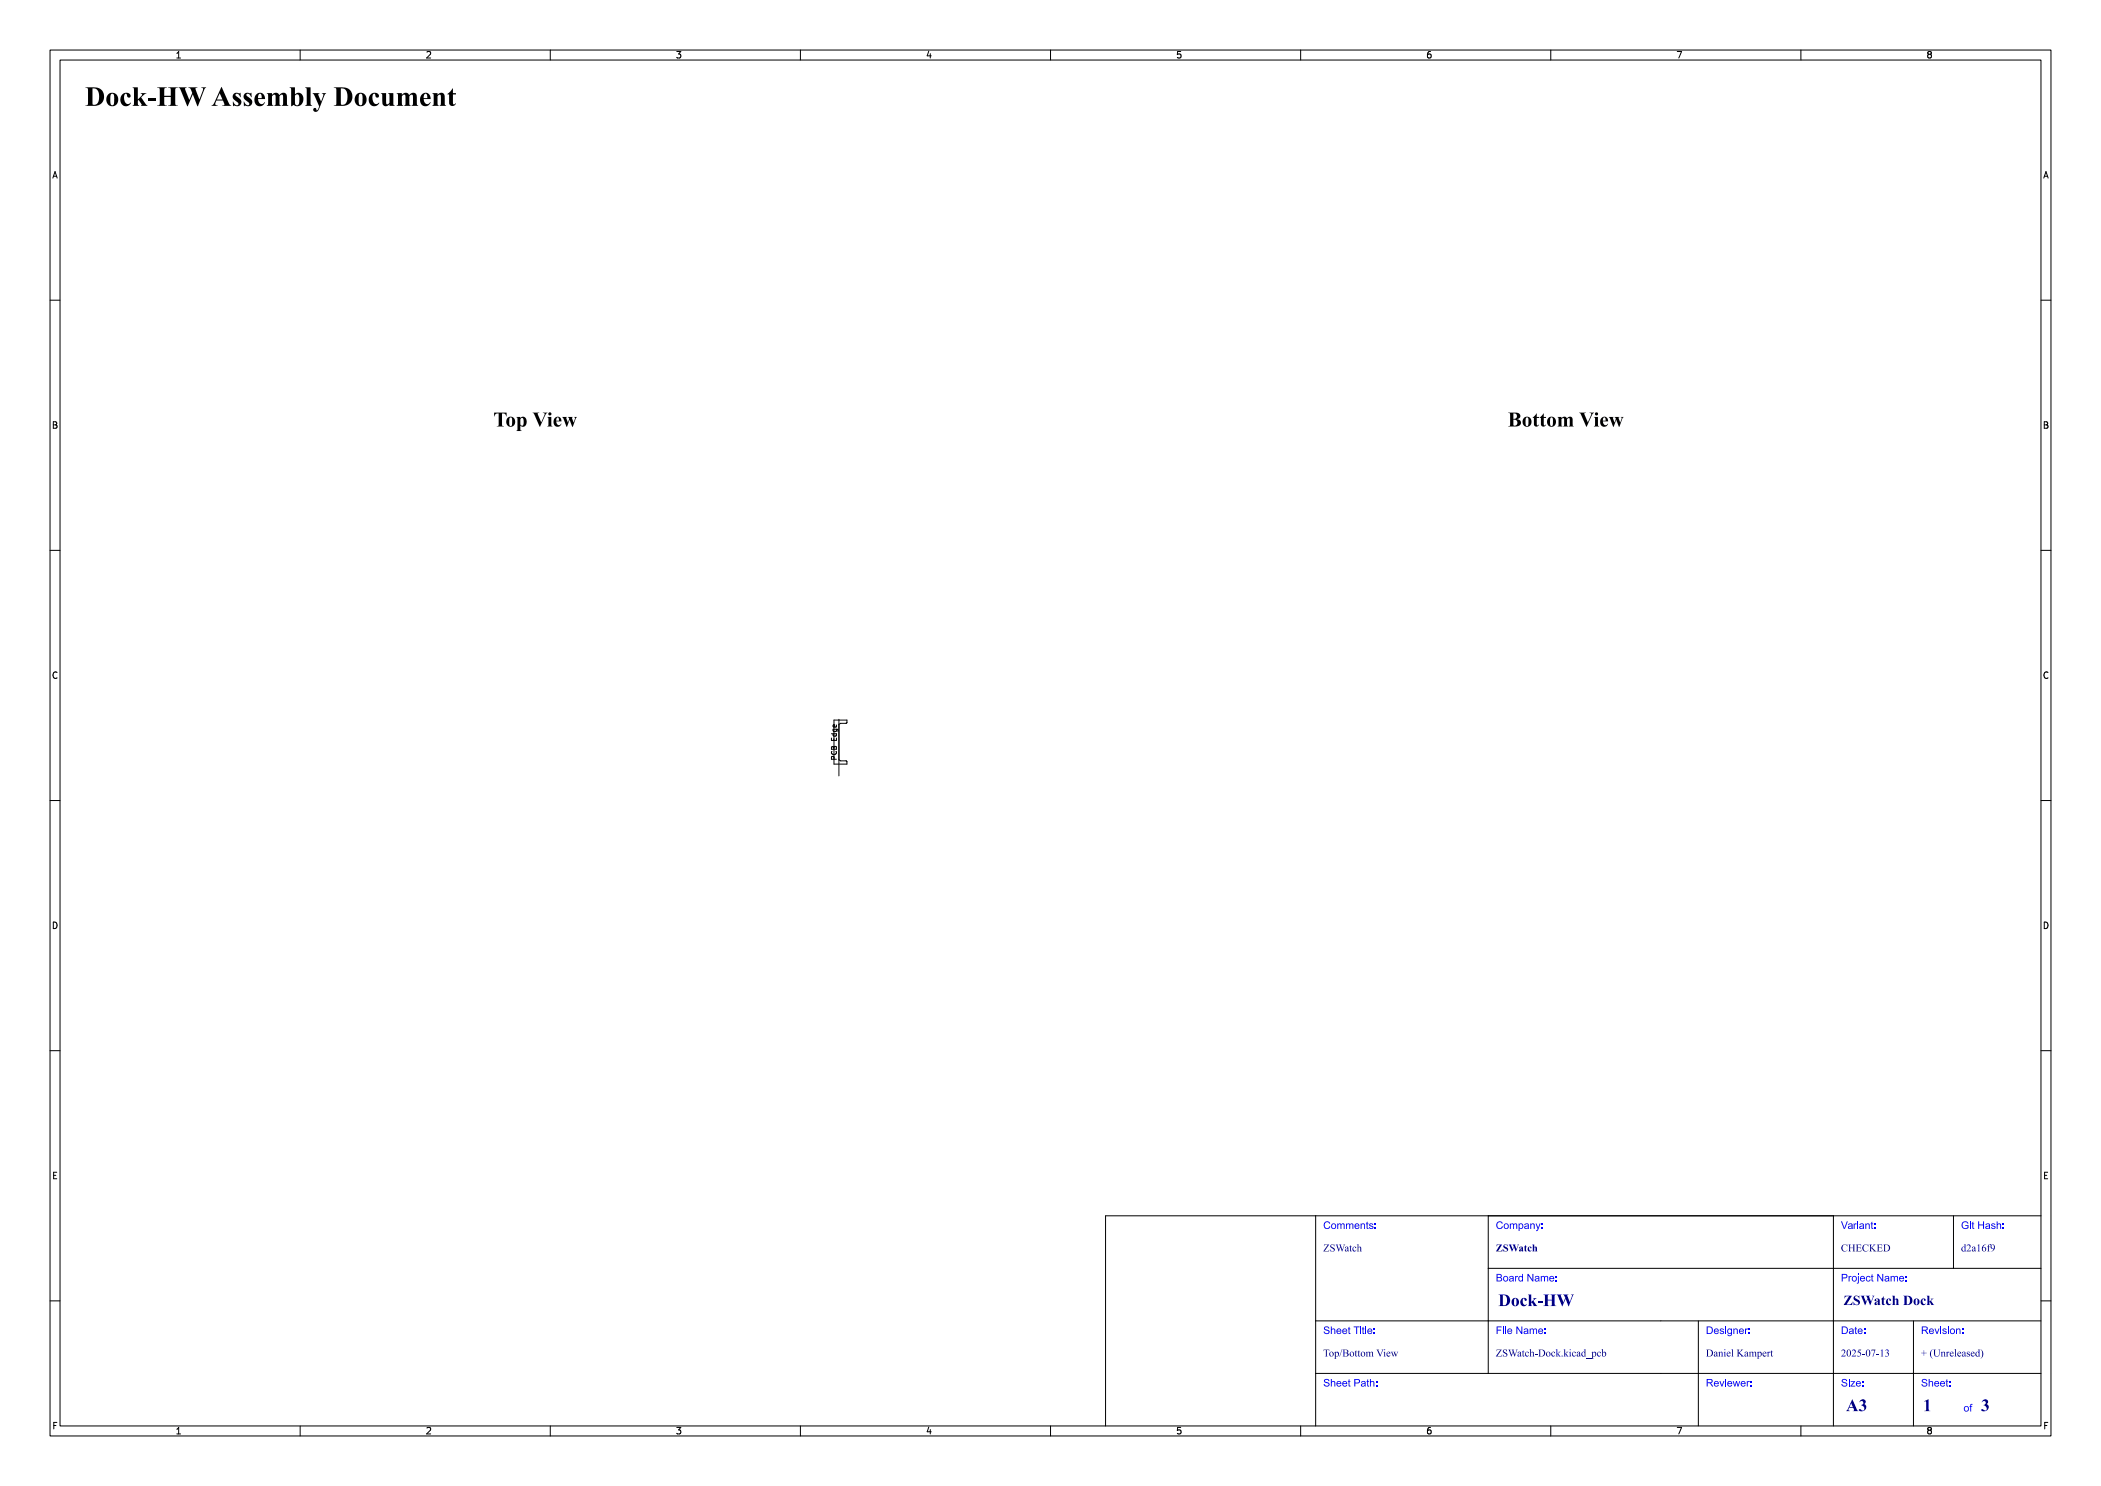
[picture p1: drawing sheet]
<svg xmlns="http://www.w3.org/2000/svg" width="420mm" height="297mm" viewBox="0 0 420 297" stroke-linecap="round" stroke-linejoin="round" font-family="sans-serif">
<defs><g id="words">
<text font-size="5.3" fill="#fff" x="17" y="21.5">Dock-HW Assembly Document</text>
<g font-size="3.3" fill="#fff">
<text x="299.5" y="261.2">Dock-HW</text>
<text x="369" y="282.2">A3</text>
<text x="384.4" y="282.3">1</text>
<text x="396" y="282.3">3</text>
</g>
<text font-size="2.7" fill="#fff" x="368.5" y="261">ZSWatch Dock</text>
<g font-size="2" fill="#fff">
<text x="264.5" y="245.8">Comments:</text>
<text x="299" y="245.8">Company:</text>
<text x="368" y="245.8">Variant:</text>
<text x="392" y="245.8">Git Hash:</text>
<text x="264.5" y="250.2">ZSWatch</text>
<text x="299" y="250.2">ZSWatch</text>
<text x="368" y="250.2">CHECKED</text>
<text x="392" y="250.2">d2a16f9</text>
<text x="299" y="256.2">Board Name:</text>
<text x="368" y="256.2">Project Name:</text>
<text x="264.5" y="266.8">Sheet Title:</text>
<text x="299" y="266.8">File Name:</text>
<text x="341" y="266.8">Designer:</text>
<text x="368" y="266.8">Date:</text>
<text x="384" y="266.8">Revision:</text>
<text x="264.5" y="271.2">Top/Bottom View</text>
<text x="299" y="271.2">ZSWatch-Dock.kicad_pcb</text>
<text x="341" y="271.2">Daniel Kampert</text>
<text x="368" y="271.2">2025-07-13</text>
<text x="384" y="271.2">+ (Unreleased)</text>
<text x="264.5" y="277.3">Sheet Path:</text>
<text x="341" y="277.2">Reviewer:</text>
<text x="368" y="277.3">Size:</text>
<text x="384" y="277.2">Sheet:</text>
<text x="392.5" y="282.3">of</text>
</g>
<g font-size="1.7" fill="#fff">
<text x="35" y="11.6">1</text>
<text x="85" y="11.6">2</text>
<text x="135" y="11.6">3</text>
<text x="185" y="11.6">4</text>
<text x="235" y="11.6">5</text>
<text x="285" y="11.6">6</text>
<text x="335" y="11.6">7</text>
<text x="385" y="11.6">8</text>
<text x="10.5" y="35.6">A</text>
<text x="408.5" y="35.6">A</text>
<text x="10.5" y="85.6">B</text>
<text x="408.5" y="85.6">B</text>
<text x="10.5" y="135.7">C</text>
<text x="408.5" y="135.7">C</text>
<text x="10.5" y="185.6">D</text>
<text x="408.5" y="185.6">D</text>
<text x="10.5" y="235.7">E</text>
<text x="408.5" y="235.7">E</text>
<text x="10.5" y="285.6">F</text>
<text x="35" y="286.7">1</text>
<text x="85" y="286.7">2</text>
<text x="135" y="286.7">3</text>
<text x="185" y="286.7">4</text>
<text x="235" y="286.7">5</text>
<text x="285" y="286.7">6</text>
<text x="335" y="286.7">7</text>
<text x="385" y="286.7">8</text>
<text x="408.5" y="285.6">F</text>
</g>
<text font-size="1.3" fill="#fff" x="167.2" y="151.5" transform="rotate(-90 167.2 151.5)">PCB Edge</text>
</g></defs>
<g fill="#000">
<path d="M98.8 82.5h2.5v.7a.76 .76 0 0 0-.9-.6v2.4l.3 .2h-1.4l.4-.2v-2.4a.75 .75 0 0 0-.9 .6z" fill-rule="evenodd"/>
<path d="M101.6 83.4a.95 .95 0 0 1 1.4 1 .95 .95 0 0 1-1.6 .6l-.2-.5h.6v.4a.26 .26 0 0 0 .3 .3 .26 .26 0 0 0 .2-.3v-1.3a.28 .28 0 0 0-.3-.2 .28 .28 0 0 0-.2 .4v.7h-.6l.1-.6z" fill-rule="evenodd"/>
<path d="M103.2 83.3h.8v.3a.73 .73 0 0 1 .9-.2 .73 .73 0 0 1 .4 .9 .77 .77 0 0 1-.3 .9 .77 .77 0 0 1-1-.1v.9l.3 .1h-1.1l.2-.2v-2.1h.6v1a.31 .31 0 0 0 .3 .3 .31 .31 0 0 0 .3-.2v-1.1a.31 .31 0 0 0-.3-.3 .31 .31 0 0 0-.3 .3h-.6v-.3z" fill-rule="evenodd"/>
<path d="M106.5 82.5h1.3l-.3 .1v.2l.7 1.6 .7-1.6-.4-.3h.9l-.3 .3-1.2 2.5-1.1-2.6z" fill-rule="evenodd"/>
<path d="M109.4 83.3h.8v1.7l.2 .2h-1l.2-.4v-1.3z" fill-rule="evenodd"/>
<path d="M110.9 83.6a.77 .77 0 0 1 .9-.2 .77 .77 0 0 1 .4 .8h-1a.54 .54 0 0 0 .3 .7 .54 .54 0 0 0 .7-.2 .82 .82 0 0 1-1.1 .5 .82 .82 0 0 1-.4-1.1h1l-.1-.6a.37 .37 0 0 0-.4 .1 .37 .37 0 0 0 0 .4h-.5z" fill-rule="evenodd"/>
<path d="M112.4 83.3h.9l-.1 .2 .3 1 .3-.8-.3-.4h1l-.2 .2 .4 1 .3-.9-.2-.3 .5 .1-.2 .2-.6 1.7h-.1l-.5-1.4-.7 1.4z" fill-rule="evenodd"/>
<path d="M301.5 82.5h1.3a.72 .72 0 0 1 .9 .2 .72 .72 0 0 1 0 .9l-.4 .2a.73 .73 0 0 1 .8 .7 .73 .73 0 0 1-.9 .7h-1.7l.3-.1 .1-.2h.6a.51 .51 0 0 0 .8 0 .51 .51 0 0 0-.1-.7l-.2-.3h-.5v1h-.6v-1.2h.6a.57 .57 0 0 0 .7-.5 .57 .57 0 0 0-.7-.6v1.1h-.6l-.1-1z" fill-rule="evenodd"/>
<path d="M304.7 83.4a.95 .95 0 0 1 1.4 1 .95 .95 0 0 1-1.5 .6l-.2-.5h.6v.4a.26 .26 0 0 0 .2 .3 .26 .26 0 0 0 .3-.3v-1.3a.28 .28 0 0 0-.3-.2 .28 .28 0 0 0-.2 .4v.7h-.6v-.6z" fill-rule="evenodd"/>
<path d="M307.1 82.6l.1 .7h.5v.2h-.5v1.4l.1 .1 .3-.2a.51 .51 0 0 1-.6 .4 .51 .51 0 0 1-.4-.6v-1.1h-.2z" fill-rule="evenodd"/>
<path d="M308.5 82.6l.1 .7h.5v.2h-.5v1.4l.1 .1 .3-.2a.51 .51 0 0 1-.6 .4 .51 .51 0 0 1-.4-.6v-1.1h-.2z" fill-rule="evenodd"/>
<path d="M309.6 83.4a.95 .95 0 0 1 1.4 1 .95 .95 0 0 1-1.5 .6l-.2-.5h.5l.1 .4a.26 .26 0 0 0 .2 .3 .26 .26 0 0 0 .3-.3v-1.3a.28 .28 0 0 0-.4-.2 .28 .28 0 0 0-.1 .4l-.1 .7h-.5v-.6z" fill-rule="evenodd"/>
<path d="M311.3 83.3h.8v.3a.6 .6 0 0 1 .6-.3 .6 .6 0 0 1 .5 .3 .61 .61 0 0 1 .8-.3 .61 .61 0 0 1 .4 .7v1l.2 .2h-1l.2-.2v-1.2a.27 .27 0 0 0-.3-.3 .27 .27 0 0 0-.2 .3v1.2l.2 .2h-1l.2-.2v-1.2a.22 .22 0 0 0-.2-.2 .22 .22 0 0 0-.3 .1l-.1 1.1 .2 .4h-1l.3-.4-.1-1.3z" fill-rule="evenodd"/>
<path d="M315.7 82.5h1.3l-.3 .1v.2l.7 1.6 .7-1.5v-.3l-.4-.1h1l-.4 .3-1.1 2.5-1.2-2.6z" fill-rule="evenodd"/>
<path d="M318.6 83.3h.8v1.7l.3 .2h-1.1l.3-.4-.1-1.3z" fill-rule="evenodd"/>
<path d="M320.1 83.6a.77 .77 0 0 1 1-.2 .77 .77 0 0 1 .4 .8h-1.1a.54 .54 0 0 0 .3 .7 .54 .54 0 0 0 .7-.2 .82 .82 0 0 1-1.1 .5 .82 .82 0 0 1-.4-1.1h1.1l-.2-.6a.37 .37 0 0 0-.4 .1 .37 .37 0 0 0 0 .4h-.5z" fill-rule="evenodd"/>
<path d="M321.6 83.3h1l-.2 .2 .3 1 .3-.8-.3-.4h1l-.2 .2 .4 1 .3-.9-.2-.3 .6 .1-.2 .2-.7 1.7h-.1l-.5-1.4-.6 1.4z" fill-rule="evenodd"/>
<circle cx="109.9" cy="82.7" r=".32"/>
<circle cx="319.1" cy="82.7" r=".32"/>
</g>
<g fill="none" stroke="#000" stroke-width=".2">
<path d="M10 10h400v277h-400zM12 12h396v273h-396zM35.3 11.6h.8M35.3 10.7l.4-.4v1.3M60 10v2M85.3 10.4l.5-.1 .3 .4-.8 .9h.8M110 10v2M135.3 10.3h.8l-.4 .5 .3 .1v.6l-.2 .1-.5-.1M160 10v2M185.7 10.2l-.4 1h.9M186 10.7v.9M210 10v2"/>
<path d="M236 10.3h-.6l-.1 .6 .2-.1 .5 .1 .1 .1-.1 .5-.2 .1-.5-.1M260 10v2M286 10.3l-.4 .1-.2 .2-.1 .7 .3 .3 .4-.1 .1-.5-.1-.1-.4-.1-.3 .2M310 10v2M335.3 10.3h.9l-.6 1.3M360 10v2M385.6 10.9l-.3 .2 .1 .4 .2 .1 .4-.1 .1-.2-.1-.3-.2-.1M385.6 10.9l-.3-.3 .3-.3h.2l.3 .2-.3 .4M385.6 10.9h.2M10.6 35.6l.4-1.3 .4 1.3M10.7 35.2h.6M408.6 35.6l.4-1.3 .4 1.3"/>
<path d="M408.7 35.2h.6M10 60h2M408 60h2M10.7 84.3h.4l.2 .2-.2 .4 .2 .1 .1 .3-.2 .3h-.5zM10.7 84.9h.4M408.6 84.3h.5l.2 .2-.2 .4 .2 .1 .1 .3-.3 .3h-.5zM408.6 84.9h.5M10 110h2M408 110h2M11.4 134.4a.62 .62 0 0 0-.9 .5 .62 .62 0 0 0 .7 .7l.2-.1M409.4 134.4a.62 .62 0 0 0-.9 .5 .62 .62 0 0 0 .6 .7l.3-.1M10 160h2"/>
<path d="M166.2 147.5v.5h1v-.5M166.2 146.7h1M166.3 149.3l.2-.1 .2 .2 .2-.2h.2l.1 .5h-1zM166.3 150.2a.44 .44 0 0 0 .4 .6 .44 .44 0 0 0 .4-.6M166.5 145.7h.8l.2 .2v.3M166.6 145.7l-.1 .3 .2 .2 .5-.1v-.4M166.6 146.7l-.1 .2 .2 .2 .5-.1v-.3M166.7 147.7v.3M166.7 149.4v.3M166.7 151.4l-.2-.2h-.2l-.1 .5h1M167.2 144.9v.3l-.1 .1h-.5v-.4l.2-.1 .1 .5M167.7 144.8l.3-.2h1.2l.1-.7h-2.6v8.8h2.6l-.1-.6h-1.2l-.3-.2"/>
<path d="M167.7 143.8v11.3M408 160h2M10.7 184.3a.66 .66 0 0 1 .7 .6 .66 .66 0 0 1-.7 .7zM408.6 184.3a.66 .66 0 0 1 .8 .6 .66 .66 0 0 1-.8 .7zM10 210h2M408 210h2M10.7 234.9h.5M11.3 234.3h-.6v1.3h.6M408.7 234.9h.4M409.3 234.3h-.6v1.3h.6M10 260h2M408 260h2"/>
<path d="M10.8 284.9h.4M11.4 284.3h-.6v1.3M35.3 285.7l.4-.4v1.3M35.3 286.6h.8M60 285v2M85.3 285.4l.5-.1 .3 .4-.8 .9h.8M110 285v2M135.3 285.3h.8l-.4 .5 .3 .1v.6l-.2 .1-.5-.1M160 285v2M185.7 285.2l-.4 1h.9M186 285.7v.9M210 285v2"/>
<path d="M236 285.3h-.6l-.1 .6 .2-.1 .5 .1 .1 .1-.1 .5-.2 .1-.5-.1M260 285v2M286 285.3l-.4 .1-.2 .2-.1 .7 .3 .3 .4-.1 .1-.5-.1-.1-.4-.1-.3 .2M310 285v2M335.3 285.3h.9l-.6 1.3M360 285v2M385.6 285.9l-.3-.3 .3-.3h.2l.3 .2-.3 .4M385.6 285.9l-.3 .2v.2l.3 .3 .4-.1 .1-.2v-.2l-.3-.2M385.6 285.9h.2M408.7 284.9h.5M409.4 284.3h-.7v1.3"/>
</g>
<path d="M384.6 280.1l.9-.4v2.1l.4 .2h-1.2l.3-.1v-1.5v-.3z" fill-rule="evenodd" fill="#00007f"/>
<g fill="#00f">
<path d="M384.3 275.7l.7-.1 .2 .4-.1 .1a.32 .32 0 0 0-.4-.4 .32 .32 0 0 0-.3 .5h.3a.5 .5 0 0 1 .6 .6 .5 .5 0 0 1-.8 .3l-.4-.3v-.2h.2a.39 .39 0 0 0 .4 .4 .39 .39 0 0 0 .4-.4l-.9-.4v-.2z" fill-rule="evenodd"/>
<path d="M385.5 275.6h.2v.6l.3-.2 .4 .2v.9h-.2v-.7a.27 .27 0 0 0-.3-.2 .27 .27 0 0 0-.2 .3v.6h-.2z" fill-rule="evenodd"/>
<path d="M386.8 276.2a.51 .51 0 0 1 .6-.1 .51 .51 0 0 1 .2 .5h-.8l.3 .4 .5-.2a.52 .52 0 0 1-.6 .3 .52 .52 0 0 1-.3-.6h.8l-.3-.3-.4 .3h-.1z" fill-rule="evenodd"/>
<path d="M388 276.2a.51 .51 0 0 1 .6-.1 .51 .51 0 0 1 .2 .5h-.8l.2 .4 .6-.2a.52 .52 0 0 1-.6 .3 .52 .52 0 0 1-.4-.6h.8l-.3-.3-.3 .3h-.2z" fill-rule="evenodd"/>
<path d="M389.1 275.8l.2-.1v.3h.1v.2h-.1v.6l.2 .3a.27 .27 0 0 1-.3 0 .27 .27 0 0 1-.1-.3v-.6h-.2z" fill-rule="evenodd"/>
<path d="M389.7 276h.2v.2h-.2z" fill-rule="evenodd"/>
<path d="M389.7 276.9h.2v.2h-.2z" fill-rule="evenodd"/>
<path d="M392.7 281.1a.54 .54 0 0 1 .9 .1 .54 .54 0 0 1-.3 .8 .54 .54 0 0 1-.7-.4h.2a.37 .37 0 0 0 .5 .4 .37 .37 0 0 0 0-.7l-.3-.1-.2 .4h-.2z" fill-rule="evenodd"/>
<path d="M393.9 280.7l.4-.1v.2l-.3 .1 .2 .3h-.2v.9h-.2v-.9h-.1z" fill-rule="evenodd"/>
</g>
<path d="M396.3 279.9a.55 .55 0 0 1 .9-.2 .55 .55 0 0 1-.1 .9 .81 .81 0 0 1 .2 1.2 .81 .81 0 0 1-1.3 0l.3-.2a.54 .54 0 0 0 .8 .2 .71 .71 0 0 0-.6-1 .41 .41 0 0 0 .5-.3 .41 .41 0 0 0-.3-.5 .41 .41 0 0 0-.5 .3z" fill-rule="evenodd" fill="#00007f"/>
<g fill="#00f">
<path d="M368.3 275.7l.7-.1 .2 .4-.1 .1a.32 .32 0 0 0-.4-.4 .32 .32 0 0 0-.3 .5h.3a.5 .5 0 0 1 .6 .6 .5 .5 0 0 1-.8 .3l-.4-.3v-.2h.2a.39 .39 0 0 0 .4 .4 .39 .39 0 0 0 .4-.4l-.9-.4v-.2z" fill-rule="evenodd"/>
<path d="M369.5 275.6h.2v.2h-.2z" fill-rule="evenodd"/>
<path d="M369.5 276h.2v1.1h-.2z" fill-rule="evenodd"/>
<path d="M369.9 276h.9l-.7 1h.8v.1h-1l.7-.9h-.7z" fill-rule="evenodd"/>
<path d="M371.1 276.2a.51 .51 0 0 1 .6-.1 .51 .51 0 0 1 .3 .5h-.8l.2 .4 .6-.2a.52 .52 0 0 1-.7 .3 .52 .52 0 0 1-.3-.6h.8l-.3-.3-.3 .3h-.2z" fill-rule="evenodd"/>
<path d="M372.3 276h.2v.2h-.2z" fill-rule="evenodd"/>
<path d="M372.3 276.9h.2v.2h-.2z" fill-rule="evenodd"/>
</g>
<g fill="#00007f">
<path d="M370.3 279.7l.9 2.1 .3 .2h-1.1l.2-.1-.1-.5h-.9l-.1 .5 .3 .1h-.8l.6-.8h.8l-.3-.7-.4 .7h-.1z" fill-rule="evenodd"/>
<path d="M371.9 279.9a.55 .55 0 0 1 .8-.2 .55 .55 0 0 1 0 .9 .81 .81 0 0 1 .1 1.2 .81 .81 0 0 1-1.2 0l.2-.2a.54 .54 0 0 0 .8 .2 .72 .72 0 0 0-.6-1 .41 .41 0 0 0 .5-.3 .41 .41 0 0 0-.3-.5 .41 .41 0 0 0-.5 .3z" fill-rule="evenodd"/>
</g>
<path d="M366.5 274.5h41.5M382.5 274.5v10.5M408 264h-41.5v21" fill="none" stroke="#000" stroke-width=".2"/>
<g fill="#00f">
<path d="M384.2 265.1h.6a.42 .42 0 0 1 .6 .4 .42 .42 0 0 1-.5 .4l.6 .7h-.3l-.4-.6h-.2h-.2v.6h-.2v-.8l.9-.1a.25 .25 0 0 0 0-.3 .25 .25 0 0 0-.3-.1h-.4v.5h-.2z" fill-rule="evenodd"/>
<path d="M385.7 265.7l.1-.1a.51 .51 0 0 1 .6 0 .51 .51 0 0 1 .2 .5h-.8l.2 .4 .6-.2a.52 .52 0 0 1-.7 .3 .52 .52 0 0 1-.3-.6h.8l-.3-.3-.3 .3h-.2z" fill-rule="evenodd"/>
<path d="M386.7 265.5h.2l.3 .9 .3-.9h.2l-.4 1.1h-.2z" fill-rule="evenodd"/>
<path d="M387.9 265.1h.2v.2h-.2z" fill-rule="evenodd"/>
<path d="M387.9 265.5h.2v1.1h-.2z" fill-rule="evenodd"/>
<path d="M388.4 265.6l.5-.1 .2 .3h-.2a.21 .21 0 0 0-.2-.2 .21 .21 0 0 0-.1 .3 .43 .43 0 0 1 .4 .1 .43 .43 0 0 1 .1 .4l-.2 .2h-.4l-.2-.3h.1a.24 .24 0 0 0 .3 .3 .24 .24 0 0 0 .2-.4 .43 .43 0 0 1-.6-.5z" fill-rule="evenodd"/>
<path d="M389.4 265.1h.2v.2h-.2z" fill-rule="evenodd"/>
<path d="M389.4 265.5h.2v1.1h-.2z" fill-rule="evenodd"/>
<path d="M390 265.6a.54 .54 0 0 1 .8 .1 .54 .54 0 0 1-.3 .8 .54 .54 0 0 1-.7-.4h.2a.37 .37 0 0 0 .5 .4 .37 .37 0 0 0 .1-.7l-.4-.1-.2 .4h-.2z" fill-rule="evenodd"/>
<path d="M391 265.5h.2v.2l.3-.2a.35 .35 0 0 1 .4 .5v.6h-.2v-.6a.27 .27 0 0 0-.3-.3 .27 .27 0 0 0-.2 .3v.6h-.2z" fill-rule="evenodd"/>
<path d="M392.2 265.5h.2v.2h-.2z" fill-rule="evenodd"/>
<path d="M392.2 266.4h.2v.2h-.2z" fill-rule="evenodd"/>
</g>
<g fill="#00007f">
<path d="M384 270.4h.5l.1-.5v.5l.5 .1h-.5l-.1 .5v-.5z" fill-rule="evenodd"/>
<path d="M386.1 269.8l.3-.1a1.42 1.42 0 0 0 0 1.9l-.5-.6a1.13 1.13 0 0 1 .2-1.2z" fill-rule="evenodd"/>
<path d="M386.4 269.7h.6l-.2 .2v.7a.41 .41 0 0 0 .4 .5 .41 .41 0 0 0 .4-.6v-.7l-.2-.1h.5l-.2 .2v.6a.55 .55 0 0 1-.6 .7 .55 .55 0 0 1-.5-.7v-.7z" fill-rule="evenodd"/>
<path d="M387.9 270.3l.4-.1v.2a.29 .29 0 0 1 .3-.2 .29 .29 0 0 1 .2 .3v.5l.2 .1h-.5l.2-.2-.1-.5-.1-.1-.2 .1v.6l.1 .1h-.4l.1-.1v-.6z" fill-rule="evenodd"/>
<path d="M389 270.3l.3-.1v.2l.2-.2h.2l-.4 .3v.5l.2 .1h-.5l.1-.1v-.6z" fill-rule="evenodd"/>
<path d="M389.9 270.3l.4-.1 .2 .2v.1h-.6l.2 .4 .3 .1 .1-.2a.41 .41 0 0 1-.6 .3 .41 .41 0 0 1-.1-.6h.5l-.2-.3-.3 .3z" fill-rule="evenodd"/>
<path d="M390.7 269.8l.3-.1v1.3l.1 .1h-.4l.1-.1v-.9v-.3z" fill-rule="evenodd"/>
<path d="M391.4 270.3l.4-.1 .2 .2 .1 .1h-.7l.2 .4 .3 .1 .1-.2a.41 .41 0 0 1-.5 .3 .41 .41 0 0 1-.2-.6h.5l-.2-.3-.3 .3z" fill-rule="evenodd"/>
<path d="M392.3 270.2l.5 .1 .1 .7 .1-.1-.1 .2-.2-.1-.2 .1h-.2l-.1-.2 .3 .1 .2-.1v-.3l-.5 .3 .5-.4-.2-.3-.2 .3z" fill-rule="evenodd"/>
<path d="M393.2 270.2h.5v.3l-.2-.3-.2 .1 .1 .2a.34 .34 0 0 1 .4 .5 .34 .34 0 0 1-.6 .1v-.3l.2 .3 .2-.2-.4-.4z" fill-rule="evenodd"/>
<path d="M394.1 270.3l.4-.1 .2 .2v.1h-.6l.1 .4 .3 .1 .2-.2a.41 .41 0 0 1-.6 .3 .41 .41 0 0 1-.1-.6h.5l-.2-.3-.3 .3z" fill-rule="evenodd"/>
<path d="M395.4 269.8l.3-.1v1.3h.2l-.6 .2-.4-.2v-.4h.2l.1 .4 .3-.1-.1-.7-.3 .1v.3h-.2v-.1a.41 .41 0 0 1 .6-.3v-.4z" fill-rule="evenodd"/>
<path d="M395.9 269.7a1.08 1.08 0 0 1 0 1.9 1.42 1.42 0 0 0 0-1.9z" fill-rule="evenodd"/>
</g>
<path d="M382.5 264v10.5" fill="none" stroke="#000" stroke-width=".2"/>
<g fill="#00f">
<path d="M368.2 265.1h.5a.75 .75 0 0 1 .7 .8 .75 .75 0 0 1-.7 .7h-.5v-.2h.5a.58 .58 0 0 0 .5-.5 .58 .58 0 0 0-.5-.6h-.3v1.1h-.2z" fill-rule="evenodd"/>
<path d="M369.7 265.6l.2-.1a.47 .47 0 0 1 .5 .1 .47 .47 0 0 1 .1 .6l.1 .4-.2-.1-.5 .1-.3-.1v-.2l.6 .2 .1-.4-.7 .2a.57 .57 0 0 1 .7-.4l-.1-.2-.6 .1z" fill-rule="evenodd"/>
<path d="M370.9 265.3l.1-.1v.3h.2v.2h-.2v.6l.2 .3a.27 .27 0 0 1-.3 0 .27 .27 0 0 1 0-.3v-.6h-.2z" fill-rule="evenodd"/>
<path d="M371.5 265.7l.1-.1a.51 .51 0 0 1 .5 0 .51 .51 0 0 1 .2 .5h-.8l.3 .4 .5-.2a.52 .52 0 0 1-.6 .3 .52 .52 0 0 1-.4-.6h.9l-.3-.3-.4 .3h-.2z" fill-rule="evenodd"/>
<path d="M372.6 265.5h.2v.2h-.2z" fill-rule="evenodd"/>
<path d="M372.6 266.4h.2v.2h-.2z" fill-rule="evenodd"/>
</g>
<path d="M408 253.5h-41.5v10.5" fill="none" stroke="#000" stroke-width=".2"/>
<g fill="#00f">
<path d="M368.2 254.6h.5a.46 .46 0 0 1 .6 .5 .46 .46 0 0 1-.6 .4h-.3v.6h-.2v-.8h.7l.2-.2-.2-.3h-.5v.5h-.2z" fill-rule="evenodd"/>
<path d="M369.5 255h.2v.2l.4-.2v.2a.24 .24 0 0 0-.3 .1 .24 .24 0 0 0-.1 .3v.5h-.2z" fill-rule="evenodd"/>
<path d="M370.3 255.1a.55 .55 0 0 1 .9 .1 .55 .55 0 0 1-.3 .8 .55 .55 0 0 1-.7-.4h.2a.37 .37 0 0 0 .5 .4 .37 .37 0 0 0 0-.7l-.3-.1-.2 .4h-.2z" fill-rule="evenodd"/>
<path d="M371.4 254.6h.2v.2h-.2z" fill-rule="evenodd"/>
<path d="M371.4 255h.2v1.2a.3 .3 0 0 1-.1 .3 .3 .3 0 0 1-.3 0l.2-.2z" fill-rule="evenodd"/>
<path d="M371.9 255.2a.51 .51 0 0 1 .7-.1 .51 .51 0 0 1 .2 .5h-.8l.2 .4 .6-.2a.52 .52 0 0 1-.6 .3 .52 .52 0 0 1-.4-.6h.8l-.3-.3-.3 .3h-.2z" fill-rule="evenodd"/>
<path d="M373.1 255.1h.6l.2 .3h-.2a.34 .34 0 0 0-.5-.2 .34 .34 0 0 0 0 .6l.3 .2 .2-.3h.2a.53 .53 0 0 1-.8 .3 .53 .53 0 0 1 0-.8z" fill-rule="evenodd"/>
<path d="M374.1 254.8l.2-.1v.3h.2v.2h-.2v.6l.2 .3a.27 .27 0 0 1-.3 0 .27 .27 0 0 1-.1-.3v-.6h-.1z" fill-rule="evenodd"/>
<path d="M375.3 254.6h.2l.8 1.2v-1.2h.2v1.5h-.2l-.8-1.2v1.2h-.2z" fill-rule="evenodd"/>
<path d="M376.9 255.1l.1-.1a.47 .47 0 0 1 .6 .1 .47 .47 0 0 1 0 .6l.1 .4-.2-.1-.5 .1-.3-.1v-.2l.6 .2 .2-.4-.8 .2a.57 .57 0 0 1 .8-.4l-.2-.2-.6 .1z" fill-rule="evenodd"/>
<path d="M377.9 255h.2v.2l.3-.2 .3 .2 .3-.2 .3 .1 .1 1h-.2l-.1-.9a.26 .26 0 0 0-.2 0 .26 .26 0 0 0-.1 .3v.6h-.2v-.8l-.4-.1-.1 .9h-.2z" fill-rule="evenodd"/>
<path d="M379.8 255.2a.51 .51 0 0 1 .6-.1 .51 .51 0 0 1 .2 .5h-.8l.3 .4 .5-.2a.52 .52 0 0 1-.6 .3 .52 .52 0 0 1-.4-.6h.8l-.3-.3-.3 .3h-.2z" fill-rule="evenodd"/>
<path d="M380.9 255h.2v.2h-.2z" fill-rule="evenodd"/>
<path d="M380.9 255.9h.2v.2h-.2z" fill-rule="evenodd"/>
</g>
<g fill="#00007f">
<path d="M368.2 269.8a.42 .42 0 0 1 .6 .1 .42 .42 0 0 1-.1 .6l-.4 .5 .7-.1-.1 .2h-.9a.88 .88 0 0 0 .6-1.2h-.2l-.3 .2z" fill-rule="evenodd"/>
<path d="M369.3 269.8l.2-.1a.7 .7 0 0 1 .5 .7 .7 .7 0 0 1-.6 .7l-.3-.5 .2-.1a.36 .36 0 0 0 0 .4 .36 .36 0 0 0 .4 .1l.1-.8-.2-.4a.42 .42 0 0 0-.3 .7l-.2-.1z" fill-rule="evenodd"/>
<path d="M370.3 269.8a.42 .42 0 0 1 .6 .1 .42 .42 0 0 1-.1 .6l-.4 .5 .7-.1-.1 .2h-.9a.88 .88 0 0 0 .6-1.2h-.2l-.3 .2z" fill-rule="evenodd"/>
<path d="M371.6 269.7h.5l-.1 .2h-.4l-.1 .2a.5 .5 0 0 1 .5 .6 .5 .5 0 0 1-.7 .3 .4 .4 0 0 0 .6-.2 .4 .4 0 0 0-.5-.5h-.1z" fill-rule="evenodd"/>
<path d="M372.3 270.6h.5v.1h-.5z" fill-rule="evenodd"/>
<path d="M373.2 269.8l.1-.1a.7 .7 0 0 1 .6 .7 .7 .7 0 0 1-.6 .7l-.3-.5 .2-.1a.36 .36 0 0 0-.1 .4 .36 .36 0 0 0 .4 .1l.2-.6-.2-.6a.42 .42 0 0 0-.3 .7l-.2-.1z" fill-rule="evenodd"/>
<path d="M374.2 269.7h.7l-.5 1.4h-.1l.4-1.2h-.5l-.1 .2z" fill-rule="evenodd"/>
<path d="M375.1 270.6h.5v.1h-.5z" fill-rule="evenodd"/>
<path d="M375.9 269.9l.4-.2v1.3l.2 .1h-.5l.1-.1v-1z" fill-rule="evenodd"/>
<path d="M377 269.8h.4a.31 .31 0 0 1 0 .5 .44 .44 0 0 1 .1 .7 .44 .44 0 0 1-.6 0 .35 .35 0 0 0 .5-.1 .35 .35 0 0 0-.3-.5 .28 .28 0 0 0 .3-.2 .28 .28 0 0 0-.2-.3 .28 .28 0 0 0-.3 .1z" fill-rule="evenodd"/>
</g>
<g fill="#00f">
<path d="M341.2 275.6h.6a.42 .42 0 0 1 .6 .4 .42 .42 0 0 1-.5 .4l.6 .7h-.3a.74 .74 0 0 0-.8-.6v.6h-.2v-.8l.9-.1a.25 .25 0 0 0 0-.3 .25 .25 0 0 0-.3-.1h-.4v.5h-.2z" fill-rule="evenodd"/>
<path d="M342.7 276.2a.51 .51 0 0 1 .6-.1 .51 .51 0 0 1 .3 .5h-.8l.2 .4 .6-.2a.52 .52 0 0 1-.7 .3 .52 .52 0 0 1-.3-.6h.8l-.3-.3-.3 .3h-.2z" fill-rule="evenodd"/>
<path d="M343.7 276h.2l.3 .9 .3-.9h.2l-.4 1.1h-.2z" fill-rule="evenodd"/>
<path d="M344.9 275.6h.2v.2h-.2z" fill-rule="evenodd"/>
<path d="M344.9 276h.2v1.1h-.2z" fill-rule="evenodd"/>
<path d="M345.4 276.2a.51 .51 0 0 1 .6-.1 .51 .51 0 0 1 .3 .5h-.8l.2 .4 .6-.2a.52 .52 0 0 1-.7 .3 .52 .52 0 0 1-.3-.6h.8l-.3-.3-.3 .3h-.2z" fill-rule="evenodd"/>
<path d="M346.4 276h.2l.2 .9 .2-.9h.2l.2 .9 .3-.9h.2l-.4 1.1h-.2l-.2-.8-.2 .8h-.2z" fill-rule="evenodd"/>
<path d="M348.1 276.2a.51 .51 0 0 1 .6-.1 .51 .51 0 0 1 .3 .5h-.9l.3 .4 .6-.2a.52 .52 0 0 1-.7 .3 .52 .52 0 0 1-.3-.6h.8l-.3-.3-.3 .3h-.2z" fill-rule="evenodd"/>
<path d="M349.2 276h.1v.2l.4-.2v.2a.24 .24 0 0 0-.3 .1 .24 .24 0 0 0 0 .3v.5h-.2z" fill-rule="evenodd"/>
<path d="M349.9 276h.2v.2h-.2z" fill-rule="evenodd"/>
<path d="M349.9 276.9h.2v.2h-.2z" fill-rule="evenodd"/>
</g>
<path d="M332 274.5h34.5M339.5 274.5v10.5" fill="none" stroke="#000" stroke-width=".2"/>
<g fill="#00f">
<path d="M341.2 265.1h.5a.75 .75 0 0 1 .7 .8 .75 .75 0 0 1-.7 .7h-.5v-.2h.5a.58 .58 0 0 0 .5-.5 .58 .58 0 0 0-.5-.6h-.3v1.1h-.2z" fill-rule="evenodd"/>
<path d="M342.7 265.7l.1-.1a.51 .51 0 0 1 .6 0 .51 .51 0 0 1 .2 .5h-.8l.2 .4 .6-.2a.52 .52 0 0 1-.7 .3 .52 .52 0 0 1-.3-.6h.8l-.3-.3-.3 .3h-.2z" fill-rule="evenodd"/>
<path d="M343.8 265.6l.6-.1 .2 .3h-.2a.21 .21 0 0 0-.2-.2 .21 .21 0 0 0-.2 .3 .43 .43 0 0 1 .5 .1 .43 .43 0 0 1 .1 .4l-.2 .2h-.4l-.3-.3h.2a.24 .24 0 0 0 .3 .3 .24 .24 0 0 0 .2-.4 .43 .43 0 0 1-.6-.5z" fill-rule="evenodd"/>
<path d="M344.9 265.1h.2v.2h-.2z" fill-rule="evenodd"/>
<path d="M344.9 265.5h.2v1.1h-.2z" fill-rule="evenodd"/>
<path d="M345.4 265.6l.3-.1 .4 .2v-.2h.1v1a.48 .48 0 0 1-.3 .5 .48 .48 0 0 1-.6-.3l.5 .2 .2-.1v-.3a.47 .47 0 0 1-.5 0 .47 .47 0 0 1-.2-.4h.2a.34 .34 0 0 0 .4 .3 .34 .34 0 0 0 .1-.5 .3 .3 0 0 0-.3-.2 .3 .3 0 0 0-.2 .4h-.2z" fill-rule="evenodd"/>
<path d="M346.5 265.5h.2v.2l.3-.2a.35 .35 0 0 1 .4 .5v.6h-.2v-.6a.27 .27 0 0 0-.3-.3 .27 .27 0 0 0-.2 .3v.6h-.2z" fill-rule="evenodd"/>
<path d="M347.7 265.7l.1-.1a.51 .51 0 0 1 .6 0 .51 .51 0 0 1 .2 .5h-.8l.2 .4 .6-.2a.52 .52 0 0 1-.6 .3 .52 .52 0 0 1-.4-.6h.8l-.3-.3-.3 .3h-.2z" fill-rule="evenodd"/>
<path d="M348.8 265.5h.2v.2l.4-.2v.2a.24 .24 0 0 0-.3 .1 .24 .24 0 0 0-.1 .3v.5h-.2z" fill-rule="evenodd"/>
<path d="M349.6 265.5h.2v.2h-.2z" fill-rule="evenodd"/>
<path d="M349.6 266.4h.2v.2h-.2z" fill-rule="evenodd"/>
</g>
<path d="M332 264h34.5M339.5 264v10.5" fill="none" stroke="#000" stroke-width=".2"/>
<g fill="#00007f">
<path d="M341 269.7h.6a.7 .7 0 0 1 .8 .7 .7 .7 0 0 1-.7 .7h-.7l.2-.1v-1.2h.2v1.2a.65 .65 0 0 0 .8-.7 .65 .65 0 0 0-1-.5z" fill-rule="evenodd"/>
<path d="M342.7 270.2l.5 .1 .1 .7 .1-.1-.1 .2-.7-.1v-.1l.3 .1 .2-.1v-.3l-.5 .3 .5-.4-.2-.3-.3 .3z" fill-rule="evenodd"/>
<path d="M343.5 270.3l.3-.1v.2a.29 .29 0 0 1 .3-.2 .29 .29 0 0 1 .2 .3v.5l.2 .1h-.5l.2-.2v-.5l-.2-.1-.2 .1v.6l.1 .1h-.4l.1-.1v-.6z" fill-rule="evenodd"/>
<path d="M344.6 270.3l.3-.1v.8l.1 .1h-.4l.1-.1v-.5z" fill-rule="evenodd"/>
<path d="M345.3 270.3l.4-.1 .2 .2 .1 .1h-.7l.2 .4 .3 .1 .1-.2a.41 .41 0 0 1-.5 .3 .41 .41 0 0 1-.2-.6h.5l-.2-.3-.3 .3z" fill-rule="evenodd"/>
<path d="M346.1 269.8l.3-.1v1.3l.2 .1h-.5l.1-.1v-1.1z" fill-rule="evenodd"/>
<path d="M347.2 269.7h.5l-.1 .1-.1 .6 .6-.5-.1-.2h.5l-.8 .7 1 .7h-.7l.1-.1-.6-.6 .1 .6 .1 .1h-.5l.2-.2-.1-1z" fill-rule="evenodd"/>
<path d="M348.8 270.2l.6 .1v.7l.2-.1-.2 .2-.7-.1v-.1l.3 .1 .2-.1v-.3l-.5 .3 .5-.4-.1-.3-.3 .3z" fill-rule="evenodd"/>
<path d="M349.6 270.3l.3-.1v.2l.3-.2 .3 .2a.3 .3 0 0 1 .3-.2 .3 .3 0 0 1 .2 .3l.1 .5 .1 .1h-.5l.2-.1v-.5a.2 .2 0 0 0-.2-.2 .2 .2 0 0 0-.2 .2v.5l.1 .1h-.4l.1-.1v-.5l-.1-.2-.3 .1v.6l.2 .1h-.5l.1-.1v-.5z" fill-rule="evenodd"/>
<path d="M351.2 270.3l.3-.1v.2a.39 .39 0 0 1 .6-.1 .39 .39 0 0 1 0 .5l-.2 .3h-.4v.4l.2 .1h-.5l.2-.2v-1h.1l.1 .6a.33 .33 0 0 0 .4-.3 .33 .33 0 0 0-.4-.3h-.2z" fill-rule="evenodd"/>
<path d="M352.4 270.3l.4-.1 .3 .2v.1h-.6l.1 .4 .3 .1 .2-.2a.41 .41 0 0 1-.6 .3 .41 .41 0 0 1-.1-.6h.5l-.2-.3-.3 .3z" fill-rule="evenodd"/>
<path d="M353.2 270.3l.3-.1v.2l.2-.2h.2l-.4 .3v.5l.2 .1h-.5l.1-.1 .1-.5z" fill-rule="evenodd"/>
<path d="M354.2 269.9v.3h.2h-.2v.7h.3l-.3 .2-.1-.1-.1-.8h-.1z" fill-rule="evenodd"/>
<circle cx="344.8" cy="269.8" r=".1"/>
</g>
<path d="M332 264h-34.5v10.5h34.5" fill="none" stroke="#000" stroke-width=".2"/>
<g fill="#00007f">
<path d="M299.2 269.7h1l-.9 1.3h.7l.2-.3v.4h-1.2l.9-1.3h-.6l-.2 .3z" fill-rule="evenodd"/>
<path d="M300.5 269.8l.7-.1v.5a.29 .29 0 0 0-.3-.4 .29 .29 0 0 0-.2 .4h.1a.49 .49 0 0 1 .5 .3 .49 .49 0 0 1-.2 .6l-.7 .1 .1-.5a.33 .33 0 0 0 .3 .4 .33 .33 0 0 0 .3-.4l-.1-.1a.51 .51 0 0 1-.5-.2 .51 .51 0 0 1 0-.6z" fill-rule="evenodd"/>
<path d="M301.5 269.7h.5l-.1 .2 .3 .9 .2-.7-.3-.4h.6l-.2 .2 .3 .9 .3-.9-.1-.2h.4l-.6 1.5-.3-.9-.4 .9z" fill-rule="evenodd"/>
<path d="M303.5 270.2l.5 .1v.7l.2-.1-.1 .2-.7-.1-.1-.1 .4 .1 .2-.1v-.3l-.6 .3 .6-.4-.2-.3-.3 .3z" fill-rule="evenodd"/>
<path d="M304.5 269.9v.3h.3h-.3v.7h.3l-.3 .2-.1-.1v-.8h-.2z" fill-rule="evenodd"/>
<path d="M305 270.3l.4-.1 .2 .1-.1 .2a.28 .28 0 0 0-.4-.3 .28 .28 0 0 0-.1 .5l.3 .3 .3-.2a.43 .43 0 0 1-.6 .3 .43 .43 0 0 1-.1-.7z" fill-rule="evenodd"/>
<path d="M305.7 269.8l.3-.1v.7l.3-.2h.2l.1 .8 .1 .1h-.4l.1-.2v-.5l-.1-.1-.3 .1 .1 .6 .1 .1h-.5l.2-.1v-.9z" fill-rule="evenodd"/>
<path d="M306.8 270.6h.6v.1h-.6z" fill-rule="evenodd"/>
<path d="M307.5 269.7h.6a.7 .7 0 0 1 .8 .7 .7 .7 0 0 1-.8 .7h-.6l.2-.1v-1.2h.2v1.2a.65 .65 0 0 0 .7-.7 .65 .65 0 0 0-.9-.5z" fill-rule="evenodd"/>
<path d="M309.2 270.3a.46 .46 0 0 1 .7 .1 .46 .46 0 0 1-.3 .7 .46 .46 0 0 1-.6-.5h.2a.34 .34 0 0 0 .1 .4 .34 .34 0 0 0 .5-.1 .34 .34 0 0 0-.1-.4l-.2-.3-.3 .4h-.2z" fill-rule="evenodd"/>
<path d="M310.2 270.3l.4-.1 .2 .1v.2a.28 .28 0 0 0-.4-.3 .28 .28 0 0 0-.1 .5l.2 .3 .4-.2a.43 .43 0 0 1-.7 .3 .43 .43 0 0 1 0-.7z" fill-rule="evenodd"/>
<path d="M311 269.8l.3-.1v.9l.3-.3v-.1h.4l-.5 .3 .5 .6h-.4l-.3-.5v.4l.1 .1h-.4l.1-.2v-1z" fill-rule="evenodd"/>
<path d="M312.5 269.8l.4-.1v.9l.3-.3-.1-.1h.4l-.5 .3 .6 .6h-.5l-.2-.5v.4l.1 .1h-.5l.2-.2v-1z" fill-rule="evenodd"/>
<path d="M313.6 270.3l.4-.1v.8l.1 .1h-.4l.1-.1v-.5z" fill-rule="evenodd"/>
<path d="M314.4 270.3l.4-.1 .2 .1-.1 .2a.28 .28 0 0 0-.4-.3 .28 .28 0 0 0-.1 .5l.2 .3 .4-.2a.43 .43 0 0 1-.6 .3 .43 .43 0 0 1-.1-.7z" fill-rule="evenodd"/>
<path d="M315.3 270.2l.5 .1 .1 .7 .1-.1-.1 .2-.7-.1v-.1l.3 .1 .2-.1v-.3l-.5 .3 .5-.4-.2-.3-.3 .3z" fill-rule="evenodd"/>
<path d="M316.6 269.8l.3-.1v1.3h.2l-.6 .2-.3-.2-.1-.4h.2l.2 .4 .3-.1-.2-.7-.2 .1-.1 .3h-.2v-.1a.41 .41 0 0 1 .7-.3l-.1-.4z" fill-rule="evenodd"/>
<path d="M317.1 271.5l1 .1z" fill-rule="evenodd"/>
<path d="M318.1 270.3l.3-.1v.2a.39 .39 0 0 1 .6-.1 .39 .39 0 0 1 .1 .5l-.3 .3h-.4l.1 .4 .1 .1h-.5l.2-.2v-1h.1l.1 .6a.33 .33 0 0 0 .4-.3 .33 .33 0 0 0-.4-.3h-.2z" fill-rule="evenodd"/>
<path d="M319.4 270.3l.4-.1 .2 .1-.1 .2a.28 .28 0 0 0-.4-.3 .28 .28 0 0 0-.1 .5l.2 .3 .4-.2a.43 .43 0 0 1-.6 .3 .43 .43 0 0 1-.1-.7z" fill-rule="evenodd"/>
<path d="M320.1 269.8l.3-.1v.6a.45 .45 0 0 1 .7 .3 .45 .45 0 0 1-.5 .6l-.3-.2v-.6h.1v.6a.32 .32 0 0 0 .5-.3 .32 .32 0 0 0-.5-.3h-.1v-.5z" fill-rule="evenodd"/>
<circle cx="312.3" cy="271" r=".11"/>
<circle cx="313.9" cy="269.8" r=".1"/>
</g>
<path d="M366.5 253.5h-69v10.5" fill="none" stroke="#000" stroke-width=".2"/>
<g fill="#00f">
<path d="M299.2 254.6l.9 .1 .1 .3-.2 .3a.42 .42 0 0 1 .3 .6 .42 .42 0 0 1-.6 .2h-.5v-.2l.9-.1-.1-.3-.6-.1v.5h-.2v-.7h.5a.24 .24 0 0 0 .3-.1 .24 .24 0 0 0-.2-.3h-.4v.4h-.2z" fill-rule="evenodd"/>
<path d="M300.6 255.1a.55 .55 0 0 1 .9 .1 .55 .55 0 0 1-.3 .8 .55 .55 0 0 1-.7-.4h.2a.37 .37 0 0 0 .5 .4 .37 .37 0 0 0 0-.7l-.3-.1-.2 .4h-.2z" fill-rule="evenodd"/>
<path d="M301.8 255.2l.1-.2a.47 .47 0 0 1 .6 .1 .47 .47 0 0 1 .1 .6v.4l-.2-.1-.5 .1-.2-.1-.1-.2 .6 .2 .2-.4-.8 .2a.57 .57 0 0 1 .8-.4l-.2-.2-.5 .1z" fill-rule="evenodd"/>
<path d="M302.9 255h.1v.2l.4-.2v.2a.25 .25 0 0 0-.3 .1 .25 .25 0 0 0 0 .3v.5h-.2z" fill-rule="evenodd"/>
<path d="M303.7 255.1l.3-.1 .3 .2v-.6h.1v1.5h-.1v-.1l-.2 .1h-.4l-.2-.4 .2-.1a.34 .34 0 0 0 .4 .4 .34 .34 0 0 0 .2-.6l-.4-.2-.2 .4h-.2z" fill-rule="evenodd"/>
<path d="M305.3 254.6h.2l.8 1.2v-1.2h.2v1.5h-.2l-.8-1.2v1.2h-.2z" fill-rule="evenodd"/>
<path d="M306.9 255.2l.1-.2a.47 .47 0 0 1 .6 .1 .47 .47 0 0 1 .1 .6l.1 .4-.3-.1-.4 .1-.3-.1v-.2l.6 .2 .1-.4-.7 .2a.57 .57 0 0 1 .7-.4l-.1-.2-.6 .1z" fill-rule="evenodd"/>
<path d="M308 255h.2v.2l.2-.2 .4 .2 .3-.2 .2 .1 .2 1h-.2l-.1-.9a.26 .26 0 0 0-.3 0 .26 .26 0 0 0-.1 .3v.6h-.2v-.8l-.3-.1-.1 .9h-.2z" fill-rule="evenodd"/>
<path d="M309.8 255.2a.51 .51 0 0 1 .6-.1 .51 .51 0 0 1 .3 .5h-.8l.2 .4 .6-.2a.52 .52 0 0 1-.7 .3 .52 .52 0 0 1-.3-.6h.8l-.3-.3-.3 .3h-.2z" fill-rule="evenodd"/>
<path d="M311 255h.2v.2h-.2z" fill-rule="evenodd"/>
<path d="M311 255.9h.2v.2h-.2z" fill-rule="evenodd"/>
<path d="M368 244.1h.2l.5 1.4 .5-1.4h.2l-.6 1.5h-.2z" fill-rule="evenodd"/>
<path d="M369.6 244.6l.1-.1a.47 .47 0 0 1 .5 .1 .47 .47 0 0 1 .1 .6l.1 .4-.2-.1-.5 .1-.3-.1v-.2l.6 .2 .2-.4-.8 .2a.57 .57 0 0 1 .8-.4l-.2-.2-.6 .1z" fill-rule="evenodd"/>
<path d="M370.5 244.5h.2v.2l.4-.2v.2a.25 .25 0 0 0-.3 .1 .25 .25 0 0 0-.1 .3v.5h-.2z" fill-rule="evenodd"/>
<path d="M371.2 244.1h.2v.2h-.2z" fill-rule="evenodd"/>
<path d="M371.2 244.5h.2v1.1h-.2z" fill-rule="evenodd"/>
<path d="M371.8 244.6l.1-.1a.47 .47 0 0 1 .6 .1 .47 .47 0 0 1 .1 .6l.1 .4-.3-.1-.5 .1-.2-.1v-.2l.6 .2 .1-.4-.7 .2a.57 .57 0 0 1 .7-.4l-.2-.2-.5 .1z" fill-rule="evenodd"/>
<path d="M372.9 244.5h.1v.2l.4-.2a.35 .35 0 0 1 .4 .5v.6h-.2v-.6a.27 .27 0 0 0-.3-.3 .27 .27 0 0 0-.2 .3v.6h-.2z" fill-rule="evenodd"/>
<path d="M374.1 244.3l.2-.1v.3h.2v.2h-.2v.6l.2 .3a.27 .27 0 0 1-.3 0 .27 .27 0 0 1-.1-.3v-.6h-.2z" fill-rule="evenodd"/>
<path d="M374.7 244.5h.2v.2h-.2z" fill-rule="evenodd"/>
<path d="M374.7 245.4h.2v.2h-.2z" fill-rule="evenodd"/>
</g>
<path d="M408 243h-41.5v10.5" fill="none" stroke="#000" stroke-width=".2"/>
<g fill="#00007f">
<path d="M368.3 248.9l1-.2v.5a.53 .53 0 0 0-.7-.4 .53 .53 0 0 0-.3 .8l.1 .3 .3 .2 .4-.1 .2-.2a.6 .6 0 0 1-1 .2 .78 .78 0 0 1 0-1.1z" fill-rule="evenodd"/>
<path d="M369.4 248.7h.6l-.2 .1v.6h.7v-.6l-.2-.1h.6l-.2 .3v1l.2 .1h-.6l.2-.1v-.5h-.7v.5l.2 .1h-.6l.2-.2v-1z" fill-rule="evenodd"/>
<path d="M371 248.7h1v.3l-.1-.2h-.5v.6l.4-.1 .1-.1v.4l-.1-.1-.4-.1v.6a.51 .51 0 0 0 .7-.2l-.1 .3h-1l.2-.2v-1z" fill-rule="evenodd"/>
<path d="M372.5 248.9l1-.2v.5a.53 .53 0 0 0-.7-.4 .53 .53 0 0 0-.3 .8l.1 .3 .3 .2 .4-.1 .2-.2a.6 .6 0 0 1-1 .2 .78 .78 0 0 1 0-1.1z" fill-rule="evenodd"/>
<path d="M373.6 248.7h.6l-.2 .1v.6l.5-.5-.1-.2h.5l-.7 .7 .9 .7h-.6l.1-.1-.6-.6v.6l.2 .1h-.6l.2-.2v-1z" fill-rule="evenodd"/>
<path d="M375.2 248.7h1v.3l-.1-.2h-.6v.6l.5-.1 .1-.1v.4l-.1-.1-.5-.1 .1 .6a.51 .51 0 0 0 .7-.2l-.1 .3h-1l.2-.2-.1-1z" fill-rule="evenodd"/>
<path d="M376.4 248.7h.6a.7 .7 0 0 1 .8 .7 .7 .7 0 0 1-.7 .7h-.7l.2-.1v-1.2h.2v1.2a.65 .65 0 0 0 .8-.7 .65 .65 0 0 0-1-.5z" fill-rule="evenodd"/>
</g>
<path d="M366.5 243h-69v10.5" fill="none" stroke="#000" stroke-width=".2"/>
<g fill="#00f">
<path d="M299.3 244.3l.7-.2 .4 .3-.2 .2a.53 .53 0 0 0-.8-.2 .53 .53 0 0 0 0 .8l.4 .3 .3-.1 .1-.3h.2a.74 .74 0 0 1-1.1 .4 .74 .74 0 0 1 0-1.2z" fill-rule="evenodd"/>
<path d="M300.8 244.6a.54 .54 0 0 1 .8 .1 .54 .54 0 0 1-.3 .8 .54 .54 0 0 1-.7-.4h.2a.37 .37 0 0 0 .5 .4 .37 .37 0 0 0 .1-.7l-.4-.1-.2 .4h-.2z" fill-rule="evenodd"/>
<path d="M301.8 244.5h.2v.2l.4-.2 .2 .2 .3-.2 .3 .1 .1 1h-.2l-.1-.9a.26 .26 0 0 0-.3 0 .26 .26 0 0 0 0 .3v.6h-.2l-.1-.8-.3-.1-.1 .9h-.2z" fill-rule="evenodd"/>
<path d="M303.6 244.5h.1v.2a.5 .5 0 0 1 .8 .4 .5 .5 0 0 1-.7 .4v.5h-.2v-.9h.1a.33 .33 0 0 0 .4 .4 .33 .33 0 0 0 .2-.5l-.1-.3h-.2l-.3 .4h-.1z" fill-rule="evenodd"/>
<path d="M304.8 244.6l.1-.1a.47 .47 0 0 1 .6 .1 .47 .47 0 0 1 .1 .6l.1 .4-.3-.1-.4 .1-.3-.1v-.2l.6 .2 .1-.4-.7 .2a.57 .57 0 0 1 .7-.4l-.1-.2-.6 .1z" fill-rule="evenodd"/>
<path d="M305.9 244.5h.2v.2l.3-.2a.35 .35 0 0 1 .4 .5v.6h-.2v-.6a.27 .27 0 0 0-.3-.3 .27 .27 0 0 0-.2 .3v.6h-.2z" fill-rule="evenodd"/>
<path d="M307 244.5h.2l.3 .9 .3-.9h.2l-.6 1.4-.2 .2-.1-.1-.1-.1 .3-.1 .1-.2z" fill-rule="evenodd"/>
<path d="M308.2 244.5h.2v.2h-.2z" fill-rule="evenodd"/>
<path d="M308.2 245.4h.2v.2h-.2z" fill-rule="evenodd"/>
</g>
<g fill="#00007f">
<path d="M299.2 248.7h1.1l-.8 1.3a.68 .68 0 0 0 .9-.4l-.1 .5h-1.3l.9-1.3a.54 .54 0 0 0-.8 .3z" fill-rule="evenodd"/>
<path d="M300.6 248.8l.8-.1v.5l-.4-.4-.3 .2 .2 .2a.52 .52 0 0 1 .5 .7 .52 .52 0 0 1-.8 .2l-.1 .1v-.6a.35 .35 0 0 0 .3 .5 .35 .35 0 0 0 .4-.3l-.6-.5z" fill-rule="evenodd"/>
<path d="M301.6 248.7h.6l-.1 .2 .3 .8 .2-.5-.3-.5h.7l-.2 .1 .3 .8 .3-.7-.1-.2 .3 .1-.6 1.4-.4-.9-.4 .9z" fill-rule="evenodd"/>
<path d="M303.7 249.3l.4-.2 .3 .1v.8h.2l-.1 .1-.4-.1-.2 .1-.2-.1v-.1h.4v-.3l-.2 .3h-.2l.4-.4v-.2h-.2a.15 .15 0 0 1 0 .2 .15 .15 0 0 1-.2 0 .15 .15 0 0 1 0-.2z" fill-rule="evenodd"/>
<path d="M305 248.8v.4h.3l-.3 .1 .1 .7 .2-.1-.3 .2-.2-.1v-.7l-.2-.1z" fill-rule="evenodd"/>
<path d="M305.5 249.3l.5-.1 .1 .3h-.2l-.1-.3a.37 .37 0 0 0-.1 .5 .37 .37 0 0 0 .5 .2 .47 .47 0 0 1-.8 .1 .47 .47 0 0 1 .1-.7z" fill-rule="evenodd"/>
<path d="M306.3 248.7h.4v.6l.2-.2a.29 .29 0 0 1 .3 .4l.1 .6h-.4v-.8l-.2 .1 .1 .7h-.5l.1-.2z" fill-rule="evenodd"/>
<path d="M368.7 259h1.5l-1.1 1.7a.91 .91 0 0 0 1.2-.5l-.1 .6h-1.7l1.1-1.7a.73 .73 0 0 0-.9 .4z" fill-rule="evenodd"/>
<path d="M370.7 259.1l.4-.2 .4 .2 .2-.2-.1 .7a.41 .41 0 0 0-.3-.6 .41 .41 0 0 0-.5 .4l.2 .1a.82 .82 0 0 1 .8 1l-.4 .3h-.7l-.2 .1 .1-.7a.48 .48 0 0 0 .3 .5 .48 .48 0 0 0 .6-.3l-.2-.2a.72 .72 0 0 1-.7-1z" fill-rule="evenodd"/>
<path d="M371.9 259h.8l-.1 .2 .4 1 .3-.7-.4-.5h.9l-.2 .1 .4 1.1 .4-1-.2-.2h.5l-.8 1.9-.5-1.2-.6 1.2z" fill-rule="evenodd"/>
<path d="M374.8 259.7l.2-.1a.47 .47 0 0 1 .5-.1 .47 .47 0 0 1 .2 .5l.1 .6h.1l-.4 .2a.35 .35 0 0 0-.6 0l-.2-.1v-.2h.7v-.4l-.3 .4h-.4l.7-.5-.1-.3h-.3a.2 .2 0 0 1 .1 .3 .2 .2 0 0 1-.3 0 .2 .2 0 0 1 0-.3z" fill-rule="evenodd"/>
<path d="M376.5 259.1l.1 .5h.3v.1h-.3v.9h.3l-.1 .2a.35 .35 0 0 1-.5 0 .35 .35 0 0 1-.1-.4v-.7l-.2-.1z" fill-rule="evenodd"/>
<path d="M377.2 259.7a.4 .4 0 0 1 .5-.2 .4 .4 0 0 1 .2 .5h-.2l-.1-.4a.5 .5 0 0 0-.2 .6 .5 .5 0 0 0 .6 .4v-.1a.58 .58 0 0 1-.8 .2 .58 .58 0 0 1-.1-.8z" fill-rule="evenodd"/>
<path d="M378.2 259h.6v.7a.4 .4 0 0 1 .5-.2 .4 .4 0 0 1 .2 .6v.6l.1 .1h-.6l.1-.2-.1-.9-.2 .2 .1 .9h-.7l.2-.2v-1.5z" fill-rule="evenodd"/>
<path d="M380.4 259h.9a.93 .93 0 0 1 1 .9 .93 .93 0 0 1-1 .9h-.9l.3-.1v-.2h.4l.1 .2a.57 .57 0 0 0 .6-.8 .64 .64 0 0 0-.7-.8v1.4h-.4v-1.3z" fill-rule="evenodd"/>
<path d="M382.8 259.6a.62 .62 0 0 1 .8 .2 .62 .62 0 0 1-.2 .9 .62 .62 0 0 1-.8-.2l-.1-.2h.4v.3a.18 .18 0 0 0 .2 .2 .18 .18 0 0 0 .2-.2v-.8a.19 .19 0 0 0-.3-.2 .19 .19 0 0 0-.1 .3v.4h-.4z" fill-rule="evenodd"/>
<path d="M384.1 259.7a.4 .4 0 0 1 .5-.2 .4 .4 0 0 1 .3 .5h-.2l-.2-.4a.5 .5 0 0 0-.2 .6 .5 .5 0 0 0 .6 .4v-.1a.58 .58 0 0 1-.8 .2 .58 .58 0 0 1-.1-.8z" fill-rule="evenodd"/>
<path d="M385.1 259h.6v1.2l.4-.5-.1-.1h.5l-.5 .4 .6 .8h-.6l.1-.1-.3-.5-.1 .5 .1 .1h-.7l.2-.2v-1.5z" fill-rule="evenodd"/>
<path d="M299.5 258.7h1.1a1.17 1.17 0 0 1 1.3 1.2 1.17 1.17 0 0 1-1.3 1.1h-1.1l.3-.1 .1-.2h.5v.1a.53 .53 0 0 0 .7 0 .53 .53 0 0 0 .1-.6 .93 .93 0 0 0-.8-1.4v1.9h-.5v-1.7z" fill-rule="evenodd"/>
<path d="M302.5 259.5a.79 .79 0 0 1 1.1 .8 .79 .79 0 0 1-1.3 .5l-.1-.4h.5v.3a.22 .22 0 0 0 .2 .3 .22 .22 0 0 0 .2-.2v-1.1a.23 .23 0 0 0-.3-.2 .23 .23 0 0 0-.1 .3v.6h-.5v-.5z" fill-rule="evenodd"/>
<path d="M304.2 259.6a.5 .5 0 0 1 .6-.2 .5 .5 0 0 1 .3 .6 .36 .36 0 0 1-.4-.4l-.1-.1a.42 .42 0 0 0-.2 .7 .51 .51 0 0 0 .3 .6 .51 .51 0 0 0 .5-.1 .77 .77 0 0 1-1.1 .2 .77 .77 0 0 1 0-1.2z" fill-rule="evenodd"/>
<path d="M305.4 258.7h.7v1.5l.5-.5-.1-.3h.7l-.7 .6 .8 1h-.8l.1-.1-.4-.6-.1 .6 .2 .1h-.9l.2-.3v-1.8z" fill-rule="evenodd"/>
<path d="M307.4 260.1h1v.3h-1z" fill-rule="evenodd"/>
<path d="M308.5 258.7h1.2l-.3 .2v.9h.8v-.9l-.3-.2h1.2l-.3 .1v.3v1.7l.3 .2h-1.2l.3-.1v-1h-.8v1l.3 .1h-1.2l.3-.1v-.3v-1.6z" fill-rule="evenodd"/>
<path d="M311.2 258.7h1l-.2 .3 .5 1.3 .4-.9-.2-.5-.3-.2h1.1l-.2 .2 .5 1.3 .4-1.2-.2-.3 .6 .1-.2 .1-.8 2.2-.6-1.5-.7 1.5z" fill-rule="evenodd"/>
</g>
<path d="M263 274.5h34.5M297.5 264h-34.5v21" fill="none" stroke="#000" stroke-width=".2"/>
<g fill="#00f">
<path d="M299.2 265.1h1v.2h-.8v.5h.7v.1h-.7v.7h-.2z" fill-rule="evenodd"/>
<path d="M300.4 265.1h.2v.2h-.2z" fill-rule="evenodd"/>
<path d="M300.4 265.5h.2v1.1h-.2z" fill-rule="evenodd"/>
<path d="M300.9 265.1h.2v1.5h-.2z" fill-rule="evenodd"/>
<path d="M301.4 265.7l.1-.1a.51 .51 0 0 1 .6 0 .51 .51 0 0 1 .2 .5h-.8l.2 .4 .6-.2a.52 .52 0 0 1-.7 .3 .52 .52 0 0 1-.3-.6h.8l-.3-.3-.3 .3h-.2z" fill-rule="evenodd"/>
<path d="M303.1 265.1h.2l.8 1.2v-1.2h.2v1.5h-.2l-.8-1.2v1.2h-.2z" fill-rule="evenodd"/>
<path d="M304.7 265.6l.1-.1a.47 .47 0 0 1 .6 .1 .47 .47 0 0 1 .1 .6l.1 .4-.3-.1-.5 .1-.2-.1v-.2l.6 .2 .1-.4-.7 .2a.57 .57 0 0 1 .7-.4l-.2-.2-.5 .1z" fill-rule="evenodd"/>
<path d="M305.8 265.5h.1v.2l.5-.2 .2 .2 .2-.2 .3 .1 .2 1h-.2l-.1-.9a.26 .26 0 0 0-.3 0 .26 .26 0 0 0-.1 .3v.6h-.2v-.8l-.3-.1-.1 .9h-.2z" fill-rule="evenodd"/>
<path d="M307.6 265.7l.1-.1a.51 .51 0 0 1 .6 0 .51 .51 0 0 1 .2 .5h-.8l.2 .4 .6-.2a.52 .52 0 0 1-.7 .3 .52 .52 0 0 1-.3-.6h.8l-.3-.3-.3 .3h-.2z" fill-rule="evenodd"/>
<path d="M308.8 265.5h.2v.2h-.2z" fill-rule="evenodd"/>
<path d="M308.8 266.4h.2v.2h-.2z" fill-rule="evenodd"/>
<path d="M264.8 265.2l.7-.1 .2 .4-.1 .1a.32 .32 0 0 0-.4-.4 .32 .32 0 0 0-.3 .5h.3a.5 .5 0 0 1 .6 .6 .5 .5 0 0 1-.8 .3l-.4-.3v-.2h.2a.39 .39 0 0 0 .4 .4 .39 .39 0 0 0 .4-.4l-.9-.4v-.2z" fill-rule="evenodd"/>
<path d="M266 265.1h.2v.6l.3-.2 .4 .2v.9h-.2v-.7a.27 .27 0 0 0-.3-.2 .27 .27 0 0 0-.2 .3v.6h-.2z" fill-rule="evenodd"/>
<path d="M267.3 265.7l.1-.1a.51 .51 0 0 1 .5 0 .51 .51 0 0 1 .2 .5h-.8l.3 .4 .5-.2a.52 .52 0 0 1-.6 .3 .52 .52 0 0 1-.3-.6h.8l-.3-.3-.4 .3h-.1z" fill-rule="evenodd"/>
<path d="M268.5 265.7v-.1a.51 .51 0 0 1 .6 0 .51 .51 0 0 1 .2 .5h-.8l.2 .4 .6-.2a.52 .52 0 0 1-.6 .3 .52 .52 0 0 1-.4-.6h.8l-.3-.3-.3 .3h-.2z" fill-rule="evenodd"/>
<path d="M269.6 265.3l.2-.1v.3h.1v.2h-.1v.6l.2 .3a.27 .27 0 0 1-.3 0 .27 .27 0 0 1-.1-.3v-.6h-.2z" fill-rule="evenodd"/>
<path d="M270.6 265.1h1.2v.2h-.5v1.3h-.2v-1.3h-.5z" fill-rule="evenodd"/>
<path d="M271.9 265.1h.2v.2h-.2z" fill-rule="evenodd"/>
<path d="M271.9 265.5h.2v1.1h-.2z" fill-rule="evenodd"/>
<path d="M272.4 265.3l.2-.1v.3h.1v.2h-.1v.6l.2 .3a.27 .27 0 0 1-.3 0 .27 .27 0 0 1-.1-.3v-.6h-.2z" fill-rule="evenodd"/>
<path d="M272.9 265.1h.2v1.5h-.2z" fill-rule="evenodd"/>
<path d="M273.5 265.7v-.1a.51 .51 0 0 1 .6 0 .51 .51 0 0 1 .2 .5h-.8l.3 .4 .5-.2a.52 .52 0 0 1-.6 .3 .52 .52 0 0 1-.4-.6h.8l-.3-.3-.3 .3h-.2z" fill-rule="evenodd"/>
<path d="M274.6 265.5h.2v.2h-.2z" fill-rule="evenodd"/>
<path d="M274.6 266.4h.2v.2h-.2z" fill-rule="evenodd"/>
<path d="M264.8 275.7l.7-.1 .2 .4-.1 .1a.32 .32 0 0 0-.4-.4 .32 .32 0 0 0-.3 .5h.3a.5 .5 0 0 1 .6 .6 .5 .5 0 0 1-.8 .3l-.4-.3v-.2h.2a.39 .39 0 0 0 .4 .4 .39 .39 0 0 0 .4-.4l-.9-.4v-.2z" fill-rule="evenodd"/>
<path d="M266 275.6h.2v.6l.3-.2 .4 .2v.9h-.2v-.7a.27 .27 0 0 0-.3-.2 .27 .27 0 0 0-.2 .3v.6h-.2z" fill-rule="evenodd"/>
<path d="M267.3 276.2a.51 .51 0 0 1 .6-.1 .51 .51 0 0 1 .2 .5h-.8l.3 .4 .5-.2a.52 .52 0 0 1-.6 .3 .52 .52 0 0 1-.3-.6h.8l-.3-.3-.4 .3h-.1z" fill-rule="evenodd"/>
<path d="M268.5 276.2a.51 .51 0 0 1 .6-.1 .51 .51 0 0 1 .2 .5h-.8l.2 .4 .6-.2a.52 .52 0 0 1-.6 .3 .52 .52 0 0 1-.4-.6h.8l-.3-.3-.3 .3h-.2z" fill-rule="evenodd"/>
<path d="M269.6 275.8l.2-.1v.3h.1v.2h-.1v.6l.2 .3a.27 .27 0 0 1-.3 0 .27 .27 0 0 1-.1-.3v-.6h-.2z" fill-rule="evenodd"/>
<path d="M270.7 275.6h.6a.46 .46 0 0 1 .6 .5 .46 .46 0 0 1-.6 .4h-.4v.6h-.2v-.8h.8l.2-.2-.2-.3h-.6v.5h-.2z" fill-rule="evenodd"/>
<path d="M272.2 276.2l.1-.2a.47 .47 0 0 1 .6 .1 .47 .47 0 0 1 .1 .6v.4l-.2-.1-.5 .1-.2-.1-.1-.2 .6 .2 .2-.4-.8 .2a.57 .57 0 0 1 .8-.4l-.2-.2-.5 .1z" fill-rule="evenodd"/>
<path d="M273.3 275.8l.2-.1v.3h.2v.2h-.2v.6l.2 .3a.27 .27 0 0 1-.3 0 .27 .27 0 0 1-.1-.3v-.6h-.1z" fill-rule="evenodd"/>
<path d="M273.9 275.6h.1v.6l.4-.2 .3 .1v1h-.1v-.7a.27 .27 0 0 0-.4-.2 .27 .27 0 0 0-.2 .3v.6h-.1z" fill-rule="evenodd"/>
<path d="M275.1 276h.2v.2h-.2z" fill-rule="evenodd"/>
<path d="M275.1 276.9h.2v.2h-.2z" fill-rule="evenodd"/>
</g>
<g fill="#00007f">
<path d="M264.6 269.7h1.1v.4l-.1-.2-.4-.1v1.2l.2 .1h-.6l.2-.1v-1.2h-.3l-.1 .3z" fill-rule="evenodd"/>
<path d="M265.9 270.3a.46 .46 0 0 1 .7 .1 .46 .46 0 0 1-.3 .7 .46 .46 0 0 1-.6-.5h.2a.34 .34 0 0 0 .1 .4 .34 .34 0 0 0 .5-.1 .34 .34 0 0 0-.1-.4l-.3-.3-.2 .4h-.2z" fill-rule="evenodd"/>
<path d="M266.7 270.3l.3-.1v.2a.39 .39 0 0 1 .6-.1 .39 .39 0 0 1 0 .5l-.2 .3h-.4v.4l.2 .1h-.5l.1-.2v-1h.2v.6a.33 .33 0 0 0 .5-.3 .33 .33 0 0 0-.4-.3h-.3z" fill-rule="evenodd"/>
<path d="M268.2 269.7l-.5 1.5z" fill-rule="evenodd"/>
<path d="M268.4 269.7h.6a.38 .38 0 0 1 .5 .2 .38 .38 0 0 1-.2 .5 .39 .39 0 0 1 .3 .5 .39 .39 0 0 1-.6 .2h-.6l.1-.1 .1-.5h.2v.5a.37 .37 0 0 0 .5 0 .37 .37 0 0 0 0-.5 .37 .37 0 0 0-.5 0h-.2l-.1-.7h.3v.6a.35 .35 0 0 0 .4-.1 .35 .35 0 0 0 0-.4 .35 .35 0 0 0-.4-.1z" fill-rule="evenodd"/>
<path d="M270 270.3a.46 .46 0 0 1 .7 .1 .46 .46 0 0 1-.4 .7 .46 .46 0 0 1-.5-.5h.2a.34 .34 0 0 0 .1 .4 .34 .34 0 0 0 .4-.1 .34 .34 0 0 0 0-.4l-.3-.3-.2 .4h-.2z" fill-rule="evenodd"/>
<path d="M271.1 269.9v.3h.2h-.2v.7h.3l-.3 .2-.2-.1v-.8h-.1z" fill-rule="evenodd"/>
<path d="M271.7 269.9v.3h.2h-.2v.7h.2l-.2 .2-.2-.1v-.8h-.1z" fill-rule="evenodd"/>
<path d="M272.2 270.3a.46 .46 0 0 1 .7 .1 .46 .46 0 0 1-.3 .7 .46 .46 0 0 1-.6-.5h.2a.34 .34 0 0 0 .1 .4 .34 .34 0 0 0 .5-.1 .34 .34 0 0 0-.1-.4l-.3-.3-.2 .4h-.2z" fill-rule="evenodd"/>
<path d="M273 270.3l.3-.1v.2l.4-.2 .2 .2a.3 .3 0 0 1 .3-.2 .3 .3 0 0 1 .3 .3v.5l.1 .1h-.5l.2-.1v-.5l-.2-.2-.2 .1v.6l.1 .1h-.4l.1-.1v-.5l-.1-.2-.3 .1v.6l.2 .1h-.5l.2-.1v-.6z" fill-rule="evenodd"/>
<path d="M275.1 269.7h.6l-.2 .2 .4 .9 .4-.9-.1-.2h.4l-.7 1.5z" fill-rule="evenodd"/>
<path d="M276.6 270.3l.3-.1v.8l.1 .1h-.4l.1-.1v-.5z" fill-rule="evenodd"/>
<path d="M277.3 270.3l.4-.1 .2 .2v.1h-.6l.2 .4 .3 .1 .1-.2a.41 .41 0 0 1-.6 .3 .41 .41 0 0 1-.1-.6h.5l-.2-.3-.3 .3z" fill-rule="evenodd"/>
<path d="M278 270.2h.4l-.1 .1 .2 .6 .2-.4-.2-.3h.5l-.1 .1 .2 .6 .2-.6-.1-.1h.3l-.4 1-.3-.6-.3 .6z" fill-rule="evenodd"/>
<circle cx="276.8" cy="269.8" r=".1"/>
</g>
<path d="M297.5 243h-34.5v21" fill="none" stroke="#000" stroke-width=".2"/>
<g fill="#00f">
<path d="M264.8 244.3l.7-.2 .4 .3-.2 .2a.53 .53 0 0 0-.8-.2 .53 .53 0 0 0 0 .8l.4 .3 .3-.1 .1-.3h.2a.74 .74 0 0 1-1.1 .4 .74 .74 0 0 1 0-1.2z" fill-rule="evenodd"/>
<path d="M266.3 244.6a.54 .54 0 0 1 .8 .1 .54 .54 0 0 1-.3 .8 .54 .54 0 0 1-.7-.4h.2a.37 .37 0 0 0 .5 .4 .37 .37 0 0 0 .1-.7l-.4-.1-.2 .4h-.2z" fill-rule="evenodd"/>
<path d="M267.3 244.5h.2v.2l.4-.2 .2 .2 .3-.2 .3 .1 .1 1h-.2l-.1-.9a.26 .26 0 0 0-.3 0 .26 .26 0 0 0 0 .3v.6h-.2l-.1-.8-.3-.1-.1 .9h-.2z" fill-rule="evenodd"/>
<path d="M269.1 244.5h.1v.2l.4-.2 .3 .2 .2-.2 .3 .1 .1 1h-.1l-.1-.9a.26 .26 0 0 0-.3 0 .26 .26 0 0 0-.1 .3v.6h-.2v-.8l-.3-.1-.1 .9h-.2z" fill-rule="evenodd"/>
<path d="M270.9 244.7l.1-.1a.51 .51 0 0 1 .5 0 .51 .51 0 0 1 .3 .5h-.9l.3 .4 .6-.2a.52 .52 0 0 1-.7 .3 .52 .52 0 0 1-.3-.6h.8l-.3-.3-.3 .3h-.2z" fill-rule="evenodd"/>
<path d="M272 244.5h.1v.2l.4-.2a.35 .35 0 0 1 .4 .5v.6h-.2v-.6a.27 .27 0 0 0-.3-.3 .27 .27 0 0 0-.2 .3v.6h-.2z" fill-rule="evenodd"/>
<path d="M273.2 244.3l.2-.1v.3h.2v.2h-.2v.6l.2 .3a.27 .27 0 0 1-.3 0 .27 .27 0 0 1-.1-.3v-.6h-.2z" fill-rule="evenodd"/>
<path d="M273.8 244.6l.5-.1 .2 .3h-.2a.21 .21 0 0 0-.2-.2 .21 .21 0 0 0-.1 .3 .43 .43 0 0 1 .4 .1 .43 .43 0 0 1 .1 .4l-.2 .2h-.4l-.2-.3h.1a.24 .24 0 0 0 .3 .3 .24 .24 0 0 0 .2-.4 .43 .43 0 0 1-.6-.5z" fill-rule="evenodd"/>
<path d="M274.8 244.5h.2v.2h-.2z" fill-rule="evenodd"/>
<path d="M274.8 245.4h.2v.2h-.2z" fill-rule="evenodd"/>
</g>
<g fill="#00007f">
<path d="M264.7 248.7h1l-.9 1.3h.7l.2-.3v.4h-1.2l.9-1.3h-.6l-.1 .3z" fill-rule="evenodd"/>
<path d="M266 248.8l.7-.1v.5a.29 .29 0 0 0-.3-.4 .29 .29 0 0 0-.2 .4h.1a.49 .49 0 0 1 .5 .3 .49 .49 0 0 1-.1 .6l-.8 .1 .1-.5a.33 .33 0 0 0 .3 .4 .33 .33 0 0 0 .2-.4v-.1a.51 .51 0 0 1-.5-.2 .51 .51 0 0 1 0-.6z" fill-rule="evenodd"/>
<path d="M267 248.7h.5l-.1 .1 .3 1 .2-.7-.3-.4h.6l-.2 .2 .3 .9 .3-.9-.1-.2h.4l-.6 1.5-.3-.9-.4 .9z" fill-rule="evenodd"/>
<path d="M269 249.2l.5 .1v.7l.2-.1-.1 .2-.7-.1-.1-.1 .4 .1 .2-.1v-.3l-.6 .3 .6-.4-.2-.3-.3 .3z" fill-rule="evenodd"/>
<path d="M270 248.9v.3h.3h-.3v.7h.3l-.3 .2-.1-.1v-.8h-.2z" fill-rule="evenodd"/>
<path d="M270.5 249.3l.4-.1 .2 .1-.1 .2a.28 .28 0 0 0-.4-.3 .28 .28 0 0 0-.1 .5l.3 .3 .3-.2a.43 .43 0 0 1-.6 .3 .43 .43 0 0 1-.1-.7z" fill-rule="evenodd"/>
<path d="M271.2 248.8l.3-.1v.7l.3-.2h.2l.1 .8 .1 .1h-.4l.1-.2v-.5l-.1-.1-.3 .1 .1 .6 .1 .1h-.5l.2-.1v-.9v-.3z" fill-rule="evenodd"/>
</g>
<path d="M263 243h-42v42M297.5 243h69" fill="none" stroke="#000" stroke-width=".2"/>
<g fill="#000">
<path d="M17.1 17.5a5.9 5.9 0 0 1 2.7 .1 1.87 1.87 0 0 1 .9 2.2 1.87 1.87 0 0 1-2 1.4h-1.6l.4-.2 .1-.4h.9v.2a.65 .65 0 0 0 .7 .2 .65 .65 0 0 0 .4-.6 2.07 2.07 0 0 0-.6-2.7h-.5v2.9h-.9v-2.8z" fill-rule="evenodd"/>
<path d="M21.7 18.8a1.29 1.29 0 0 1 1.9 1.1 1.29 1.29 0 0 1-1.9 1.1l-.4-.9h.7l.1 .6a.35 .35 0 0 0 .3 .3 .35 .35 0 0 0 .4-.3v-1.7a.37 .37 0 0 0-.5-.3 .37 .37 0 0 0-.2 .5l-.1 .9h-.7v-.7z" fill-rule="evenodd"/>
<path d="M26.5 17.5h1.1v2.4l.8-.9v-.2l-.3-.2h1.2l-1.1 .9 1.3 1.7h-1.3l.1-.3-.6-.9-.1 .1v.8l.2 .3h-1.3l.2-.2 .1-.4v-2.9z" fill-rule="evenodd"/>
<path d="M29.6 19.6h1.6v.6h-1.6z" fill-rule="evenodd"/>
<path d="M31.4 17.5h2l-.5 .2-.1 1.4h1.3v-1a.53 .53 0 0 0-.5-.6h2l-.5 .2-.1 .4v2.7l.6 .4h-2l.5-.3v-1.5h-1.3l.1 1.5 .5 .3h-2l.5-.2v-.5v-2.7z" fill-rule="evenodd"/>
<path d="M35.7 17.5h1.6l-.3 .2v.2l.8 2.1 .6-1.4a1.18 1.18 0 0 0-.7-1.1h1.8l-.4 .2 .8 2.2 .7-1.9v-.3l-.4-.2h1l-.3 .3-1.3 3.4-1.1-2.3-1.1 2.3-1.4-3.4z" fill-rule="evenodd"/>
<path d="M46.7 18.8a1.08 1.08 0 0 1 1.2-.1l.2-.2v.9a.84 .84 0 0 0-1-.6v.3a1.76 1.76 0 0 1 1.2 1.3 .96 .96 0 0 1-1.6 .7l-.1 .1-.1-.9a.91 .91 0 0 0 1.1 .7l.1-.4a2.35 2.35 0 0 1-1.2-1.3z" fill-rule="evenodd"/>
<path d="M48.9 18.8a1.08 1.08 0 0 1 1.2-.1l.2-.2v.9a.84 .84 0 0 0-1-.6v.3a1.75 1.75 0 0 1 1.1 1.3 .96 .96 0 0 1-1.5 .7l-.1 .1-.1-.9a.91 .91 0 0 0 1.1 .7v-.4a2.36 2.36 0 0 1-1.1-1.3z" fill-rule="evenodd"/>
<path d="M51.2 18.9a1.03 1.03 0 0 1 1.2-.3 1.03 1.03 0 0 1 .6 1.2h-1.4a.72 .72 0 0 0 .4 .9 .72 .72 0 0 0 .9-.3 .93 .93 0 0 1-1.2 .8 1.26 1.26 0 0 1-.8-1.7l1.4 .1v-.6l-.3-.3-.4 .3v.5h-.7z" fill-rule="evenodd"/>
<path d="M53.3 18.6h1.1v.4a.79 .79 0 0 1 .7-.5 .79 .79 0 0 1 .7 .5 .82 .82 0 0 1 1.1-.4 .82 .82 0 0 1 .5 1v1.3l.2 .3h-1.3l.3-.3v-1.7a.31 .31 0 0 0-.3-.3 .31 .31 0 0 0-.3 .2l-.1 .1v1.7l.3 .3h-1.4l.3-.4v-1.6a.3 .3 0 0 0-.2-.3 .3 .3 0 0 0-.4 .2l-.1 .1v1.4v.4l.2 .2h-1.3l.3-.2v-.4v-1.7z" fill-rule="evenodd"/>
<path d="M57.9 17.5h1.1v1.4a1.04 1.04 0 0 1 1.3-.1 1.04 1.04 0 0 1 .3 1.3 1.17 1.17 0 0 1-.6 1 1.17 1.17 0 0 1-1.3-.1l-.5 .2v-2.1h.8v1.6a.4 .4 0 0 0 .4 .4 .4 .4 0 0 0 .4-.4v-1.3a.46 .46 0 0 0-.3-.5 .46 .46 0 0 0-.5 .2h-.8v-1.4z" fill-rule="evenodd"/>
<path d="M61 17.5h1.1v3.1v.4l.3 .2h-1.4l.3-.2v-.4v-2.9z" fill-rule="evenodd"/>
<path d="M66.7 17.5a5.9 5.9 0 0 1 2.7 .1 1.87 1.87 0 0 1 1 2.2 1.87 1.87 0 0 1-2 1.4h-1.7l.5-.2v-.4h.9v.2a.65 .65 0 0 0 .7 .2 .65 .65 0 0 0 .5-.6 2.08 2.08 0 0 0-.7-2.7h-.5v2.9h-.9v-2.8z" fill-rule="evenodd"/>
<path d="M71.4 18.8a1.29 1.29 0 0 1 1.9 1.1 1.29 1.29 0 0 1-1.9 1.1l-.5-.9h.8v.6a.35 .35 0 0 0 .3 .3 .35 .35 0 0 0 .4-.3v-1.7a.37 .37 0 0 0-.4-.3 .37 .37 0 0 0-.3 .5v.9h-.8l.1-.7z" fill-rule="evenodd"/>
<path d="M76.1 18.6h1.1v2a.27 .27 0 0 0 .2 .3 .27 .27 0 0 0 .3-.2l.2-.2v-1.3l-.1-.4-.2-.2h1v2.3l.3 .3h-1v-.4a.79 .79 0 0 1-1.1 .4 .79 .79 0 0 1-.4-1v-1.3z" fill-rule="evenodd"/>
<path d="M79.3 18.6h1v.4a.79 .79 0 0 1 .8-.5 .79 .79 0 0 1 .7 .5 .82 .82 0 0 1 1-.4 .82 .82 0 0 1 .5 1v1.3l.3 .3h-1.3l.2-.3v-1.7a.31 .31 0 0 0-.2-.3 .31 .31 0 0 0-.3 .2l-.2 .1v1.7l.3 .3h-1.3l.3-.4-.1-1.6a.3 .3 0 0 0-.2-.3 .3 .3 0 0 0-.3 .2l-.2 .1v1.4l.1 .4 .2 .2h-1.3l.2-.2 .1-.4-.1-1.7z" fill-rule="evenodd"/>
<path d="M84.3 18.9a1.03 1.03 0 0 1 1.3-.3 1.03 1.03 0 0 1 .5 1.2h-1.4a.72 .72 0 0 0 .4 .9 .72 .72 0 0 0 .9-.3l.1 .1a1.14 1.14 0 0 1-1.5 .7 1.14 1.14 0 0 1-.6-1.6h1.4v-.6l-.3-.3-.3 .3-.1 .5h-.7z" fill-rule="evenodd"/>
<path d="M86.4 18.6h1.1v.4a.79 .79 0 0 1 1-.4 .79 .79 0 0 1 .4 1v1.3l.3 .3h-1.3l.2-.3v-1.7a.28 .28 0 0 0-.2-.3 .28 .28 0 0 0-.3 .2l-.1 .2v1.3v.4l.2 .2h-1.3l.2-.2 .1-.4v-1.7z" fill-rule="evenodd"/>
<path d="M90.5 17.7v.9h.6v.3h-.6l.1 1.8 .1 .2 .4-.3a.68 .68 0 0 1-.9 .6 .68 .68 0 0 1-.4-.9v-1.4l-.4-.1z" fill-rule="evenodd"/>
<path d="M24.5 18.8a.84 .84 0 0 1 1-.3 .84 .84 0 0 1 .5 .9 .46 .46 0 0 1-.5 0 .46 .46 0 0 1-.1-.5l-.3-.2a1.36 1.36 0 0 0 .5 2.1l.5-.3a1.02 1.02 0 0 1-1 .7 1.02 1.02 0 0 1-1-.8v-.7z" fill-rule="evenodd"/>
<path d="M44.3 17.4l1.5 3.4 .4 .4h-1.8l.5-.3-.3-.8h-1.3l-.3 .8 .5 .3h-1.2l.4-.5 .4-.8h1.4l-.6-1.3-.5 1.3h-.3z" fill-rule="evenodd"/>
<path d="M62.5 18.6h1.4l-.3 .3 .6 1.4 .4-1.4-.3-.3h.9l-.3 .3-.9 2.4a1.27 1.27 0 0 1-.7 1 .41 .41 0 0 1-.7-.2 .41 .41 0 0 1 .6-.4l.1 .3 .1 .1 .4-.8-1-2.3z" fill-rule="evenodd"/>
<path d="M74.1 18.8a.84 .84 0 0 1 1-.3 .84 .84 0 0 1 .6 .9 .46 .46 0 0 1-.6 0 .46 .46 0 0 1-.1-.5l-.2-.2a1.29 1.29 0 0 0 .4 2.1l.6-.3a.99 .99 0 0 1-.8 .7 .99 .99 0 0 1-1-.3 1.58 1.58 0 0 1 .1-2.1z" fill-rule="evenodd"/>
</g>
<g fill="#00007f">
<path d="M392.6 248.8l.3-.1v1.3h.2l-.6 .2-.4-.2v-.4h.2l.1 .4 .3-.1-.1-.7-.2 .1-.1 .3h-.2v-.1a.4 .4 0 0 1 .6-.3v-.4z" fill-rule="evenodd"/>
<path d="M393.3 248.8a.42 .42 0 0 1 .6 .1 .42 .42 0 0 1-.2 .6l-.4 .5 .7-.1-.1 .2h-.8a.87 .87 0 0 0 .6-1.2h-.3l-.3 .2z" fill-rule="evenodd"/>
<path d="M394.3 249.2l.5 .1 .1 .7 .1-.1-.1 .2-.7-.1v-.1l.3 .1 .2-.1v-.3l-.5 .3 .5-.4-.2-.3-.2 .3z" fill-rule="evenodd"/>
<path d="M395.3 248.9l.3-.2 .1 1.3 .1 .1h-.5l.2-.1v-.9v-.2z" fill-rule="evenodd"/>
<path d="M396.5 248.9l.5-.2-.4 .2-.2 .4a.43 .43 0 0 1 .6 .3 .43 .43 0 0 1-.4 .6 .43 .43 0 0 1-.4-.6h.2a.31 .31 0 0 0 .1 .4 .31 .31 0 0 0 .4 0 .31 .31 0 0 0-.1-.5l-.2-.2-.2 .1v.2h-.2z" fill-rule="evenodd"/>
<path d="M397.5 248.8l.3-.1 .2 .1v.1l-.3-.2-.1 .1v.4h.2h-.2v.8l.2 .1h-.6l.2-.1v-.8h-.2h.2z" fill-rule="evenodd"/>
<path d="M398.1 248.8a.61 .61 0 0 1 .7 .4 .61 .61 0 0 1-.3 .8l-.6 .1 .4-.2 .3-.4h-.5a.24 .24 0 0 1-.2-.2 .24 .24 0 0 1 .2-.2l.1 .3a.34 .34 0 0 0 .4-.2 .34 .34 0 0 0-.3-.4l-.2 .3h-.2z" fill-rule="evenodd"/>
</g>
<path d="M390.5 243v10.5" fill="none" stroke="#000" stroke-width=".2"/>
<g fill="#00f">
<path d="M392.3 244.3l.8-.2 .3 .3 .1 .1-.2 .1a.58 .58 0 0 0-.8-.2 .58 .58 0 0 0-.2 .8 .58 .58 0 0 0 .8 .2l.2-.1v-.3h-.4v-.1h.6v.5a.81 .81 0 0 1-1.2 .1 .81 .81 0 0 1 0-1.2z" fill-rule="evenodd"/>
<path d="M393.8 244.1h.2v.2h-.2z" fill-rule="evenodd"/>
<path d="M393.8 244.5h.2v1.1h-.2z" fill-rule="evenodd"/>
<path d="M394.3 244.3l.2-.1v.3h.1v.2h-.1v.6l.2 .3a.27 .27 0 0 1-.3 0 .27 .27 0 0 1-.1-.3v-.6h-.2z" fill-rule="evenodd"/>
<path d="M395.4 244.1h.2v.6h.8v-.6h.2v1.5h-.2v-.7h-.8v.7h-.2z" fill-rule="evenodd"/>
<path d="M397 244.6l.1-.1a.47 .47 0 0 1 .6 .1 .47 .47 0 0 1 .1 .6l.1 .4-.3-.1-.5 .1-.2-.1v-.2l.6 .2 .1-.4-.7 .2a.57 .57 0 0 1 .7-.4l-.2-.2-.5 .1z" fill-rule="evenodd"/>
<path d="M398.1 244.6l.6-.1 .2 .3h-.2a.21 .21 0 0 0-.3-.2 .21 .21 0 0 0-.1 .3 .43 .43 0 0 1 .5 .1 .43 .43 0 0 1 .1 .4l-.3 .2h-.3l-.3-.3h.2a.24 .24 0 0 0 .3 .3 .24 .24 0 0 0 .1-.4 .43 .43 0 0 1-.5-.5z" fill-rule="evenodd"/>
<path d="M399.1 244.1h.2v.6l.3-.2 .4 .1v1h-.2v-.7a.27 .27 0 0 0-.3-.2 .27 .27 0 0 0-.2 .3v.6h-.2z" fill-rule="evenodd"/>
<path d="M400.4 244.5h.2v.2h-.2z" fill-rule="evenodd"/>
<path d="M400.4 245.4h.2v.2h-.2z" fill-rule="evenodd"/>
</g>
<use href="#words"/>
</svg>
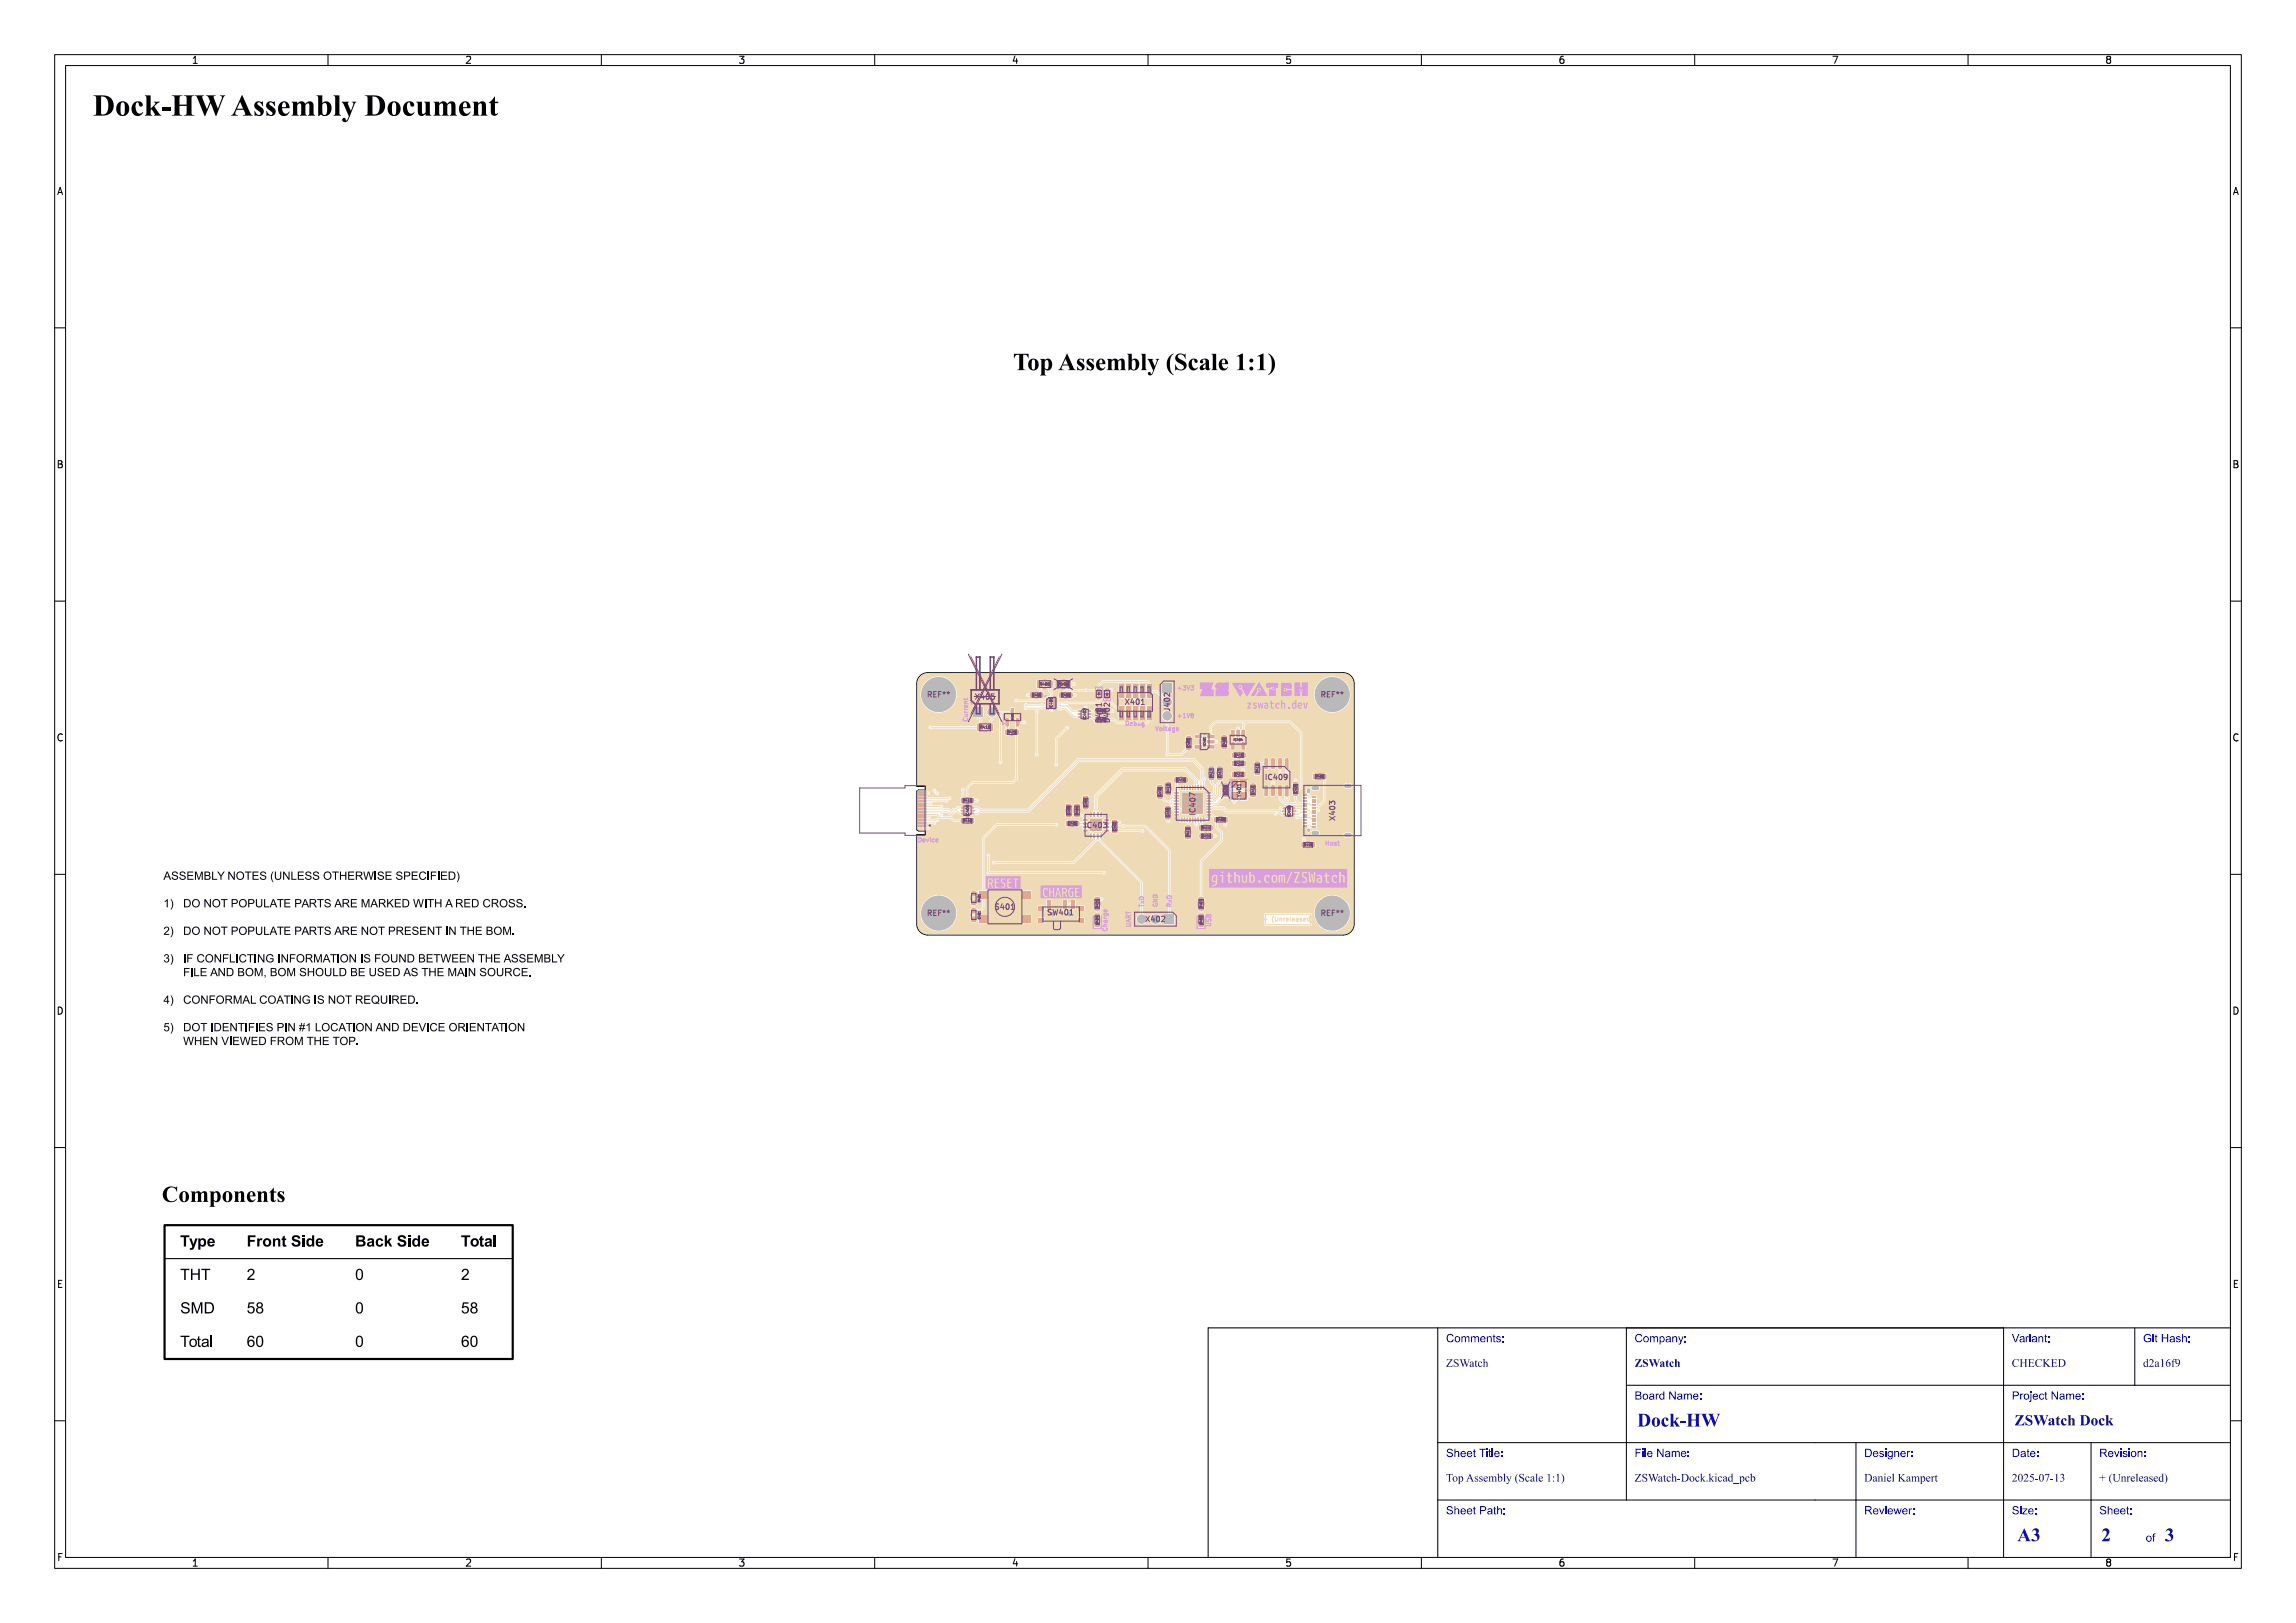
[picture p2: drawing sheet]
<svg xmlns="http://www.w3.org/2000/svg" width="420mm" height="297mm" viewBox="0 0 420 297" stroke-linecap="round" stroke-linejoin="round" font-family="sans-serif">
<defs><g id="words">
<text font-size="5.3" fill="#fff" x="17" y="21.5">Dock-HW Assembly Document</text>
<text font-size="4.3" fill="#fff" x="178.3" y="68">Top Assembly (Scale 1:1)</text>
<g font-size="3.3" fill="#fff">
<text x="299.5" y="261.2">Dock-HW</text>
<text x="369" y="282.2">A3</text>
<text x="384.4" y="282.3">2</text>
<text x="396" y="282.3">3</text>
</g>
<text font-size="2.7" fill="#fff" x="368.5" y="261">ZSWatch Dock</text>
<g font-size="2" fill="#fff">
<text x="264.5" y="245.8">Comments:</text>
<text x="299" y="245.8">Company:</text>
<text x="368" y="245.8">Variant:</text>
<text x="392" y="245.8">Git Hash:</text>
<text x="264.5" y="250.2">ZSWatch</text>
<text x="299" y="250.2">ZSWatch</text>
<text x="368" y="250.2">CHECKED</text>
<text x="392" y="250.2">d2a16f9</text>
<text x="299" y="256.2">Board Name:</text>
<text x="368" y="256.2">Project Name:</text>
<text x="264.5" y="266.8">Sheet Title:</text>
<text x="299" y="266.8">File Name:</text>
<text x="341" y="266.8">Designer:</text>
<text x="368" y="266.8">Date:</text>
<text x="384" y="266.8">Revision:</text>
<text x="264.5" y="271.2">Top Assembly (Scale 1:1)</text>
<text x="299" y="271.2">ZSWatch-Dock.kicad_pcb</text>
<text x="341" y="271.2">Daniel Kampert</text>
<text x="368" y="271.2">2025-07-13</text>
<text x="384" y="271.2">+ (Unreleased)</text>
<text x="264.5" y="277.3">Sheet Path:</text>
<text x="341" y="277.2">Reviewer:</text>
<text x="368" y="277.3">Size:</text>
<text x="384" y="277.2">Sheet:</text>
<text x="392.5" y="282.3">of</text>
</g>
<g font-size="1.7" fill="#fff">
<text x="35" y="11.6">1</text>
<text x="85" y="11.6">2</text>
<text x="135" y="11.6">3</text>
<text x="185" y="11.6">4</text>
<text x="235" y="11.6">5</text>
<text x="285" y="11.6">6</text>
<text x="335" y="11.6">7</text>
<text x="385" y="11.6">8</text>
<text x="10.5" y="35.6">A</text>
<text x="408.5" y="35.6">A</text>
<text x="10.5" y="85.6">B</text>
<text x="408.5" y="85.6">B</text>
<text x="10.5" y="135.7">C</text>
<text x="408.5" y="135.7">C</text>
<text x="10.5" y="185.6">D</text>
<text x="408.5" y="185.6">D</text>
<text x="10.5" y="235.7">E</text>
<text x="408.5" y="235.7">E</text>
<text x="10.5" y="285.6">F</text>
<text x="35" y="286.7">1</text>
<text x="85" y="286.7">2</text>
<text x="135" y="286.7">3</text>
<text x="185" y="286.7">4</text>
<text x="235" y="286.7">5</text>
<text x="285" y="286.7">6</text>
<text x="335" y="286.7">7</text>
<text x="385" y="286.7">8</text>
<text x="408.5" y="285.6">F</text>
</g>
<g font-size="1.3" fill="#fff">
<text x="169.7" y="127.6">REF**</text>
<text x="178.6" y="128">X405</text>
<text x="206" y="129">X401</text>
<text x="214" y="130" transform="rotate(-90 214 130)">J402</text>
<text x="241.7" y="127.6">REF**</text>
<text x="201.5" y="132" transform="rotate(-90 201.5 132)">D401</text>
<text x="203" y="132" transform="rotate(-90 203 132)">D402</text>
<text x="231.5" y="142.7">IC409</text>
<text x="218.7" y="149.1" transform="rotate(-90 218.7 149.1)">IC407</text>
<text x="244.2" y="149.9" transform="rotate(-90 244.2 149.9)">X403</text>
<text x="198.5" y="151.5">IC403</text>
<text x="169.7" y="167.6">REF**</text>
<text x="182.2" y="166.4">S401</text>
<text x="192" y="167.5">SW401</text>
<text x="241.7" y="167.6">REF**</text>
<text x="209.8" y="168.7">X402</text>
</g>
<g font-size="1.1" fill="#fff">
<text x="178.1" y="128.9" transform="rotate(-90 178.1 128.9)">+</text>
<text x="215.2" y="131.4">+1V8</text>
<text x="215.2" y="126.3">+3V3</text>
<text x="177" y="132.1" transform="rotate(-90 177 132.1)">Current</text>
<text x="206" y="132.8">Debug</text>
<text x="211.3" y="133.8">Voltage</text>
<text x="167.9" y="154.1">Device</text>
<text x="242.4" y="154.7">Host</text>
<text x="209.2" y="166.1" transform="rotate(-90 209.2 166.1)">TxD</text>
<text x="211.8" y="166.1" transform="rotate(-90 211.8 166.1)">GND</text>
<text x="214.3" y="166.1" transform="rotate(-90 214.3 166.1)">RxD</text>
<text x="202.5" y="170.3" transform="rotate(-90 202.5 170.3)">Charge</text>
<text x="206.8" y="169.5" transform="rotate(-90 206.8 169.5)">UART</text>
<text x="221.5" y="169.4" transform="rotate(-90 221.5 169.4)">USB</text>
<text x="231.1" y="168.6">+ (Unreleased)</text>
</g>
<text font-size=".9" fill="#fff" x="227" y="145.7" transform="rotate(-90 227 145.7)">Y401</text>
<g font-size=".7" fill="#fff">
<text x="190.3" y="125.5">R405</text>
<text x="193.7" y="125.5">R406</text>
<text x="192.5" y="129.6" transform="rotate(-90 192.5 129.6)">IC405</text>
<text x="198.7" y="131.7" transform="rotate(-90 198.7 131.7)">IC402</text>
<text x="179.4" y="133.3">R418</text>
<text x="177.2" y="149.3" transform="rotate(-90 177.2 149.3)">IC408</text>
<text x="236.1" y="149.5" transform="rotate(-90 236.1 149.5)">IC406</text>
</g>
<g font-size=".5" fill="#fff">
<text x="189" y="127.4">C409</text>
<text x="194.3" y="127.4">C406</text>
<text x="200.9" y="131.9">R403</text>
<text x="200.9" y="130.3">R402</text>
<text x="184.5" y="134.2">R420</text>
<text x="217.7" y="136.6" transform="rotate(-90 217.7 136.6)">C402</text>
<text x="220.5" y="136.5" transform="rotate(-90 220.5 136.5)">IC401</text>
<text x="224.1" y="136.4" transform="rotate(-90 224.1 136.4)">C408</text>
<text x="225.7" y="135.6">IC404</text>
<text x="215.4" y="142.9">C416</text>
<text x="221.8" y="142.1" transform="rotate(-90 221.8 142.1)">R417</text>
<text x="223.3" y="142.1" transform="rotate(-90 223.3 142.1)">C417</text>
<text x="226" y="141.9">C412</text>
<text x="226" y="139.9">C411</text>
<text x="226" y="138.4">C410</text>
<text x="230.2" y="141.2" transform="rotate(-90 230.2 141.2)">R419</text>
<text x="240.8" y="142.3">R409</text>
<text x="176.3" y="146.7">R415</text>
<text x="195.7" y="149" transform="rotate(-90 195.7 149)">C403</text>
<text x="197.2" y="149" transform="rotate(-90 197.2 149)">R404</text>
<text x="198.8" y="147.5" transform="rotate(-90 198.8 147.5)">C404</text>
<text x="212.4" y="145.6" transform="rotate(-90 212.4 145.6)">C418</text>
<text x="213.8" y="149.3" transform="rotate(-90 213.8 149.3)">C415</text>
<text x="213.9" y="144.9" transform="rotate(-90 213.9 144.9)">R412</text>
<text x="224.4" y="145.2" transform="rotate(-90 224.4 145.2)">R411</text>
<text x="229.4" y="145.3" transform="rotate(-90 229.4 145.3)">C413</text>
<text x="237.2" y="145" transform="rotate(-90 237.2 145)">C419</text>
<text x="176.3" y="150.4">R416</text>
<text x="195.6" y="150.9">C405</text>
<text x="204.1" y="151.9" transform="rotate(-90 204.1 151.9)">C407</text>
<text x="217.5" y="152.9" transform="rotate(-90 217.5 152.9)">R413</text>
<text x="220" y="151.7">R414</text>
<text x="220" y="153.2">C414</text>
<text x="222.7" y="150.2">R408</text>
<text x="238.7" y="154.8">R410</text>
<text x="179.3" y="165" transform="rotate(-90 179.3 165)">R401</text>
<text x="200.9" y="166" transform="rotate(-90 200.9 166)">R421</text>
<text x="219.9" y="166" transform="rotate(-90 219.9 166)">R407</text>
<text x="179.3" y="168.1" transform="rotate(-90 179.3 168.1)">C401</text>
<text x="200.9" y="169" transform="rotate(-90 200.9 169)">D404</text>
<text x="219.9" y="169" transform="rotate(-90 219.9 169)">D403</text>
</g>
<text font-size=".4" fill="#fff" x="185.4" y="131.8" transform="rotate(-90 185.4 131.8)">Q401</text>
</g></defs>
<path d="M168.3 123.7l.9-.5 .5-.1h76a2 2 0 0 1 2 2v44a2 2 0 0 1-2 2h-76a2 2 0 0 1-2-2v-16.4h1.6v-.6h-1.2l-.4-.2v-7.1l.4-.2h1.2v-.7h-1.6v-18.8l.1-.5z" fill="none" stroke="#000" stroke-width=".18"/>
<path d="M231.5 167.3h8.2v1.9h-8.2z" fill="none" stroke="#eedab5" stroke-width=".2"/>
<g fill="none" stroke="#eedab5" stroke-width=".18">
<path d="M231.1 168.3h.7M231.4 168v.6M233 167.6a.92 .92 0 0 0 0 1.3M233.3 167.8v.6l.1 .2 .3-.2v-.6M234.1 168v.6M234.1 168.1h.3l.1 .5M234.8 168v.6M235.1 168l-.3 .2M235.3 168.3l.4-.1-.1-.1h-.3v.4h.3M236 167.8v.6l.1 .2M236.4 168.3l.4-.1-.1-.1h-.3v.4h.3M237.1 168.1h.3l.1 .5"/>
<path d="M237.5 168.2l-.4 .2 .1 .2 .3-.1M238.1 168.1h-.3l.3 .2v.2h-.3M238.5 168.3l.3-.1v-.1h-.3v.4h.3M239.5 168.1l-.2-.1-.2 .2 .1 .3h.3M239.5 167.8v.8M239.8 167.6a.92 .92 0 0 1 0 1.3"/>
</g>
<g fill="#eedab5">
<path d="M202 151.9h.8v.2h-.8z" fill-rule="evenodd"/>
<path d="M202 151.2h.8v.3h-.8z" fill-rule="evenodd"/>
<path d="M202 150.6h.8v.2h-.8z" fill-rule="evenodd"/>
<path d="M202 149.9h.8v.3h-.8z" fill-rule="evenodd"/>
<path d="M201.3 148.7h.3v.8h-.3z" fill-rule="evenodd"/>
<path d="M200.7 148.7h.2v.8h-.2z" fill-rule="evenodd"/>
<path d="M200 148.7h.3v.8h-.3z" fill-rule="evenodd"/>
<path d="M199.4 148.7h.2v.8h-.2z" fill-rule="evenodd"/>
<path d="M198.1 149.9h.8v.3h-.8z" fill-rule="evenodd"/>
<path d="M198.1 150.6h.8v.2h-.8z" fill-rule="evenodd"/>
<path d="M198.1 151.2h.8v.3h-.8z" fill-rule="evenodd"/>
<path d="M198.1 151.9h.8v.2h-.8z" fill-rule="evenodd"/>
<path d="M199.4 152.6h.2v.8h-.2z" fill-rule="evenodd"/>
<path d="M200 152.6h.3v.8h-.3z" fill-rule="evenodd"/>
<path d="M200.7 152.6h.2v.8h-.2z" fill-rule="evenodd"/>
<path d="M201.3 152.6h.3v.8h-.3z" fill-rule="evenodd"/>
<path d="M199.4 150h2.1v2.1h-2.1z" fill-rule="evenodd"/>
<path d="M202.2 127.4h.6v.6h-.6z" fill-rule="evenodd"/>
<path d="M202.2 126h.6v.6h-.6z" fill-rule="evenodd"/>
<path d="M219.3 165.9h.8v.7h-.8z" fill-rule="evenodd"/>
<path d="M219.3 164.2h.8v.7h-.8z" fill-rule="evenodd"/>
<path d="M227.2 133.6l.5 .1-.1 1.2-.5-.1z" fill-rule="evenodd"/>
<path d="M226.2 133.6l.6 .1-.1 1.2-.5-.1z" fill-rule="evenodd"/>
<path d="M225.3 133.6l.5 .1-.1 1.2-.5-.1z" fill-rule="evenodd"/>
<path d="M225.3 135.9h.5l-.1 1.3-.5-.1z" fill-rule="evenodd"/>
<path d="M227.2 135.9h.5l-.1 1.3-.5-.1z" fill-rule="evenodd"/>
<path d="M203.5 151.6h.8v.8h-.8z" fill-rule="evenodd"/>
<path d="M203.5 150.1h.8v.8h-.8z" fill-rule="evenodd"/>
<path d="M219.5 152.6h.7v.8h-.7z" fill-rule="evenodd"/>
<path d="M221 152.6h.8v.8h-.8z" fill-rule="evenodd"/>
<path d="M241.9 141.7h.7v.8h-.7z" fill-rule="evenodd"/>
<path d="M240.2 141.7h.7v.8h-.7z" fill-rule="evenodd"/>
<path d="M238.4 150.9h.7v.3h-.7z" fill-rule="evenodd"/>
<path d="M238.4 150.4h.7v.3h-.7z" fill-rule="evenodd"/>
<path d="M238.4 149.9h.7v.3h-.7z" fill-rule="evenodd"/>
<path d="M238.4 149.4h.7v.3h-.7z" fill-rule="evenodd"/>
<path d="M238.4 148.9h.7v.3h-.7z" fill-rule="evenodd"/>
<path d="M238.4 148.4h.7v.3h-.7z" fill-rule="evenodd"/>
<path d="M238.4 147.9h.7v.3h-.7z" fill-rule="evenodd"/>
<path d="M238.4 147.4h.7v.3h-.7z" fill-rule="evenodd"/>
<path d="M238.4 146.9h.7v.3h-.7z" fill-rule="evenodd"/>
<path d="M238.4 146.4h.7v.3h-.7z" fill-rule="evenodd"/>
<path d="M238.4 145.9h.7v.3h-.7z" fill-rule="evenodd"/>
<path d="M238.4 145.4h.7v.3h-.7z" fill-rule="evenodd"/>
<path d="M240.1 145.7h.7v.3h-.7z" fill-rule="evenodd"/>
<path d="M240.1 146.2h.7v.3h-.7z" fill-rule="evenodd"/>
<path d="M240.1 146.7h.7v.3h-.7z" fill-rule="evenodd"/>
<path d="M240.1 147.2h.7v.3h-.7z" fill-rule="evenodd"/>
<path d="M240.1 147.7h.7v.3h-.7z" fill-rule="evenodd"/>
<path d="M240.1 148.2h.7v.3h-.7z" fill-rule="evenodd"/>
<path d="M240.1 148.7h.7v.3h-.7z" fill-rule="evenodd"/>
<path d="M240.1 149.2h.7v.3h-.7z" fill-rule="evenodd"/>
<path d="M240.1 149.7h.7v.3h-.7z" fill-rule="evenodd"/>
<path d="M240.1 150.2h.7v.3h-.7z" fill-rule="evenodd"/>
<path d="M240.1 150.7h.7v.3h-.7z" fill-rule="evenodd"/>
<path d="M240.1 151.2h.7v.3h-.7z" fill-rule="evenodd"/>
</g>
<g fill="#eedab5">
<circle cx="241.3" cy="167.1" r=".4"/>
<circle cx="242" cy="165.4" r=".4"/>
<circle cx="242" cy="168.8" r=".4"/>
<circle cx="243.7" cy="164.7" r=".4"/>
<circle cx="243.7" cy="167.1" r="3.2"/>
<circle cx="243.7" cy="169.5" r=".4"/>
<circle cx="245.4" cy="165.4" r=".4"/>
<circle cx="245.4" cy="168.8" r=".4"/>
<circle cx="246.1" cy="167.1" r=".4"/>
</g>
<path d="M240.3 152.4h.6M240.3 144.2h.6M246.3 152.8h.6M246.3 143.8h.6" fill="none" stroke="#eedab5" stroke-width=".8"/>
<g fill="#eedab5">
<path d="M239.8 154.2h.7v.8h-.7z" fill-rule="evenodd"/>
<path d="M238.1 154.2h.7v.8h-.7z" fill-rule="evenodd"/>
<path d="M200.3 165.9h.8v.7h-.8z" fill-rule="evenodd"/>
<path d="M200.3 164.2h.8v.7h-.8z" fill-rule="evenodd"/>
<path d="M216.9 152.8h.8v.7h-.8z" fill-rule="evenodd"/>
<path d="M216.9 151.1h.8v.7h-.8z" fill-rule="evenodd"/>
<path d="M178.1 129.4h1.7v1.7h-1.7z" fill-rule="evenodd"/>
<path d="M222.7 141.9h.8v.8h-.8z" fill-rule="evenodd"/>
<path d="M222.7 140.3h.8v.8h-.8z" fill-rule="evenodd"/>
<path d="M180.7 132.5l.7-.1 .2 .2v.9l-.1 .3h-.7l-.2-.2z" fill-rule="evenodd"/>
<path d="M178.8 132.5l.8-.1 .2 .2v.9l-.2 .3h-.6l-.2-.2z" fill-rule="evenodd"/>
<path d="M177.5 149.8h.6v.8h-.6z" fill-rule="evenodd"/>
<path d="M175.8 149.8h.7v.8h-.7z" fill-rule="evenodd"/>
<path d="M193.2 124.6l.7-.1 .2 .2v.9l-.1 .3h-.7l-.2-.2z" fill-rule="evenodd"/>
<path d="M195 124.6l.7-.1 .2 .2v.9l-.1 .3h-.6l-.3-.2z" fill-rule="evenodd"/>
<path d="M235.1 138.8l.6 .1-.1 1.8-.5-.1z" fill-rule="evenodd"/>
<path d="M233.9 138.8l.5 .1-.1 1.8-.5-.1z" fill-rule="evenodd"/>
<path d="M232.6 138.8l.6 .1-.1 1.8-.5-.1z" fill-rule="evenodd"/>
<path d="M231.3 138.8l.6 .1-.1 1.8-.5-.1z" fill-rule="evenodd"/>
<path d="M231.3 143.8h.6l-.1 1.9-.5-.1z" fill-rule="evenodd"/>
<path d="M232.6 143.8h.6l-.1 1.9-.5-.1z" fill-rule="evenodd"/>
<path d="M233.9 143.8h.5l-.1 1.9-.5-.1z" fill-rule="evenodd"/>
<path d="M235.1 143.8h.6l-.1 1.9-.5-.1z" fill-rule="evenodd"/>
<path d="M223.5 136.2h.8v.8h-.8z" fill-rule="evenodd"/>
<path d="M223.5 134.6h.8v.8h-.8z" fill-rule="evenodd"/>
<path d="M213.1 167.4h1.6v1.6h-1.6z" fill-rule="evenodd"/>
<path d="M183.9 133.6h.7v.8h-.7z" fill-rule="evenodd"/>
<path d="M185.6 133.6h.7v.8h-.7z" fill-rule="evenodd"/>
<path d="M179.1 163h1.5v1.4h-1.5z" fill-rule="evenodd"/>
<path d="M179.1 167.6h1.5v1.2h-1.5z" fill-rule="evenodd"/>
<path d="M187 163h1.6v1.4h-1.6z" fill-rule="evenodd"/>
<path d="M187 167.6h1.6v1.2h-1.6z" fill-rule="evenodd"/>
<path d="M200.3 129.7h.7v.8h-.7z" fill-rule="evenodd"/>
<path d="M202 129.7h.7v.8h-.7z" fill-rule="evenodd"/>
<path d="M213.2 147.5h.8v.8h-.8z" fill-rule="evenodd"/>
<path d="M213.2 149.1h.8v.8h-.8z" fill-rule="evenodd"/>
<path d="M200.7 126h.6v.6h-.6z" fill-rule="evenodd"/>
<path d="M200.7 127.4h.6v.6h-.6z" fill-rule="evenodd"/>
<path d="M229.6 139.4h.8v.7h-.8z" fill-rule="evenodd"/>
<path d="M229.6 141.1h.8v.7h-.8z" fill-rule="evenodd"/>
<path d="M177.6 148.7h.4l.1 .3-.5 .1z" fill-rule="evenodd"/>
<path d="M177.6 148.2h.6v.2l-.6 .1z" fill-rule="evenodd"/>
<path d="M177.6 147.6h.4l.1 .3-.5 .1z" fill-rule="evenodd"/>
<path d="M175.9 147.6h.5v.4h-.5z" fill-rule="evenodd"/>
<path d="M175.8 148.2h.5l.1 .2-.6 .1z" fill-rule="evenodd"/>
<path d="M175.9 148.7h.5v.3h-.5z" fill-rule="evenodd"/>
<path d="M184 131.5h.5v1.4l-.5-.1z" fill-rule="evenodd"/>
<path d="M185.9 131.5h.5v1.4l-.5-.1z" fill-rule="evenodd"/>
<path d="M184.9 129.6l.6 .1-.1 1.3-.5-.1z" fill-rule="evenodd"/>
<path d="M211.8 145.3h.8v.8h-.8z" fill-rule="evenodd"/>
<path d="M211.8 143.8h.8v.7h-.8z" fill-rule="evenodd"/>
<path d="M197.3 130l.4-.1 .1 .4h-.4z" fill-rule="evenodd"/>
<path d="M197.2 130.5h.6v.3h-.6z" fill-rule="evenodd"/>
<path d="M197.3 131h.4l.1 .3-.4 .1z" fill-rule="evenodd"/>
<path d="M199 131h.4l.1 .3-.4 .1z" fill-rule="evenodd"/>
<path d="M199 130.5h.6v.3h-.6z" fill-rule="evenodd"/>
<path d="M199 130l.4-.1 .1 .4h-.4z" fill-rule="evenodd"/>
<path d="M196.6 147.2h.8v.6h-.8z" fill-rule="evenodd"/>
<path d="M196.6 148.8h.8v.7h-.8z" fill-rule="evenodd"/>
<path d="M213.3 143.1h.8v.7h-.8z" fill-rule="evenodd"/>
<path d="M213.3 144.8h.8v.7h-.8z" fill-rule="evenodd"/>
<path d="M190 126.8h.8v.8h-.8z" fill-rule="evenodd"/>
<path d="M188.5 126.8h.7v.8h-.7z" fill-rule="evenodd"/>
<path d="M234.7 147.8l.4-.1 .1 .4h-.4z" fill-rule="evenodd"/>
<path d="M234.6 148.3h.6v.3h-.6z" fill-rule="evenodd"/>
<path d="M234.7 148.8h.4l.1 .3-.4 .1z" fill-rule="evenodd"/>
<path d="M236.4 148.8h.4l.1 .3-.4 .1z" fill-rule="evenodd"/>
<path d="M236.4 148.3h.6v.3h-.6z" fill-rule="evenodd"/>
<path d="M236.4 147.8l.4-.1 .1 .4h-.4z" fill-rule="evenodd"/>
<path d="M177.7 163.2h.8v.7h-.8z" fill-rule="evenodd"/>
<path d="M177.7 164.8h.8v.7h-.8z" fill-rule="evenodd"/>
<path d="M225.2 142.8h1.2v1.4h-1.2z" fill-rule="evenodd"/>
<path d="M225.2 145h1.2v1.4h-1.2z" fill-rule="evenodd"/>
<path d="M226.9 145h1.2v1.4h-1.2z" fill-rule="evenodd"/>
<path d="M226.9 142.8h1.2v1.4h-1.2z" fill-rule="evenodd"/>
<path d="M236.6 144.8h.8v.7h-.8z" fill-rule="evenodd"/>
<path d="M236.6 143.2h.8v.8h-.8z" fill-rule="evenodd"/>
<path d="M177.7 166.3h.8v.8h-.8z" fill-rule="evenodd"/>
<path d="M177.7 167.8h.8v.8h-.8z" fill-rule="evenodd"/>
<path d="M220.1 143.8h.2l-.1 .8-.2-.1z" fill-rule="evenodd"/>
<path d="M219.6 143.8h.2l-.1 .8-.2-.1z" fill-rule="evenodd"/>
<path d="M219.1 143.8h.2l-.1 .8-.2-.1z" fill-rule="evenodd"/>
<path d="M218.6 143.8h.2l-.1 .8-.2-.1z" fill-rule="evenodd"/>
<path d="M218.1 143.8h.2l-.1 .8-.2-.1z" fill-rule="evenodd"/>
<path d="M217.6 143.8h.2l-.1 .8-.2-.1z" fill-rule="evenodd"/>
<path d="M217.1 143.8h.2l-.1 .8-.2-.1z" fill-rule="evenodd"/>
<path d="M216.6 143.8h.2l-.1 .8-.2-.1z" fill-rule="evenodd"/>
<path d="M216.1 143.8h.2l-.1 .8-.2-.1z" fill-rule="evenodd"/>
<path d="M214.8 145h.8v.2h-.7z" fill-rule="evenodd"/>
<path d="M214.8 145.5h.8v.2h-.7z" fill-rule="evenodd"/>
<path d="M214.8 146h.8v.2h-.7z" fill-rule="evenodd"/>
<path d="M214.8 146.5h.8v.2h-.7z" fill-rule="evenodd"/>
<path d="M214.8 147h.8v.2h-.7z" fill-rule="evenodd"/>
<path d="M214.8 147.5h.8v.2h-.7z" fill-rule="evenodd"/>
<path d="M214.8 148h.8v.2h-.7z" fill-rule="evenodd"/>
<path d="M214.8 148.5h.8v.2h-.7z" fill-rule="evenodd"/>
<path d="M214.8 149h.8v.2h-.7z" fill-rule="evenodd"/>
<path d="M216.1 149.6l.2 .1-.1 .8-.2-.1z" fill-rule="evenodd"/>
<path d="M216.6 149.6l.2 .1-.1 .8-.2-.1z" fill-rule="evenodd"/>
<path d="M217.1 149.6l.2 .1-.1 .8-.2-.1z" fill-rule="evenodd"/>
<path d="M217.6 149.6l.2 .1-.1 .8-.2-.1z" fill-rule="evenodd"/>
<path d="M218.1 149.6l.2 .1-.1 .8-.2-.1z" fill-rule="evenodd"/>
<path d="M218.6 149.6l.2 .1-.1 .8-.2-.1z" fill-rule="evenodd"/>
<path d="M219.1 149.6l.2 .1-.1 .8-.2-.1z" fill-rule="evenodd"/>
<path d="M219.6 149.6l.2 .1-.1 .8-.2-.1z" fill-rule="evenodd"/>
<path d="M220.1 149.6l.2 .1-.1 .8-.2-.1z" fill-rule="evenodd"/>
<path d="M220.7 149h.8v.2h-.8z" fill-rule="evenodd"/>
<path d="M220.7 148.5h.8v.2h-.8z" fill-rule="evenodd"/>
<path d="M220.7 148h.8v.2h-.8z" fill-rule="evenodd"/>
<path d="M220.7 147.5h.8v.2h-.8z" fill-rule="evenodd"/>
<path d="M220.7 147h.8v.2h-.8z" fill-rule="evenodd"/>
<path d="M220.7 146.5h.8v.2h-.8z" fill-rule="evenodd"/>
<path d="M220.7 146h.8v.2h-.8z" fill-rule="evenodd"/>
<path d="M220.7 145.5h.8v.2h-.8z" fill-rule="evenodd"/>
<path d="M220.7 145h.8v.2h-.8z" fill-rule="evenodd"/>
<path d="M216.3 145.2h3.7v3.7h-3.7z" fill-rule="evenodd"/>
<path d="M227 137.8h.8v.8h-.8z" fill-rule="evenodd"/>
<path d="M225.5 137.8h.7v.8h-.7z" fill-rule="evenodd"/>
<path d="M200.3 168.8h.8v.8h-.8z" fill-rule="evenodd"/>
<path d="M200.3 167.2h.8v.8h-.8z" fill-rule="evenodd"/>
<path d="M190 165.8h1v.8h-1z" fill-rule="evenodd"/>
<path d="M190 168h1v.8h-1z" fill-rule="evenodd"/>
<path d="M197.2 165.8h1.1v.8h-1.1z" fill-rule="evenodd"/>
<path d="M197.2 168h1.1v.8h-1.1z" fill-rule="evenodd"/>
<path d="M191.5 164.8h.7v1.5h-.7z" fill-rule="evenodd"/>
<path d="M194.5 164.8h.7v1.5h-.7z" fill-rule="evenodd"/>
<path d="M196 164.8h.7v1.5h-.7z" fill-rule="evenodd"/>
<path d="M222.2 149.6h.6v.8h-.6z" fill-rule="evenodd"/>
<path d="M223.8 149.6h.7v.8h-.7z" fill-rule="evenodd"/>
<path d="M227 139.3h.8v.8h-.8z" fill-rule="evenodd"/>
<path d="M225.5 139.3h.7v.8h-.7z" fill-rule="evenodd"/>
<path d="M167.9 150.9h1.5v.3h-1.5z" fill-rule="evenodd"/>
<path d="M167.9 150.4h1.5v.3h-1.5z" fill-rule="evenodd"/>
<path d="M167.9 149.9h1.5v.3h-1.5z" fill-rule="evenodd"/>
<path d="M167.9 149.4h1.5v.3h-1.5z" fill-rule="evenodd"/>
<path d="M167.9 148.9h1.5v.3h-1.5z" fill-rule="evenodd"/>
<path d="M167.9 148.4h1.5v.3h-1.5z" fill-rule="evenodd"/>
<path d="M167.9 147.9h1.5v.3h-1.5z" fill-rule="evenodd"/>
<path d="M167.9 147.4h1.5v.3h-1.5z" fill-rule="evenodd"/>
<path d="M167.9 146.9h1.5v.3h-1.5z" fill-rule="evenodd"/>
<path d="M167.9 146.4h1.5v.3h-1.5z" fill-rule="evenodd"/>
<path d="M167.9 145.9h1.5v.3h-1.5z" fill-rule="evenodd"/>
<path d="M167.9 145.4h1.5v.3h-1.5z" fill-rule="evenodd"/>
<path d="M167.9 144.7h1.5v.5h-1.5z" fill-rule="evenodd"/>
<path d="M214.9 142.3h.7v.8h-.7z" fill-rule="evenodd"/>
<path d="M216.4 142.3h.8v.8h-.8z" fill-rule="evenodd"/>
<path d="M228.8 143.5h.8v.7h-.8z" fill-rule="evenodd"/>
<path d="M228.8 145h.8v.8h-.8z" fill-rule="evenodd"/>
<path d="M209.8 125.3h.8v2.4h-.8z" fill-rule="evenodd"/>
<path d="M209.8 129.2h.8v2.4h-.8z" fill-rule="evenodd"/>
<path d="M208.5 125.3h.8v2.4h-.8z" fill-rule="evenodd"/>
<path d="M208.5 129.2h.8v2.4h-.8z" fill-rule="evenodd"/>
<path d="M207.3 125.3h.7v2.4h-.7z" fill-rule="evenodd"/>
<path d="M207.3 129.2h.7v2.4h-.7z" fill-rule="evenodd"/>
<path d="M206 125.3h.7v2.4h-.7z" fill-rule="evenodd"/>
<path d="M206 129.2h.7v2.4h-.7z" fill-rule="evenodd"/>
<path d="M204.7 125.3h.8v2.4h-.8z" fill-rule="evenodd"/>
<path d="M204.7 129.2h.8v2.4h-.8z" fill-rule="evenodd"/>
<path d="M221.1 151.1h.7v.8h-.7z" fill-rule="evenodd"/>
<path d="M219.4 151.1h.7v.8h-.7z" fill-rule="evenodd"/>
<path d="M212.7 125.1h1.6v1.7h-1.6z" fill-rule="evenodd"/>
<path d="M189.8 124.6l.7-.1 .2 .2v.9l-.1 .3h-.7l-.2-.2z" fill-rule="evenodd"/>
<path d="M191.6 124.6l.7-.1 .2 .2v.9l-.1 .3h-.6l-.3-.2z" fill-rule="evenodd"/>
<path d="M191.3 127.7h.6v.2h-.6z" fill-rule="evenodd"/>
<path d="M191.8 127.5h.1v.3h-.1z" fill-rule="evenodd"/>
<path d="M191.3 128.1h.6v.2h-.6z" fill-rule="evenodd"/>
<path d="M191.3 128.5h.6v.2h-.6z" fill-rule="evenodd"/>
<path d="M191.3 128.9h.6v.2h-.6z" fill-rule="evenodd"/>
<path d="M191.3 129.3h.6v.2h-.6z" fill-rule="evenodd"/>
<path d="M192.2 129.1h.2v.6h-.2z" fill-rule="evenodd"/>
<path d="M192.6 129.3h.6v.2h-.6z" fill-rule="evenodd"/>
<path d="M192.6 128.9h.6v.2h-.6z" fill-rule="evenodd"/>
<path d="M192.6 128.5h.6v.2h-.6z" fill-rule="evenodd"/>
<path d="M192.6 128.1h.6v.2h-.6z" fill-rule="evenodd"/>
<path d="M192.6 127.7h.6v.2h-.6z" fill-rule="evenodd"/>
<path d="M192.2 127.5h.2v.6h-.2z" fill-rule="evenodd"/>
<path d="M219.3 168.8h.8v.8h-.8z" fill-rule="evenodd"/>
<path d="M219.3 167.2h.8v.8h-.8z" fill-rule="evenodd"/>
<path d="M223.8 143.4h.8v.7h-.8z" fill-rule="evenodd"/>
<path d="M223.8 145.1h.8v.7h-.8z" fill-rule="evenodd"/>
<path d="M175.8 146.1h.7v.8h-.7z" fill-rule="evenodd"/>
<path d="M177.5 146.1h.6v.8h-.6z" fill-rule="evenodd"/>
<path d="M193.8 126.8h.8v.8h-.8z" fill-rule="evenodd"/>
<path d="M195.4 126.8h.7v.8h-.7z" fill-rule="evenodd"/>
<path d="M195.1 148.7h.8v.8h-.8z" fill-rule="evenodd"/>
<path d="M195.1 147.2h.8v.7h-.8z" fill-rule="evenodd"/>
<path d="M221.2 142h.8v.7h-.8z" fill-rule="evenodd"/>
<path d="M221.2 140.3h.8v.7h-.8z" fill-rule="evenodd"/>
<path d="M196.6 150.3h.8v.8h-.8z" fill-rule="evenodd"/>
<path d="M195 150.3h.8v.8h-.8z" fill-rule="evenodd"/>
<path d="M200.3 131.3h.7v.8h-.7z" fill-rule="evenodd"/>
<path d="M202 131.3h.7v.8h-.7z" fill-rule="evenodd"/>
<path d="M198.2 147.3h.8v.7h-.8z" fill-rule="evenodd"/>
<path d="M198.2 145.7h.8v.8h-.8z" fill-rule="evenodd"/>
<path d="M227 141.3h.8v.8h-.8z" fill-rule="evenodd"/>
<path d="M225.4 141.3h.8v.8h-.8z" fill-rule="evenodd"/>
<path d="M217 136.3h.9v.8h-.9z" fill-rule="evenodd"/>
<path d="M217 134.8h.9v.8h-.9z" fill-rule="evenodd"/>
<path d="M220.9 136.4h1.2v.5l-1.2 .1z" fill-rule="evenodd"/>
<path d="M220.9 135.5l1.2-.1v.5l-1.2 .1z" fill-rule="evenodd"/>
<path d="M220.9 134.5h1.2v.5l-1.2 .1z" fill-rule="evenodd"/>
<path d="M218.6 134.5h1.2l.1 .5-1.3 .1z" fill-rule="evenodd"/>
<path d="M218.6 136.4h1.2l.1 .5-1.3 .1z" fill-rule="evenodd"/>
</g>
<g fill="#eedab5">
<circle cx="181.5" cy="130.3" r=".85"/>
<circle cx="211.4" cy="168.2" r=".85"/>
<circle cx="208.8" cy="168.2" r=".85"/>
<circle cx="241.3" cy="127.1" r=".4"/>
<circle cx="242" cy="125.4" r=".4"/>
<circle cx="242" cy="128.8" r=".4"/>
<circle cx="243.7" cy="124.7" r=".4"/>
<circle cx="243.7" cy="127.1" r="3.2"/>
<circle cx="243.7" cy="129.5" r=".4"/>
<circle cx="245.4" cy="125.4" r=".4"/>
<circle cx="245.4" cy="128.8" r=".4"/>
<circle cx="246.1" cy="127.1" r=".4"/>
<circle cx="169.3" cy="167.1" r=".4"/>
<circle cx="170" cy="165.4" r=".4"/>
<circle cx="170" cy="168.8" r=".4"/>
<circle cx="171.7" cy="164.7" r=".4"/>
<circle cx="171.7" cy="167.1" r="3.2"/>
<circle cx="171.7" cy="169.5" r=".4"/>
<circle cx="173.4" cy="165.4" r=".4"/>
<circle cx="173.4" cy="168.8" r=".4"/>
<circle cx="174.1" cy="167.1" r=".4"/>
<circle cx="213.5" cy="128.4" r=".85"/>
<circle cx="213.5" cy="131" r=".85"/>
<circle cx="169.3" cy="127.1" r=".4"/>
<circle cx="170" cy="125.4" r=".4"/>
<circle cx="170" cy="128.8" r=".4"/>
<circle cx="171.7" cy="124.7" r=".4"/>
<circle cx="171.7" cy="127.1" r="3.2"/>
<circle cx="171.7" cy="129.5" r=".4"/>
<circle cx="173.4" cy="125.4" r=".4"/>
<circle cx="173.4" cy="128.8" r=".4"/>
<circle cx="174.1" cy="127.1" r=".4"/>
<circle cx="227.4" cy="140.9" r=".22"/>
<circle cx="237" cy="142.8" r=".23"/>
<circle cx="232.9" cy="143.3" r=".23"/>
<circle cx="235.6" cy="148.5" r=".23"/>
<circle cx="196.6" cy="127.2" r=".22"/>
<circle cx="222.2" cy="153" r=".23"/>
<circle cx="178.7" cy="146.5" r=".23"/>
<circle cx="198.6" cy="146.9" r=".22"/>
<circle cx="207.6" cy="128" r=".23"/>
<circle cx="223.9" cy="135.8" r=".23"/>
<circle cx="178.1" cy="167.5" r=".22"/>
<circle cx="225.8" cy="146.7" r=".22"/>
<circle cx="196.2" cy="150.7" r=".23"/>
<circle cx="218.8" cy="150.9" r=".23"/>
<circle cx="196.4" cy="125.2" r=".22"/>
<circle cx="223.1" cy="141.5" r=".22"/>
<circle cx="198.2" cy="131" r=".23"/>
<circle cx="230" cy="140.7" r=".22"/>
<circle cx="217.4" cy="135.9" r=".22"/>
<circle cx="203.3" cy="126.3" r=".22"/>
<circle cx="222.4" cy="135.7" r=".22"/>
<circle cx="226.6" cy="139.7" r=".23"/>
<circle cx="212.2" cy="144.9" r=".22"/>
<circle cx="226.6" cy="138.2" r=".23"/>
<circle cx="192.3" cy="130" r=".22"/>
<circle cx="229.2" cy="144.6" r=".23"/>
<circle cx="216.1" cy="142.7" r=".22"/>
<circle cx="213.7" cy="150.3" r=".23"/>
<circle cx="169.8" cy="145.1" r=".23"/>
<circle cx="224.1" cy="150.9" r=".23"/>
<circle cx="239.5" cy="145.8" r=".23"/>
<circle cx="204.7" cy="150.5" r=".23"/>
<circle cx="221.6" cy="141.5" r=".22"/>
<circle cx="188" cy="127.2" r=".22"/>
<circle cx="219.7" cy="168.4" r=".22"/>
<circle cx="241.4" cy="142.1" r=".23"/>
<circle cx="169.8" cy="151.5" r=".22"/>
<circle cx="226.5" cy="133.3" r=".22"/>
<circle cx="177" cy="150.2" r=".23"/>
<circle cx="178.6" cy="148.3" r=".22"/>
<circle cx="239.3" cy="154.6" r=".22"/>
<circle cx="227.5" cy="144.5" r=".23"/>
<circle cx="195.5" cy="148.2" r=".23"/>
<circle cx="239.6" cy="151.1" r=".22"/>
<circle cx="194.9" cy="166.7" r=".23"/>
<circle cx="189.6" cy="138.1" r=".22"/>
<circle cx="189.6" cy="130.3" r=".22"/>
<circle cx="189.6" cy="127.2" r=".22"/>
<circle cx="213.5" cy="138.1" r=".23"/>
<circle cx="209" cy="152" r=".22"/>
<circle cx="195.2" cy="133.2" r=".22"/>
<circle cx="195.2" cy="128.6" r=".22"/>
<circle cx="193.2" cy="150.9" r=".23"/>
<circle cx="193.2" cy="139.9" r=".22"/>
<circle cx="233.3" cy="148.9" r=".22"/>
<circle cx="234.3" cy="147.9" r=".23"/>
<circle cx="187.7" cy="129.6" r=".22"/>
<circle cx="171.4" cy="145.2" r=".22"/>
<circle cx="171.4" cy="150.1" r=".22"/>
<circle cx="170.9" cy="144.7" r=".22"/>
<circle cx="190.6" cy="129" r=".22"/>
<circle cx="170.9" cy="150.6" r=".22"/>
<circle cx="187.6" cy="129" r=".22"/>
<circle cx="187.3" cy="132.2" r=".23"/>
<circle cx="201.5" cy="164.6" r=".22"/>
<circle cx="235.4" cy="146.1" r=".4"/>
<circle cx="237.3" cy="147.1" r=".23"/>
<circle cx="237.3" cy="148.5" r=".23"/>
<circle cx="220.8" cy="150" r=".22"/>
<circle cx="237.3" cy="149.6" r=".23"/>
<circle cx="172.2" cy="149.1" r=".23"/>
<circle cx="172.2" cy="147.6" r=".23"/>
<circle cx="183" cy="131.1" r=".23"/>
<circle cx="185.9" cy="128.2" r=".22"/>
<circle cx="183" cy="139.5" r=".22"/>
<circle cx="220.3" cy="142.5" r=".22"/>
<circle cx="219.7" cy="143.1" r=".23"/>
<circle cx="213.7" cy="144.3" r=".22"/>
<circle cx="235.4" cy="141.4" r=".23"/>
<circle cx="173.1" cy="146.6" r=".23"/>
<circle cx="181.8" cy="157.8" r=".22"/>
<circle cx="180.8" cy="156.6" r=".22"/>
<circle cx="201.9" cy="159.7" r=".23"/>
<circle cx="180.8" cy="159.7" r=".23"/>
<circle cx="173.7" cy="146.1" r=".23"/>
<circle cx="205.4" cy="151.2" r=".22"/>
<circle cx="198.6" cy="126.3" r=".22"/>
<circle cx="198.6" cy="129.5" r=".22"/>
<circle cx="195.6" cy="165.5" r=".23"/>
<circle cx="185.1" cy="134" r=".23"/>
<circle cx="200.7" cy="168.4" r=".22"/>
<circle cx="194.4" cy="129.2" r=".22"/>
<circle cx="193.9" cy="129.7" r=".23"/>
<circle cx="234.1" cy="142.3" r=".23"/>
<circle cx="214.4" cy="146.6" r=".23"/>
<circle cx="203.5" cy="130.1" r=".22"/>
<circle cx="208.9" cy="128.8" r=".22"/>
<circle cx="238.5" cy="153.6" r=".22"/>
<circle cx="239.4" cy="149.1" r=".23"/>
<circle cx="176.2" cy="144.6" r=".22"/>
<circle cx="170.2" cy="133.1" r=".23"/>
<circle cx="170.2" cy="147.1" r=".22"/>
<circle cx="169.9" cy="149.6" r=".22"/>
<circle cx="238" cy="148.6" r=".23"/>
<circle cx="241.1" cy="148.3" r=".22"/>
<circle cx="174.6" cy="148.5" r=".23"/>
<circle cx="175.3" cy="147.8" r=".22"/>
<circle cx="174" cy="148.5" r=".23"/>
</g>
<g fill="none" stroke="#eedab5" stroke-width=".2">
<path d="M170.2 133.1h9.1M178.9 130.3v1.1l.4 .4v1.3M179.3 133.1h.1M181.5 130.3v1.4l-.4 .3v1.1M181.5 130.3h.1M181.5 130.3h3.7M183 131.1v8.4M184.2 132.2l.1 1.8h.8M185.9 128.2h5.7v.4M187.3 132.2h-1.2v.8l-.2 .2v9.3l-.7 .7h-7.3l-1 1v3.8l-.4 .3h-.4M187.6 129h4M188 127.2h.9"/>
<path d="M189.6 127.2h1.4l.6 .6M189.6 130.3v7.8M190.2 125.2l.2 2M191.6 129.4h-.7l-.2 .2-3 .1M192.3 129.4v.6M192.9 127.8h.7l1.5-1.5h5.9v-.9l.7-.7h8.2l.3 .3v1.5h1.4l1.9 1.9M192.9 128.2v.4h10.4l1.8 1.8M192.9 129.4h.7l.3 .3h1.1l1.5 1.5h1M192.9 129l2.3 .2 .9 .9h1.4M193.6 125.2h-1.6v1.2l.3 .3v1.1M195.2 133.2l-2 2v4.7M195.4 125.2h1"/>
<path d="M195.8 127.2h.8M197.5 130.7h.4l.2 .2M198.6 129.5v.7l.5 .5h.2M199.3 131.2h.3l.5 .5h.6l-.2 .2M199.3 130.1h1.4M202.3 130.1h1.2M202.5 126.3h.8M202.5 127.7h-1.5v.6l-.3 .3M208.9 126.5h-1.3v1.5M208.9 128.8v1.6M210.2 130.4v1.5l-.4 .4h-5.4l-.6-.6h-1.5M213.5 131v7.1h2.6l1.4-1.4h1.7"/>
<path d="M217.5 135.2v.7M221.6 135.7h.8M221.6 134.8h-.7l-.3 .3v1.3l.2 .3h.8M223.9 135v.8M225.5 136.5l-1.6 .1M225.8 138.2h.8M225.8 139.7h.8M226.5 133.3v.9M227.4 136.5v3.2M227.4 138.2h.1M228 132.1l-.6 .6v2.1l-.3 .3h-1.3l-.3-.2v-.7M230.9 139.7l-.1 .1"/>
<path d="M231.6 139.7l-1.6 .1M234.1 139.7v2.6M235.4 139.7v1.7M238 134.1l-2-2h-13.7l-.8 .8v1.9M238 134.2v10M168.6 144.9v.7h.7l.4-.4M168.6 149.1h2.9l.5 .5h1.9l.6 .6h1.7M168.6 151.1l.5 .4h.7M168.6 150.1h2.8M168.6 150.6h2.3M168.6 149.6h1.3M168.6 147.1h1.6"/>
<path d="M168.6 147.6h3.6M168.6 146.6h4.5M168.6 146.1h5.1M176.2 144.6v1.9M177 150.2h.8M177.8 146.5h.9M177.9 148.3h.7M180.8 156.6v3.1h21.1M193.2 150.9h-10.9l-2.4 2.4v12.9l-.5 .5h-1.3v-1.5M195.4 150.7h.8M195.5 147.6v.6M195.5 149.1l2.4 .1 .6 .6v.3"/>
<path d="M197 150.7h1.5M198.6 146.1v.8M198.6 147.6v1.2l.3 .3h.6M200.8 153.5l8 8v6.7M200.8 153.5l-4.4 4.4h-14.6M200.8 153v.5M202.4 152h6.6M202.4 151.3h1.9l.2-.1h5l4.4 4.4v12.6M204.7 150.5h-1.5l-.2 .2h-1.2l-.4 .3h-.9v.6l-1 1v.4M212.2 144.1v.8M212.2 145.7l.9 .9h.6l.5 .5h1M213.6 149.5l.1 .8"/>
<path d="M213.7 144.3v.8l1 1h.5M214.4 146.6h.8M215.2 147.6h-.6l-.3 .3h-.7M215.2 142.5v2.6M216.1 142.7h.7M216.7 147.1h1.5M217.7 150v.5l-.4 .3v.7M218.2 147.1l-1 1h-2M218.2 147.1v1.3l1 1v.6h-.5v.7l.1 .2M219.7 150v.5l.1 .2v2.3M220.2 150h.6M221.1 149.1h.5l.9 .9v1.4l1 1v1.4l-3.8 3.8v7"/>
<path d="M221.4 153h.8M221.6 140.7v.8M221.6 142.3v1l.5 .5v1.4l-.4 .4h-.6M223.1 140.7v.8M223.1 142.3v.8l-.6 .6v1.6l-.8 .8h-.6M224.2 150v.9M225.8 145.7v1M225.8 141.7v1.8h-.7l-.2 .3h-1.1l-.5 .5v1.2l-1.1 1.1h-1.1M225.8 142.4h.1M227.4 140.9v.8M227.5 143.5v1M229.2 145.4h-.6l-.3 .3h-.8v-.3l-.7-.7h-1.9l-2.4 2.4h-1.4"/>
<path d="M229.2 143.9v.7M230 140.7v.7M232.9 143.3v1.4M234.1 144.7v1.5l.9 .9h4.5l.2 .2h.7M234.9 148.5h.7M235.4 141.4h.1M236.7 148.5h.6M237 142.8v.8M237 145.2v1.2l.3 .3v.4M237.3 149.6h2.3l.2 .2h.6M238 144.1l-1 1.1M238.5 153.6v1"/>
<path d="M238.7 151.1h.9l.2 .2h.6M238.7 145.6h.6l.2 .2h.9M238.7 149.1h.7M239.3 154.6h.8M240.6 142.1h.8M242.2 142.1v4.5l-1.2 1.2h-.6M178.1 167.5v.7h1.8M194.9 165.5v1.2M195.6 165.5h.7M200.7 164.6h.8M200.7 166.2v1.4M200.7 168.4v.8"/>
<path d="M219.7 166.2v1.4M219.7 168.4v.8"/>
</g>
<g fill="none" stroke="#eedab5" stroke-width=".18">
<path d="M168.6 148.1h5l.4 .4 .3-.4h.5l.8 .8h.5M174.6 148.5l-.5 .5h-.3l-.4-.4h-4.8M175.3 147.8h.8M218.7 144.2l.1-1.2-2.1-2.1h-11.2l-4.9 4.9v2.5l.2 .1v.7M219.2 144.2l-.1-1.3-2.2-2.2h-11.6l-5 5v2.6l-.1 .1v.7M219.7 143.1v1.1M220.2 144.2v-1.2l-.4-.4v-1.8l-1.6-1.6h-20.8l-9.3 9.3h-8.8l-.4 .4h-1.1M220.3 142.5l-.2-.3v-1.5l-1.7-1.7h-21.2l-9.2 9.2h-8.7l-.4-.4h-1.1M221.1 148.1l2.6-.1 .6 .6h8.8l.2 .3M221.1 147.6l2.7 .1 .7 .7h9.2l.6 .6h.6M234.3 147.9h.6M236.7 147.9l2.5 .2 .7 .7h.5"/>
<path d="M238.7 148.6h-.7l-.4 .4h-.9M240.4 148.3h.7"/>
</g>
<path d="M235.4 144.7v1.4" fill="none" stroke="#eedab5" stroke-width=".4"/>
<path d="M168.4 123.8l.6-.5 .7-.1h76.2a1.9 1.9 0 0 1 1.7 1.9v44.2a1.9 1.9 0 0 1-1.9 1.7h-76.2a1.91 1.91 0 0 1-1.7-1.9v-2.2h.6a3.3 3.3 0 0 0 4.4 3.4 3.3 3.3 0 0 0 1.4-5.4h3.3v.6l.4 .3v.3l-.4 .3v.6l.3 .3-.3 .7v.6l.3 .2h.7l.2-.4h.2l.2 .6h1.5l.1-1.5h6.2v1.4l.1 .1h1.6l.1-1h1.1v.8l.1 .1h1.1l.1-.9h6l.1 .9h1.1l.1-.1v-.8l-.1-.1h-1.1l-.1 .1h-6l-.1-.1-2.3 .1-.1-.6h-1.6l-.1 .1-7.8-.1-.1 .6a.49 .49 0 0 1-.5-.8h13.5v.2a.55 .55 0 0 0 .9 .4 .55 .55 0 0 0 0-1 .55 .55 0 0 0-.9 .4h-13.5l.2-.3h.8l.5-.6 .1-.5h9.7l.1 .9h1.1l.1-.1v-.8l-.1-.1h-1.1l-.1 .1h-9.7v-1h11.3v1.5l.1 .1 .8-.1v-1.5h2.1v1.5l.1 .1a.42 .42 0 0 0 .1 .5 .42 .42 0 0 0 .5 .1 .57 .57 0 0 0 .4 .9 .57 .57 0 0 0 .6-.8 .57 .57 0 0 0-.9-.2l-.1-.4 .2-.2 .1-.5 .5 .1 .1 .5h.7l.1-.1v-.5h.3v.8l.1 .1h1.1l.1-.7h1.7v.5l.4 .3v.2l-.4 .3v.6l.3 .3v.4l-.3 .3v.6l.3 .3 .6-.1 .3-.2v-.6l-.3-.3v-.4l.3-.3v-.6l-.4-.3v-.2l.4-.3-.1-.7-.1-.1h-.7l-.3 .3h-1.7l-.1-.3-1.5 .1-.1-1.1h-.7l-.1 .5h-.5l-.2-.5h-.7l-.1 .1h-2.1l-.1-.1h-.7l-.1 .1h-11.3v-.3l.6-.1v-1.4h6.2v1.4l.1 .1h1.6l.1-.2h11.4v.6l.1 .1 .8 .1 .2-.1a.46 .46 0 0 0 .6-.6l-.8-.4-.7 .1-.2 .2h-11.4v-1.3l-.1-.1h-1.6l-.1 .1h-6.2l-.6-.1v-6.3h.4l.1 .3v2.5a.36 .36 0 0 0 0 .6 .36 .36 0 0 0 .5-.1h20.5a.36 .36 0 0 0 .6 0 .36 .36 0 0 0-.1-.5 .36 .36 0 0 0-.5 .1h-20.5l-.1-1.7h.4a.37 .37 0 0 0 .3 .4 .37 .37 0 0 0 .4-.1h14.3l4.4-4.3 7.8 7.7v5.7a.98 .98 0 0 0-.7 1.2 .98 .98 0 0 0 1.1 .8 .98 .98 0 0 0 .8-1.1h.6v.2a.98 .98 0 0 0 1.5 .7 .98 .98 0 0 0 0-1.6 .98 .98 0 0 0-1.5 .7l-.6-.1a1.17 1.17 0 0 0-.8-.8v-5.9l-7.7-7.7 .4-.2v-.9l-.4-.1-.2 .2-.4-.2-.2 .2-.5-.2 .2-.2h1.4l.1-1.1 .2-.2 .1 .1-.1 .3 .1 .4h-.1v.5l1.3 .1 .3 .3h.8l.3-.3h4.1a.36 .36 0 0 0 .5 0 .36 .36 0 0 0 0-.5 .36 .36 0 0 0-.5 0h-4.1l-.2-.2 .2-.2 .8 .1 .3-.1h3.7l4.3 4.3v11.5l-.8 .1 .1 1.9 1.9-.1v-1.8l-.8-.1v-1.2h5v.5l.4 .3v.2l-.4 .4v.5l.3 .3v.4l-.3 .3v.5l.3 .4 .6-.1 .3-.2v-.6l-.3-.3v-.4l.3-.3v-.6h11v1.9l.2 .2h8.2l.2-.2v-1.9l-.2-.2h-8.2l-.2 .2h-11l-.4-.4h20.5a3.3 3.3 0 0 0 4.7 3.2 3.3 3.3 0 0 0 .6-5.7 3.3 3.3 0 0 0-5.3 2.2v.3h-20.5l.4-.4v-.6l-.2-.2h-.8l-.2 .3h-5v-1.7h5v.6l.1 .1 .8 .1 .2-.1 .1-.7-.4-.3v-6.3l3.4-3.4h14.7v.7l.2 .2h.6l.3-.3h.5l.2 .3h.6l.2-.1 .1-.8-.2-.2-.7-.1-.2 .3h-.5l-.4-.3a.41 .41 0 0 0 .1-.5 .41 .41 0 0 0-.5-.2l-.2 .3 .2 .3-.3 .4h-14.7l.4-.4v-1.5h16.1l.1 .4 .3 .2h.8l.4-.3h4.3l.1 .4 .3 .2h.8a.53 .53 0 0 0 .5-.5 .53 .53 0 0 0-.5-.5h-.8l-.4 .4h-4.3a.52 .52 0 0 0-.4-.8l-.9 .1-.3 .4h-16.1l-1-1.1v-.6l.3-.3v-.7h.6v.7l.3 .2a.38 .38 0 0 0 0 .5 .38 .38 0 0 0 .5 0 .38 .38 0 0 0 0-.5l.3-.3v-.7l-.2-.1-.6-.1-.3 .3h-.6l-.2-.3h-.6l-.6-.5v-.2h-1v.6l.9 .1 .5 .4v.6l.3 .3v.8l.9 1v1.2l-3.7 3.9v6.4l-.4 .3h-5v-8.8l-2.1-2.1h4.7l.2 .2h.7l.2-.1 .1-.3h-.5v.4h-.2v-.4h-.5v.2h-4.7l-.5-.5h5.2v.2h1.2l-.1-.4-.4-.1v.5h-.2v-.5l-.4 .1-.1 .2h-5.2l-2-2h-5a.39 .39 0 0 0 .5-.3 .39 .39 0 0 0-.3-.5l-.4-.2h-.7l-.3 .3-.3 .1-.1-.5h-.9a.32 .32 0 0 0 0 .5v.2h-.3l-.2-.7-2.2 .1v2.2l.1 .2-.2 .3v.8l.4 .1 .2-.1 .5 .2-4 4h-14.3a.35 .35 0 0 0-.6 .2h-.4v-.9a.36 .36 0 0 0 0-.6 .36 .36 0 0 0-.5 .3h-.4v-3.1l2.3-2.4h10.5a.36 .36 0 0 0 .5 .1 .36 .36 0 0 0 0-.6 .36 .36 0 0 0-.5 .1h-10.7l-2.6 2.6v9.6l-.6 .1v1.4l.6 .1v1.6l-.3 .3h-.5l-.4-.3v-.4l.3-.3v-.5l-.2-.2h-.7l-.3 .2h-3.3a3.3 3.3 0 0 0-3.6-.9 3.3 3.3 0 0 0-2.2 2.9h-.6v-3.1h9.7l.3 .2h.7l.2-.2v-.2h-.5v.4h-.1v-.4h-.6v.2h-9.7v-.5h9.7v.2h1.2v-.4l-.3-.1h-.2v.5h-.1v-.5l-.4 .1-.2 .2h-9.7v-10.4l1.6-.2v-.7h-1.3l-.3-.2v-.4l.8-.1 .4 .4h.5a.38 .38 0 0 0 .5 0 .38 .38 0 0 0 .1-.5 .38 .38 0 0 0-.6 0v-.4h1.1a.4 .4 0 0 0 .5 .1 .4 .4 0 0 0 .2-.5 .36 .36 0 0 0 .4-.4 .36 .36 0 0 0-.6-.2h-.9v-.5h1.2l.6 .5h1.8l.6 .6h1.2l.3 .4h.5l.3-.3h.5l.3 .3h.6l.2-.4h16.5l.1 .7 .1 .1 .8 .1a.58 .58 0 0 1 .9 0h.2v-1.2h-.3a.5 .5 0 0 1-.4 .3 .5 .5 0 0 1-.4-.3h-.7l-.3 .3h-16.5v-.6l-.2-.2h-.6l-.2 .3h-.6l-.3-.3h-.5l-.3 .4h-1l-.7-.6-1.4-.1v-.5h.8l.4 .4h.5l.8-.6 .5 .5 .9 .1 .1-.2v-.4l.6-.5v-.4h.4v1.3l.2 .2 1.2-.1 .5-.4h8.8l1.4-1.4h5.3v.6a.51 .51 0 0 1 0 .9v.6l.2 .3h.8l.3-.4h.2l.3 .4h.7l.2-.3h.2l.3 .3-.1 .3v.3h-.4l-.3-.2h-.3v1.2h.3l.3-.2h.4v.4l.1 .2-.1 .1v.4l1 .1 .1-.2-.2-.4 .2-.3v-1.4l-.6-.6h.7l.2 .2v-.5h-.2v.3h-.7l-.5-.4-.4-.1-.1-.2h1.7v.3h.2v-.5l-.2 .2-2.6-.1a.32 .32 0 0 1-.5 .2 .58 .58 0 0 1 0-1l.3-.1 .3 .3 1.3-.1 .3 .3h.7l.2-.3v-.2h-.5v.5h-.2v-.5h-.5v.2h-.5l.1-.3h-.5v.4h-.2v-.4h-.5v.1h-.3v-.4h.3v.1h1.2l-.1-.3-.2-.1h-.2v.4h-.2v-.4h-.4l-.1 .3h-.3l-.2-.3h-.7l-.3 .3h-5.3l1.5-1.5h6.9v.6l.3 .3v.3l-.2 .2-.1 .4h1.2l-.1-.4-.2-.1v-.4l.3-.3v-.6l-.2-.3h-.8l-.2 .3h-6.9l6.4-6.3h20.7l1.4 1.4v1.8l-.3 .2-2.4-2.5h-11.6l-5.2 5.2v2.5l-.2 .6-.3-.2v1.1l.2-.2 .3 .2 .4-.1 .2 .1 .4-.1 .4 .1 .2-.1v-.3h11.3v.6l.4 .3a.41 .41 0 0 0 .1 .4 .41 .41 0 0 0 .5 0v-.5l.2-.3h1.7l.1 .8h.9l.2 .1v.3l-.4 .3 .1 .7 .1 .1h.8l.2-.2v-.6l-.3-.3 .3-.4 .2 .1v-1.1l-3.9 .2v-.6l-.3-.2h-.6l-.3 .3h-11.3v-.6a.32 .32 0 0 0-.5 .1h-.1l-.3-.5h12.2l.2 .2 .4 .1v-.5h-.6v.2l-12.2-.1v-.4h12.2v.2h.6v-.6l-.4 .1-.2 .3h-12.2l.1-1.8 1.9-2h8.8v.5a.66 .66 0 0 1 0 1v.6l.1 .2 .7 .1 .5 .5h.7l.4 .5h-.3v1.2l.4-.1 .6-.5v1.3l.1 .1h.9l.1-1h.4l.1 .8h2.2l.3 .3-.4 .2-.2-.1v1.1l.2-.1v.3a.39 .39 0 0 0 .5 .4 .39 .39 0 0 0 .2-.6l.3-.1 .2 .3-.4 .4 .1 .7 .3 .5-.3 .2v.8l.1 .1h.9l.1-.1v-.7h.4v.7l.3 .2h.6l.3-.3a.39 .39 0 0 0 .5-.3 .39 .39 0 0 0-.5-.3l-.3-.3h-.6l-.3 .3h-.4l-.3-.3v-.3l.2-.3h.6l.3 .3h.5l.2-.2v-.3h-.4v.5h-.1v-.5h-.5v.2h-.6v-.6h.6v.2h1v-.3l-.2-.2h-.2v.5h-.1v-.5l-.4 .1-.1 .2h-.6l-.3-.3v-.3l.4-.1 .1-.2a.37 .37 0 0 0 .5 0 .37 .37 0 0 0 0-.5 .37 .37 0 0 0-.5 0l-.2-.3h-.9l-.2-.4 .9-.1v-3.5h.5v.3v2.7h1v-.2l.3-.1h1.7l.7 .7h8.7a.39 .39 0 0 0 .4 .3 .39 .39 0 0 0 .3-.4l.5 .4 .6 .1h.5v-.5a.39 .39 0 0 0 .6-.3 .39 .39 0 0 0-.6-.4l-.1-.5-.6 .1a.39 .39 0 0 0-.6 .1 .39 .39 0 0 0 .4 .5v.5l-.7-.7h-9.1l-.7-.6h-2l-.1-.1 .9-.1 1.3-1.3 .7-.1 .1-.2v-.6l.2-.1 .1 1.5 .3 .1a.39 .39 0 0 0 .4 .5 .39 .39 0 0 0 .4-.5l.3-.1 .1-1.5h.2l.1 1.5h1.2l.1-.5 .4-.2 .3 .2 .8-.1 .1-.2v-.6l-.3-.3v-.3l.3-.3v-.4h1.4v1.8l.2 .2h.5l.1-.2v-1.8h.4l.1 1.8 .1 .2h.4l.3-.2v-1.8l-.2-.2 .1-.3h3.2v.6l.1 .2 .8 .1 .3-.3v-.6l-.3-.3a.39 .39 0 0 0-.3-.5 .39 .39 0 0 0-.3 .5l-.3 .3h-3.2a.37 .37 0 0 0-.5-.3 .37 .37 0 0 0-.1 .6l-.2 .2h-.4l-.2-.2h-.5l-.1 .2h-1.4l-.1-.5h-.9l-.2 .2v.6l.3 .3v.4l-.6 .6-.1-.5-.5-.1 .1-.4 .4-.1v-1.5l-1.3-.1-.1 .1v1.4l.3 .2v.3l-.3-.2h-1.9l-.5 .4h-.6l-.2 .2-.1-.7 .2-.2 .9 .1 .4-.3 .2 .3h1.3v-1.5l-.5-.2 .1-.3 .3-.2v-.7h.4v.7l.1 .2h.8l.2-.2 .1-.7-.3-.3a.38 .38 0 0 0-.4-.5 .38 .38 0 0 0-.3 .5l-.2 .3h-.4l-.3-.3h-.6l-.2 .2v.8l.3 .2v.4h-.5v.5l-.3 .3-.3-.3-.7 .1-.1 .1-.1 .3-.5 .6v1.1l-1 1h-.2v-.1l.8-.9v-1.6l.6-.6 .1-.3 .3-.3v-.8a.44 .44 0 0 1-.3-.4 .44 .44 0 0 1 .3-.3v-.7l-.1-.2-.8-.1-.2 .2-.1 .8 .3 .2v.4l-.3 .2v.6l.4 .5-.6 .6-.5-.4v-.3l.4-.3v-.6l-.3-.3v-.5l.3-.2-.1-.7-.2-.2-.8 .1-.1 .2v.6a.72 .72 0 0 1 .2 .8l-.2 .2v.6l.4 .3v.5l.5 .5v1.3l-.2 .1-.1-.1h-1v.3h-.5l-.1-.4h-3.7l-.2 2.8h-.3v-.5l-.1-.1 .1-2.3h5.8l-.1-.2h-.3v.2h-.2v-.2l-.3 .1-.1 .1h-4.8v-.3l-.3-.1v-.8h.4v.7l.1 .2h2.1v-1.1h-2l-.2 .2h-.4l.1-.5a.59 .59 0 0 1 .9 0h.6l.2-.1 .1-.8-.2-.2-.7-.1-.3 .3h-.3l-.2-.2-.4-.1v.6l-.6 .1v.4l.3 .2v1.2l-.3 .1-.1 1-.3-.3-.1-.7-.2-.2v-.5l.2-.1 .1-.4h-1.2l.1 .4 .1 .1a.79 .79 0 0 1-.2 .9v.5l.1 .2 .8 .1 .4 .4-.4 .4-.3-.1h-.5l-.4-.4v-.6l-.3-.3v-.4l.3-.2v-.6l-.3-.3h-.7l-.2 .3h-8.8l.7-.7h9.6v.2h1.2l-.1-.3-.2-.2h-.2v.5h-.2v-.5l-.4 .1-.1 .2h-9.6l.8-.8h10.4v.3h.5v-.6l-.4 .1-.1 .2h-10.4l1.3-1.2h11l1.9 1.8-.1 .7-.2-.1v1.1l2.2-.1v-1.7a.43 .43 0 0 0 .2-.5 .43 .43 0 0 0-.3-.3l-.1-1.6-1.1-1.1h6.2v.7l.1 .1h.9a.46 .46 0 0 1 .8 .1h.6l.3-.2v-.3h-.5v.5h-.2v-.7l2.1-.1 .1 .7 .3 .2-.1 .5-.3 .2v.6l.2 .2h.8l.2-.2v-.5l-.3-.3-.1-.6 .3-.1 .1-.2h.5l.1 .8h.7l.1-.2v-1.7h.4l.1 1.8 .1 .1h.5l.2-.2v-1.7h.4v1.7l.2 .3v1.1a.36 .36 0 0 0 0 .5 .36 .36 0 0 0 .5 0 .36 .36 0 0 0 0-.5v-1.1l.2-.3v-1.7h.4v1.7l.2 .3v.2a.36 .36 0 0 0 0 .6 .36 .36 0 0 0 .5-.1 .36 .36 0 0 0-.1-.5l.2-.5v-1.7l-.2-.3-.5 .1-.1 .2h-.4l-.3-.3-.4 .1-.2 .2h-.4l-.3-.3-.4 .1-.2 .2h-.4l-.1-.2-.5-.1-.2 .2v.7h-.5l-.4-.3-.7 .1-.2 .2h-1.4l-.2-.3-.3-.1v.5h-.2v-.5l-.3 .1-.2 .2h-.4l-.2-.3h-.6l-.3 .3h-6.2l-.7-.7h-21.2l-9.3 9.3h-8.5l-.4-.4-1.3-.1-.2 .2h-.4v-1.5h.2v.7l.2 .2h.6l.2-.4a.39 .39 0 0 0 .6 .1 .39 .39 0 0 0 0-.6 .39 .39 0 0 0-.6 .1l-.3-.4h-.5l-.4 .3v-1.9l.9-.9h7.3l.9-.9v-2.6h6.6a.36 .36 0 0 0 .5 .3 .36 .36 0 0 0 .1-.6v-4.3l1.8-1.8a.36 .36 0 0 0 .3-.3 .36 .36 0 0 0-.4-.4 .36 .36 0 0 0-.3 .4l-1.8 2v4.4l-.2 .3h-6.6v-5.2l.3-.4-.1-.7-.2-.3 .4-.4v-.5h.4a.36 .36 0 0 0 .6 0 .36 .36 0 0 0-.1-.5 .36 .36 0 0 0-.5 0h-.4v-.4l-.2-.2-.6 .1v1.6l-.2 .4a.62 .62 0 0 1-.8 .2l-.3-.3 .2-.5v-1.3l-.2-.2h-.5l-.2 .3v1.2l.2 .5-.2 .3v.9l.2 .1h.6l.2-.3h.6l.3 .4v7.7l-.6 .6h-7.2l-1.2 1.1-.1 1.9-.2-.2v-.9a.36 .36 0 0 0 0-.6 .36 .36 0 0 0-.5 .1 .36 .36 0 0 0 0 .5v.9l-.3 .3v.8l.3 .2 .8-.1v.9l-.2 .1-.1-.5-.8 .1a.41 .41 0 0 0-.5-.1 .41 .41 0 0 0-.2 .4h-.6l-.4 .2-.3-.2-1.1-.1a.37 .37 0 0 0-.1-.5 .37 .37 0 0 0-.5 0h-1.3l-.1-.5h2.3a.41 .41 0 0 0 .5 .1 .41 .41 0 0 0 .2-.5 .36 .36 0 0 0 .5-.1 .36 .36 0 0 0-.1-.5 .36 .36 0 0 0-.5 0h-3.9l.2-.3a.35 .35 0 0 0 .4-.4 .35 .35 0 0 0-.5-.3l-.1-.1h1.1l.1 .3 .4 .1a.37 .37 0 0 0 .4 .4 .37 .37 0 0 0 .3-.5 .37 .37 0 0 0-.6-.2l.1-.1a.35 .35 0 0 0-.4-.4 .35 .35 0 0 0-.3 .4h-1.1l-.2-.9h-1.5v-10.7h2.1a.37 .37 0 0 0 .2 .3 .37 .37 0 0 0 .4-.1h8.1a.48 .48 0 0 0 .4 .6h.7l.2-.1v-1.2h.6v1l.1 .3h1l.2-.3-.1-1.1-.4-.4 .4-.3v-.6l.4-.1h.5l.2 .3v7.8a.36 .36 0 0 0-.1 .5 .36 .36 0 0 0 .6 0 .36 .36 0 0 0-.1-.5v-7.8a.35 .35 0 0 0 0-.6 .35 .35 0 0 0-.6 .3h-.5l.4-.6h2.2l.2 .6 .5 .1 .2-.2v-.7h3.7l.1 .3v7.2a.36 .36 0 0 0 0 .5 .36 .36 0 0 0 .5 0 .36 .36 0 0 0 0-.5v-7.2a.35 .35 0 0 0-.1-.6 .35 .35 0 0 0-.5 .3h-3.7v-.7l-.2-.2-.5 .1-.2 .6h-2.3a1 1 0 0 0-1.7-.5 1 1 0 0 0 .5 1.7l-.3 1h-.3l-.1 .3h-.6l-.3-.3-.1-.6-.3-.4 .7-.1v-1.8l-1.9-.1v1.9l.7 .1v.2l.4 .4-.1 .4a.43 .43 0 0 0-.4 .6l-8.2-.1a.35 .35 0 0 0-.5 .3h-2.1v-6.2h.6v.4a3.3 3.3 0 0 0 2.8 3.1 3.3 3.3 0 0 0 3.7-2.2h10.7a.37 .37 0 0 0 .6 .3h5v.3l-.6-.1-.3 .1h-2.4a.38 .38 0 0 0-.6 .1 .38 .38 0 0 0 .1 .5 .36 .36 0 0 0 .1 .5 .36 .36 0 0 0 .5-.1h2.8l.2-.1h1a.39 .39 0 0 0 0 .5 .39 .39 0 0 0 .6 0 .39 .39 0 0 0 0-.5h.9a.37 .37 0 0 0 .3 .3 .37 .37 0 0 0 .4-.1h.7l1.6 1.5 1.2 .1 .3-.2a.39 .39 0 0 0 .5-.3 .39 .39 0 0 0-.4-.5l-.2-.1v-.4l-.1-.2-1.6 .1-.4-.4h2.5l.1 .8 .5 .6v.6h.6l.9 .8h.6l.1-.1 .1-.8h.6v.7l.2 .2h.6l.3-.4h.8l.7 .6h5.4l.6-.5v-.3l.3-.1v-.7h1.8a1.13 1.13 0 0 0 .8 1.1v5.8a.36 .36 0 0 0 0 .6 .36 .36 0 0 0 .5-.1h2.3l.5-.4h8.7v.7l.1 .1h.9a.46 .46 0 0 1 .8 .1h.6l.2-.1 .1-.4h-.5v.5h-.2v-.7h.7l-.2-.4-.3-.1v.5h-.2v-.5h-.2l-.3 .3h-.4l-.2-.3h-.6l-.3 .3h-8.7l.6-.6h.6l.3-.3 .3-.1 .3 .2h1.1l.2-.2v-.5l-.2-.1-1.1-.1-.6 .3-.1-.2a.45 .45 0 0 1 0-.8l.1-.6-.2-.2h-.9l-.1 .1-.1 .6 .3 .4v.3l-.2 .3-.1 .6-.8 .9-2.3-.1v-3.2h4.7v.4l.3 .2h1.1l.2-.2h.4v1.5l.5 .6 1.3-.1 .1-.5-.3-.3 .2-.1a.4 .4 0 0 0 .6-.4 .4 .4 0 0 0-.6-.3l-.2-.2 .3-.2v-.2h1v.5a.66 .66 0 0 1 0 1v.6l.3 .2h.7l.2-.3h.5l.1 .3 .2 .2h.5l.1-.3h1.1l.2 .3h.5l.1-.2 .1-.5h-.4v.7h-.1v-.7h-.4v.4h-1.1v-1h1.1v.4h.9l-.1-.5-.1-.2h-.2v.7h-.1v-.7l-.3 .1-.1 .2h-1.1l-.1-.3h-.5l-.2 .2v.4l-.5 .1-.1-.2a.5 .5 0 0 1-.3-.4 .5 .5 0 0 1 .3-.4v-.7l-.2-.2h-.7l-.3 .3h-1l-.1-.4-.5-.1v-1.3l.7-.7h5l-.2 .3v.8l-.3 .3-.1-.2a.39 .39 0 0 0-.3-.6 .39 .39 0 0 0-.4 .6l-.1 .2-.3-.3-.4 .1-.2 .1v1.2l.6 .5h1.5l.6-.4 .1-1.2-.2-.3v-.6l.4-.5h7.8l1.9 1.9v9.8l-.5 .6h-.7l-.2 .2v.7l.4 .2v.7l.2 .4h-1.9l-.7-.7 .5-.1a.55 .55 0 0 0 .7 .6 .55 .55 0 0 0 .2-.9v-2l-.6-.1-.2 .2v1.9l-.1 .3h-.5l.2-.4-.1-1.8-.2-.2-.5 .1-.1 1.9 .2 .2v.5l.9 1h2.2l.3 .1 .9-.1v.6l-1.4-.3-.5 .1v1.5l.2 .1h.5a.38 .38 0 0 0 .1 .5 .38 .38 0 0 0 .5 0h.6l.1 1.5h1l.1 .1a.46 .46 0 0 0-.5 .6 .46 .46 0 0 0 .7 .3 .45 .45 0 0 0 .1-.7l1.2-.1v-2.8a.42 .42 0 0 0 .5-.2 .42 .42 0 0 0-.2-.6l1.3-1.3v-2.8h3.2l.1 .4 .3 .1 .8 .1a.53 .53 0 0 0 .5-.6 .53 .53 0 0 0-.5-.5h-.8l-.4 .5h-3.2v-1l.2-.3v-.8l-.2-.2-.7 .1a.59 .59 0 0 1-.7 .1l-.2-.2h-.6l-.2 .3v.7l.1 .1 .7 .1 .2-.3h.6l.3 .4v3.6l-1.1 1.1-.1-1.9h-1l-.4-.2 .4-.4 .1-.5 .3 .2h.9a.53 .53 0 0 0 .3-.6 .53 .53 0 0 0-.4-.4h-.9l-.4 .6a.43 .43 0 0 0-.5-.1 .43 .43 0 0 0-.3 .3l.2 .8-.9 .1v1.4h-.6l-.4-.5v-.5l.4-.3v-.7l.6-.5v-10.2l-2.1-2.2h-13.8l-1 1-.1 1.4-.4 .1-.4 .6h-.4v-.5l-.2-.2h-1.1l-.3 .3h-4.7v-2.7a.98 .98 0 0 0 .4-1.7 .98 .98 0 0 0-1.6 .7h-1.8v-1.7l-.9-.1-.1 .1v2.4l.3 .2-.3 .3h-5.2l-.6-.6h-1l-.3-.4h-.6l-.2 .3h-.6l-.2-.3h-.6l-.3 .3-.4-.4 .1-.7 .3 .1 .3 .3h.7l.1-.2v-.7h.6v.7l.2 .2h.6l.3-.3h.3a.36 .36 0 0 0 .6-.1 .36 .36 0 0 0-.1-.5 .36 .36 0 0 0-.5 .1h-.3l-.3-.4h-.6l-.2 .3h-.6l-.2-.3h-.6l-.3 .4h-1.3a.38 .38 0 0 0 0-.6 .38 .38 0 0 0-.5 .2h-2.5l-.5-.5 .2-.1h7.7l1.4 1.3v1.4l.1 .1 .9-.1v-2.4h.3v2.5l1-.1v-2.4h.2l.1 2.4 .9 .1v-2.5h.3v2.4l.9 .1 .1-2.5-.2-.2a.38 .38 0 0 0-.4-.5 .38 .38 0 0 0-.2 .6l-.2 .1-.4-.1h-.7l-.2 .1-.3-.1h-.8l-.1 .1-1.2-.1-.2 .4-1.1-1.1h-2.2v-.3l.3-.2h.5l.3 .2 .6-.1 .1-.6-.3-.1h-.5l-.2 .2-1.3-.2-.2 .1v.5l.3 .3-.2 .2h-7.2v-.3l.3-.1 .2-.2 .7-.1 .2-.1v-.7l.4-.4 .2 .1-.2 .3v.7l.1 .1 .8 .1 .2-.3a.41 .41 0 0 0 .5 0 .41 .41 0 0 0 .1-.5l-.3-.2-.2 .1-.3-.3 2.2-.1 .3 .2 .3-.2h1.6l.2 .2h.5l.3-.1v-.5h.5v.5l.2 .1h.6l.2-.2a.38 .38 0 0 0 .6 0 .38 .38 0 0 0-.1-.5 .38 .38 0 0 0-.5 .1l-.2-.2h-.5l-.3 .2h-.5l-.3-.2v-.4l.2-.2h3.2v2.4l.9 .1 .1-2.5h.3v2.4l.9 .1 .1-.1v-2.4h.2l.1 2.5a.43 .43 0 0 0 .2 .5 .43 .43 0 0 0 .5-.1l.2-.5 .1-1 .2 .1v1l1-.1-.1-2.5h-.9v1.1l-.3-.1v-.9l-.1-.1h-.7l-.2 .1-.3-.1h-.8l-.1 .1-.4-.1-4.1 .1 .4-.4h8l.2 .2-.3 .2v2.5h.9l.1-1.1h.7l1.3 1.2a.98 .98 0 0 0 .7 1.5 .98 .98 0 0 0 1.1-1.2 .98 .98 0 0 0-1.5-.6l-.7-.7h28.1v.4a3.3 3.3 0 0 0 5 2.7 3.3 3.3 0 0 0 0-5.8 3.3 3.3 0 0 0-5 2.7h-28.1l-.6-.6h-1v-1l-.3-.3h2.1v.8h.5v.2h-.5l.1 .8 .8 .1v-.5h.2v.5h.8l.1-.1v-.8h-.5v-.2h.5l-.1-.8-.8-.1v.5h-.2v-.5l-3 .1-.5-.5h-8.2l-.9 .8v.5l-.3 .3h-1.6l-.3-.2-.3 .2h-2.4l.2-.7a.38 .38 0 0 0 .6 0 .38 .38 0 0 0-.1-.5 .38 .38 0 0 0-.5 0 .45 .45 0 0 0-.4-.5h-.6l-.2 .1-.1 1.2 .2 .4-.5 .5-.7 .1-.3 .9h-1v-1l-.2-.3v-.3a.51 .51 0 0 0 .4-.6h.2a.48 .48 0 0 0 .4 .6h.7l.2-.3v-1.2l-.2-.1h-.7a.45 .45 0 0 0-.4 .6h-.2l-.1-.5-.2-.1h-.7l-.2 .1-.1 1.3 .4 .2v.5l.3 .3-.1 .6-.4 .1-1-1-.1-.4 .3-.4v-1.2l-.3-.1h-.8l-.1 .3v1.1l.6 .6a.52 .52 0 0 1-.4 .5 .52 .52 0 0 1-.6-.3h-.7l-.2 .3a.39 .39 0 0 0-.6 .1 .39 .39 0 0 0 .1 .5 .39 .39 0 0 0 .5 0l.3 .3h.6l.3-.3h.3l.3 .3h.6l.3-.2 .2 .4h-5a.35 .35 0 0 0-.4-.1 .35 .35 0 0 0-.2 .3h-10.7v-.3a3.3 3.3 0 0 0-2.7-4.1 3.3 3.3 0 0 0-3.8 3.1h-.6v-2.1l.1-.4z" fill-rule="evenodd" fill="#eedab5"/>
<g fill="#fff">
<circle cx="227.4" cy="140.9" r=".13"/>
<circle cx="237" cy="142.8" r=".12"/>
<circle cx="232.9" cy="143.3" r=".13"/>
<circle cx="235.6" cy="148.5" r=".12"/>
<circle cx="196.6" cy="127.2" r=".13"/>
<circle cx="222.2" cy="153" r=".12"/>
<circle cx="178.7" cy="146.5" r=".13"/>
<circle cx="198.6" cy="146.8" r=".13"/>
<circle cx="207.6" cy="128" r=".12"/>
<circle cx="223.9" cy="135.8" r=".12"/>
<circle cx="178.1" cy="167.5" r=".12"/>
<circle cx="225.8" cy="146.7" r=".13"/>
<circle cx="196.2" cy="150.7" r=".13"/>
<circle cx="218.8" cy="150.9" r=".12"/>
<circle cx="196.4" cy="125.2" r=".13"/>
<circle cx="223.1" cy="141.5" r=".13"/>
<circle cx="198.1" cy="130.9" r=".12"/>
<circle cx="230" cy="140.7" r=".12"/>
<circle cx="217.4" cy="135.9" r=".12"/>
<circle cx="203.3" cy="126.3" r=".13"/>
<circle cx="222.5" cy="135.7" r=".13"/>
<circle cx="226.6" cy="139.7" r=".12"/>
<circle cx="212.2" cy="144.9" r=".13"/>
<circle cx="226.6" cy="138.2" r=".12"/>
<circle cx="192.3" cy="130" r=".13"/>
<circle cx="229.2" cy="144.6" r=".12"/>
<circle cx="216.1" cy="142.7" r=".13"/>
<circle cx="213.7" cy="150.3" r=".12"/>
<circle cx="169.7" cy="145.2" r=".13"/>
<circle cx="224.1" cy="150.9" r=".12"/>
<circle cx="239.5" cy="145.8" r=".13"/>
<circle cx="204.7" cy="150.5" r=".12"/>
<circle cx="221.6" cy="141.5" r=".13"/>
<circle cx="188" cy="127.2" r=".13"/>
<circle cx="219.7" cy="168.4" r=".12"/>
<circle cx="241.4" cy="142.1" r=".12"/>
<circle cx="169.8" cy="151.5" r=".12"/>
<circle cx="226.5" cy="133.3" r=".12"/>
<circle cx="177" cy="150.2" r=".12"/>
<circle cx="178.6" cy="148.3" r=".13"/>
<circle cx="239.3" cy="154.6" r=".13"/>
<circle cx="227.5" cy="144.5" r=".12"/>
<circle cx="195.5" cy="148.2" r=".12"/>
<circle cx="239.6" cy="151.1" r=".12"/>
<circle cx="194.8" cy="166.7" r=".12"/>
<circle cx="189.6" cy="138.1" r=".13"/>
<circle cx="189.7" cy="130.3" r=".12"/>
<circle cx="189.6" cy="127.2" r=".13"/>
<circle cx="213.5" cy="138.1" r=".13"/>
<circle cx="209" cy="152" r=".12"/>
<circle cx="195.2" cy="133.2" r=".12"/>
<circle cx="195.2" cy="128.6" r=".12"/>
<circle cx="193.2" cy="150.9" r=".12"/>
<circle cx="193.2" cy="139.9" r=".13"/>
<circle cx="233.3" cy="148.9" r=".12"/>
<circle cx="234.3" cy="147.9" r=".12"/>
<circle cx="187.7" cy="129.7" r=".13"/>
<circle cx="171.4" cy="145.2" r=".12"/>
<circle cx="171.4" cy="150.1" r=".12"/>
<circle cx="170.9" cy="144.7" r=".13"/>
<circle cx="190.6" cy="129" r=".13"/>
<circle cx="170.9" cy="150.6" r=".13"/>
<circle cx="187.6" cy="129" r=".13"/>
<circle cx="187.3" cy="132.2" r=".13"/>
<circle cx="201.5" cy="164.6" r=".13"/>
<circle cx="235.4" cy="146.1" r=".2"/>
<circle cx="237.3" cy="147.1" r=".13"/>
<circle cx="237.3" cy="148.5" r=".12"/>
<circle cx="220.8" cy="150" r=".12"/>
<circle cx="237.3" cy="149.6" r=".12"/>
<circle cx="172.2" cy="149.1" r=".12"/>
<circle cx="172.2" cy="147.6" r=".13"/>
<circle cx="183" cy="131.1" r=".12"/>
<circle cx="185.9" cy="128.2" r=".13"/>
<circle cx="183" cy="139.5" r=".13"/>
<circle cx="220.3" cy="142.5" r=".12"/>
<circle cx="219.7" cy="143.1" r=".12"/>
<circle cx="213.7" cy="144.3" r=".13"/>
<circle cx="235.4" cy="141.4" r=".12"/>
<circle cx="173.1" cy="146.6" r=".12"/>
<circle cx="181.8" cy="157.9" r=".12"/>
<circle cx="180.8" cy="156.6" r=".13"/>
<circle cx="201.9" cy="159.7" r=".12"/>
<circle cx="180.8" cy="159.7" r=".13"/>
<circle cx="173.7" cy="146.1" r=".12"/>
<circle cx="205.4" cy="151.2" r=".12"/>
<circle cx="198.6" cy="126.3" r=".13"/>
<circle cx="198.6" cy="129.5" r=".13"/>
<circle cx="195.6" cy="165.5" r=".13"/>
<circle cx="185.1" cy="134" r=".12"/>
<circle cx="200.7" cy="168.4" r=".12"/>
<circle cx="194.4" cy="129.2" r=".13"/>
<circle cx="193.9" cy="129.7" r=".12"/>
<circle cx="234.1" cy="142.3" r=".12"/>
<circle cx="214.4" cy="146.6" r=".13"/>
<circle cx="203.5" cy="130.1" r=".12"/>
<circle cx="208.9" cy="128.8" r=".13"/>
<circle cx="238.5" cy="153.6" r=".13"/>
<circle cx="239.4" cy="149.1" r=".12"/>
<circle cx="176.2" cy="144.6" r=".12"/>
<circle cx="170.2" cy="133.1" r=".13"/>
<circle cx="170.2" cy="147.1" r=".13"/>
<circle cx="169.9" cy="149.6" r=".13"/>
<circle cx="238" cy="148.6" r=".12"/>
<circle cx="241.1" cy="148.3" r=".13"/>
<circle cx="174.6" cy="148.5" r=".13"/>
<circle cx="175.3" cy="147.8" r=".12"/>
<circle cx="174" cy="148.5" r=".12"/>
<circle cx="241.3" cy="167.1" r=".25"/>
<circle cx="242" cy="165.4" r=".25"/>
<circle cx="242" cy="168.8" r=".25"/>
<circle cx="243.7" cy="164.7" r=".25"/>
<circle cx="243.7" cy="167.1" r="1.6"/>
<circle cx="243.7" cy="169.5" r=".25"/>
<circle cx="245.4" cy="165.4" r=".25"/>
<circle cx="245.4" cy="168.8" r=".25"/>
<circle cx="246.1" cy="167.1" r=".25"/>
<circle cx="239.4" cy="151.9" r=".33"/>
</g>
<path d="M239.4 144.6v.3" fill="none" stroke="#fff" stroke-width=".65"/>
<path d="M240.3 152.4h.6M240.3 144.2h.6M246.3 152.8h.6M246.3 143.8h.6" fill="none" stroke="#fff" stroke-width=".5"/>
<g fill="#fff">
<circle cx="178.9" cy="130.3" r=".5"/>
<circle cx="181.5" cy="130.3" r=".5"/>
<circle cx="213.9" cy="168.2" r=".5"/>
<circle cx="211.4" cy="168.2" r=".5"/>
<circle cx="208.8" cy="168.2" r=".5"/>
<circle cx="241.3" cy="127.1" r=".25"/>
<circle cx="242" cy="125.4" r=".25"/>
<circle cx="242" cy="128.8" r=".25"/>
<circle cx="243.7" cy="124.7" r=".25"/>
<circle cx="243.7" cy="127.1" r="1.6"/>
<circle cx="243.7" cy="129.5" r=".25"/>
<circle cx="245.4" cy="125.4" r=".25"/>
<circle cx="245.4" cy="128.8" r=".25"/>
<circle cx="246.1" cy="127.1" r=".25"/>
<circle cx="169.3" cy="167.1" r=".25"/>
<circle cx="170" cy="165.4" r=".25"/>
<circle cx="170" cy="168.8" r=".25"/>
<circle cx="171.7" cy="164.7" r=".25"/>
<circle cx="171.7" cy="167.1" r="1.6"/>
<circle cx="171.7" cy="169.5" r=".25"/>
<circle cx="173.4" cy="165.4" r=".25"/>
<circle cx="173.4" cy="168.8" r=".25"/>
<circle cx="174.1" cy="167.1" r=".25"/>
<circle cx="192.6" cy="167.3" r=".45"/>
<circle cx="195.6" cy="167.3" r=".45"/>
<circle cx="213.5" cy="125.9" r=".5"/>
<circle cx="213.5" cy="128.4" r=".5"/>
<circle cx="213.5" cy="131" r=".5"/>
<circle cx="169.3" cy="127.1" r=".25"/>
<circle cx="170" cy="125.4" r=".25"/>
<circle cx="170" cy="128.8" r=".25"/>
<circle cx="171.7" cy="124.7" r=".25"/>
<circle cx="171.7" cy="127.1" r="1.6"/>
<circle cx="171.7" cy="129.5" r=".25"/>
<circle cx="173.4" cy="125.4" r=".25"/>
<circle cx="173.4" cy="128.8" r=".25"/>
<circle cx="174.1" cy="127.1" r=".25"/>
</g>
<g fill="#b9b9b9">
<path d="M202 151.9h.8v.2h-.8z" fill-rule="evenodd"/>
<path d="M202 151.2h.8v.3h-.8z" fill-rule="evenodd"/>
<path d="M202 150.6h.8v.2h-.8z" fill-rule="evenodd"/>
<path d="M202 149.9h.8v.3h-.8z" fill-rule="evenodd"/>
<path d="M201.3 148.7h.3v.8h-.3z" fill-rule="evenodd"/>
<path d="M200.7 148.7h.2v.8h-.2z" fill-rule="evenodd"/>
<path d="M200 148.7h.3v.8h-.3z" fill-rule="evenodd"/>
<path d="M199.4 148.7h.2v.8h-.2z" fill-rule="evenodd"/>
<path d="M198.1 149.9h.8v.3h-.8z" fill-rule="evenodd"/>
<path d="M198.1 150.6h.8v.2h-.8z" fill-rule="evenodd"/>
<path d="M198.1 151.2h.8v.3h-.8z" fill-rule="evenodd"/>
<path d="M198.1 151.9h.8v.2h-.8z" fill-rule="evenodd"/>
<path d="M199.4 152.6h.2v.8h-.2z" fill-rule="evenodd"/>
<path d="M200 152.6h.3v.8h-.3z" fill-rule="evenodd"/>
<path d="M200.7 152.6h.2v.8h-.2z" fill-rule="evenodd"/>
<path d="M201.3 152.6h.3v.8h-.3z" fill-rule="evenodd"/>
<path d="M199.4 150h2.1v2.1h-2.1z" fill-rule="evenodd"/>
<path d="M202.2 127.4h.6v.6h-.6z" fill-rule="evenodd"/>
<path d="M202.2 126h.6v.6h-.6z" fill-rule="evenodd"/>
<path d="M219.3 165.9h.8v.7h-.8z" fill-rule="evenodd"/>
<path d="M219.3 164.2h.8v.7h-.8z" fill-rule="evenodd"/>
<path d="M227.2 133.6l.5 .1-.1 1.2-.5-.1z" fill-rule="evenodd"/>
<path d="M226.2 133.6l.6 .1-.1 1.2-.5-.1z" fill-rule="evenodd"/>
<path d="M225.3 133.6l.5 .1-.1 1.2-.5-.1z" fill-rule="evenodd"/>
<path d="M225.3 135.9h.5l-.1 1.3-.5-.1z" fill-rule="evenodd"/>
<path d="M227.2 135.9h.5l-.1 1.3-.5-.1z" fill-rule="evenodd"/>
<path d="M203.5 151.6h.8v.8h-.8z" fill-rule="evenodd"/>
<path d="M203.5 150.1h.8v.8h-.8z" fill-rule="evenodd"/>
<path d="M219.5 152.6h.7v.8h-.7z" fill-rule="evenodd"/>
<path d="M221 152.6h.8v.8h-.8z" fill-rule="evenodd"/>
<path d="M241.9 141.7h.7v.8h-.7z" fill-rule="evenodd"/>
<path d="M240.2 141.7h.7v.8h-.7z" fill-rule="evenodd"/>
</g>
<g fill="#b9b9b9">
<circle cx="241.3" cy="167.1" r=".4"/>
<circle cx="242" cy="165.4" r=".4"/>
<circle cx="242" cy="168.8" r=".4"/>
<circle cx="243.7" cy="164.7" r=".4"/>
<circle cx="243.7" cy="167.1" r="3.2"/>
<circle cx="243.7" cy="169.5" r=".4"/>
<circle cx="245.4" cy="165.4" r=".4"/>
<circle cx="245.4" cy="168.8" r=".4"/>
<circle cx="246.1" cy="167.1" r=".4"/>
<circle cx="239.4" cy="151.9" r=".33"/>
</g>
<path d="M239.4 144.6v.3" fill="none" stroke="#b9b9b9" stroke-width=".65"/>
<g fill="#b9b9b9">
<path d="M238.4 150.9h.7v.3h-.7z" fill-rule="evenodd"/>
<path d="M238.4 150.4h.7v.3h-.7z" fill-rule="evenodd"/>
<path d="M238.4 149.9h.7v.3h-.7z" fill-rule="evenodd"/>
<path d="M238.4 149.4h.7v.3h-.7z" fill-rule="evenodd"/>
<path d="M238.4 148.9h.7v.3h-.7z" fill-rule="evenodd"/>
<path d="M238.4 148.4h.7v.3h-.7z" fill-rule="evenodd"/>
<path d="M238.4 147.9h.7v.3h-.7z" fill-rule="evenodd"/>
<path d="M238.4 147.4h.7v.3h-.7z" fill-rule="evenodd"/>
<path d="M238.4 146.9h.7v.3h-.7z" fill-rule="evenodd"/>
<path d="M238.4 146.4h.7v.3h-.7z" fill-rule="evenodd"/>
<path d="M238.4 145.9h.7v.3h-.7z" fill-rule="evenodd"/>
<path d="M238.4 145.4h.7v.3h-.7z" fill-rule="evenodd"/>
<path d="M240.1 145.7h.7v.3h-.7z" fill-rule="evenodd"/>
<path d="M240.1 146.2h.7v.3h-.7z" fill-rule="evenodd"/>
<path d="M240.1 146.7h.7v.3h-.7z" fill-rule="evenodd"/>
<path d="M240.1 147.2h.7v.3h-.7z" fill-rule="evenodd"/>
<path d="M240.1 147.7h.7v.3h-.7z" fill-rule="evenodd"/>
<path d="M240.1 148.2h.7v.3h-.7z" fill-rule="evenodd"/>
<path d="M240.1 148.7h.7v.3h-.7z" fill-rule="evenodd"/>
<path d="M240.1 149.2h.7v.3h-.7z" fill-rule="evenodd"/>
<path d="M240.1 149.7h.7v.3h-.7z" fill-rule="evenodd"/>
<path d="M240.1 150.2h.7v.3h-.7z" fill-rule="evenodd"/>
<path d="M240.1 150.7h.7v.3h-.7z" fill-rule="evenodd"/>
<path d="M240.1 151.2h.7v.3h-.7z" fill-rule="evenodd"/>
</g>
<path d="M240.3 152.4h.6M240.3 144.2h.6M246.3 152.8h.6M246.3 143.8h.6" fill="none" stroke="#b9b9b9" stroke-width=".8"/>
<g fill="#b9b9b9">
<path d="M239.8 154.2h.7v.8h-.7z" fill-rule="evenodd"/>
<path d="M238.1 154.2h.7v.8h-.7z" fill-rule="evenodd"/>
<path d="M200.3 165.9h.8v.7h-.8z" fill-rule="evenodd"/>
<path d="M200.3 164.2h.8v.7h-.8z" fill-rule="evenodd"/>
<path d="M216.9 152.8h.8v.7h-.8z" fill-rule="evenodd"/>
<path d="M216.9 151.1h.8v.7h-.8z" fill-rule="evenodd"/>
<path d="M178.1 129.4h1.7v1.7h-1.7z" fill-rule="evenodd"/>
<path d="M222.7 141.9h.8v.8h-.8z" fill-rule="evenodd"/>
<path d="M222.7 140.3h.8v.8h-.8z" fill-rule="evenodd"/>
<path d="M180.7 132.5l.7-.1 .2 .2v.9l-.1 .3h-.7l-.2-.2z" fill-rule="evenodd"/>
<path d="M178.8 132.5l.8-.1 .2 .2v.9l-.2 .3h-.6l-.2-.2z" fill-rule="evenodd"/>
<path d="M177.5 149.8h.6v.8h-.6z" fill-rule="evenodd"/>
<path d="M175.8 149.8h.7v.8h-.7z" fill-rule="evenodd"/>
<path d="M193.2 124.6l.7-.1 .2 .2v.9l-.1 .3h-.7l-.2-.2z" fill-rule="evenodd"/>
<path d="M195 124.6l.7-.1 .2 .2v.9l-.1 .3h-.6l-.3-.2z" fill-rule="evenodd"/>
<path d="M235.1 138.8l.6 .1-.1 1.8-.5-.1z" fill-rule="evenodd"/>
<path d="M233.9 138.8l.5 .1-.1 1.8-.5-.1z" fill-rule="evenodd"/>
<path d="M232.6 138.8l.6 .1-.1 1.8-.5-.1z" fill-rule="evenodd"/>
<path d="M231.3 138.8l.6 .1-.1 1.8-.5-.1z" fill-rule="evenodd"/>
<path d="M231.3 143.8h.6l-.1 1.9-.5-.1z" fill-rule="evenodd"/>
<path d="M232.6 143.8h.6l-.1 1.9-.5-.1z" fill-rule="evenodd"/>
<path d="M233.9 143.8h.5l-.1 1.9-.5-.1z" fill-rule="evenodd"/>
<path d="M235.1 143.8h.6l-.1 1.9-.5-.1z" fill-rule="evenodd"/>
<path d="M223.5 136.2h.8v.8h-.8z" fill-rule="evenodd"/>
<path d="M223.5 134.6h.8v.8h-.8z" fill-rule="evenodd"/>
<path d="M213.1 167.4h1.6v1.6h-1.6z" fill-rule="evenodd"/>
<path d="M183.9 133.6h.7v.8h-.7z" fill-rule="evenodd"/>
<path d="M185.6 133.6h.7v.8h-.7z" fill-rule="evenodd"/>
<path d="M179.1 163h1.5v1.4h-1.5z" fill-rule="evenodd"/>
<path d="M179.1 167.6h1.5v1.2h-1.5z" fill-rule="evenodd"/>
<path d="M187 163h1.6v1.4h-1.6z" fill-rule="evenodd"/>
<path d="M187 167.6h1.6v1.2h-1.6z" fill-rule="evenodd"/>
<path d="M200.3 129.7h.7v.8h-.7z" fill-rule="evenodd"/>
<path d="M202 129.7h.7v.8h-.7z" fill-rule="evenodd"/>
<path d="M213.2 147.5h.8v.8h-.8z" fill-rule="evenodd"/>
<path d="M213.2 149.1h.8v.8h-.8z" fill-rule="evenodd"/>
<path d="M200.7 126h.6v.6h-.6z" fill-rule="evenodd"/>
<path d="M200.7 127.4h.6v.6h-.6z" fill-rule="evenodd"/>
<path d="M229.6 139.4h.8v.7h-.8z" fill-rule="evenodd"/>
<path d="M229.6 141.1h.8v.7h-.8z" fill-rule="evenodd"/>
<path d="M177.6 148.7h.4l.1 .3-.5 .1z" fill-rule="evenodd"/>
<path d="M177.6 148.2h.6v.2l-.6 .1z" fill-rule="evenodd"/>
<path d="M177.6 147.6h.4l.1 .3-.5 .1z" fill-rule="evenodd"/>
<path d="M175.9 147.6h.5v.4h-.5z" fill-rule="evenodd"/>
<path d="M175.8 148.2h.5l.1 .2-.6 .1z" fill-rule="evenodd"/>
<path d="M175.9 148.7h.5v.3h-.5z" fill-rule="evenodd"/>
<path d="M184 131.5h.5v1.4l-.5-.1z" fill-rule="evenodd"/>
<path d="M185.9 131.5h.5v1.4l-.5-.1z" fill-rule="evenodd"/>
<path d="M184.9 129.6l.6 .1-.1 1.3-.5-.1z" fill-rule="evenodd"/>
<path d="M211.8 145.3h.8v.8h-.8z" fill-rule="evenodd"/>
<path d="M211.8 143.8h.8v.7h-.8z" fill-rule="evenodd"/>
<path d="M197.3 130l.4-.1 .1 .4h-.4z" fill-rule="evenodd"/>
<path d="M197.2 130.5h.6v.3h-.6z" fill-rule="evenodd"/>
<path d="M197.3 131h.4l.1 .3-.4 .1z" fill-rule="evenodd"/>
<path d="M199 131h.4l.1 .3-.4 .1z" fill-rule="evenodd"/>
<path d="M199 130.5h.6v.3h-.6z" fill-rule="evenodd"/>
<path d="M199 130l.4-.1 .1 .4h-.4z" fill-rule="evenodd"/>
<path d="M196.6 147.2h.8v.6h-.8z" fill-rule="evenodd"/>
<path d="M196.6 148.8h.8v.7h-.8z" fill-rule="evenodd"/>
<path d="M213.3 143.1h.8v.7h-.8z" fill-rule="evenodd"/>
<path d="M213.3 144.8h.8v.7h-.8z" fill-rule="evenodd"/>
<path d="M190 126.8h.8v.8h-.8z" fill-rule="evenodd"/>
<path d="M188.5 126.8h.7v.8h-.7z" fill-rule="evenodd"/>
<path d="M234.7 147.8l.4-.1 .1 .4h-.4z" fill-rule="evenodd"/>
<path d="M234.6 148.3h.6v.3h-.6z" fill-rule="evenodd"/>
<path d="M234.7 148.8h.4l.1 .3-.4 .1z" fill-rule="evenodd"/>
<path d="M236.4 148.8h.4l.1 .3-.4 .1z" fill-rule="evenodd"/>
<path d="M236.4 148.3h.6v.3h-.6z" fill-rule="evenodd"/>
<path d="M236.4 147.8l.4-.1 .1 .4h-.4z" fill-rule="evenodd"/>
<path d="M177.7 163.2h.8v.7h-.8z" fill-rule="evenodd"/>
<path d="M177.7 164.8h.8v.7h-.8z" fill-rule="evenodd"/>
<path d="M225.2 142.8h1.2v1.4h-1.2z" fill-rule="evenodd"/>
<path d="M225.2 145h1.2v1.4h-1.2z" fill-rule="evenodd"/>
<path d="M226.9 145h1.2v1.4h-1.2z" fill-rule="evenodd"/>
<path d="M226.9 142.8h1.2v1.4h-1.2z" fill-rule="evenodd"/>
<path d="M236.6 144.8h.8v.7h-.8z" fill-rule="evenodd"/>
<path d="M236.6 143.2h.8v.8h-.8z" fill-rule="evenodd"/>
<path d="M177.7 166.3h.8v.8h-.8z" fill-rule="evenodd"/>
<path d="M177.7 167.8h.8v.8h-.8z" fill-rule="evenodd"/>
<path d="M220.1 143.8h.2l-.1 .8-.2-.1z" fill-rule="evenodd"/>
<path d="M219.6 143.8h.2l-.1 .8-.2-.1z" fill-rule="evenodd"/>
<path d="M219.1 143.8h.2l-.1 .8-.2-.1z" fill-rule="evenodd"/>
<path d="M218.6 143.8h.2l-.1 .8-.2-.1z" fill-rule="evenodd"/>
<path d="M218.1 143.8h.2l-.1 .8-.2-.1z" fill-rule="evenodd"/>
<path d="M217.6 143.8h.2l-.1 .8-.2-.1z" fill-rule="evenodd"/>
<path d="M217.1 143.8h.2l-.1 .8-.2-.1z" fill-rule="evenodd"/>
<path d="M216.6 143.8h.2l-.1 .8-.2-.1z" fill-rule="evenodd"/>
<path d="M216.1 143.8h.2l-.1 .8-.2-.1z" fill-rule="evenodd"/>
<path d="M214.8 145h.8v.2h-.7z" fill-rule="evenodd"/>
<path d="M214.8 145.5h.8v.2h-.7z" fill-rule="evenodd"/>
<path d="M214.8 146h.8v.2h-.7z" fill-rule="evenodd"/>
<path d="M214.8 146.5h.8v.2h-.7z" fill-rule="evenodd"/>
<path d="M214.8 147h.8v.2h-.7z" fill-rule="evenodd"/>
<path d="M214.8 147.5h.8v.2h-.7z" fill-rule="evenodd"/>
<path d="M214.8 148h.8v.2h-.7z" fill-rule="evenodd"/>
<path d="M214.8 148.5h.8v.2h-.7z" fill-rule="evenodd"/>
<path d="M214.8 149h.8v.2h-.7z" fill-rule="evenodd"/>
<path d="M216.1 149.6l.2 .1-.1 .8-.2-.1z" fill-rule="evenodd"/>
<path d="M216.6 149.6l.2 .1-.1 .8-.2-.1z" fill-rule="evenodd"/>
<path d="M217.1 149.6l.2 .1-.1 .8-.2-.1z" fill-rule="evenodd"/>
<path d="M217.6 149.6l.2 .1-.1 .8-.2-.1z" fill-rule="evenodd"/>
<path d="M218.1 149.6l.2 .1-.1 .8-.2-.1z" fill-rule="evenodd"/>
<path d="M218.6 149.6l.2 .1-.1 .8-.2-.1z" fill-rule="evenodd"/>
<path d="M219.1 149.6l.2 .1-.1 .8-.2-.1z" fill-rule="evenodd"/>
<path d="M219.6 149.6l.2 .1-.1 .8-.2-.1z" fill-rule="evenodd"/>
<path d="M220.1 149.6l.2 .1-.1 .8-.2-.1z" fill-rule="evenodd"/>
<path d="M220.7 149h.8v.2h-.8z" fill-rule="evenodd"/>
<path d="M220.7 148.5h.8v.2h-.8z" fill-rule="evenodd"/>
<path d="M220.7 148h.8v.2h-.8z" fill-rule="evenodd"/>
<path d="M220.7 147.5h.8v.2h-.8z" fill-rule="evenodd"/>
<path d="M220.7 147h.8v.2h-.8z" fill-rule="evenodd"/>
<path d="M220.7 146.5h.8v.2h-.8z" fill-rule="evenodd"/>
<path d="M220.7 146h.8v.2h-.8z" fill-rule="evenodd"/>
<path d="M220.7 145.5h.8v.2h-.8z" fill-rule="evenodd"/>
<path d="M220.7 145h.8v.2h-.8z" fill-rule="evenodd"/>
<path d="M216.3 145.2h3.7v3.7h-3.7z" fill-rule="evenodd"/>
<path d="M227 137.8h.8v.8h-.8z" fill-rule="evenodd"/>
<path d="M225.5 137.8h.7v.8h-.7z" fill-rule="evenodd"/>
<path d="M200.3 168.8h.8v.8h-.8z" fill-rule="evenodd"/>
<path d="M200.3 167.2h.8v.8h-.8z" fill-rule="evenodd"/>
<path d="M190 165.8h1v.8h-1z" fill-rule="evenodd"/>
<path d="M190 168h1v.8h-1z" fill-rule="evenodd"/>
<path d="M197.2 165.8h1.1v.8h-1.1z" fill-rule="evenodd"/>
<path d="M197.2 168h1.1v.8h-1.1z" fill-rule="evenodd"/>
<path d="M191.5 164.8h.7v1.5h-.7z" fill-rule="evenodd"/>
<path d="M194.5 164.8h.7v1.5h-.7z" fill-rule="evenodd"/>
<path d="M196 164.8h.7v1.5h-.7z" fill-rule="evenodd"/>
<path d="M222.2 149.6h.6v.8h-.6z" fill-rule="evenodd"/>
<path d="M223.8 149.6h.7v.8h-.7z" fill-rule="evenodd"/>
<path d="M227 139.3h.8v.8h-.8z" fill-rule="evenodd"/>
<path d="M225.5 139.3h.7v.8h-.7z" fill-rule="evenodd"/>
<path d="M167.8 150.9h1.6l.1 .3-1.6 .1z" fill-rule="evenodd"/>
<path d="M167.8 150.4h1.6l.1 .3-1.6 .1z" fill-rule="evenodd"/>
<path d="M167.8 149.9h1.6l.1 .3-1.6 .1z" fill-rule="evenodd"/>
<path d="M167.8 149.4h1.6l.1 .3-1.6 .1z" fill-rule="evenodd"/>
<path d="M167.8 148.9h1.6l.1 .3-1.6 .1z" fill-rule="evenodd"/>
<path d="M167.8 148.4h1.6l.1 .3-1.6 .1z" fill-rule="evenodd"/>
<path d="M167.8 147.9h1.6l.1 .3-1.6 .1z" fill-rule="evenodd"/>
<path d="M167.8 147.4h1.6l.1 .3-1.6 .1z" fill-rule="evenodd"/>
<path d="M167.8 146.9h1.6l.1 .3-1.6 .1z" fill-rule="evenodd"/>
<path d="M167.8 146.4h1.6l.1 .3-1.6 .1z" fill-rule="evenodd"/>
<path d="M167.8 145.9h1.6l.1 .3-1.6 .1z" fill-rule="evenodd"/>
<path d="M167.8 145.4h1.6l.1 .3-1.6 .1z" fill-rule="evenodd"/>
<path d="M167.8 144.6h1.6l.1 .6-1.6 .1z" fill-rule="evenodd"/>
<path d="M214.9 142.3h.7v.8h-.7z" fill-rule="evenodd"/>
<path d="M216.4 142.3h.8v.8h-.8z" fill-rule="evenodd"/>
<path d="M228.8 143.5h.8v.7h-.8z" fill-rule="evenodd"/>
<path d="M228.8 145h.8v.8h-.8z" fill-rule="evenodd"/>
<path d="M209.8 125.3h.8v2.4h-.8z" fill-rule="evenodd"/>
<path d="M209.8 129.2h.8v2.4h-.8z" fill-rule="evenodd"/>
<path d="M208.5 125.3h.8v2.4h-.8z" fill-rule="evenodd"/>
<path d="M208.5 129.2h.8v2.4h-.8z" fill-rule="evenodd"/>
<path d="M207.3 125.3h.7v2.4h-.7z" fill-rule="evenodd"/>
<path d="M207.3 129.2h.7v2.4h-.7z" fill-rule="evenodd"/>
<path d="M206 125.3h.7v2.4h-.7z" fill-rule="evenodd"/>
<path d="M206 129.2h.7v2.4h-.7z" fill-rule="evenodd"/>
<path d="M204.7 125.3h.8v2.4h-.8z" fill-rule="evenodd"/>
<path d="M204.7 129.2h.8v2.4h-.8z" fill-rule="evenodd"/>
<path d="M221.1 151.1h.7v.8h-.7z" fill-rule="evenodd"/>
<path d="M219.4 151.1h.7v.8h-.7z" fill-rule="evenodd"/>
<path d="M212.7 125.1h1.6v1.7h-1.6z" fill-rule="evenodd"/>
<path d="M189.8 124.6l.7-.1 .2 .2v.9l-.1 .3h-.7l-.2-.2z" fill-rule="evenodd"/>
<path d="M191.6 124.6l.7-.1 .2 .2v.9l-.1 .3h-.6l-.3-.2z" fill-rule="evenodd"/>
<path d="M191.3 127.7h.6v.2h-.6z" fill-rule="evenodd"/>
<path d="M191.8 127.5h.1v.3h-.1z" fill-rule="evenodd"/>
<path d="M191.3 128.1h.6v.2h-.6z" fill-rule="evenodd"/>
<path d="M191.3 128.5h.6v.2h-.6z" fill-rule="evenodd"/>
<path d="M191.3 128.9h.6v.2h-.6z" fill-rule="evenodd"/>
<path d="M191.3 129.3h.6v.2h-.6z" fill-rule="evenodd"/>
<path d="M192.2 129.1h.2v.6h-.2z" fill-rule="evenodd"/>
<path d="M192.6 129.3h.6v.2h-.6z" fill-rule="evenodd"/>
<path d="M192.6 128.9h.6v.2h-.6z" fill-rule="evenodd"/>
<path d="M192.6 128.5h.6v.2h-.6z" fill-rule="evenodd"/>
<path d="M192.6 128.1h.6v.2h-.6z" fill-rule="evenodd"/>
<path d="M192.6 127.7h.6v.2h-.6z" fill-rule="evenodd"/>
<path d="M192.2 127.5h.2v.6h-.2z" fill-rule="evenodd"/>
<path d="M219.3 168.8h.8v.8h-.8z" fill-rule="evenodd"/>
<path d="M219.3 167.2h.8v.8h-.8z" fill-rule="evenodd"/>
<path d="M223.8 143.4h.8v.7h-.8z" fill-rule="evenodd"/>
<path d="M223.8 145.1h.8v.7h-.8z" fill-rule="evenodd"/>
<path d="M175.8 146.1h.7v.8h-.7z" fill-rule="evenodd"/>
<path d="M177.5 146.1h.6v.8h-.6z" fill-rule="evenodd"/>
<path d="M193.8 126.8h.8v.8h-.8z" fill-rule="evenodd"/>
<path d="M195.4 126.8h.7v.8h-.7z" fill-rule="evenodd"/>
<path d="M195.1 148.7h.8v.8h-.8z" fill-rule="evenodd"/>
<path d="M195.1 147.2h.8v.7h-.8z" fill-rule="evenodd"/>
<path d="M221.2 142h.8v.7h-.8z" fill-rule="evenodd"/>
<path d="M221.2 140.3h.8v.7h-.8z" fill-rule="evenodd"/>
<path d="M196.6 150.3h.8v.8h-.8z" fill-rule="evenodd"/>
<path d="M195 150.3h.8v.8h-.8z" fill-rule="evenodd"/>
<path d="M200.3 131.3h.7v.8h-.7z" fill-rule="evenodd"/>
<path d="M202 131.3h.7v.8h-.7z" fill-rule="evenodd"/>
<path d="M198.2 147.3h.8v.7h-.8z" fill-rule="evenodd"/>
<path d="M198.2 145.7h.8v.8h-.8z" fill-rule="evenodd"/>
<path d="M227 141.3h.8v.8h-.8z" fill-rule="evenodd"/>
<path d="M225.4 141.3h.8v.8h-.8z" fill-rule="evenodd"/>
<path d="M217 136.3h.9v.8h-.9z" fill-rule="evenodd"/>
<path d="M217 134.8h.9v.8h-.9z" fill-rule="evenodd"/>
<path d="M220.9 136.4h1.2v.5l-1.2 .1z" fill-rule="evenodd"/>
<path d="M220.9 135.5l1.2-.1v.5l-1.2 .1z" fill-rule="evenodd"/>
<path d="M220.9 134.5h1.2v.5l-1.2 .1z" fill-rule="evenodd"/>
<path d="M218.6 134.5h1.2l.1 .5-1.3 .1z" fill-rule="evenodd"/>
<path d="M218.6 136.4h1.2l.1 .5-1.3 .1z" fill-rule="evenodd"/>
</g>
<g fill="#b9b9b9">
<circle cx="181.5" cy="130.3" r=".85"/>
<circle cx="211.4" cy="168.2" r=".85"/>
<circle cx="208.8" cy="168.2" r=".85"/>
<circle cx="241.3" cy="127.1" r=".4"/>
<circle cx="242" cy="125.4" r=".4"/>
<circle cx="242" cy="128.8" r=".4"/>
<circle cx="243.7" cy="124.7" r=".4"/>
<circle cx="243.7" cy="127.1" r="3.2"/>
<circle cx="243.7" cy="129.5" r=".4"/>
<circle cx="245.4" cy="125.4" r=".4"/>
<circle cx="245.4" cy="128.8" r=".4"/>
<circle cx="246.1" cy="127.1" r=".4"/>
<circle cx="169.3" cy="167.1" r=".4"/>
<circle cx="170" cy="165.4" r=".4"/>
<circle cx="170" cy="168.8" r=".4"/>
<circle cx="171.7" cy="164.7" r=".4"/>
<circle cx="171.7" cy="167.1" r="3.2"/>
<circle cx="171.7" cy="169.5" r=".4"/>
<circle cx="173.4" cy="165.4" r=".4"/>
<circle cx="173.4" cy="168.8" r=".4"/>
<circle cx="174.1" cy="167.1" r=".4"/>
<circle cx="192.6" cy="167.3" r=".45"/>
<circle cx="195.6" cy="167.3" r=".45"/>
<circle cx="213.5" cy="128.4" r=".85"/>
<circle cx="213.5" cy="131" r=".85"/>
<circle cx="169.3" cy="127.1" r=".4"/>
<circle cx="170" cy="125.4" r=".4"/>
<circle cx="170" cy="128.8" r=".4"/>
<circle cx="171.7" cy="124.7" r=".4"/>
<circle cx="171.7" cy="127.1" r="3.2"/>
<circle cx="171.7" cy="129.5" r=".4"/>
<circle cx="173.4" cy="125.4" r=".4"/>
<circle cx="173.4" cy="128.8" r=".4"/>
<circle cx="174.1" cy="127.1" r=".4"/>
</g>
<g fill="#e1a98e">
<path d="M200.6 151.2h.8v.7h-.8z" fill-rule="evenodd"/>
<path d="M200.6 150.1h.8v.8h-.8z" fill-rule="evenodd"/>
<path d="M199.6 151.2h.7v.7h-.7z" fill-rule="evenodd"/>
<path d="M199.6 150.1h.7v.8h-.7z" fill-rule="evenodd"/>
<path d="M202 151.9h.8v.2h-.8z" fill-rule="evenodd"/>
<path d="M202 151.2h.8v.3h-.8z" fill-rule="evenodd"/>
<path d="M202 150.6h.8v.2h-.8z" fill-rule="evenodd"/>
<path d="M202 149.9h.8v.3h-.8z" fill-rule="evenodd"/>
<path d="M201.3 148.7h.3v.8h-.3z" fill-rule="evenodd"/>
<path d="M200.7 148.7h.2v.8h-.2z" fill-rule="evenodd"/>
<path d="M200 148.7h.3v.8h-.3z" fill-rule="evenodd"/>
<path d="M199.4 148.7h.2v.8h-.2z" fill-rule="evenodd"/>
<path d="M198.1 149.9h.8v.3h-.8z" fill-rule="evenodd"/>
<path d="M198.1 150.6h.8v.2h-.8z" fill-rule="evenodd"/>
<path d="M198.1 151.2h.8v.3h-.8z" fill-rule="evenodd"/>
<path d="M198.1 151.9h.8v.2h-.8z" fill-rule="evenodd"/>
<path d="M199.4 152.6h.2v.8h-.2z" fill-rule="evenodd"/>
<path d="M200 152.6h.3v.8h-.3z" fill-rule="evenodd"/>
<path d="M200.7 152.6h.2v.8h-.2z" fill-rule="evenodd"/>
<path d="M201.3 152.6h.3v.8h-.3z" fill-rule="evenodd"/>
<path d="M202.2 127.4h.6v.6h-.6z" fill-rule="evenodd"/>
<path d="M202.2 126h.6v.6h-.6z" fill-rule="evenodd"/>
<path d="M219.3 165.9h.8v.7h-.8z" fill-rule="evenodd"/>
<path d="M219.3 164.2h.8v.7h-.8z" fill-rule="evenodd"/>
<path d="M227.2 133.6l.5 .1-.1 1.2-.5-.1z" fill-rule="evenodd"/>
<path d="M226.2 133.6l.6 .1-.1 1.2-.5-.1z" fill-rule="evenodd"/>
<path d="M225.3 133.6l.5 .1-.1 1.2-.5-.1z" fill-rule="evenodd"/>
<path d="M225.3 135.9h.5l-.1 1.3-.5-.1z" fill-rule="evenodd"/>
<path d="M227.2 135.9h.5l-.1 1.3-.5-.1z" fill-rule="evenodd"/>
<path d="M203.5 151.6h.8v.8h-.8z" fill-rule="evenodd"/>
<path d="M203.5 150.1h.8v.8h-.8z" fill-rule="evenodd"/>
<path d="M219.5 152.6h.7v.8h-.7z" fill-rule="evenodd"/>
<path d="M221 152.6h.8v.8h-.8z" fill-rule="evenodd"/>
<path d="M241.9 141.7h.7v.8h-.7z" fill-rule="evenodd"/>
<path d="M240.2 141.7h.7v.8h-.7z" fill-rule="evenodd"/>
<path d="M238.4 150.9h.7v.3h-.7z" fill-rule="evenodd"/>
<path d="M238.4 150.4h.7v.3h-.7z" fill-rule="evenodd"/>
<path d="M238.4 149.9h.7v.3h-.7z" fill-rule="evenodd"/>
<path d="M238.4 149.4h.7v.3h-.7z" fill-rule="evenodd"/>
<path d="M238.4 148.9h.7v.3h-.7z" fill-rule="evenodd"/>
<path d="M238.4 148.4h.7v.3h-.7z" fill-rule="evenodd"/>
<path d="M238.4 147.9h.7v.3h-.7z" fill-rule="evenodd"/>
<path d="M238.4 147.4h.7v.3h-.7z" fill-rule="evenodd"/>
<path d="M238.4 146.9h.7v.3h-.7z" fill-rule="evenodd"/>
<path d="M238.4 146.4h.7v.3h-.7z" fill-rule="evenodd"/>
<path d="M238.4 145.9h.7v.3h-.7z" fill-rule="evenodd"/>
<path d="M238.4 145.4h.7v.3h-.7z" fill-rule="evenodd"/>
<path d="M240.1 145.7h.7v.3h-.7z" fill-rule="evenodd"/>
<path d="M240.1 146.2h.7v.3h-.7z" fill-rule="evenodd"/>
<path d="M240.1 146.7h.7v.3h-.7z" fill-rule="evenodd"/>
<path d="M240.1 147.2h.7v.3h-.7z" fill-rule="evenodd"/>
<path d="M240.1 147.7h.7v.3h-.7z" fill-rule="evenodd"/>
<path d="M240.1 148.2h.7v.3h-.7z" fill-rule="evenodd"/>
<path d="M240.1 148.7h.7v.3h-.7z" fill-rule="evenodd"/>
<path d="M240.1 149.2h.7v.3h-.7z" fill-rule="evenodd"/>
<path d="M240.1 149.7h.7v.3h-.7z" fill-rule="evenodd"/>
<path d="M240.1 150.2h.7v.3h-.7z" fill-rule="evenodd"/>
<path d="M240.1 150.7h.7v.3h-.7z" fill-rule="evenodd"/>
<path d="M240.1 151.2h.7v.3h-.7z" fill-rule="evenodd"/>
<path d="M239.8 154.2h.7v.8h-.7z" fill-rule="evenodd"/>
<path d="M238.1 154.2h.7v.8h-.7z" fill-rule="evenodd"/>
<path d="M200.3 165.9h.8v.7h-.8z" fill-rule="evenodd"/>
<path d="M200.3 164.2h.8v.7h-.8z" fill-rule="evenodd"/>
<path d="M216.9 152.8h.8v.7h-.8z" fill-rule="evenodd"/>
<path d="M216.9 151.1h.8v.7h-.8z" fill-rule="evenodd"/>
<path d="M222.7 141.9h.8v.8h-.8z" fill-rule="evenodd"/>
<path d="M222.7 140.3h.8v.8h-.8z" fill-rule="evenodd"/>
<path d="M180.7 132.5l.7-.1 .2 .2v.9l-.1 .3h-.7l-.2-.2z" fill-rule="evenodd"/>
<path d="M178.8 132.5l.8-.1 .2 .2v.9l-.2 .3h-.6l-.2-.2z" fill-rule="evenodd"/>
<path d="M177.5 149.8h.6v.8h-.6z" fill-rule="evenodd"/>
<path d="M175.8 149.8h.7v.8h-.7z" fill-rule="evenodd"/>
<path d="M235.1 138.8l.6 .1-.1 1.8-.5-.1z" fill-rule="evenodd"/>
<path d="M233.9 138.8l.5 .1-.1 1.8-.5-.1z" fill-rule="evenodd"/>
<path d="M232.6 138.8l.6 .1-.1 1.8-.5-.1z" fill-rule="evenodd"/>
<path d="M231.3 138.8l.6 .1-.1 1.8-.5-.1z" fill-rule="evenodd"/>
<path d="M231.3 143.8h.6l-.1 1.9-.5-.1z" fill-rule="evenodd"/>
<path d="M232.6 143.8h.6l-.1 1.9-.5-.1z" fill-rule="evenodd"/>
<path d="M233.9 143.8h.5l-.1 1.9-.5-.1z" fill-rule="evenodd"/>
<path d="M235.1 143.8h.6l-.1 1.9-.5-.1z" fill-rule="evenodd"/>
<path d="M223.5 136.2h.8v.8h-.8z" fill-rule="evenodd"/>
<path d="M223.5 134.6h.8v.8h-.8z" fill-rule="evenodd"/>
<path d="M183.9 133.6h.7v.8h-.7z" fill-rule="evenodd"/>
<path d="M185.6 133.6h.7v.8h-.7z" fill-rule="evenodd"/>
<path d="M179.1 163h1.5v1.4h-1.5z" fill-rule="evenodd"/>
<path d="M179.1 167.6h1.5v1.2h-1.5z" fill-rule="evenodd"/>
<path d="M187 163h1.6v1.4h-1.6z" fill-rule="evenodd"/>
<path d="M187 167.6h1.6v1.2h-1.6z" fill-rule="evenodd"/>
<path d="M200.3 129.7h.7v.8h-.7z" fill-rule="evenodd"/>
<path d="M202 129.7h.7v.8h-.7z" fill-rule="evenodd"/>
<path d="M213.2 147.5h.8v.8h-.8z" fill-rule="evenodd"/>
<path d="M213.2 149.1h.8v.8h-.8z" fill-rule="evenodd"/>
<path d="M200.7 126h.6v.6h-.6z" fill-rule="evenodd"/>
<path d="M200.7 127.4h.6v.6h-.6z" fill-rule="evenodd"/>
<path d="M229.6 139.4h.8v.7h-.8z" fill-rule="evenodd"/>
<path d="M229.6 141.1h.8v.7h-.8z" fill-rule="evenodd"/>
<path d="M177.6 148.7h.4l.1 .3-.5 .1z" fill-rule="evenodd"/>
<path d="M177.6 148.2h.6v.2l-.6 .1z" fill-rule="evenodd"/>
<path d="M177.6 147.6h.4l.1 .3-.5 .1z" fill-rule="evenodd"/>
<path d="M175.9 147.6h.5v.4h-.5z" fill-rule="evenodd"/>
<path d="M175.8 148.2h.5l.1 .2-.6 .1z" fill-rule="evenodd"/>
<path d="M175.9 148.7h.5v.3h-.5z" fill-rule="evenodd"/>
<path d="M184 131.5h.5v1.4l-.5-.1z" fill-rule="evenodd"/>
<path d="M185.9 131.5h.5v1.4l-.5-.1z" fill-rule="evenodd"/>
<path d="M184.9 129.6l.6 .1-.1 1.3-.5-.1z" fill-rule="evenodd"/>
<path d="M211.8 145.3h.8v.8h-.8z" fill-rule="evenodd"/>
<path d="M211.8 143.8h.8v.7h-.8z" fill-rule="evenodd"/>
<path d="M197.3 130l.4-.1 .1 .4h-.4z" fill-rule="evenodd"/>
<path d="M197.2 130.5h.6v.3h-.6z" fill-rule="evenodd"/>
<path d="M197.3 131h.4l.1 .3-.4 .1z" fill-rule="evenodd"/>
<path d="M199 131h.4l.1 .3-.4 .1z" fill-rule="evenodd"/>
<path d="M199 130.5h.6v.3h-.6z" fill-rule="evenodd"/>
<path d="M199 130l.4-.1 .1 .4h-.4z" fill-rule="evenodd"/>
<path d="M196.6 147.2h.8v.6h-.8z" fill-rule="evenodd"/>
<path d="M196.6 148.8h.8v.7h-.8z" fill-rule="evenodd"/>
<path d="M213.3 143.1h.8v.7h-.8z" fill-rule="evenodd"/>
<path d="M213.3 144.8h.8v.7h-.8z" fill-rule="evenodd"/>
<path d="M190 126.8h.8v.8h-.8z" fill-rule="evenodd"/>
<path d="M188.5 126.8h.7v.8h-.7z" fill-rule="evenodd"/>
<path d="M234.7 147.8l.4-.1 .1 .4h-.4z" fill-rule="evenodd"/>
<path d="M234.6 148.3h.6v.3h-.6z" fill-rule="evenodd"/>
<path d="M234.7 148.8h.4l.1 .3-.4 .1z" fill-rule="evenodd"/>
<path d="M236.4 148.8h.4l.1 .3-.4 .1z" fill-rule="evenodd"/>
<path d="M236.4 148.3h.6v.3h-.6z" fill-rule="evenodd"/>
<path d="M236.4 147.8l.4-.1 .1 .4h-.4z" fill-rule="evenodd"/>
<path d="M177.7 163.2h.8v.7h-.8z" fill-rule="evenodd"/>
<path d="M177.7 164.8h.8v.7h-.8z" fill-rule="evenodd"/>
<path d="M225.2 142.8h1.2v1.4h-1.2z" fill-rule="evenodd"/>
<path d="M225.2 145h1.2v1.4h-1.2z" fill-rule="evenodd"/>
<path d="M226.9 145h1.2v1.4h-1.2z" fill-rule="evenodd"/>
<path d="M226.9 142.8h1.2v1.4h-1.2z" fill-rule="evenodd"/>
<path d="M236.6 144.8h.8v.7h-.8z" fill-rule="evenodd"/>
<path d="M236.6 143.2h.8v.8h-.8z" fill-rule="evenodd"/>
<path d="M177.7 166.3h.8v.8h-.8z" fill-rule="evenodd"/>
<path d="M177.7 167.8h.8v.8h-.8z" fill-rule="evenodd"/>
<path d="M219 145.4h.8v.9h-.8z" fill-rule="evenodd"/>
<path d="M217.7 145.4h.9v.9h-.9z" fill-rule="evenodd"/>
<path d="M216.5 145.4h.9v.9h-.9z" fill-rule="evenodd"/>
<path d="M219 146.7h.8v.8h-.8z" fill-rule="evenodd"/>
<path d="M217.7 146.7h.9v.8h-.9z" fill-rule="evenodd"/>
<path d="M216.5 146.7h.9v.8h-.9z" fill-rule="evenodd"/>
<path d="M219 147.9h.8v.9h-.8z" fill-rule="evenodd"/>
<path d="M217.7 147.9h.9v.9h-.9z" fill-rule="evenodd"/>
<path d="M216.5 147.9h.9v.9h-.9z" fill-rule="evenodd"/>
<path d="M220.1 143.8h.2l-.1 .8-.2-.1z" fill-rule="evenodd"/>
<path d="M219.6 143.8h.2l-.1 .8-.2-.1z" fill-rule="evenodd"/>
<path d="M219.1 143.8h.2l-.1 .8-.2-.1z" fill-rule="evenodd"/>
<path d="M218.6 143.8h.2l-.1 .8-.2-.1z" fill-rule="evenodd"/>
<path d="M218.1 143.8h.2l-.1 .8-.2-.1z" fill-rule="evenodd"/>
<path d="M217.6 143.8h.2l-.1 .8-.2-.1z" fill-rule="evenodd"/>
<path d="M217.1 143.8h.2l-.1 .8-.2-.1z" fill-rule="evenodd"/>
<path d="M216.6 143.8h.2l-.1 .8-.2-.1z" fill-rule="evenodd"/>
<path d="M216.1 143.8h.2l-.1 .8-.2-.1z" fill-rule="evenodd"/>
<path d="M214.8 145h.8v.2h-.7z" fill-rule="evenodd"/>
<path d="M214.8 145.5h.8v.2h-.7z" fill-rule="evenodd"/>
<path d="M214.8 146h.8v.2h-.7z" fill-rule="evenodd"/>
<path d="M214.8 146.5h.8v.2h-.7z" fill-rule="evenodd"/>
<path d="M214.8 147h.8v.2h-.7z" fill-rule="evenodd"/>
<path d="M214.8 147.5h.8v.2h-.7z" fill-rule="evenodd"/>
<path d="M214.8 148h.8v.2h-.7z" fill-rule="evenodd"/>
<path d="M214.8 148.5h.8v.2h-.7z" fill-rule="evenodd"/>
<path d="M214.8 149h.8v.2h-.7z" fill-rule="evenodd"/>
<path d="M216.1 149.6l.2 .1-.1 .8-.2-.1z" fill-rule="evenodd"/>
<path d="M216.6 149.6l.2 .1-.1 .8-.2-.1z" fill-rule="evenodd"/>
<path d="M217.1 149.6l.2 .1-.1 .8-.2-.1z" fill-rule="evenodd"/>
<path d="M217.6 149.6l.2 .1-.1 .8-.2-.1z" fill-rule="evenodd"/>
<path d="M218.1 149.6l.2 .1-.1 .8-.2-.1z" fill-rule="evenodd"/>
<path d="M218.6 149.6l.2 .1-.1 .8-.2-.1z" fill-rule="evenodd"/>
<path d="M219.1 149.6l.2 .1-.1 .8-.2-.1z" fill-rule="evenodd"/>
<path d="M219.6 149.6l.2 .1-.1 .8-.2-.1z" fill-rule="evenodd"/>
<path d="M220.1 149.6l.2 .1-.1 .8-.2-.1z" fill-rule="evenodd"/>
<path d="M220.7 149h.8v.2h-.8z" fill-rule="evenodd"/>
<path d="M220.7 148.5h.8v.2h-.8z" fill-rule="evenodd"/>
<path d="M220.7 148h.8v.2h-.8z" fill-rule="evenodd"/>
<path d="M220.7 147.5h.8v.2h-.8z" fill-rule="evenodd"/>
<path d="M220.7 147h.8v.2h-.8z" fill-rule="evenodd"/>
<path d="M220.7 146.5h.8v.2h-.8z" fill-rule="evenodd"/>
<path d="M220.7 146h.8v.2h-.8z" fill-rule="evenodd"/>
<path d="M220.7 145.5h.8v.2h-.8z" fill-rule="evenodd"/>
<path d="M220.7 145h.8v.2h-.8z" fill-rule="evenodd"/>
<path d="M227 137.8h.8v.8h-.8z" fill-rule="evenodd"/>
<path d="M225.5 137.8h.7v.8h-.7z" fill-rule="evenodd"/>
<path d="M200.3 168.8h.8v.8h-.8z" fill-rule="evenodd"/>
<path d="M200.3 167.2h.8v.8h-.8z" fill-rule="evenodd"/>
<path d="M190 165.8h1v.8h-1z" fill-rule="evenodd"/>
<path d="M190 168h1v.8h-1z" fill-rule="evenodd"/>
<path d="M197.2 165.8h1.1v.8h-1.1z" fill-rule="evenodd"/>
<path d="M197.2 168h1.1v.8h-1.1z" fill-rule="evenodd"/>
<path d="M191.5 164.8h.7v1.5h-.7z" fill-rule="evenodd"/>
<path d="M194.5 164.8h.7v1.5h-.7z" fill-rule="evenodd"/>
<path d="M196 164.8h.7v1.5h-.7z" fill-rule="evenodd"/>
<path d="M222.2 149.6h.6v.8h-.6z" fill-rule="evenodd"/>
<path d="M223.8 149.6h.7v.8h-.7z" fill-rule="evenodd"/>
<path d="M227 139.3h.8v.8h-.8z" fill-rule="evenodd"/>
<path d="M225.5 139.3h.7v.8h-.7z" fill-rule="evenodd"/>
<path d="M167.9 150.9h1.5v.3h-1.5z" fill-rule="evenodd"/>
<path d="M167.9 150.4h1.5v.3h-1.5z" fill-rule="evenodd"/>
<path d="M167.9 149.9h1.5v.3h-1.5z" fill-rule="evenodd"/>
<path d="M167.9 149.4h1.5v.3h-1.5z" fill-rule="evenodd"/>
<path d="M167.9 148.9h1.5v.3h-1.5z" fill-rule="evenodd"/>
<path d="M167.9 148.4h1.5v.3h-1.5z" fill-rule="evenodd"/>
<path d="M167.9 147.9h1.5v.3h-1.5z" fill-rule="evenodd"/>
<path d="M167.9 147.4h1.5v.3h-1.5z" fill-rule="evenodd"/>
<path d="M167.9 146.9h1.5v.3h-1.5z" fill-rule="evenodd"/>
<path d="M167.9 146.4h1.5v.3h-1.5z" fill-rule="evenodd"/>
<path d="M167.9 145.9h1.5v.3h-1.5z" fill-rule="evenodd"/>
<path d="M167.9 145.4h1.5v.3h-1.5z" fill-rule="evenodd"/>
<path d="M167.9 144.7h1.5v.5h-1.5z" fill-rule="evenodd"/>
<path d="M214.9 142.3h.7v.8h-.7z" fill-rule="evenodd"/>
<path d="M216.4 142.3h.8v.8h-.8z" fill-rule="evenodd"/>
<path d="M228.8 143.5h.8v.7h-.8z" fill-rule="evenodd"/>
<path d="M228.8 145h.8v.8h-.8z" fill-rule="evenodd"/>
<path d="M209.8 125.3h.8v2.4h-.8z" fill-rule="evenodd"/>
<path d="M209.8 129.2h.8v2.4h-.8z" fill-rule="evenodd"/>
<path d="M208.5 125.3h.8v2.4h-.8z" fill-rule="evenodd"/>
<path d="M208.5 129.2h.8v2.4h-.8z" fill-rule="evenodd"/>
<path d="M207.3 125.3h.7v2.4h-.7z" fill-rule="evenodd"/>
<path d="M207.3 129.2h.7v2.4h-.7z" fill-rule="evenodd"/>
<path d="M206 125.3h.7v2.4h-.7z" fill-rule="evenodd"/>
<path d="M206 129.2h.7v2.4h-.7z" fill-rule="evenodd"/>
<path d="M204.7 125.3h.8v2.4h-.8z" fill-rule="evenodd"/>
<path d="M204.7 129.2h.8v2.4h-.8z" fill-rule="evenodd"/>
<path d="M221.1 151.1h.7v.8h-.7z" fill-rule="evenodd"/>
<path d="M219.4 151.1h.7v.8h-.7z" fill-rule="evenodd"/>
<path d="M189.8 124.6l.7-.1 .2 .2v.9l-.1 .3h-.7l-.2-.2z" fill-rule="evenodd"/>
<path d="M191.6 124.6l.7-.1 .2 .2v.9l-.1 .3h-.6l-.3-.2z" fill-rule="evenodd"/>
<path d="M191.3 127.7h.6v.2h-.6z" fill-rule="evenodd"/>
<path d="M191.8 127.5h.1v.3h-.1z" fill-rule="evenodd"/>
<path d="M191.3 128.1h.6v.2h-.6z" fill-rule="evenodd"/>
<path d="M191.3 128.5h.6v.2h-.6z" fill-rule="evenodd"/>
<path d="M191.3 128.9h.6v.2h-.6z" fill-rule="evenodd"/>
<path d="M191.3 129.3h.6v.2h-.6z" fill-rule="evenodd"/>
<path d="M192.2 129.1h.2v.6h-.2z" fill-rule="evenodd"/>
<path d="M192.6 129.3h.6v.2h-.6z" fill-rule="evenodd"/>
<path d="M192.6 128.9h.6v.2h-.6z" fill-rule="evenodd"/>
<path d="M192.6 128.5h.6v.2h-.6z" fill-rule="evenodd"/>
<path d="M192.6 128.1h.6v.2h-.6z" fill-rule="evenodd"/>
<path d="M192.6 127.7h.6v.2h-.6z" fill-rule="evenodd"/>
<path d="M192.2 127.5h.2v.6h-.2z" fill-rule="evenodd"/>
<path d="M219.3 168.8h.8v.8h-.8z" fill-rule="evenodd"/>
<path d="M219.3 167.2h.8v.8h-.8z" fill-rule="evenodd"/>
<path d="M175.8 146.1h.7v.8h-.7z" fill-rule="evenodd"/>
<path d="M177.5 146.1h.6v.8h-.6z" fill-rule="evenodd"/>
<path d="M193.8 126.8h.8v.8h-.8z" fill-rule="evenodd"/>
<path d="M195.4 126.8h.7v.8h-.7z" fill-rule="evenodd"/>
<path d="M195.1 148.7h.8v.8h-.8z" fill-rule="evenodd"/>
<path d="M195.1 147.2h.8v.7h-.8z" fill-rule="evenodd"/>
<path d="M221.2 142h.8v.7h-.8z" fill-rule="evenodd"/>
<path d="M221.2 140.3h.8v.7h-.8z" fill-rule="evenodd"/>
<path d="M196.6 150.3h.8v.8h-.8z" fill-rule="evenodd"/>
<path d="M195 150.3h.8v.8h-.8z" fill-rule="evenodd"/>
<path d="M200.3 131.3h.7v.8h-.7z" fill-rule="evenodd"/>
<path d="M202 131.3h.7v.8h-.7z" fill-rule="evenodd"/>
<path d="M198.2 147.3h.8v.7h-.8z" fill-rule="evenodd"/>
<path d="M198.2 145.7h.8v.8h-.8z" fill-rule="evenodd"/>
<path d="M227 141.3h.8v.8h-.8z" fill-rule="evenodd"/>
<path d="M225.4 141.3h.8v.8h-.8z" fill-rule="evenodd"/>
<path d="M217 136.3h.9v.8h-.9z" fill-rule="evenodd"/>
<path d="M217 134.8h.9v.8h-.9z" fill-rule="evenodd"/>
<path d="M220.9 136.4h1.2v.5l-1.2 .1z" fill-rule="evenodd"/>
<path d="M220.9 135.5l1.2-.1v.5l-1.2 .1z" fill-rule="evenodd"/>
<path d="M220.9 134.5h1.2v.5l-1.2 .1z" fill-rule="evenodd"/>
<path d="M218.6 134.5h1.2l.1 .5-1.3 .1z" fill-rule="evenodd"/>
<path d="M218.6 136.4h1.2l.1 .5-1.3 .1z" fill-rule="evenodd"/>
</g>
<g fill="none" stroke="#db9de1" stroke-width=".18">
<path d="M176.3 131.4a.36 .36 0 0 0 .3 .5 .36 .36 0 0 0 .3-.5M176.5 130.7h.5M176.5 130.4h.5M176.5 130.1l.1 .3M176.5 127.8v.3M176.5 129.6l.1 .3M176.5 129.9h.5M176.5 128.7h.5M176.9 130.7l.1 .3-.5 .1M177 129.1l-.1 .3h-.4v-.3l.1-.1 .1 .4M177 127.8l-.1 .2h-.7M177 128.3l-.5 .1v.3"/>
<path d="M177.5 128.6h.6M177.8 128.3v.6M206 132a.4 .4 0 0 1 .4 .4 .4 .4 0 0 1-.4 .4zM206.7 132.5l.4-.1v-.1h-.4l.1 .4h.3M207.5 132.3l.2-.1 .2 .2-.1 .3h-.3M207.5 132v.8M208.2 132.2v.5h.3M208.5 132.2v.6M209.3 132.7h-.4l.1-.4h.3v.6l-.2 .1h-.2M211.4 132.9l.2 .8 .3-.8M212.2 133.6v.1M212.2 133.2h.2l.1 .1-.1 .4-.3-.1z"/>
<path d="M212.9 132.9v.7l.1 .1M213.2 133.2h.3M213.3 132.9v.7l.2 .1M213.8 133.2h.3v.5M214.1 133.4l-.4 .1 .1 .2h.3M214.8 133.7l-.3-.1v-.4h.3v.6l-.1 .2h-.2M215.2 133.5l.4-.1-.1-.2-.3 .1v.4h.3M215.5 126h.6M215.5 131h.6M215.8 125.7v.6M215.8 130.7v.6M216.4 125.5h.5l-.3 .3h.2v.4h-.4"/>
<path d="M216.4 131.3h.5M216.4 130.8l.3-.3v.8M217.1 125.5l.3 .8 .2-.8M217.1 130.5l.3 .8 .2-.8M217.8 125.5h.5l-.2 .3h.2v.4h-.5M218 130.9l-.1-.2 .1-.2 .3 .2-.1 .2M218 130.9l-.1 .1 .1 .3 .3-.1-.1-.3M218 130.9h.2M168.1 153.3a.4 .4 0 0 1 .4 .4 .4 .4 0 0 1-.4 .4zM168.8 153.8l.4-.1v-.1h-.4l.1 .4h.3M169.5 153.5l.2 .6 .2-.6M170.2 153.3h.1"/>
<path d="M170.2 153.5v.6M170.9 153.6l-.2-.1-.2 .2 .1 .3h.3M171.2 153.8l.4-.1-.1-.1h-.3v.4h.3M242.6 153.9v.8M242.6 154.3h.4M243 153.9v.8M243.5 154.2h.1l.2 .1-.2 .4-.2-.2zM244.4 154.2l-.3 .1 .3 .2v.1h-.3M244.7 154.2h.3M244.8 153.9v.7l.2 .1M201.7 169.5h.8M201.8 169.8a.36 .36 0 0 0 .3 .5 .36 .36 0 0 0 .3-.5"/>
<path d="M202 167.8l.1 .2M202 168h.5M202 167.2h.6l.2 .2-.1 .1M202 167.2v.2l.1 .2 .4-.1v-.3M202.2 168.4l.1 .4 .2-.1v-.3M202.5 166.5l-.1 .4-.4-.1v-.3h.2v.4M202.5 168.4l-.5 .1v.3M202.5 169.1l-.5 .1v.3M206 169h.7l.1 .2-.1 .3h-.7M206 166.8v.5M206 167h.8M206.4 168v-.4l-.3-.1-.1 .5h.8"/>
<path d="M206.6 168.3v.4M206.8 168.2l-.8 .3 .8 .3M206.8 167.5l-.4 .3M208.4 165.5v.4M208.4 165.7h.8M208.4 164.3a.43 .43 0 0 1 .5-.2 .43 .43 0 0 1 .3 .5h-.8zM208.7 164.9l.5 .4M209.2 164.9l-.5 .4M210.9 164.6h.8l-.8 .4h.8M211 165.4a.36 .36 0 0 0 .3 .5 .36 .36 0 0 0 .3-.5h-.2v.1M211 163.9a.43 .43 0 0 1 .5-.1 .43 .43 0 0 1 .2 .4h-.8zM213.6 164a.42 .42 0 0 1 .5 0 .42 .42 0 0 1 .2 .4h-.8z"/>
<path d="M213.7 164.7l.6 .4M213.9 165.8l-.1-.4h-.3v.4h.8M214.3 165.4l-.4 .2M214.3 164.7l-.6 .4M220.7 169h.6l.2 .1-.2 .3h-.6M220.7 167.5l.2-.1 .2 .1 .2-.1 .2 .1v.3h-.8zM220.7 168.2l.1 .4a.33 .33 0 0 0 .4-.4h.3v.4M221.1 167.5v.3"/>
</g>
<g fill="#db9de1">
<path d="M181 160.9a.31 .31 0 0 1 .4 .3 .31 .31 0 0 1-.4 .3z" fill-rule="evenodd"/>
<path d="M180.3 160.3h6.4v2.4h-6.4v-1.9h.4v1.6h.3v-.7l.2 .2 .2 .5h1.3v-.2h-.5v-.6h.5v-.2h-.5v-.2h.8l.1 .3a.58 .58 0 0 1 .5 .7l-.3 .1-.2-.2v.3l.4 .1 1.6-.1v-.2h-.6v-.6h.5v-.2h-.5v-.5h1.2v1.5h.2v-1.5h.4v-.2h-1v.2h-.2v-.2h-.9v1.7h-.6a.58 .58 0 0 0 .3-.6 .58 .58 0 0 0-.5-.4v-.4h.5v-.2a.55 .55 0 0 0-.9 .4h-.8v-.3h.5v-.2h-.8v1.7h-.2l-.3-.7a.56 .56 0 0 0 .1-.8 .56 .56 0 0 0-.8-.1h-.4z" fill-rule="evenodd"/>
</g>
<path d="M201.9 126.3v2h1.2v-2M203.4 151.1v.3M204.4 151.1v.3M220.5 152.5h.3M220.5 153.5h.3M219.2 165.2v.4M220.2 165.2v.4" fill="none" stroke="#db9de1" stroke-width=".18"/>
<g fill="#db9de1">
<path d="M235.6 129.3h.3v.4h-.3z" fill-rule="evenodd"/>
<path d="M238.4 128.6h.2l.2 .9 .2-.9h.2l-.3 1.1h-.2z" fill-rule="evenodd"/>
<path d="M228.2 128.6h.7l-.5 .9h.5v.2h-.7l.4-.9h-.4z" fill-rule="evenodd"/>
<path d="M230.1 128.6h.2l.1 .8 .1-.8h.2l.1 .9 .1-.9h.2l-.2 1.1h-.2l-.1-.9-.2 .9h-.2z" fill-rule="evenodd"/>
<path d="M234.3 128.1h.2v.5l.5 .1 .1 1h-.2v-.8l-.2-.2-.2 .1v.9h-.2z" fill-rule="evenodd"/>
<path d="M232.5 128.2h.2v.4h.3v.2h-.3v.7h.3v.2h-.4l-.1-.2v-.7h-.3v-.2h.3z" fill-rule="evenodd"/>
<path d="M233.4 128.7l.6-.1v.4h-.2v-.3a.37 .37 0 0 0-.3 .5 .37 .37 0 0 0 .5 .3v.1a.57 .57 0 0 1-.7-.2 .57 .57 0 0 1 .1-.7z" fill-rule="evenodd"/>
<path d="M236.9 128.1h.2v1.5a.51 .51 0 0 1-.5 0 .51 .51 0 0 1-.3-.5h.3l.1 .4h.2l-.1-.7h-.2v.3h-.3a.41 .41 0 0 1 .1-.4 .41 .41 0 0 1 .5-.1z" fill-rule="evenodd"/>
<path d="M229.3 128.6h.6v.2l-.3-.1-.2 .2 .3 .2a.37 .37 0 0 1 .2 .5 .37 .37 0 0 1-.6 .1l-.1-.3 .3 .1 .2-.1-.5-.4z" fill-rule="evenodd"/>
<path d="M237.5 128.7a.44 .44 0 0 1 .5-.1 .44 .44 0 0 1 .2 .6h-.6l.1 .2 .4 .1v.1a.51 .51 0 0 1-.6 0 .51 .51 0 0 1-.1-.6h.6l-.2-.3-.2 .3h-.2z" fill-rule="evenodd"/>
<path d="M231.3 128.6a.43 .43 0 0 1 .4 0 .43 .43 0 0 1 .3 .4v.6a.51 .51 0 0 1-.8-.3l.6 .2v-.4l-.6 .2 .1-.2 .5-.1-.1-.2h-.4z" fill-rule="evenodd"/>
</g>
<g fill="none" stroke="#db9de1" stroke-width=".18">
<path d="M180 132.4h.4M180 133.8h.4M183.6 130.6v1.3M184.9 133.5h.4M184.9 134.5h.4M186.8 130.6v1.3M189.5 126.7h.3M189.5 127.7h.3M194.3 124.5h.4M194.3 125.9h.4M200.4 127.7v-2h1.2v2M201.3 129.6h.4"/>
<path d="M201.3 130.6h.4M223.4 135.7v.2M224.4 135.7v.2M176.7 149.7h.5M176.7 150.7h.5M196.5 148.1v.5M197.5 148.1v.5M211.7 144.8v.3M212.7 144.8v.3M213.1 148.6v.2M213.2 144.1v.4M214.1 148.6v.2"/>
<path d="M214.2 144.1v.4M216.8 152.1v.4M217.8 152.1v.4M222.6 141.4v.2M223.6 141.4v.2M229.5 140.4v.4M230.5 140.4v.4M239.1 154.1h.4M239.1 155.1h.4M241.2 141.6h.4M241.2 142.6h.4M200.2 165.2v.4"/>
<path d="M201.2 165.2v.4"/>
</g>
<path d="M183.4 132.2l.3 .2-.3 .2z" fill="#db9de1" stroke="#db9de1" stroke-width=".18"/>
<g fill="#db9de1">
<path d="M236.8 124.9h1l.1 .9h.2v-.9h1.1v2.5l-1.1-.1v-.6l.2-.4-.3-.2-.3 .2 .2 .4-.1 .7-1-.1z" fill-rule="evenodd"/>
<path d="M231.6 125h2.2v.9h-.5v1.5h-1.2v-1.3l.8 .2 .2-.3-.3-.3-.3 .2h-.9z" fill-rule="evenodd"/>
<path d="M219.5 124.9h2.5l-.5 1.3h.5v1.2h-2.5l.4-1.3h-.4z" fill-rule="evenodd"/>
<path d="M234.3 125h1.7l.2 .1 .1 .9h-.9l-.3-.2-.3 .3 .1 .3 .2 .1 .4-.2h.8v.8l-.2 .2-1.8 .1z" fill-rule="evenodd"/>
<path d="M222.5 125.1l.3-.2h2v1.3h-.4l.4 .3v.4l-.1 .3-.4 .2h-1.9v-1.2h.5l-.6-.4v-.4z" fill-rule="evenodd"/>
<path d="M230.3 124.8l1.5 2.6-2-.1 .4-.7 .3-.1 .2-.2-.2-.4-.3-.1-.2 .2v.5l-.5 .8h-.7z" fill-rule="evenodd"/>
<path d="M225.3 125h4.3l-1.5 2.5-.9-1.5v-.4l-.1-.2a.37 .37 0 0 0-.6 .3 .37 .37 0 0 0 .4 .4l.4 .6-.5 .8z" fill-rule="evenodd"/>
<circle cx="232.8" cy="126" r=".17"/>
<circle cx="226.9" cy="125.7" r=".19"/>
<circle cx="230.3" cy="126.2" r=".2"/>
<circle cx="235.1" cy="126.2" r=".18"/>
<circle cx="238" cy="126.4" r=".17"/>
</g>
<path d="M226.5 137.7h.3M226.5 138.7h.3M228.3 142.6h-3.3v4M236.5 144.2v.3M237.5 144.2v.3M177.6 164.1v.5M177.6 167.3v.3M178.6 167.3v.3M178.6 164.1v.5M200 167.6v2.3h1.4v-2.3" fill="none" stroke="#db9de1" stroke-width=".18"/>
<g fill="#db9de1">
<path d="M241.2 160.9l.3-.1v.5h-.3z" fill-rule="evenodd"/>
<path d="M222 160.4l.4-.1v.9l-.2 .1-.2-.2z" fill-rule="evenodd"/>
<path d="M228.8 160.4l.1-.1a.53 .53 0 0 1 .4 .5 .53 .53 0 0 1-.3 .6l-.2-.1z" fill-rule="evenodd"/>
<path d="M232.9 160.4l.1-.1a.52 .52 0 0 1 .5 .5 .52 .52 0 0 1-.4 .5l-.2-.2z" fill-rule="evenodd"/>
<path d="M221.2 159h25.2v3.4h-25.2v-1.6h.4l.2 .6h.6l-.2 .4-.4 .1v.3l.5-.1 .4-.5h12.9l.7-1.8h1.1l-.7 1.7h1v-.2h-.6l.5-1.3h.5l.1 .4 .2 .2a.41 .41 0 0 1 .4 .6 .41 .41 0 0 1-.7 0v.2l.1 .1a.62 .62 0 0 0 .9-.3 .62 .62 0 0 0-.5-.8l-.2-.2 .1-.4 .6 .1v-.3l-.2-.1h.4l.2 2h.3l.1-1.3 .2 1.3h.4v-.4h.3l.2 .3 .2 .2 .6-.1v-1.1l-.1-.2h.5v.2h.3l.1 1.1h.6v-.2h-.4v-.5h.8l.1 .6 .5 .2 1-.1v-1.1l.3-.1 .2 .2v1h.3v-1.1l-.2-.3-.6 .1v-.7h-.3v2h-.5h.1v-.2h-.1a.51 .51 0 0 1-.5-.4 .51 .51 0 0 1 .4-.6v.3h.3v-.5h-.2a.64 .64 0 0 0-.8 .7h-.8v-.4h.4v-.2h-.4v-.6h-.3v.6h-1.6v.2h.1a.33 .33 0 0 1 .5 .2l-.4 .1-.3 .4h-.3l.1-1.6h-.2l-.1 1.8-.2-1.4h-.2l-.2 1.2-.1-1.6h-1.1l-.3 .1-.1 .4h-.5l.1-.5h-1v.3h-.4l.1-.3h-.2l-.9 2.1h-12.6v-1.5h-.2h.6v.2h.4v1.2h.3v-1.3h.6v.2h.3v.9l.4 .3 1-.1v-1.1l.2-.1 .2 .2v1h.3v-.4h.3l.1 .4 .3 .1 3.1-.1v-.4h-.4v.4h-1l.3-.2 .1-.5h1.6a.66 .66 0 0 0 .3 .7 .66 .66 0 0 0 .7 0v-.2l-.3 .1-.3-.2-.1-.4h1a.59 .59 0 0 0 .6 .8 .59 .59 0 0 0 .6-.8l-.2-.6h.4v1.3h.2v-1.1l.2-.1 .1 1.2h.2v-1.1l.2-.1v1.2h.3l-.1-1.3h-1.6a.6 .6 0 0 0-.6 0 .6 .6 0 0 0-.3 .6h-1l.2-.5h.2v.3h.3v-.5h-.1a.64 .64 0 0 0-.9 .7h-1.6l-.2-.6-.6-.1v-.6h-.3v2h-.4v-1.4h-.3l.1 1.2h-.4l-.1-1.2h-.3v1h-.3l-.1-.9-.3-.1-.3 .1v-.7h-.3v2h-.4v-.2h-.4l-.1-.9h.5v-.2h-.5v-.6h-.2v.6l-2.7-.1-.2 .1-.2 .6h-.4v-1h2.6v-.3h-.4v.3h-2.2z" fill-rule="evenodd"/>
</g>
<path d="M226.5 139.2h.3M223.1 149.5h.5M223.1 150.5h.5M226.5 140.2h.3" fill="none" stroke="#db9de1" stroke-width=".18"/>
<g fill="#db9de1">
<path d="M193.5 162.7l.2 .8h-.3z" fill-rule="evenodd"/>
<path d="M194.5 162.6a.31 .31 0 0 1 .4 .3 .31 .31 0 0 1-.4 .3z" fill-rule="evenodd"/>
<path d="M190.4 162h7.4v2.4h-7.4v-1.1h.3a.66 .66 0 0 0 .8 .8h.7v-.8h.4v.8h.7v-.4h.4l.1 .4h.3l-.4-1.6h.6v1.6h.2v-.7l.3 .2 .2 .5h.2l-.3-.7 .5-.1a.65 .65 0 0 0 .1 .7 .65 .65 0 0 0 .7 .1h1.3v-.2h-.6v-.6h.5v-.2h-.5v-.5h.6v-.2h-.9v1.7h-.4h.2v-1h-.6v.2h.3v.6a.66 .66 0 0 1-.4-1l.1-.2h.5v-.2a.67 .67 0 0 0-.7 .1 .67 .67 0 0 0-.2 .7h-.3a.57 .57 0 0 0-.1-.8 .57 .57 0 0 0-.7 0l-.9-.1-.4 1.7h-.1v-1.7h-.3v.7h-.4v-.7h-.3v1.7h-.4l.1-.2a.46 .46 0 0 1-.5-.1 .46 .46 0 0 1-.1-.5l.2-.7h.2v.4h.2v-.5a.65 .65 0 0 0-.7 .1 .65 .65 0 0 0-.2 .7h-.3z" fill-rule="evenodd"/>
</g>
<g fill="none" stroke="#db9de1" stroke-width=".18">
<path d="M190.9 124.5h.4M190.9 125.9h.4M191.4 129.8h.5M192.6 129.8h.5M192.7 127.5h.4M194.8 126.7h.3M194.8 127.7h.3M201.3 131.2h.4M201.3 132.2h.4M216.9 135.8v.3M218 135.8v.3M176.7 146h.5"/>
<path d="M176.7 147h.5M195 148.2v.3M196 148.2v.3M196.1 150.2h.2M196.1 151.2h.2M198.1 146.7v.3M199.1 146.7v.3M215.9 142.2h.3M215.9 143.2h.3M220.4 151h.4M220.4 152h.4M221.1 141.3v.4"/>
<path d="M222.1 141.3v.4M223.7 144.4v.4M224.7 144.4v.4M226.5 142.2h.2M226.5 141.2h.2M228.7 144.5v.3M229.7 144.5v.3M219 167.6v2.3h1.4v-2.3"/>
</g>
<path d="M191.3 127.2v.3h-.3z" fill="#db9de1" stroke="#db9de1" stroke-width=".18"/>
<g fill="none" stroke="#744679" stroke-width=".18">
<path d="M177.1 119.7l6.2 12.4M183.3 119.7l-6.2 12.4M169.8 127.1l.5-.1v-.3l-.5-.1v1M170 127.1l.4 .5M170.8 127h.3M171.3 126.6h-.5v1h.5M171.7 127h.3M172.2 126.6h-.5v1M172.5 126.7l.2 .1M172.7 126.6v.2M172.7 126.8l-.1 .2M172.7 126.8l.1 .2"/>
<path d="M172.9 126.7l-.2 .1M173.2 126.7l.3 .1M173.5 126.6v.2M173.5 126.8l-.2 .2M173.5 126.8l.1 .2M173.7 126.7l-.2 .1M177.6 126.2h5.2zM177.6 126.2l.1 2zM177.7 128.1l-.1 .1 .7 .6M177.7 128.1l.6 .7M178.2 127.4h3.9M178.3 128.7l4.5 .1z"/>
<path d="M178.4 127l.7 1M178.6 120.2h.7zM178.6 120.2v6.1zM178.6 128.7v2zM178.6 130.6h.7zM179.1 127l-.7 1M179.2 132.5h2v1.2h-2zM179.2 120.2v6.1zM179.2 128.7v2zM179.4 133.1h.2v-.2l-.2-.1v.5M179.5 133.1l.1 .2M179.7 126.9l-.3 .7h.7"/>
<path d="M179.9 127.3v.7M179.9 132.8l-.1 .4h.3M180.1 133v.3M180.3 133.3h.3M180.3 133l.2-.2v.5M180.5 127.1l.1-.1a.53 .53 0 0 1 .4 .5 .53 .53 0 0 1-.4 .5l-.2-.4zM180.8 132.9l.1-.1 .2 .1M180.8 132.9l.1 .1M180.8 132.9h.1M180.8 133.1h.1M180.9 133h.1M180.9 133l-.1 .1"/>
<path d="M181 133l.1 .1-.1 .2h-.2v-.2M181.1 132.9h.1M181.1 132.9l-.1 .1M181.1 120.2h.7zM181.1 120.2v6.1zM181.1 128.7v2zM181.1 130.6h.7zM181.8 120.2v6.1zM181.8 128.7v2zM181.9 127h-.5l-.1 .4h.5l.1 .5-.2 .1-.4-.1M182.7 126.2v2.6zM183.8 130.6h2.8v1.3h-2.5l-.3-.3z"/>
<path d="M184.3 133.6h1.6v.8h-1.6zM184.5 134l.2 .2M184.6 133.8h-.2v.4M184.6 133.8h.1M184.6 133.8v.2h-.2M184.9 133.8l-.1 .2h.3M185 133.9v.3M185 131.1h.1M185 131.1h.3M185.1 130.8v.1M185.1 131.3h.2M185.2 133.8h.2"/>
<path d="M185.2 133.8h.1M185.2 131.3v.2l-.2-.1M185.3 130.7v.2M185.3 131.1h.1M185.3 130.8h-.3h.1M185.4 131.6l-.1 .1M185.4 133.8h.1M185.4 131.6h.1M185.4 133.8l-.2 .4h.2M185.6 133.8v.3h.2M185.6 133.8h.1M185.7 133.8h.1"/>
<path d="M185.8 133.8v.3M185.8 134.1h.1M188.8 126.8h1.6v.8h-1.6zM189.2 127h-.2l-.1 .2 .1 .2 .2-.1M189.4 127l-.1 .2h.3M189.5 127.1v.3M189.7 127.1l.1 .3M189.7 127v.1M189.8 127.4h.1M189.8 127h.1M189.8 127h-.1M189.9 127v.1"/>
<path d="M189.9 127.1l-.1 .3M190.1 127.1v.1M190.1 127v.1M190.1 124.6h2v1.2h-2zM190.1 127h.1M190.1 127.2h.1M190.2 127l.1 .2-.2 .2M190.2 127h-.1M190.3 125.2h.2v-.2l-.2-.1v.5M190.3 127.2h-.1M190.4 125.2l.2 .2M190.9 124.9l-.2 .4h.4"/>
<path d="M191 125.1v.3M191.3 125l.2 .1-.1 .3-.2-.2zM191.7 125.4h.1M191.9 127.6h1.2v2h-1.7v-1.5zM192 124.9h-.3v.3h.3l-.1 .2h-.2M192 129.6h.5M192 127.7v.2h.3l-.1-.2M192.1 129.1a.23 .23 0 0 0 .2 .3 .23 .23 0 0 0 .2-.3M192.2 128.7h.3M192.3 127.7h-.1M192.3 127.7h.1M192.3 128.6v.3l-.3-.1"/>
<path d="M192.4 127.7h.1M192.5 129.1h.1M192.5 128.2h-.5l.1 .2h.4M192.5 128.2h.1M192.5 127.7h.1M192.5 127.7v.2M192.5 128.2v.1M192.5 128.3v.1M192.8 124.2l3.4 2M193.5 124.5l2.1 .1zM193.5 124.5v1.4zM193.5 125.8h2.1z"/>
<path d="M193.5 125.2h2M193.7 125.2h.2v-.2l-.2-.1v.5M193.8 125.2l.2 .2M194.2 126.8h1.6v.8h-1.6zM194.3 124.9l-.2 .4h.4M194.4 125.1v.3M194.5 127h-.1l-.1 .2 .1 .2 .1-.1M194.7 125h.2l-.1 .4a.24 .24 0 0 1-.2-.1 .24 .24 0 0 1 .1-.3zM194.7 125.4h.1M194.8 127l-.1 .2h.2M194.9 127.1v.3M195.1 127.1l.1 .3"/>
<path d="M195.1 125.2l.1-.1 .2 .1-.1 .2h-.2M195.1 127v.1M195.1 125.4h.1M195.2 127.4h.1M195.2 127h.1M195.2 127h-.1M195.3 127v.1M195.3 127.1l-.1 .3M195.3 124.9l-.2 .1v.4M195.5 124.5v1.4zM195.5 127.2h-.1M195.5 127.4h.1"/>
<path d="M195.5 127.1l.2 .1v.1M195.5 127.1v.1M195.6 127.4h-.1M195.6 127l-.1 .1v.3M195.7 127.3l-.1 .1M196.2 124.2l-3.4 2M198.1 129.8h.9v1.7h-1.3v-1.4zM198.1 131.6h.5M198.2 130.2h.2l.2 .1-.3 .1zM198.2 131.1a.22 .22 0 0 0 .2 .3 .22 .22 0 0 0 .2-.3M198.3 130.7h.3M198.5 130.6v.3l-.4-.1"/>
<path d="M198.6 129.7v.3l-.3-.3-.2 .1 .1 .2M200.5 129.7a.48 .48 0 0 1 .6-.1 .48 .48 0 0 1 .3 .4 .49 .49 0 0 1-.6 .3 .49 .49 0 0 1-.3-.5zM200.5 126.3h.9v1.4h-.9zM200.6 131.6a.52 .52 0 0 1 .6 0 .52 .52 0 0 1 .3 .5h-1zM200.7 129.7h1.6v.8h-1.6zM200.7 131.3h1.6v.8h-1.6zM200.8 130.7h.7M200.8 126.8h.4M200.9 130.1l.2 .2M200.9 131.7l.2 .2M201 126.8l.2 .3h-.4zM201 126.7v.1"/>
<path d="M201 127.1v.1M201 131.5h-.2v.4M201 131.5h.1M201 131.7h-.2M201 129.9h-.2v.4M201 129.9l.1 .1M201 131.5v.2M201 130.1h-.2M201 131.7h.1M201.1 130h.1M201.1 130l-.1 .1M201.1 130.5v.6l-.7-.2"/>
<path d="M201.3 129.9l-.1 .3h.3M201.3 131.5l-.1 .2h.3M201.4 130v.3M201.4 131.6v.3M201.5 128.7v.5M201.5 128.9h-1l.2 .3M201.6 130v.3M201.6 129.9l.2 .1v.3M201.6 130.3h.1M201.6 131.5v.3M201.6 129.9v.1M201.6 131.8v.1"/>
<path d="M201.6 130.3h.2M201.6 131.5h.2M201.6 131.9h.2M201.6 131.5h.1M201.8 131.5h.1M201.8 131.5v.3M201.8 130.3h.1M201.8 131.8v.1M201.9 131.5h.3l-.1 .1M201.9 131.8l.1 .1M202 129.9h.2M202 131.9h.2"/>
<path d="M202 129.8a.49 .49 0 0 1 .6-.3 .49 .49 0 0 1 .3 .5 .49 .49 0 0 1-.6 .3 .49 .49 0 0 1-.3-.5zM202 126.3h1v1.4h-1zM202.1 131.6l.1 .1M202.1 131.6a.52 .52 0 0 1 .6 0 .52 .52 0 0 1 .3 .5h-1v-.2M202.1 131.6l-.1 .3M202.2 131.7h.1M202.2 129.9v.1M202.2 131.7v.1M202.2 131.8v.1M202.2 130l-.3 .3h.3M202.3 130.7h.7M202.3 127.2h.4"/>
<path d="M202.3 126.9h.4l-.2 .3zM202.5 126.8v.1M202.5 127.2v.1M202.6 130.5v.6l-.7-.2M203 128.7v.6l-.8-.6-.2 .2 .1 .3M204.5 126.7h5.9l.4 .5v3h-6.3zM204.9 126.7v-1h.4v1M204.9 130.2v1h.4v-1M205.9 127.9l.6 1M206.2 126.7v-1h.4v1M206.2 130.2v1h.4v-1M206.5 127.9l-.6 1"/>
<path d="M207.1 127.9l-.2 .7h.6M207.3 128.2v.7M207.4 126.7v-1h.4v1M207.4 130.2v1h.4v-1M208 128l.1-.1a.53 .53 0 0 1 .3 .5 .53 .53 0 0 1-.3 .5 .66 .66 0 0 1-.1-.9zM208.7 126.7v-1h.4v1M208.7 130.2v1h.4v-1M208.8 128.9h.5M208.8 128.2l.3-.3v1M210 126.7v-1h.4v1M210 130.2v1h.4v-1M212.9 124.6h1.9v7.7h-2.6v-7z"/>
<path d="M213 129.7l.8 .1 .2 .3M213 127.9a.49 .49 0 0 1 .6-.2 .49 .49 0 0 1 .3 .5 .49 .49 0 0 1-.6 .2 .49 .49 0 0 1-.3-.5zM213.3 128.8h.7M213.6 128.7v.6l-.7-.2M214 126.8v.6l-.8-.6-.2 .2 .1 .4M217.1 135.1h.7v1.6h-.7zM217.3 135.3v.2M217.3 135.7v.1M217.3 135.8h.1M217.3 135.7h.3l-.3 .1M217.3 136.4h.1M217.3 135.7h.1"/>
<path d="M217.3 135.3h.1M217.4 136.1h.2M217.5 136v.2h-.3M217.6 136.4v.2h-.1h-.2v-.2M217.6 135.3v.2l-.3-.2M219.6 134.3h1.6v2.5l-.5 .4h-1.1zM220.1 136.5h.4M220.2 136.1v.1l.1 .1 .2-.1v-.1M220.3 135.7h.2M220.4 135.7v.2l-.3-.1M220.5 135.4h-.4l.4 .1M220.5 136.1h.1"/>
<path d="M220.5 135.4h.1M220.5 135.4v.1M220.5 135.5h.1M220.5 134.9v.3M220.5 135h-.4l.1 .2M223.5 135h.8v1.6h-.8zM223.7 135.6v.1M223.7 136.2l.1 .3h.2M223.8 135.1v.2M223.8 135.3h.1M223.8 135.1h.1M223.8 135.9h.3"/>
<path d="M223.9 135.3h-.1M223.9 135.1v.1M223.9 135.3h.1M223.9 135.2v.1M223.9 135.3h.2M223.9 135.1h.2M223.9 135.1h.1M224 135.8v.3l-.3-.1M224 136.5h.1M224.1 136.2l-.1 .3M224.1 135.5l-.4 .1M224.1 135.5h.1"/>
<path d="M224.1 135.1h.1M224.1 135.1v.2M224.1 135.5l-.1 .2h-.3M224.1 135.3h.1M225 134.6h2.5l.4 .4v1.2h-2.9zM225.7 135.1v.4M225.8 139.3h1.6v.8h-1.6zM225.8 137.8h1.6v.8h-1.6zM225.9 138.1l.1 .2h.2M226 138l-.1 .1M226.1 135.2h-.1l-.1 .1 .1 .2h.1M226.2 139.5h-.2l-.1 .2 .1 .2 .2-.1"/>
<path d="M226.2 138h-.2M226.4 135.1l-.1 .3h.2M226.4 138l-.1 .2h.3M226.4 139.5l-.1 .2h.3M226.5 135.3v.2M226.5 138.1v.3M226.5 139.6v.3M226.7 139.9h.2M226.7 138.4h.2M226.7 138.1l.1-.1v.4M226.7 139.6l.1-.1v.4M226.7 135.5h.1"/>
<path d="M226.8 135.2h-.1v.3M226.8 135.2h.1M226.8 135.2v.3M227.1 139.9h.2M227.1 139.6l.1-.1v.4M227.1 138l.1 .4 .1-.4M227.1 135.1l-.1 .3h.3M227.1 138h.2M227.1 138h.1M227.2 135.3v.2M227.3 138h.1M229.6 139.8h.8v1.6h-.8z"/>
<path d="M230 139.9v.2h-.1M230.1 140l-.3-.1v.2M230.1 140h.1M230.2 140v.1M241.8 127.1l.5-.1v-.3l-.5-.1v1M242 127.1l.4 .5M242.8 127h.3M243.3 126.6h-.5v1h.5M243.7 127h.3M244.2 126.6h-.5v1M244.5 126.7l.2 .1M244.7 126.6v.2"/>
<path d="M244.7 126.8l-.1 .2M244.7 126.8l.1 .2M244.9 126.7l-.2 .1M245.2 126.7l.3 .1M245.5 126.6v.2M245.5 126.8l-.2 .2M245.5 126.8l.1 .2M245.7 126.7l-.2 .1M157.2 144.2h8.4v-.4h3.6v9.1h-3.6v-.5h-8.4zM176.2 149.8h1.6v.8h-1.6zM176.2 146.1h1.6v.8h-1.6zM176.3 147.5h1.3v1.4l-.3 .3h-1z"/>
<path d="M176.4 150.2l.1 .2M176.4 146.5l.1 .2M176.5 146.3h-.2v.4M176.5 150h-.2v.4M176.5 150v.1M176.5 150.2h-.2M176.5 146.3v.1M176.5 146.4l-.2 .1M176.5 150.1h.1M176.5 150.1v.1M176.7 149.3h.5M176.7 147.9a.24 .24 0 0 1 .3-.1 .24 .24 0 0 1 .2 .2l-.4 .1z"/>
<path d="M176.7 147.4l.1 .2 .1-.1M176.8 148.8a.22 .22 0 0 0 .2 .3 .22 .22 0 0 0 .2-.3M176.8 147.9h-.1M176.8 147.4h-.1M176.8 147.4h.1M176.8 150l-.1 .2h.2M176.8 146.3l-.1 .2h.2M176.9 146.4v.3M176.9 150.1v.3M176.9 148.4h.3M176.9 147.4h.1M176.9 147.4l.1-.1 .2 .1-.1 .2-.2-.1"/>
<path d="M176.9 147.4v.1M177 148.3v.3l-.3-.1M177.1 150.4h.2M177.1 146.4l.1-.1v.4M177.1 150.1l.1-.1v.4M177.1 146.7h.2M177.5 150.3v.1M177.5 150.4h.1M177.6 150.1v.1M177.6 150.1l-.2 .1M177.6 150l-.1 .1v.2M177.6 150.4h.1"/>
<path d="M177.6 150.2v.2M177.7 146.3h-.2l-.1 .2h.2l.1 .1h-.3M195.1 147.5h.8v1.6h-.8zM195.3 148.8v.2M195.3 149h.1M195.4 150.3h1.6v.8h-1.6zM195.4 148.4h.3M195.5 147.7l-.1 .1-.1-.2v.3M195.5 147.6l.2 .1-.1 .2M195.5 147.6v.1M195.5 148.4v.2l-.2-.1M195.6 148.8v.2h-.2"/>
<path d="M195.7 148.1v.1M195.8 150.5h-.2l-.1 .2 .1 .2 .2-.1M196 150.5l-.1 .2h.3M196.1 150.6v.3M196.3 150.8v.1M196.3 150.5v.3M196.3 150.5h.2M196.3 150.9h.2M196.3 150.5h.1M196.5 150.5h.1M196.5 150.5v.3M196.5 150.8v.1"/>
<path d="M196.6 147.5h.8v1.6h-.8zM196.7 150.8v.1M196.7 150.9h.2M196.8 148.1v.1M196.9 150.5h-.2v.2h.2v.1M196.9 150.8v.1M196.9 148.4h.3M196.9 147.7h.3M197 148.8h-.2v.2h.4M197 148.8h.1M197 148.8v.2M197 148.4v.2l-.2-.1"/>
<path d="M197 147.6v.3l-.2-.1M197.2 148.8l-.2 .1M198.2 146.1h.8v1.6h-.8zM198.4 147.3v.2l.2 .1 .2-.1v-.2M198.5 149h4v3l-1 1h-3zM198.5 147h.3M198.5 146.2h.3M198.5 150.5v1M198.6 146.9v.3l-.2-.1M198.6 146.2v.2l-.2-.1M198.7 147.3h.1M198.7 146.6l-.3 .1 .3 .1"/>
<path d="M198.7 146.6h.1M198.8 146.6v.1M198.8 146.7l-.1 .1M199.6 150.6a.44 .44 0 0 0-.6 .4 .44 .44 0 0 0 .6 .4M200.2 150.4l-.2 .7h.6M200.5 150.8v.7M201.1 150.5h.1a.53 .53 0 0 1 .3 .5 .53 .53 0 0 1-.3 .5 .67 .67 0 0 1-.1-1zM201.8 150.5h.7l-.4 .4 .3 .1v.4l-.1 .1-.5-.1M203.5 150.5h.8v1.6h-.8zM203.7 151v.1M203.7 151l.1-.1 .3 .1M203.7 151.1l.1 .1 .3-.1"/>
<path d="M203.7 151.7v.2h.3M203.8 151.4h.3M203.9 151.3v.2h-.2M204 151.9h.1M204 151.7v.2M204.1 151v.1M204.1 150.7l-.4-.2v.3M211.8 144.1h.8v1.6h-.8zM212 145.5l.1 .1 .3-.1M212 145.4v.1M212 145.4h.1M212 144.2v.3"/>
<path d="M212 144.5h.1M212 144.2h.1M212.1 144.2v.1M212.1 145h.3M212.1 144.4v.1M212.1 144.4h.1M212.1 144.3v.1M212.1 144.4h.2M212.2 144.2l-.1 .1M212.2 144.2l.1 .2M212.2 144.2h.1M212.2 145v.2l-.3-.1"/>
<path d="M212.3 145.4h.1M212.3 144.4h.1M212.4 144.6v.2M212.4 145.4v.1M212.4 144.7h-.4l.1 .1M213.2 147.9h.8v1.6h-.8zM213.3 143.5h.8v1.6h-.8zM213.4 148v.2h.2v-.2h.2M213.4 149.1v.2l.2 .1 .2-.1v-.2M213.5 144.8v.2h.4M213.5 143.6v.2M213.5 143.8h.1"/>
<path d="M213.5 144.8h.2M213.5 144.8h.1M213.5 143.6h.1M213.5 148.8h.3M213.6 144.4h.3M213.7 144.8h.1M213.7 144.8v.2M213.7 148.7v.3l-.3-.1M213.7 144.3v.3l-.2-.1M213.8 148h.1M213.8 148v.2M213.8 148.2h.1"/>
<path d="M213.8 148.4v.2M213.8 148.5h-.4l.1 .1M213.9 144.7l-.2 .2M213.9 143.6v.3l-.4-.3M213.9 144v.2M213.9 144.1h-.4l.1 .1M215.2 144.1h5l1 1v5h-6zM215.2 142.3h1.6v.8h-1.6zM215.4 142.6l.1 .3M215.4 142.5v.1M215.5 142.9h.1M215.5 142.5h-.1"/>
<path d="M215.5 142.5h.1M215.6 142.5h.1M215.6 142.9h-.1M215.8 142.5l-.1 .3h.3M215.9 142.6v.3M216.1 142.9h.2M216.1 142.6l.1-.1v.4M216.5 142.7h.2v.2h-.2zM216.5 142.7h.1M216.7 142.5l-.2 .2M216.9 151.5h.8v1.6h-.8zM217.2 152.4h.3"/>
<path d="M217.3 152.8h-.2v.2h.4M217.3 151.6l-.1 .1-.1-.1v.3M217.3 152.8h.1M217.3 152.8v.2M217.3 151.6h.1M217.3 152.3v.3l-.2-.1M217.4 151.6h.1M217.5 151.6l-.1 .3M217.5 152.7l-.2 .2M217.5 152v.2M217.5 152.1h-.4l.1 .1M217.6 149h1"/>
<path d="M217.7 148a.44 .44 0 0 0 .4 .6 .44 .44 0 0 0 .4-.6M217.7 146.2a.48 .48 0 0 1 .6-.2 .48 .48 0 0 1 .3 .5 .49 .49 0 0 1-.6 .2 .49 .49 0 0 1-.3-.5zM218 147.1h.6M218.3 147v.6l-.7-.2M218.6 145.5l-1-.4v.6M219.8 151.1h1.6v.8h-1.6zM219.8 152.6h1.6v.8h-1.6zM219.9 151.5h.2v-.2h-.2v.4M219.9 153.1h.1M220 153.1h.2M220 151.5l.2 .2M220.2 152.8h-.2l-.1 .3"/>
<path d="M220.4 151.3l-.1 .2h.3M220.4 152.8l-.1 .2h.3M220.5 151.4v.3M220.5 152.9v.3M220.7 151.7h.2M220.7 151.4l.1-.1v.4M220.7 153.2h.2M220.7 152.9l.1-.1v.4M221.2 151.3l-.1 .2h.2M221.2 152.8l-.1 .2h.2M221.2 140.7h.8v1.6h-.8zM221.3 151.4v.3"/>
<path d="M221.3 152.9v.3M221.5 141.6h.3M221.6 142.2v-.2h-.2v.2h.4M221.6 141.5v.3l-.2-.1M221.8 141.3h-.4l.1 .1M221.8 141.9l-.2 .2M221.8 141l-.4-.2v.3M221.8 141.2v.2M222.5 149.6h1.6v.8h-1.6zM222.7 140.7h.8v1.6h-.8zM222.7 150l.2 .2M222.8 150h-.2"/>
<path d="M222.8 149.8h-.2v.4M222.8 149.8h.1M222.9 149.8v.2M222.9 150h-.1M222.9 142l.1 .2M222.9 141.9v.1M223 142.2h.1M223 141.3v.1M223 141.4h.1M223 141.6h.3M223.1 149.8l-.1 .2h.3M223.2 141.5v.3l-.3-.1"/>
<path d="M223.2 149.9v.3M223.3 141.9v.3h-.3M223.3 141.2v.2M223.3 141l-.4-.2v.3M223.3 141.3h-.3M223.4 143.1l1.6 3M223.4 149.8l.2 .1-.1 .3zM223.5 150.2h.1M223.8 143.8h.9zM223.8 143.8v1.7zM223.8 145.4h.9zM223.8 149.9h.1"/>
<path d="M223.8 149.9l.1 .1M223.8 150v.2M223.8 150.2h.1M224 150v.1l-.1 .1M224 145.1v.2h.4M224 149.8l-.2 .1M224 149.8h.1M224 149.9l-.1 .1M224 145.1h.2M224 149.8v.1M224 145.1h.1M224 149.9h.1"/>
<path d="M224.1 144.7h.3M224.2 145.1h.1M224.2 143.8v1.6M224.2 144.6v.3l-.2-.1M224.4 144.4h-.4l.1 .1M224.4 145l-.2 .2M224.4 143.9v.2M224.4 144.3v.2M224.4 144h-.4l.1 .1M224.6 143.8v1.7zM225 143.1l-1.6 3M225.6 143h2.1l.2 .2v2.8l-.2 .2h-2.1l-.2-.2v-2.8z"/>
<path d="M225.8 141.3h1.6v.8h-1.6zM226.1 141.5h-.1l-.1 .2 .1 .2h.2M226.1 141.5h.1M226.3 145.4l.3 .2M226.3 144.2a.34 .34 0 0 1 .4-.1 .34 .34 0 0 1 .2 .3 .34 .34 0 0 1-.4 .2 .34 .34 0 0 1-.2-.4zM226.4 141.5l-.1 .3h.3M226.4 143l-1 1M226.5 141.6v.3M226.5 144.9h.5M226.6 145.6h.4M226.6 145.6l-.3 .3M226.7 141.9h.2"/>
<path d="M226.7 141.6l.1-.1v.4M226.7 144.8v.4l-.5-.2M227 143.5v.4M227 143.7h-.7l.2 .2M227.1 141.5l.2 .1-.3 .3h.3M228.8 143.8h.8v1.6h-.8zM229 145.1v.1l.2 .1 .2-.1-.1-.1M229.1 144.7h.3M229.2 144l-.1 .1-.1-.2v.3M229.2 143.9h.1l.1 .2M229.2 143.9v.1M229.2 144.7v.2l-.2-.1"/>
<path d="M229.4 144.2h-.1M229.4 144.4h-.4l.1 .1M229.4 144.3v.2M229.4 144.1v.1M229.8 140.1h.1M229.9 140.7h.3M230 141.3v-.2h-.2v.2h.4M230 140.6v.3l-.2-.1M230.2 141l-.2 .2M230.2 140.3v.2M230.2 140.4h-.4l.1 .1M231.1 140.3h3.9l1 1v2.9h-4.9z"/>
<path d="M231.6 141.7v1M232.6 141.8a.43 .43 0 0 0-.6 .4 .43 .43 0 0 0 .6 .4M233.2 141.6l-.2 .7h.6M233.5 142v.7M234 141.8l.2-.1a.52 .52 0 0 1 .3 .5 .52 .52 0 0 1-.3 .5l-.3-.4zM235.1 147.9l.4-.3h1v1.7h-1.4zM235.4 142.1l-.1 .2h-.3l-.1-.5 .4-.1 .1 .2v.5l-.1 .2-.3 .1M235.5 149.4h.5M235.5 147.5l.1 .2 .3 .1 .1-.3h-.3l.1 .3M235.6 148h.3l.1 .2a.24 .24 0 0 1-.3 .1 .24 .24 0 0 1-.1-.3zM235.6 148.2h.1M235.6 148.9a.22 .22 0 0 0 .2 .3 .22 .22 0 0 0 .2-.3"/>
<path d="M235.7 148.5h.3M235.9 148.4v.3l-.4-.1M236.6 143.6h.8v1.6h-.8zM236.8 144.9l.2 .2 .2-.2M236.8 144.9h.1M236.8 143.7l.1 .2h.1v-.2M236.8 144.8v.1M236.9 143.7h.2l.1 .2M236.9 143.7h-.1M236.9 144.5h.3M237 143.7h.1M237 144.4v.3l-.2-.1"/>
<path d="M237.1 144.8h.1M237.2 144.8v.1M237.2 144.1v.2M237.2 144.9h.1M237.2 144.2h-.4l.1 .1M238.5 154.2h1.6v.8h-1.6zM238.5 143.7h10.5v9.2h-10.5zM238.6 154.6h.2v-.2h-.2v.4M238.7 154.6l.2 .2M239.1 154.4l-.1 .2h.3M239.2 154.5v.3M239.4 154.8h.2"/>
<path d="M239.4 154.5l.1-.1v.4M239.8 154.7l.1-.3 .1 .3M239.8 154.7v.1M239.8 154.8h.1M240 154.7l-.1 .1M240.6 141.7h1.6v.8h-1.6zM240.7 142.1h.2v-.2h-.2v.4M240.8 142.1l.2 .2M241.2 141.9l-.1 .2h.3M241.3 142v.3M241.5 142.2h.1M241.5 142.2l.1 .1"/>
<path d="M241.6 141.9l-.1 .3M241.6 141.9h.1M241.7 141.9v.3M241.7 142.3h-.1M241.7 142.2v.1M241.7 142.2h.1M242.1 142.1h-.2v-.2l.2 .1v.2l-.2 .1M243.2 149.4l1 .7M243.2 147.2v-.6l.4 .3 .1-.2h.4l.1 .1-.1 .4M243.3 147.7a.48 .48 0 0 1 .5-.2 .48 .48 0 0 1 .3 .5 .49 .49 0 0 1-.5 .2 .49 .49 0 0 1-.4-.5zM243.5 148.6h.7M243.8 148.5v.6l-.7-.3"/>
<path d="M244.2 149.4l-1 .7M169.8 167.1l.5-.1v-.3l-.5-.1v1M170 167.1l.4 .5M170.8 167h.3M171.3 166.6h-.5v1h.5M171.7 167h.3M172.2 166.6h-.5v1M172.5 166.7l.2 .1M172.7 166.6v.2M172.7 166.8l-.1 .2M172.7 166.8l.1 .2M172.9 166.7l-.2 .1"/>
<path d="M173.2 166.7l.3 .1M173.5 166.6v.2M173.5 166.8l-.2 .2M173.5 166.8l.1 .2M173.7 166.7l-.2 .1M177.7 163.5h.8v1.6h-.8zM177.7 166.7h.8v1.6h-.8zM178.9 164.8v.2h.4M178.9 164.1v.1M178.9 167.2v.1M178.9 164.2h.1M178.9 167.3h.1"/>
<path d="M178.9 164.8h.2M178.9 164.1h.4l-.4 .1M178.9 167.9v.2h.2h.2v-.2M178.9 164.8h.1M178.9 164.1h.1M178.9 167.2h.4l-.4 .1M178.9 167.2h.1M179 167.6h.3M179 164.5h.3M179.1 164.8h.1M179.1 164.8v.2M179.2 164.4v.2h-.3"/>
<path d="M179.2 167.5v.2l-.3-.1M179.3 164.8l-.2 .1M179.3 163.7v.2M179.3 166.8v.2M179.3 163.8h-.4l.1 .1M179.3 166.9h-.4l.1 .1M180.7 162.8h6.2v6.2h-6.2zM182.7 165.5h-.5v.3l.4 .2 .1 .2-.2 .2h-.4M183.3 165.4l-.2 .7h.6M183.5 165.7v.7M184.1 165.5l.2-.1a.53 .53 0 0 1 .3 .5 .53 .53 0 0 1-.3 .5l-.3-.4zM185 166.4h.5"/>
<path d="M185 165.7l.3-.3v1M190.7 166h6.7v2.6h-6.7zM192.3 166.5l-.4-.1-.2 .2 .1 .3 .4 .1v.3l-.5 .1M192.6 166.4l.3 1 .1-.7 .2 .7 .3-1M194 168.6v1.3l-.3 .2h-.8l-.2-.2v-1.3M194 166.4l-.2 .7h.6M194.3 166.8v.6M194.9 166.5l.1-.1a.54 .54 0 0 1 .3 .5 .54 .54 0 0 1-.3 .5 .66 .66 0 0 1-.1-.9zM195.7 167.4h.6M195.7 166.7l.3-.3v1M200.3 164.6h.8v1.6h-.8zM200.3 167.6h.8v1.6h-.5l-.3-.3z"/>
<path d="M200.5 168.2h.1M200.5 168.2l.1 .1 .3-.1M200.5 168.2l.1-.1 .3 .1M200.5 168.9h.3l.1 .2h-.4zM200.6 165.1h.1M200.6 165.1l-.1 .2M200.6 165.1l.3 .2v-.2M200.6 165.5h.3M200.6 168.5h.3M200.6 167.7h.3M200.7 165.9h-.2v.2h.4M200.7 165.9h.1"/>
<path d="M200.7 165.9v.2M200.7 165.4v.3l-.2-.1M200.7 167.7v.2l-.2-.1M200.7 168.4v.3l-.2-.1M200.8 168.9h.1M200.9 165.8l-.2 .2M200.9 164.7v.2M200.9 168.2h.1M200.9 164.8h-.4l.1 .1M207.6 166.9h6.9l.7 .7v1.9h-7.6zM209.6 167.7l.7 1M210.3 167.7l-.7 1"/>
<path d="M210.8 167.6l-.2 .7h.6M211.1 168v.7M211.7 167.7h.1a.53 .53 0 0 1 .3 .5 .53 .53 0 0 1-.3 .5 .67 .67 0 0 1-.1-1zM212.5 167.8l.4-.1 .2 .2-.6 .8h.6M219.3 164.6h.8v1.6h-.8zM219.3 167.6h.8v1.6h-.5l-.3-.3zM219.5 168v-.3l.1 .1 .2-.1v.3M219.5 168.2h.1M219.5 168.2l.3 .1M219.5 165.9v.2h.4M219.5 165.1v.2M219.5 165.3h.1"/>
<path d="M219.5 165.9h.1M219.5 165.9h.2v.2M219.5 165.1h.1M219.5 165.1l.4 .1-.4 .1M219.5 168.9h.3l.1 .2h-.4zM219.6 165.5h.3M219.6 168.5h.3M219.7 165.4v.3l-.2-.1M219.7 168.4v.3l-.2-.1M219.8 168.1l-.3 .1M219.8 168.1h.1M219.8 168.1l.1 .1"/>
<path d="M219.8 168.3h.1M219.9 165.8l-.2 .2M219.9 164.9l-.4-.2v.3M219.9 168.2h.1M219.9 168.2l-.1 .1M241.8 167.1l.5-.1v-.3l-.5-.1v1M242 167.1l.4 .5M242.8 167h.3M243.3 166.6h-.5v1h.5M243.7 167h.3M244.2 166.6h-.5v1M244.5 166.7l.2 .1"/>
<path d="M244.7 166.6v.2M244.7 166.8l-.1 .2M244.7 166.8l.1 .2M244.9 166.7l-.2 .1M245.2 166.7l.3 .1M245.5 166.6v.2M245.5 166.8l-.2 .2M245.5 166.8l.1 .2M245.7 166.7l-.2 .1"/>
<circle cx="185.2" cy="131.7" r=".15"/>
<circle cx="195.5" cy="148.1" r=".18"/>
<circle cx="197" cy="148.1" r=".18"/>
<circle cx="183.8" cy="166" r="1.75"/>
</g>
<circle cx="170.1" cy="151.1" r=".1" fill="none" stroke="#744679" stroke-width=".2"/>
<path d="M30.1 224.2h63.7v24.5h-63.7z" fill="none" stroke="#000" stroke-width=".4"/>
<g fill="#000">
<path d="M37.4 159.5h.8l.3 .4a.25 .25 0 0 0-.2 .3 .25 .25 0 0 0 .2 .2 .45 .45 0 0 1-.1 .5 .45 .45 0 0 1-.4 .1h-.6v-.2h.7l.2-.1-.1-.4h-.6v.5h-.2v-.7h.5a.24 .24 0 0 0 .4-.1 .24 .24 0 0 0-.3-.3h-.4v.4h-.2z" fill-rule="evenodd"/>
<path d="M43.4 159.7a.74 .74 0 0 1 1.2 .1 .74 .74 0 0 1-.3 1.1 .74 .74 0 0 1-1.1-.5v-.1h.2a.56 .56 0 0 0 .8 .5 .56 .56 0 0 0 .1-1l-.3-.1a.52 .52 0 0 0-.6 .6h-.2z" fill-rule="evenodd"/>
<path d="M50.3 159.5h.2v.9a.4 .4 0 0 0 .4 .4 .4 .4 0 0 0 .4-.4v-.9h.2v.9a.59 .59 0 0 1-.6 .6 .59 .59 0 0 1-.6-.6z" fill-rule="evenodd"/>
<path d="M59.4 159.7a.74 .74 0 0 1 1.1 .1 .74 .74 0 0 1-.3 1.1 .74 .74 0 0 1-1-.5v-.1h.2a.56 .56 0 0 0 .8 .5 .56 .56 0 0 0 .1-1l-.3-.1a.52 .52 0 0 0-.6 .6h-.2z" fill-rule="evenodd"/>
<path d="M65.1 159.5h.7a.42 .42 0 0 1 .5 .3 .42 .42 0 0 1-.4 .5l.5 .7h-.2l-.4-.6-.3-.1h-.2v.7h-.2v-.8h.6a.26 .26 0 0 0 .4-.3 .26 .26 0 0 0-.3-.2h-.5v.5h-.2z" fill-rule="evenodd"/>
<path d="M68.6 159.5h.2v1.5h-.2z" fill-rule="evenodd"/>
<path d="M73.9 159.5h.6a.46 .46 0 0 1 .6 .4 .46 .46 0 0 1-.6 .5h-.4v.6h-.2v-.8h.6a.28 .28 0 0 0 .3-.3 .28 .28 0 0 0-.3-.2h-.4v.5h-.2z" fill-rule="evenodd"/>
<path d="M78.3 159.5h.2v1.5h-.2z" fill-rule="evenodd"/>
<path d="M80.1 159.5h.2v1.5h-.2z" fill-rule="evenodd"/>
<path d="M82.1 159.5h.5a.75 .75 0 0 1 .7 .7 .75 .75 0 0 1-.7 .8h-.5v-.2h.5a.58 .58 0 0 0 .5-.6 .58 .58 0 0 0-.5-.5h-.3v1.1h-.2z" fill-rule="evenodd"/>
<path d="M30.2 174.7a.4 .4 0 0 1 .6 0 .4 .4 0 0 1-.1 .6 .47 .47 0 0 1 0 .8 .47 .47 0 0 1-.7-.4h.2a.3 .3 0 0 0 .3 .3 .3 .3 0 0 0 .3-.4 .3 .3 0 0 0-.4-.2v-.2a.26 .26 0 0 0 .3-.2 .26 .26 0 0 0-.3-.3 .26 .26 0 0 0-.2 .3h-.2z" fill-rule="evenodd"/>
<path d="M30.1 164.9l.6-.4v1.5h-.2v-1.1l-.4 .2z" fill-rule="evenodd"/>
<path d="M30.1 169.7a.48 .48 0 0 1 .8 0 .48 .48 0 0 1-.2 .8l-.5 .4h.8v.2h-1l.3-.6a.43 .43 0 0 0 .4-.3 .43 .43 0 0 0-.1-.5l-.3 .1-.1 .2h-.2z" fill-rule="evenodd"/>
<path d="M30.5 159.5h.2l.6 1.5h-.2l-.2-.5h-.6l-.2 .5h-.2l.2-.6h.7l-.2-.7-.3 .7h-.2z" fill-rule="evenodd"/>
<path d="M31.2 164.5a1.23 1.23 0 0 1 0 2 1.73 1.73 0 0 0 0-2z" fill-rule="evenodd"/>
<path d="M31.2 169.5a1.23 1.23 0 0 1 0 2 1.73 1.73 0 0 0 0-2z" fill-rule="evenodd"/>
<path d="M31.2 174.6a1.23 1.23 0 0 1 0 2 1.73 1.73 0 0 0 0-2z" fill-rule="evenodd"/>
<path d="M31.6 159.6l.3-.1h.4l.2 .3-.1 .1a.32 .32 0 0 0-.4-.3 .32 .32 0 0 0-.3 .4l.1 .1a.57 .57 0 0 1 .8 .6 .64 .64 0 0 1-.7 .3 .64 .64 0 0 1-.5-.5h.2a.39 .39 0 0 0 .4 .4 .39 .39 0 0 0 .4-.4l-.3-.1a.49 .49 0 0 1-.5-.2 .49 .49 0 0 1 0-.6z" fill-rule="evenodd"/>
<path d="M33 159.6l.3-.1h.4l.2 .3-.1 .1a.32 .32 0 0 0-.4-.3 .32 .32 0 0 0-.3 .4l.1 .1a.57 .57 0 0 1 .8 .6 .64 .64 0 0 1-.7 .3 .64 .64 0 0 1-.5-.5h.2a.39 .39 0 0 0 .4 .4 .39 .39 0 0 0 .4-.4l-.3-.1a.49 .49 0 0 1-.5-.2 .49 .49 0 0 1 0-.6z" fill-rule="evenodd"/>
<path d="M33.7 177.1h1v.2h-.8v.5h.7v.2h-.7v.6h-.2z" fill-rule="evenodd"/>
<path d="M33.7 174.6h.2v1.5h-.2z" fill-rule="evenodd"/>
<path d="M34.3 174.6h1v.2h-.8v.5h.7v.1h-.7v.7h-.2z" fill-rule="evenodd"/>
<path d="M34.3 159.5h1.1v.2h-.9v.4h.8v.2h-.8v.5h.9v.2h-1.1z" fill-rule="evenodd"/>
<path d="M33.7 164.5h.5a.75 .75 0 0 1 .7 .8 .75 .75 0 0 1-.7 .7h-.5v-.1h.5a.58 .58 0 0 0 .5-.6 .58 .58 0 0 0-.5-.6h-.3v1.2h-.2z" fill-rule="evenodd"/>
<path d="M33.7 169.6h.5a.76 .76 0 0 1 .7 .7 .76 .76 0 0 1-.7 .8h-.5v-.2h.5a.58 .58 0 0 0 .5-.6 .58 .58 0 0 0-.5-.6h-.3v1.2h-.2z" fill-rule="evenodd"/>
<path d="M35 177.1h.2v1.5h-.2z" fill-rule="evenodd"/>
<path d="M35.5 177.1h.2v1.4h.8v.1h-1z" fill-rule="evenodd"/>
<path d="M35.7 159.5h.3l.4 1.3 .4-1.3h.3v1.5h-.2v-1.3l-.4 1.3h-.2l-.5-1.3v1.3h-.1z" fill-rule="evenodd"/>
<path d="M35.3 164.7a.74 .74 0 0 1 1.2 .1 .74 .74 0 0 1-.3 1.1 .74 .74 0 0 1-1.1-.5v-.1h.2a.56 .56 0 0 0 .8 .5 .56 .56 0 0 0 .1-.9l-.3-.2a.52 .52 0 0 0-.6 .6h-.2z" fill-rule="evenodd"/>
<path d="M35.3 169.8a.74 .74 0 0 1 1.2 .1 .74 .74 0 0 1-.3 1.1 .74 .74 0 0 1-1.1-.5v-.2h.2a.56 .56 0 0 0 .8 .6 .56 .56 0 0 0 .1-1l-.3-.2a.52 .52 0 0 0-.6 .6h-.2z" fill-rule="evenodd"/>
<path d="M36.7 177.1h1.1v.2h-.9v.5h.8v.1h-.8v.6h.9v.1h-1.1z" fill-rule="evenodd"/>
<path d="M36.3 174.8l.2-.2a.62 .62 0 0 1 .9 .4l-.2 .1a.53 .53 0 0 0-.8-.2 .53 .53 0 0 0-.1 .8l.4 .3 .3-.1 .2-.3h.2a.72 .72 0 0 1-1.1 .4 .72 .72 0 0 1-.2-1.1z" fill-rule="evenodd"/>
<path d="M37.4 164.5h.2l.8 1.2v-1.2h.2v1.5h-.2l-.8-1.1v1.1h-.2z" fill-rule="evenodd"/>
<path d="M37.4 169.6h.2l.8 1.2v-1.2h.2v1.5h-.2l-.8-1.2v1.2h-.2z" fill-rule="evenodd"/>
<path d="M37.8 174.8a.74 .74 0 0 1 1.1 .1 .74 .74 0 0 1-.3 1.1 .74 .74 0 0 1-1-.5v-.1h.2a.56 .56 0 0 0 .8 .5 .56 .56 0 0 0 .1-.9 .52 .52 0 0 0-.6-.2 .52 .52 0 0 0-.3 .6h-.2z" fill-rule="evenodd"/>
<path d="M38.8 159.5h.2v1.3h.7v.2h-.9z" fill-rule="evenodd"/>
<path d="M39.3 174.6h.2l.7 1.2v-1.2h.2v1.5h-.2l-.8-1.2v1.2h-.1z" fill-rule="evenodd"/>
<path d="M39 164.7a.74 .74 0 0 1 1.2 .1 .74 .74 0 0 1-.3 1.1 .74 .74 0 0 1-1-.5l-.1-.1h.3a.56 .56 0 0 0 .7 .5 .56 .56 0 0 0 .2-.9l-.3-.2a.52 .52 0 0 0-.6 .6h-.3z" fill-rule="evenodd"/>
<path d="M39 169.8a.74 .74 0 0 1 1.2 .1 .74 .74 0 0 1-.3 1.1 .74 .74 0 0 1-1-.5l-.1-.2h.3a.56 .56 0 0 0 .7 .6 .56 .56 0 0 0 .2-1l-.3-.2a.52 .52 0 0 0-.6 .6h-.3z" fill-rule="evenodd"/>
<path d="M39 177.1h.2l.7 1.5h-.3l-.1-.4h-.7l-.1 .4h-.2l.2-.6h.7l-.3-.7-.2 .7h-.2z" fill-rule="evenodd"/>
<path d="M40 177.1h.2l.8 1.2v-1.2h.1v1.5h-.2l-.8-1.1v1.1h-.1z" fill-rule="evenodd"/>
<path d="M39.7 159.5h.3l.4 .7 .5-.7h.2l-.6 .9v.6h-.2v-.6z" fill-rule="evenodd"/>
<path d="M40.8 174.6h1v.2h-.8v.5h.7v.1h-.7v.7h-.2z" fill-rule="evenodd"/>
<path d="M40.4 164.5h1.2v.2h-.5v1.3h-.2v-1.3h-.5z" fill-rule="evenodd"/>
<path d="M40.4 169.6h1.2v.1h-.5v1.4h-.2v-1.4h-.5z" fill-rule="evenodd"/>
<path d="M41.8 159.5h.2l.8 1.2v-1.2h.1v1.5h-.2l-.7-1.2v1.2h-.2z" fill-rule="evenodd"/>
<path d="M42 174.6h.2v1.3h.8v.2h-1z" fill-rule="evenodd"/>
<path d="M41.5 177.1h.5a.76 .76 0 0 1 .7 .8 .76 .76 0 0 1-.7 .7h-.5v-.1h.5a.58 .58 0 0 0 .5-.6 .58 .58 0 0 0-.5-.6h-.3v1.2h-.2z" fill-rule="evenodd"/>
<path d="M42.4 164.5h.5a.46 .46 0 0 1 .6 .5 .46 .46 0 0 1-.5 .4h-.4v.6h-.2v-.8h.6a.28 .28 0 0 0 .3-.2 .28 .28 0 0 0-.3-.3h-.4v.5h-.2z" fill-rule="evenodd"/>
<path d="M42.4 169.6h.5a.46 .46 0 0 1 .6 .4 .46 .46 0 0 1-.5 .5h-.4v.6h-.2v-.8h.6a.28 .28 0 0 0 .3-.3 .28 .28 0 0 0-.3-.3h-.4v.6h-.2z" fill-rule="evenodd"/>
<path d="M43.3 174.6h.2v1.5h-.2z" fill-rule="evenodd"/>
<path d="M43.6 177.1l.8 .1 .2 .4a.25 .25 0 0 0-.1 .2 .25 .25 0 0 0 .2 .2 .45 .45 0 0 1-.1 .5 .45 .45 0 0 1-.5 .1h-.5v-.1h.7l.2-.2-.1-.3-.6-.1v.6h-.2v-.7h.5a.24 .24 0 0 0 .3-.2 .24 .24 0 0 0-.2-.3h-.4v.5h-.2z" fill-rule="evenodd"/>
<path d="M43.9 164.7a.74 .74 0 0 1 1.1 .1 .74 .74 0 0 1-.3 1.1 .74 .74 0 0 1-1-.5v-.1h.2a.56 .56 0 0 0 .8 .5 .56 .56 0 0 0 .1-.9l-.3-.2a.52 .52 0 0 0-.6 .6h-.2z" fill-rule="evenodd"/>
<path d="M43.9 169.8a.74 .74 0 0 1 1.1 .1 .74 .74 0 0 1-.3 1.1 .74 .74 0 0 1-1-.5v-.2h.2a.56 .56 0 0 0 .8 .6 .56 .56 0 0 0 .1-1l-.3-.2a.52 .52 0 0 0-.6 .6h-.2z" fill-rule="evenodd"/>
<path d="M43.9 174.8l.3-.2a.62 .62 0 0 1 .9 .4l-.2 .1a.53 .53 0 0 0-.8-.2 .53 .53 0 0 0-.1 .8l.4 .3 .3-.1 .2-.3h.2a.72 .72 0 0 1-1.1 .4 .72 .72 0 0 1-.2-1.1z" fill-rule="evenodd"/>
<path d="M44.8 159.5h1.2v.2h-.5v1.3h-.2v-1.3h-.5z" fill-rule="evenodd"/>
<path d="M45.2 174.6h1.2v.2h-.5v1.3h-.2v-1.3h-.5z" fill-rule="evenodd"/>
<path d="M45.1 177.3a.74 .74 0 0 1 1.1 .1 .74 .74 0 0 1-.2 1.1 .74 .74 0 0 1-1.1-.5v-.1h.2a.56 .56 0 0 0 .8 .5 .56 .56 0 0 0 .1-.9l-.3-.2a.52 .52 0 0 0-.6 .6h-.2z" fill-rule="evenodd"/>
<path d="M45.4 164.5h.6a.46 .46 0 0 1 .5 .5 .46 .46 0 0 1-.5 .4h-.4v.6h-.2v-.8h.6a.28 .28 0 0 0 .3-.2 .28 .28 0 0 0-.3-.3h-.4v.5h-.2z" fill-rule="evenodd"/>
<path d="M45.4 169.6h.6a.46 .46 0 0 1 .5 .4 .46 .46 0 0 1-.5 .5h-.4v.6h-.2v-.8h.6a.28 .28 0 0 0 .3-.3 .28 .28 0 0 0-.3-.3h-.4v.6h-.2z" fill-rule="evenodd"/>
<path d="M46.2 159.5h1.1v.2h-.9v.4h.8v.2h-.8v.5h.9v.2h-1.1z" fill-rule="evenodd"/>
<path d="M46.6 177.1h.3l.4 1.3 .5-1.3h.2v1.5h-.2v-1.2l-.4 1.2h-.2l-.4-1.2v1.2h-.2z" fill-rule="evenodd"/>
<path d="M46.6 174.6h.2v1.5h-.2z" fill-rule="evenodd"/>
<path d="M47.2 174.6h.2l.8 1.2v-1.2h.2v1.5h-.2l-.8-1.2v1.2h-.2z" fill-rule="evenodd"/>
<path d="M47.7 159.6l.3-.1h.4l.3 .3-.2 .1a.32 .32 0 0 0-.4-.3 .32 .32 0 0 0-.2 .4l.1 .1a.57 .57 0 0 1 .7 .6 .64 .64 0 0 1-.7 .3 .64 .64 0 0 1-.5-.5h.2a.39 .39 0 0 0 .4 .4 .39 .39 0 0 0 .4-.4l-.2-.1a.49 .49 0 0 1-.6-.2 .49 .49 0 0 1 0-.6z" fill-rule="evenodd"/>
<path d="M46.8 164.5h.2v.9a.4 .4 0 0 0 .4 .5 .4 .4 0 0 0 .4-.5v-.9h.2v.9a.59 .59 0 0 1-.6 .7 .59 .59 0 0 1-.6-.7z" fill-rule="evenodd"/>
<path d="M46.8 169.6h.2v.8a.4 .4 0 0 0 .4 .5 .4 .4 0 0 0 .4-.5v-.8h.2v.8a.59 .59 0 0 1-.6 .7 .59 .59 0 0 1-.6-.7z" fill-rule="evenodd"/>
<path d="M48.3 164.5h.2v1.4h.7v.1h-.9z" fill-rule="evenodd"/>
<path d="M48.3 169.6h.2v1.3h.7v.2h-.9z" fill-rule="evenodd"/>
<path d="M48.4 178.4h.2v.4l-.2 .1z" fill-rule="evenodd"/>
<path d="M48.9 174.8l.2-.2h.5l.3 .3 .1 .1-.2 .1a.58 .58 0 0 0-.8-.2 .58 .58 0 0 0-.1 .8 .58 .58 0 0 0 .8 .2l.1-.1v-.3h-.4v-.1h.6v.5a.81 .81 0 0 1-1.1 .1 .81 .81 0 0 1 0-1.2z" fill-rule="evenodd"/>
<path d="M49.9 159.5h.1l-.2 .4a1.74 1.74 0 0 0 .2 1.5 1.34 1.34 0 0 1-.1-1.9z" fill-rule="evenodd"/>
<path d="M49.5 177.1l.9 .1 .2 .4a.25 .25 0 0 0-.2 .2 .25 .25 0 0 0 .2 .2 .45 .45 0 0 1-.1 .5 .45 .45 0 0 1-.4 .1h-.6v-.1h.7l.2-.2-.1-.3-.6-.1v.6h-.2v-.7h.5a.24 .24 0 0 0 .4-.2 .24 .24 0 0 0-.2-.3h-.5v.5h-.2z" fill-rule="evenodd"/>
<path d="M49.9 164.5h.2l.6 1.5h-.2l-.2-.4h-.6l-.2 .4h-.2l.3-.6h.7l-.3-.7-.3 .7h-.1z" fill-rule="evenodd"/>
<path d="M49.9 169.6h.2l.6 1.5h-.2l-.2-.5h-.6l-.2 .5h-.2l.3-.6h.7l-.3-.8-.3 .8h-.1z" fill-rule="evenodd"/>
<path d="M51 174.6h.1v1.5h-.1z" fill-rule="evenodd"/>
<path d="M50.7 164.5h1.2v.2h-.5v1.3h-.2v-1.3h-.5z" fill-rule="evenodd"/>
<path d="M50.7 169.6h1.2v.1h-.5v1.4h-.2v-1.4h-.5z" fill-rule="evenodd"/>
<path d="M51.5 174.6h.2l.8 1.2v-1.2h.2v1.5h-.2l-.8-1.2v1.2h-.2z" fill-rule="evenodd"/>
<path d="M51.1 177.3a.74 .74 0 0 1 1.1 .1 .74 .74 0 0 1-.3 1.1 .74 .74 0 0 1-1-.5v-.1h.2a.56 .56 0 0 0 .8 .5 .56 .56 0 0 0 .1-.9l-.3-.2a.52 .52 0 0 0-.6 .6h-.2z" fill-rule="evenodd"/>
<path d="M51.8 159.5h.2l.8 1.2v-1.2h.2v1.5h-.2l-.8-1.2v1.2h-.2z" fill-rule="evenodd"/>
<path d="M52 164.5h1.1v.2h-.9v.5h.8v.1h-.8v.6h.9v.1h-1.1z" fill-rule="evenodd"/>
<path d="M52 169.6h1.1v.1h-.9v.5h.8v.2h-.8v.5h.9v.2h-1.1z" fill-rule="evenodd"/>
<path d="M52.5 177.1h.3l.5 1.3 .4-1.3h.3v1.5h-.2v-1.2l-.4 1.2h-.2l-.5-1.2v1.2h-.2z" fill-rule="evenodd"/>
<path d="M53 174.6h1v.2h-.8v.5h.7v.1h-.7v.7h-.2z" fill-rule="evenodd"/>
<path d="M53.3 159.5h.2v1.3h.7v.2h-.9z" fill-rule="evenodd"/>
<path d="M54.5 159.5h1.1v.2h-.9v.4h.8v.2h-.8v.5h.9v.2h-1.1z" fill-rule="evenodd"/>
<path d="M54 164.5h.6a.46 .46 0 0 1 .5 .5 .46 .46 0 0 1-.5 .4h-.4v.6h-.2v-.8h.6a.28 .28 0 0 0 .3-.2 .28 .28 0 0 0-.3-.3h-.4v.5h-.2z" fill-rule="evenodd"/>
<path d="M54 169.6h.6a.46 .46 0 0 1 .5 .4 .46 .46 0 0 1-.5 .5h-.4v.6h-.2v-.8h.6a.28 .28 0 0 0 .3-.3 .28 .28 0 0 0-.3-.3h-.4v.6h-.2z" fill-rule="evenodd"/>
<path d="M55 177.3l.3-.2 .4 .1 .3 .3-.2 .1a.32 .32 0 0 0-.4-.4 .32 .32 0 0 0-.2 .5h.1a.57 .57 0 0 1 .7 .7 .64 .64 0 0 1-.7 .3 .64 .64 0 0 1-.5-.5l.2-.1a.39 .39 0 0 0 .4 .4 .39 .39 0 0 0 .4-.4l-.2-.1a.49 .49 0 0 1-.6-.2 .49 .49 0 0 1 0-.5z" fill-rule="evenodd"/>
<path d="M54.4 174.8a.74 .74 0 0 1 1.2 .1 .74 .74 0 0 1-.3 1.1 .74 .74 0 0 1-1.1-.5v-.1h.2a.56 .56 0 0 0 .8 .5 .56 .56 0 0 0 .2-.9 .52 .52 0 0 0-.7-.2 .52 .52 0 0 0-.3 .6h-.2z" fill-rule="evenodd"/>
<path d="M56 159.6l.3-.1h.4l.2 .3-.1 .1a.32 .32 0 0 0-.4-.3 .32 .32 0 0 0-.2 .4v.1a.57 .57 0 0 1 .8 .6 .64 .64 0 0 1-.7 .3 .64 .64 0 0 1-.5-.5h.2a.39 .39 0 0 0 .4 .4 .39 .39 0 0 0 .4-.4l-.2-.1a.49 .49 0 0 1-.6-.2 .49 .49 0 0 1 0-.6z" fill-rule="evenodd"/>
<path d="M56.3 177.1h.2v.7h.8v-.7h.2v1.5h-.2v-.7h-.8v.7h-.2z" fill-rule="evenodd"/>
<path d="M55.7 164.5h.2l.7 1.5h-.3l-.1-.4h-.7l-.1 .4h-.3l.3-.6h.7l-.3-.7-.2 .7h-.2z" fill-rule="evenodd"/>
<path d="M55.7 169.6h.2l.7 1.5h-.3l-.1-.5h-.7l-.1 .5h-.3l.3-.6h.7l-.3-.8-.2 .8h-.2z" fill-rule="evenodd"/>
<path d="M55.9 174.6h.7a.42 .42 0 0 1 .5 .4 .42 .42 0 0 1-.4 .4l.6 .7h-.3l-.4-.6h-.2h-.3v.6h-.2v-.8h.7a.26 .26 0 0 0 .3-.2 .26 .26 0 0 0-.3-.3h-.5v.5h-.2z" fill-rule="evenodd"/>
<path d="M57.4 159.6l.3-.1h.4l.2 .3-.1 .1a.32 .32 0 0 0-.4-.3 .32 .32 0 0 0-.2 .4v.1a.57 .57 0 0 1 .8 .6 .64 .64 0 0 1-.7 .3 .64 .64 0 0 1-.5-.5h.2a.39 .39 0 0 0 .4 .4 .39 .39 0 0 0 .4-.4l-.2-.1a.49 .49 0 0 1-.6-.2 .49 .49 0 0 1 0-.6z" fill-rule="evenodd"/>
<path d="M56.6 164.5h.7a.42 .42 0 0 1 .5 .4 .42 .42 0 0 1-.4 .5l.6 .6h-.3a.74 .74 0 0 0-.9-.6v.6h-.2v-.8h.7a.26 .26 0 0 0 .3-.2 .26 .26 0 0 0-.3-.3h-.5v.5h-.2z" fill-rule="evenodd"/>
<path d="M56.6 169.6h.7a.42 .42 0 0 1 .5 .3 .42 .42 0 0 1-.4 .5l.6 .7h-.3l-.4-.6-.2-.1h-.3v.7h-.2v-.9h.7a.26 .26 0 0 0 .3-.2 .26 .26 0 0 0-.3-.3h-.5v.5h-.2z" fill-rule="evenodd"/>
<path d="M57.4 174.6h.3l.5 1.3 .4-1.3h.3v1.5h-.2v-1.2l-.5 1.2h-.1l-.5-1.3v1.3h-.2z" fill-rule="evenodd"/>
<path d="M58 164.5h1.2v.2h-.5v1.3h-.2v-1.3h-.5z" fill-rule="evenodd"/>
<path d="M58 169.6h1.2v.1h-.5v1.4h-.2v-1.4h-.5z" fill-rule="evenodd"/>
<path d="M57.9 177.3a.74 .74 0 0 1 1.2 .1 .74 .74 0 0 1-.3 1.1 .74 .74 0 0 1-1.1-.5v-.1h.2a.56 .56 0 0 0 .8 .5 .56 .56 0 0 0 .2-.9l-.3-.2a.52 .52 0 0 0-.7 .6h-.2z" fill-rule="evenodd"/>
<path d="M59.5 164.7l.3-.2 .4 .1 .3 .3-.2 .1a.32 .32 0 0 0-.4-.4 .32 .32 0 0 0-.2 .5h.1a.57 .57 0 0 1 .7 .7 .64 .64 0 0 1-.7 .3 .64 .64 0 0 1-.5-.5l.2-.1a.39 .39 0 0 0 .4 .4 .39 .39 0 0 0 .4-.4l-.2-.1a.49 .49 0 0 1-.6-.2 .49 .49 0 0 1 0-.5z" fill-rule="evenodd"/>
<path d="M59.5 169.7l.3-.1h.4l.3 .3-.2 .1a.32 .32 0 0 0-.4-.4 .32 .32 0 0 0-.2 .5h.1a.57 .57 0 0 1 .7 .7 .64 .64 0 0 1-.7 .3 .64 .64 0 0 1-.5-.5h.2a.39 .39 0 0 0 .4 .3 .39 .39 0 0 0 .4-.4l-.2-.1a.49 .49 0 0 1-.6-.1 .49 .49 0 0 1 0-.6z" fill-rule="evenodd"/>
<path d="M59.4 177.1h.2v.9a.4 .4 0 0 0 .4 .5 .4 .4 0 0 0 .4-.5v-.9h.2v.9a.59 .59 0 0 1-.6 .7 .59 .59 0 0 1-.6-.7z" fill-rule="evenodd"/>
<path d="M59.6 174.6h.2l.6 1.5h-.2l-.2-.4h-.6l-.2 .4h-.2l.3-.6h.7l-.3-.7-.2 .7h-.2z" fill-rule="evenodd"/>
<path d="M60.4 174.6h1.2v.2h-.5v1.3h-.2v-1.3h-.5z" fill-rule="evenodd"/>
<path d="M60.9 177.1h.2v1.4h.8v.1h-1z" fill-rule="evenodd"/>
<path d="M60.8 159.5h1.2v.2h-.5v1.3h-.2v-1.3h-.5z" fill-rule="evenodd"/>
<path d="M61.8 174.6h.2v1.5h-.2z" fill-rule="evenodd"/>
<path d="M62.2 159.5h.2v.6h.8v-.6h.2v1.5h-.2v-.7h-.8v.7h-.2z" fill-rule="evenodd"/>
<path d="M61.7 164.5h.2l.7 1.5h-.3l-.1-.4h-.7l-.1 .4h-.2l.2-.6h.7l-.3-.7-.2 .7h-.2z" fill-rule="evenodd"/>
<path d="M61.7 169.6h.2l.7 1.5h-.3l-.1-.5h-.7l-.1 .5h-.2l.2-.6h.7l-.3-.8-.2 .8h-.2z" fill-rule="evenodd"/>
<path d="M62.1 177.1h.5a.76 .76 0 0 1 .8 .8 .76 .76 0 0 1-.7 .7h-.6v-.1h.5a.58 .58 0 0 0 .6-.6 .58 .58 0 0 0-.6-.6h-.3v1.2h-.2z" fill-rule="evenodd"/>
<path d="M62.4 174.8a.74 .74 0 0 1 1.2 .1 .74 .74 0 0 1-.3 1.1 .74 .74 0 0 1-1-.5l-.1-.1h.2a.56 .56 0 0 0 .8 .5 .56 .56 0 0 0 .2-.9 .52 .52 0 0 0-.7-.2 .52 .52 0 0 0-.3 .6h-.2z" fill-rule="evenodd"/>
<path d="M62.7 164.5h.6a.42 .42 0 0 1 .6 .4 .42 .42 0 0 1-.5 .5l.6 .6h-.3a.74 .74 0 0 0-.8-.6v.6h-.2v-.8h.6a.26 .26 0 0 0 .4-.2 .26 .26 0 0 0-.4-.3h-.4v.5h-.2z" fill-rule="evenodd"/>
<path d="M62.7 169.6h.6a.42 .42 0 0 1 .6 .3 .42 .42 0 0 1-.5 .5l.6 .7h-.3l-.4-.6-.2-.1h-.2v.7h-.2v-.9h.6a.26 .26 0 0 0 .4-.2 .26 .26 0 0 0-.4-.3h-.4v.5h-.2z" fill-rule="evenodd"/>
<path d="M63.7 159.5h1.1v.2h-.9v.4h.8v.2h-.8v.5h.9v.2h-1.1z" fill-rule="evenodd"/>
<path d="M63.9 174.6h.2l.8 1.2v-1.2h.2v1.5h-.2l-.8-1.2v1.2h-.2z" fill-rule="evenodd"/>
<path d="M64.2 164.5h1.1v.2h-.9v.5h.8v.1h-.8v.6h.9v.1h-1.1z" fill-rule="evenodd"/>
<path d="M64.2 169.6h1.1v.1h-.9v.5h.8v.2h-.8v.5h.9v.2h-1.1z" fill-rule="evenodd"/>
<path d="M64.2 177.1l.8 .1 .3 .4a.25 .25 0 0 0-.2 .2 .25 .25 0 0 0 .2 .2 .45 .45 0 0 1-.1 .5 .45 .45 0 0 1-.4 .1h-.6v-.1h.7l.2-.2-.1-.3-.6-.1v.6h-.2v-.7h.5a.24 .24 0 0 0 .4-.2 .24 .24 0 0 0-.2-.3h-.5v.5h-.2z" fill-rule="evenodd"/>
<path d="M65.6 177.1h1.1v.2h-.9v.5h.8v.1h-.8v.6h.9v.1h-1.1z" fill-rule="evenodd"/>
<path d="M66.1 174.6h.2v1.5h-.2z" fill-rule="evenodd"/>
<path d="M66.2 164.5h.3l.4 1.3 .4-1.3h.3v1.5h-.2v-1.2l-.4 1.2h-.2l-.5-1.2v1.2h-.1z" fill-rule="evenodd"/>
<path d="M66.2 169.6h.2l.7 1.2v-1.2h.2v1.5h-.2l-.8-1.2v1.2h-.1z" fill-rule="evenodd"/>
<path d="M66.7 174.7l.3-.1h.4l.3 .4-.2 .1a.32 .32 0 0 0-.4-.4 .32 .32 0 0 0-.2 .5h.1a.57 .57 0 0 1 .7 .6 .64 .64 0 0 1-.6 .3 .64 .64 0 0 1-.5-.5h.1a.39 .39 0 0 0 .4 .4 .39 .39 0 0 0 .4-.4l-.2-.1a.49 .49 0 0 1-.6-.2 .49 .49 0 0 1 0-.6z" fill-rule="evenodd"/>
<path d="M66.4 159.5h.2l.3 1.3 .4-1.3h.2l.4 1.3 .3-1.3h.2l-.4 1.5h-.2l-.4-1.3-.4 1.3h-.2z" fill-rule="evenodd"/>
<path d="M67.8 169.8a.74 .74 0 0 1 1.1 .1 .74 .74 0 0 1-.2 1.1 .74 .74 0 0 1-1.1-.5v-.2h.2a.56 .56 0 0 0 .8 .6 .56 .56 0 0 0 .1-1l-.3-.2a.52 .52 0 0 0-.6 .6h-.2z" fill-rule="evenodd"/>
<path d="M67.6 177.1h.2v.9a.4 .4 0 0 0 .4 .5 .4 .4 0 0 0 .4-.5v-.9h.2v.9a.59 .59 0 0 1-.6 .7 .59 .59 0 0 1-.6-.7z" fill-rule="evenodd"/>
<path d="M68.6 174.6h1v.2h-.8v.5h.7v.1h-.7v.7h-.2z" fill-rule="evenodd"/>
<path d="M69.2 177.3l.3-.2 .4 .1 .3 .3-.2 .1a.32 .32 0 0 0-.4-.4 .32 .32 0 0 0-.2 .5h.1a.57 .57 0 0 1 .7 .7 .64 .64 0 0 1-.6 .3 .64 .64 0 0 1-.6-.5l.2-.1a.39 .39 0 0 0 .4 .4 .39 .39 0 0 0 .4-.4l-.2-.1a.49 .49 0 0 1-.6-.2 .49 .49 0 0 1 0-.5z" fill-rule="evenodd"/>
<path d="M69.2 159.6l.3-.1h.4l.3 .3-.2 .1a.32 .32 0 0 0-.4-.3 .32 .32 0 0 0-.2 .4l.1 .1a.57 .57 0 0 1 .7 .6 .64 .64 0 0 1-.6 .3 .64 .64 0 0 1-.5-.5h.1a.39 .39 0 0 0 .4 .4 .39 .39 0 0 0 .4-.4l-.2-.1a.49 .49 0 0 1-.6-.2 .49 .49 0 0 1 0-.6z" fill-rule="evenodd"/>
<path d="M68.3 164.5h.2l.6 1.5h-.2l-.2-.4h-.6l-.1 .4h-.3l.3-.6h.7l-.3-.7-.2 .7h-.2z" fill-rule="evenodd"/>
<path d="M69.2 169.6h1.2v.1h-.5v1.4h-.2v-1.4h-.5z" fill-rule="evenodd"/>
<path d="M69.3 164.5h.7a.42 .42 0 0 1 .5 .4 .42 .42 0 0 1-.4 .5l.5 .6h-.2a.74 .74 0 0 0-.9-.6v.6h-.2v-.8h.6a.26 .26 0 0 0 .4-.2 .26 .26 0 0 0-.3-.3h-.5v.5h-.2z" fill-rule="evenodd"/>
<path d="M70.5 177.1h1.1v.2h-.9v.5h.8v.1h-.8v.6h.9v.1h-1.1z" fill-rule="evenodd"/>
<path d="M70.5 159.5h1.1v.2h-.9v.4h.9v.2h-.9v.5h.9v.2h-1.1z" fill-rule="evenodd"/>
<path d="M70 174.8a.74 .74 0 0 1 1.2 .1 .74 .74 0 0 1-.3 1.1 .74 .74 0 0 1-1.1-.5v-.1h.2a.56 .56 0 0 0 .8 .5 .56 .56 0 0 0 .1-.9 .52 .52 0 0 0-.6-.2 .52 .52 0 0 0-.3 .6h-.2z" fill-rule="evenodd"/>
<path d="M70.8 164.5h.2v.8l.8-.8h.2l-.6 .6 .7 .9h-.3l-.5-.7-.3 .2v.5h-.2z" fill-rule="evenodd"/>
<path d="M71.1 169.6h.6a.46 .46 0 0 1 .6 .4 .46 .46 0 0 1-.6 .5h-.4v.6h-.2v-.8h.6a.28 .28 0 0 0 .4-.3 .28 .28 0 0 0-.4-.3h-.4v.6h-.2z" fill-rule="evenodd"/>
<path d="M72.2 164.5h1.1v.2h-.9v.5h.9v.1h-.9v.6h.9v.1h-1.1z" fill-rule="evenodd"/>
<path d="M72.6 159.6l.3-.1h.4l.3 .3-.2 .1a.32 .32 0 0 0-.4-.3 .32 .32 0 0 0-.2 .4l.1 .1a.57 .57 0 0 1 .7 .6 .64 .64 0 0 1-.7 .3 .64 .64 0 0 1-.5-.5h.2a.39 .39 0 0 0 .4 .4 .39 .39 0 0 0 .4-.4l-.2-.1a.49 .49 0 0 1-.6-.2 .49 .49 0 0 1 0-.6z" fill-rule="evenodd"/>
<path d="M71.5 174.6h.2v.9a.4 .4 0 0 0 .4 .5 .4 .4 0 0 0 .4-.5v-.9h.2v.9a.59 .59 0 0 1-.6 .6 .59 .59 0 0 1-.6-.6z" fill-rule="evenodd"/>
<path d="M71.9 177.1h.5a.76 .76 0 0 1 .8 .8 .76 .76 0 0 1-.7 .7h-.6v-.1h.5a.58 .58 0 0 0 .5-.6 .58 .58 0 0 0-.5-.6h-.3v1.2h-.2z" fill-rule="evenodd"/>
<path d="M73 174.6h.2l.8 1.2v-1.2h.2v1.5h-.2l-.8-1.2v1.2h-.2z" fill-rule="evenodd"/>
<path d="M72.5 169.6h.7a.42 .42 0 0 1 .5 .3 .42 .42 0 0 1-.4 .5l.6 .7h-.3l-.4-.6-.2-.1h-.3v.7h-.2v-.9h.7a.26 .26 0 0 0 .3-.2 .26 .26 0 0 0-.3-.3h-.5v.5h-.2z" fill-rule="evenodd"/>
<path d="M74.1 169.6h1v.1h-.8v.5h.8v.2h-.8v.5h.9v.2h-1.1z" fill-rule="evenodd"/>
<path d="M73.6 164.5h.5a.75 .75 0 0 1 .8 .8 .75 .75 0 0 1-.7 .7h-.6v-.1h.5a.58 .58 0 0 0 .6-.6 .58 .58 0 0 0-.6-.6h-.3v1.2h-.2z" fill-rule="evenodd"/>
<path d="M74.4 177.1h.2l.6 1.5h-.2l-.2-.4h-.6l-.2 .4h-.2l.2-.6h.7l-.2-.7-.3 .7h-.2z" fill-rule="evenodd"/>
<path d="M75.4 177.3l.3-.2 .4 .1 .3 .3-.2 .1a.32 .32 0 0 0-.4-.4 .32 .32 0 0 0-.2 .5h.1a.57 .57 0 0 1 .7 .7 .64 .64 0 0 1-.7 .3 .64 .64 0 0 1-.5-.5l.2-.1a.39 .39 0 0 0 .4 .4 .39 .39 0 0 0 .4-.4l-.2-.1a.49 .49 0 0 1-.6-.2 .49 .49 0 0 1 0-.5z" fill-rule="evenodd"/>
<path d="M74.5 174.6h.6a.75 .75 0 0 1 .7 .8 .75 .75 0 0 1-.7 .7h-.6v-.2h.6a.58 .58 0 0 0 .5-.5 .58 .58 0 0 0-.5-.6h-.4v1.1h-.2z" fill-rule="evenodd"/>
<path d="M75.3 159.5h1.1v.2h-.9v.4h.8v.2h-.8v.5h.9v.2h-1.1z" fill-rule="evenodd"/>
<path d="M75.6 169.7l.3-.1h.4l.2 .3-.2 .1a.32 .32 0 0 0-.3-.4 .32 .32 0 0 0-.3 .5h.1a.57 .57 0 0 1 .7 .7 .64 .64 0 0 1-.6 .3 .64 .64 0 0 1-.5-.5h.2a.39 .39 0 0 0 .4 .3 .39 .39 0 0 0 .3-.4l-.2-.1a.49 .49 0 0 1-.5-.1 .49 .49 0 0 1 0-.6z" fill-rule="evenodd"/>
<path d="M75.6 164.5h.2l.3 1.3 .3-1.3h.3l.3 1.3 .3-1.3h.2l-.4 1.5h-.2l-.4-1.3-.3 1.3h-.2z" fill-rule="evenodd"/>
<path d="M76.9 169.6h1v.1h-.8v.5h.8v.2h-.8v.5h.9v.2h-1.1z" fill-rule="evenodd"/>
<path d="M76.6 174.6l.9 .1 .2 .4a.25 .25 0 0 0-.1 .2 .25 .25 0 0 0 .1 .2 .45 .45 0 0 1 0 .5 .45 .45 0 0 1-.5 .1h-.6v-.2h.7l.2-.1v-.3l-.7-.1v.5h-.2v-.7h.6a.24 .24 0 0 0 .3-.1 .24 .24 0 0 0-.2-.3h-.5v.4h-.2z" fill-rule="evenodd"/>
<path d="M77.1 177.1h1.2v.2h-.5v1.3h-.2v-1.3h-.5z" fill-rule="evenodd"/>
<path d="M77.7 164.5h.2v1.5h-.2z" fill-rule="evenodd"/>
<path d="M76.8 159.7l.4-.2a.6 .6 0 0 1 .8 .4l-.2 .1a.53 .53 0 0 0-.8-.2 .53 .53 0 0 0-.1 .8l.4 .2h.3l.2-.3h.2a.72 .72 0 0 1-1.1 .4 .72 .72 0 0 1-.2-1.1z" fill-rule="evenodd"/>
<path d="M78 174.6h1.1v.2h-.9v.5h.9v.1h-.9v.5h1v.2h-1.2z" fill-rule="evenodd"/>
<path d="M78.2 169.6h.2l.8 1.2v-1.2h.2v1.5h-.2l-.8-1.2v1.2h-.2z" fill-rule="evenodd"/>
<path d="M78.5 177.1h.2v.7h.8v-.7h.2v1.5h-.2v-.7h-.8v.7h-.2z" fill-rule="evenodd"/>
<path d="M78.2 164.5h1.2v.2h-.5v1.3h-.2v-1.3h-.5z" fill-rule="evenodd"/>
<path d="M78.8 159.5h1v.2h-.8v.4h.7v.2h-.7v.7h-.2z" fill-rule="evenodd"/>
<path d="M79.6 164.5h.2v.7h.8v-.7h.2v1.5h-.2v-.7h-.8v.7h-.2z" fill-rule="evenodd"/>
<path d="M79.3 174.6h1.2v.2h-.5v1.3h-.2v-1.3h-.5z" fill-rule="evenodd"/>
<path d="M80 177.1h1.1v.2h-.9v.5h.9v.1h-.9v.6h1v.1h-1.2z" fill-rule="evenodd"/>
<path d="M79.6 169.6h1.2v.1h-.5v1.4h-.2v-1.4h-.5z" fill-rule="evenodd"/>
<path d="M80.7 159.5h1.1v.2h-.9v.4h.8v.2h-.8v.5h.9v.2h-1.1z" fill-rule="evenodd"/>
<path d="M80.6 174.6h.2l.3 1.3 .3-1.3h.3l.3 1.3 .3-1.3h.2l-.4 1.5h-.2l-.3-1.3-.4 1.3h-.2z" fill-rule="evenodd"/>
<path d="M81.6 169.6h.2v1.5h-.2z" fill-rule="evenodd"/>
<path d="M82 177.1h.3l.4 1.3 .5-1.3h.2v1.5h-.1v-1.2l-.5 1.2h-.2l-.4-1.2v1.2h-.2z" fill-rule="evenodd"/>
<path d="M82.2 169.6h.2l.8 1.2v-1.2h.2v1.5h-.2l-.8-1.2v1.2h-.2z" fill-rule="evenodd"/>
<path d="M82.7 174.6h1.1v.2h-.9v.5h.8v.1h-.8v.5h.9v.2h-1.1z" fill-rule="evenodd"/>
<path d="M82 164.5h.2l.6 1.5h-.2l-.2-.4h-.6l-.1 .4h-.3l.3-.6h.7l-.3-.7-.2 .7h-.2z" fill-rule="evenodd"/>
<path d="M83.6 159.5a1.23 1.23 0 0 1 0 1.9 1.74 1.74 0 0 0 0-1.9z" fill-rule="evenodd"/>
<path d="M84.1 174.6h1.1v.2h-.9v.5h.8v.1h-.8v.5h.9v.2h-1.1z" fill-rule="evenodd"/>
<path d="M83.4 164.5h.7a.42 .42 0 0 1 .5 .4 .42 .42 0 0 1-.4 .5l.5 .6h-.2l-.4-.5-.3-.1h-.2v.6h-.2v-.8h.6a.26 .26 0 0 0 .4-.2 .26 .26 0 0 0-.3-.3h-.5v.5h-.2z" fill-rule="evenodd"/>
<path d="M84.1 169.6h1.2v.1h-.5v1.4h-.2v-1.4h-.5z" fill-rule="evenodd"/>
<path d="M84.9 164.5h1.1v.2h-.9v.5h.9v.1h-.9v.6h1v.1h-1.2z" fill-rule="evenodd"/>
<path d="M84.2 177.1h.2l.6 1.5h-.2l-.2-.4h-.6l-.2 .4h-.2l.2-.6h.7l-.2-.7-.3 .7h-.2z" fill-rule="evenodd"/>
<path d="M85.2 177.1h.2v1.5h-.2z" fill-rule="evenodd"/>
<path d="M85.5 174.6h.2l.8 1.2v-1.2h.2v1.5h-.2l-.8-1.2v1.2h-.2z" fill-rule="evenodd"/>
<path d="M85.5 169.6h.2v.6h.8v-.6h.2v1.5h-.2v-.7h-.8v.7h-.2z" fill-rule="evenodd"/>
<path d="M85.7 177.1h.2l.8 1.2v-1.2h.2v1.5h-.2l-.8-1.1v1.1h-.2z" fill-rule="evenodd"/>
<path d="M86.3 164.5h.5a.75 .75 0 0 1 .8 .8 .75 .75 0 0 1-.7 .7h-.6v-.1h.5a.58 .58 0 0 0 .6-.6 .58 .58 0 0 0-.6-.6h-.3v1.2h-.2z" fill-rule="evenodd"/>
<path d="M87 169.6h1.1v.1h-.9v.5h.9v.2h-.9v.5h1v.2h-1.2z" fill-rule="evenodd"/>
<path d="M87.9 177.3l.4-.2 .4 .1 .2 .3-.2 .1a.32 .32 0 0 0-.3-.4 .32 .32 0 0 0-.3 .5h.1a.57 .57 0 0 1 .7 .7 .64 .64 0 0 1-.6 .3 .64 .64 0 0 1-.5-.5l.2-.1a.39 .39 0 0 0 .4 .4 .39 .39 0 0 0 .3-.4l-.2-.1a.49 .49 0 0 1-.5-.2 .49 .49 0 0 1-.1-.5z" fill-rule="evenodd"/>
<path d="M87.5 174.6h1.2v.2h-.5v1.3h-.2v-1.3h-.5z" fill-rule="evenodd"/>
<path d="M88.9 174.6h.2v.6h.7v-.6h.2v1.5h-.2v-.7h-.7v.7h-.2z" fill-rule="evenodd"/>
<path d="M88.6 164.7l.3-.2h.4l.3 .3 .1 .2h-.2a.53 .53 0 0 0-.8-.2 .53 .53 0 0 0-.1 .8l.5 .3 .2-.1 .2-.3 .2 .1a.72 .72 0 0 1-1 .4 .72 .72 0 0 1-.2-1.1z" fill-rule="evenodd"/>
<path d="M89 169.6h.8l.3 .4a.25 .25 0 0 0-.2 .3 .25 .25 0 0 0 .2 .2 .45 .45 0 0 1-.5 .6h-.6v-.2h.7l.2-.1-.1-.4h-.6v.5h-.2v-.7h.5a.24 .24 0 0 0 .4-.1 .24 .24 0 0 0-.2-.3l-.5-.1v.5h-.2z" fill-rule="evenodd"/>
<path d="M89.4 177.3a.74 .74 0 0 1 1.1 .1 .74 .74 0 0 1-.3 1.1 .74 .74 0 0 1-1-.5v-.1h.2a.56 .56 0 0 0 .8 .5 .56 .56 0 0 0 .1-.9l-.3-.2a.52 .52 0 0 0-.6 .6h-.2z" fill-rule="evenodd"/>
<path d="M90.4 174.6h1.1v.2h-.9v.5h.8v.1h-.8v.5h.9v.2h-1.1z" fill-rule="evenodd"/>
<path d="M89.9 164.5h.7a.42 .42 0 0 1 .5 .4 .42 .42 0 0 1-.4 .5l.6 .6h-.3a.74 .74 0 0 0-.9-.6v.6h-.2v-.8h.7a.26 .26 0 0 0 .3-.2 .26 .26 0 0 0-.3-.3h-.5v.5h-.2z" fill-rule="evenodd"/>
<path d="M90.6 169.8a.74 .74 0 0 1 1.1 .1 .74 .74 0 0 1-.3 1.1 .74 .74 0 0 1-1-.5v-.2h.2a.56 .56 0 0 0 .7 .6 .56 .56 0 0 0 .2-1l-.3-.2a.52 .52 0 0 0-.6 .6h-.2z" fill-rule="evenodd"/>
<path d="M90.9 177.1h.2v.9a.4 .4 0 0 0 .4 .5 .4 .4 0 0 0 .4-.5v-.9h.2v.9a.59 .59 0 0 1-.6 .7 .59 .59 0 0 1-.6-.7z" fill-rule="evenodd"/>
<path d="M92 169.6h.3l.5 1.3 .4-1.3h.3v1.5h-.2v-1.3l-.5 1.3h-.1l-.5-1.3v1.3h-.2z" fill-rule="evenodd"/>
<path d="M91.6 164.7a.74 .74 0 0 1 1.1 .1 .74 .74 0 0 1-.3 1.1 .74 .74 0 0 1-1-.5v-.1h.2a.56 .56 0 0 0 .8 .5 .56 .56 0 0 0 .1-.9l-.3-.2a.52 .52 0 0 0-.6 .6h-.2z" fill-rule="evenodd"/>
<path d="M93.2 164.7l.3-.2 .4 .1 .3 .3-.2 .1a.32 .32 0 0 0-.4-.4 .32 .32 0 0 0-.2 .5h.1a.57 .57 0 0 1 .7 .7 .64 .64 0 0 1-.7 .3 .64 .64 0 0 1-.5-.5l.2-.1a.39 .39 0 0 0 .4 .4 .39 .39 0 0 0 .4-.4l-.2-.1a.49 .49 0 0 1-.6-.2 .49 .49 0 0 1 0-.5z" fill-rule="evenodd"/>
<path d="M92.4 177.1h.7a.42 .42 0 0 1 .5 .4 .42 .42 0 0 1-.4 .5l.5 .6h-.2l-.4-.5-.3-.1h-.2v.6h-.2v-.8h.6a.26 .26 0 0 0 .4-.2 .26 .26 0 0 0-.3-.3h-.5v.5h-.2z" fill-rule="evenodd"/>
<path d="M92.7 174.6h.2l.6 1.5h-.2l-.2-.4h-.6l-.2 .4h-.2l.3-.6h.7l-.3-.7-.2 .7h-.2z" fill-rule="evenodd"/>
<path d="M93.7 174.7l.3-.1h.4l.3 .4-.2 .1a.32 .32 0 0 0-.3-.4 .32 .32 0 0 0-.3 .5h.1a.57 .57 0 0 1 .7 .6 .64 .64 0 0 1-.6 .3 .64 .64 0 0 1-.5-.5h.2a.39 .39 0 0 0 .4 .4 .39 .39 0 0 0 .3-.4l-.2-.1a.49 .49 0 0 1-.6-.2 .49 .49 0 0 1 0-.6z" fill-rule="evenodd"/>
<path d="M93.8 170.9h.2v.2h-.2z" fill-rule="evenodd"/>
<path d="M94.6 164.7l.3-.2 .4 .1 .3 .3-.2 .1a.32 .32 0 0 0-.4-.4 .32 .32 0 0 0-.2 .5h.1a.57 .57 0 0 1 .7 .7 .64 .64 0 0 1-.7 .3 .64 .64 0 0 1-.5-.5l.2-.1a.39 .39 0 0 0 .4 .4 .39 .39 0 0 0 .4-.4l-.2-.1a.49 .49 0 0 1-.6-.2 .49 .49 0 0 1 0-.5z" fill-rule="evenodd"/>
<path d="M95.1 174.7l.3-.1h.4l.3 .4-.2 .1a.32 .32 0 0 0-.3-.4 .32 .32 0 0 0-.3 .5h.1a.57 .57 0 0 1 .7 .6 .64 .64 0 0 1-.6 .3 .64 .64 0 0 1-.5-.5h.2a.39 .39 0 0 0 .4 .4 .39 .39 0 0 0 .3-.4l-.2-.1a.49 .49 0 0 1-.6-.2 .49 .49 0 0 1 0-.6z" fill-rule="evenodd"/>
<path d="M94 177.3l.4-.2h.4l.3 .3 .1 .2h-.2a.53 .53 0 0 0-.8-.2 .53 .53 0 0 0-.1 .8l.4 .3 .3-.1 .2-.3 .2 .1a.72 .72 0 0 1-1.1 .4 .72 .72 0 0 1-.2-1.1z" fill-rule="evenodd"/>
<path d="M95.4 177.1h1.1v.2h-.9v.5h.9v.1h-.9v.6h.9v.1h-1.1z" fill-rule="evenodd"/>
<path d="M95.9 165.8h.2v.2h-.2z" fill-rule="evenodd"/>
<path d="M96.4 174.6h1.1v.2h-.9v.5h.9v.1h-.9v.5h1v.2h-1.2z" fill-rule="evenodd"/>
<path d="M96.9 178.4h.2v.2h-.2z" fill-rule="evenodd"/>
<path d="M97.8 174.6h.3l.5 1.3 .4-1.3h.3v1.5h-.2v-1.2l-.5 1.2h-.2l-.4-1.3v1.3h-.2z" fill-rule="evenodd"/>
<path d="M99.6 174.6l.8 .1 .2 .4a.25 .25 0 0 0-.1 .2 .25 .25 0 0 0 .2 .2 .45 .45 0 0 1-.6 .6h-.5v-.2h.7l.2-.1-.1-.3-.6-.1v.5h-.2v-.7h.5a.24 .24 0 0 0 .3-.1 .24 .24 0 0 0-.2-.3h-.4v.4h-.2z" fill-rule="evenodd"/>
<path d="M101 174.6h.2v1.3h.7v.2h-.9z" fill-rule="evenodd"/>
<path d="M101.9 174.6h.3l.4 .7 .5-.7h.2l-.6 .9v.6h-.2v-.6z" fill-rule="evenodd"/>
<path d="M30.2 187.2h.7v.2h-.6l-.1 .4a.5 .5 0 0 1 .7 .3 .5 .5 0 0 1-.3 .6 .5 .5 0 0 1-.6-.4h.2a.34 .34 0 0 0 .5 .2 .34 .34 0 0 0 0-.6 .34 .34 0 0 0-.5 .1h-.2z" fill-rule="evenodd"/>
<path d="M30.6 182.2h.2v1h.2v.1h-.2v.4h-.2v-.4h-.7v-.1h.7v-.7l-.5 .7h-.2z" fill-rule="evenodd"/>
<path d="M31.2 182.2a1.23 1.23 0 0 1 0 1.9 1.73 1.73 0 0 0 0-1.9z" fill-rule="evenodd"/>
<path d="M31.2 187.2a1.23 1.23 0 0 1 0 2 1.73 1.73 0 0 0 0-2z" fill-rule="evenodd"/>
<path d="M33.5 189.7h.2l.3 1.3 .4-1.3h.2l.3 1.3 .4-1.3h.2l-.5 1.5h-.1l-.4-1.3-.4 1.3h-.2z" fill-rule="evenodd"/>
<path d="M33.7 187.2h.5a.75 .75 0 0 1 .7 .8 .75 .75 0 0 1-.7 .7h-.5v-.2h.5a.58 .58 0 0 0 .5-.5 .58 .58 0 0 0-.5-.6h-.3v1.1h-.2z" fill-rule="evenodd"/>
<path d="M33.8 182.4l.4-.2h.3l.4 .3v.1h-.2a.53 .53 0 0 0-.8-.1 .53 .53 0 0 0 0 .7l.4 .3 .3-.1 .1-.3 .2 .1a.72 .72 0 0 1-1 .4 .72 .72 0 0 1-.2-1.1z" fill-rule="evenodd"/>
<path d="M35.6 189.7h.2v.7h.8v-.7h.2v1.5h-.2v-.7h-.8v.7h-.2z" fill-rule="evenodd"/>
<path d="M35.3 182.4a.74 .74 0 0 1 1.2 .1 .74 .74 0 0 1-.3 1.1 .74 .74 0 0 1-1.1-.5v-.2h.2a.56 .56 0 0 0 .8 .6 .56 .56 0 0 0 .1-1 .52 .52 0 0 0-.6-.1 .52 .52 0 0 0-.3 .5h-.2z" fill-rule="evenodd"/>
<path d="M35.3 187.4a.74 .74 0 0 1 1.2 .1 .74 .74 0 0 1-.3 1.1 .74 .74 0 0 1-1.1-.5v-.1h.2a.56 .56 0 0 0 .8 .5 .56 .56 0 0 0 .1-.9l-.3-.2a.52 .52 0 0 0-.6 .6h-.2z" fill-rule="evenodd"/>
<path d="M36.8 182.2h.2l.8 1.2v-1.2h.2v1.5h-.2l-.8-1.2v1.2h-.2z" fill-rule="evenodd"/>
<path d="M37.2 189.7h1v.2h-.8v.5h.8v.1h-.8v.6h.9v.1h-1.1z" fill-rule="evenodd"/>
<path d="M36.7 187.2h1.2v.2h-.5v1.3h-.2v-1.3h-.5z" fill-rule="evenodd"/>
<path d="M38.3 182.2h1v.1h-.8v.5h.7v.2h-.7v.7h-.2z" fill-rule="evenodd"/>
<path d="M38.6 189.7h.2l.7 1.2v-1.2h.2v1.5h-.2l-.8-1.1v1.1h-.1z" fill-rule="evenodd"/>
<path d="M38.7 187.2h.2v1.5h-.2z" fill-rule="evenodd"/>
<path d="M39.2 187.2h.5a.75 .75 0 0 1 .8 .8 .75 .75 0 0 1-.7 .7h-.6v-.2h.5a.58 .58 0 0 0 .6-.5 .58 .58 0 0 0-.6-.6h-.3v1.1h-.2z" fill-rule="evenodd"/>
<path d="M39.7 182.4a.74 .74 0 0 1 1.2 .1 .74 .74 0 0 1-.3 1.1 .74 .74 0 0 1-1-.5l-.1-.2h.3a.56 .56 0 0 0 .7 .6 .56 .56 0 0 0 .2-1 .52 .52 0 0 0-.7-.1 .52 .52 0 0 0-.2 .5h-.3z" fill-rule="evenodd"/>
<path d="M40.7 187.2h1.1v.2h-.9v.5h.9v.1h-.9v.5h1v.2h-1.2z" fill-rule="evenodd"/>
<path d="M40.5 189.7h.2l.5 1.4 .5-1.4h.2l-.6 1.5h-.2z" fill-rule="evenodd"/>
<path d="M41.2 182.2h.7a.42 .42 0 0 1 .5 .3 .42 .42 0 0 1-.4 .5l.6 .7h-.3l-.4-.6-.2-.1h-.3v.7h-.2v-.9h.7a.26 .26 0 0 0 .3-.2 .26 .26 0 0 0-.3-.3h-.5v.5h-.2z" fill-rule="evenodd"/>
<path d="M42.1 189.7h.2v1.5h-.2z" fill-rule="evenodd"/>
<path d="M42.1 187.2h.2l.8 1.2v-1.2h.2v1.5h-.2l-.8-1.2v1.2h-.2z" fill-rule="evenodd"/>
<path d="M42.6 189.7h1.1v.2h-.9v.5h.9v.1h-.9v.6h1v.1h-1.2z" fill-rule="evenodd"/>
<path d="M42.7 182.2h.3l.5 1.3 .4-1.3h.3v1.5h-.2v-1.3l-.4 1.3h-.2l-.5-1.3v1.3h-.2z" fill-rule="evenodd"/>
<path d="M43.5 187.2h1.2v.2h-.5v1.3h-.2v-1.3h-.5z" fill-rule="evenodd"/>
<path d="M43.9 189.7h.2l.3 1.3 .4-1.3h.2l.3 1.3 .3-1.3h.2l-.4 1.5h-.2l-.3-1.3-.4 1.3h-.2z" fill-rule="evenodd"/>
<path d="M45 187.2h.2v1.5h-.2z" fill-rule="evenodd"/>
<path d="M45.5 187.2h1v.2h-.8v.5h.7v.1h-.7v.7h-.2z" fill-rule="evenodd"/>
<path d="M44.9 182.2h.2l.6 1.5h-.2l-.2-.5h-.6l-.2 .5h-.2l.3-.6h.7l-.3-.8-.2 .8h-.2z" fill-rule="evenodd"/>
<path d="M45.9 182.2h.2v1.3h.7v.2h-.9z" fill-rule="evenodd"/>
<path d="M46 189.7h1.1v.2h-.9v.5h.9v.1h-.9v.6h.9v.1h-1.1z" fill-rule="evenodd"/>
<path d="M46.8 187.2h.2v1.5h-.2z" fill-rule="evenodd"/>
<path d="M47.4 187.2h1.1v.2h-.9v.5h.8v.1h-.8v.5h.9v.2h-1.1z" fill-rule="evenodd"/>
<path d="M47.4 189.7h.5a.75 .75 0 0 1 .8 .8 .75 .75 0 0 1-.7 .7h-.6v-.1h.5a.58 .58 0 0 0 .6-.6 .58 .58 0 0 0-.6-.6h-.3v1.2h-.2z" fill-rule="evenodd"/>
<path d="M47.7 182.4l.4-.2h.3l.4 .3v.1h-.2a.53 .53 0 0 0-.7-.1 .53 .53 0 0 0-.1 .7l.4 .3 .3-.1 .1-.3 .2 .1a.72 .72 0 0 1-1 .4 .72 .72 0 0 1-.2-1.1z" fill-rule="evenodd"/>
<path d="M48.9 187.3l.3-.1h.4l.3 .4-.2 .1a.32 .32 0 0 0-.4-.4 .32 .32 0 0 0-.2 .5h.1a.57 .57 0 0 1 .7 .6 .64 .64 0 0 1-.7 .3 .64 .64 0 0 1-.5-.5h.2a.39 .39 0 0 0 .4 .4 .39 .39 0 0 0 .4-.4l-.2-.1a.49 .49 0 0 1-.6-.2 .49 .49 0 0 1 0-.6z" fill-rule="evenodd"/>
<path d="M49.5 189.7h1v.2h-.8v.5h.7v.2h-.7v.6h-.2z" fill-rule="evenodd"/>
<path d="M49.2 182.4a.74 .74 0 0 1 1.2 .1 .74 .74 0 0 1-.3 1.1 .74 .74 0 0 1-1.1-.5v-.2h.2a.56 .56 0 0 0 .8 .6 .56 .56 0 0 0 .2-1 .52 .52 0 0 0-.7-.1 .52 .52 0 0 0-.3 .5h-.2z" fill-rule="evenodd"/>
<path d="M50.8 187.2h.5a.46 .46 0 0 1 .6 .4 .46 .46 0 0 1-.6 .5h-.3v.6h-.2v-.8h.6a.28 .28 0 0 0 .3-.2 .28 .28 0 0 0-.4-.3h-.3v.5h-.2z" fill-rule="evenodd"/>
<path d="M50.8 189.7h.7a.42 .42 0 0 1 .5 .4 .42 .42 0 0 1-.4 .5l.5 .6h-.2l-.4-.5-.3-.1h-.2v.6h-.2v-.8h.6a.26 .26 0 0 0 .4-.2 .26 .26 0 0 0-.3-.3h-.5v.5h-.2z" fill-rule="evenodd"/>
<path d="M51.1 182.2h.2l.7 1.5h-.3l-.1-.5h-.7l-.1 .5h-.2l.2-.6h.7l-.3-.8-.2 .8h-.2z" fill-rule="evenodd"/>
<path d="M52.2 187.2h.2v1.5h-.2z" fill-rule="evenodd"/>
<path d="M51.9 182.2h1.2v.1h-.5v1.4h-.2v-1.4h-.5z" fill-rule="evenodd"/>
<path d="M52.7 187.2h.2l.8 1.2v-1.2h.2v1.5h-.2l-.8-1.2v1.2h-.2z" fill-rule="evenodd"/>
<path d="M52.5 189.9a.74 .74 0 0 1 1.1 .1 .74 .74 0 0 1-.3 1.1 .74 .74 0 0 1-1-.5v-.1h.2a.56 .56 0 0 0 .8 .5 .56 .56 0 0 0 .1-.9l-.1-.1a.52 .52 0 0 0-.6 0 .52 .52 0 0 0-.2 .5h-.2z" fill-rule="evenodd"/>
<path d="M53.3 182.2h.2v1.5h-.2z" fill-rule="evenodd"/>
<path d="M53.8 182.2h.2l.8 1.2v-1.2h.2v1.5h-.2l-.8-1.2v1.2h-.2z" fill-rule="evenodd"/>
<path d="M53.9 189.7h.3l.5 1.3 .4-1.3h.3v1.5h-.2v-1.2l-.5 1.2h-.1l-.5-1.2v1.2h-.2z" fill-rule="evenodd"/>
<path d="M55.1 187.2h.2l-.1 .4h.3l.1-.4h.1l-.1 .4h.2v.2h-.2l-.1 .4h.3v.1h-.3l-.1 .4h-.1l.1-.4h-.4l-.1 .4h-.1l.1-.4h-.2v-.1h.7l.1-.4h-.4v.4h-.2l.1-.4h-.3v-.2h.3z" fill-rule="evenodd"/>
<path d="M55.5 182.4l.3-.2h.5l.3 .2 .1 .2h-.2a.58 .58 0 0 0-.8-.1 .58 .58 0 0 0-.2 .8 .58 .58 0 0 0 .8 .2l.2-.1v-.3h-.4v-.2h.6v.6a.81 .81 0 0 1-1.2 0 .81 .81 0 0 1 0-1.1z" fill-rule="evenodd"/>
<path d="M56.1 187.6l.5-.4v1.5h-.2v-1.2l-.3 .3z" fill-rule="evenodd"/>
<path d="M56.1 189.7h1.2v.2h-.5v1.3h-.2v-1.3h-.5z" fill-rule="evenodd"/>
<path d="M57.5 189.7h.2v.7h.8v-.7h.2v1.5h-.2v-.7h-.8v.7h-.2z" fill-rule="evenodd"/>
<path d="M57.6 182.2h.2v1.5h-.2z" fill-rule="evenodd"/>
<path d="M57.8 187.2h.2v1.3h.7v.2h-.9z" fill-rule="evenodd"/>
<path d="M58.2 182.3l.4-.1h.4l.2 .3-.2 .1a.32 .32 0 0 0-.3-.4 .32 .32 0 0 0-.3 .5h.1a.57 .57 0 0 1 .7 .7 .64 .64 0 0 1-.6 .3 .64 .64 0 0 1-.5-.5h.2a.39 .39 0 0 0 .4 .3 .39 .39 0 0 0 .3-.4l-.2-.1a.49 .49 0 0 1-.5-.1 .49 .49 0 0 1-.1-.6z" fill-rule="evenodd"/>
<path d="M59 189.7h1.1v.2h-.9v.5h.9v.1h-.9v.6h1v.1h-1.2z" fill-rule="evenodd"/>
<path d="M59.1 187.4a.74 .74 0 0 1 1.1 .1 .74 .74 0 0 1-.3 1.1 .74 .74 0 0 1-1-.5v-.1h.2a.56 .56 0 0 0 .8 .5 .56 .56 0 0 0 .1-.9l-.3-.2a.52 .52 0 0 0-.6 .6h-.2z" fill-rule="evenodd"/>
<path d="M60.1 182.2h.2l.8 1.2v-1.2h.2v1.5h-.2l-.8-1.2v1.2h-.2z" fill-rule="evenodd"/>
<path d="M60.9 189.7h1.2v.2h-.5v1.3h-.2v-1.3h-.5z" fill-rule="evenodd"/>
<path d="M60.7 187.4l.4-.2h.3l.4 .3v.1l-.2 .1a.53 .53 0 0 0-.8-.2 .53 .53 0 0 0 0 .8l.4 .3 .3-.1 .1-.3h.2a.72 .72 0 0 1-1 .4 .72 .72 0 0 1-.2-1.1z" fill-rule="evenodd"/>
<path d="M61.8 182.4a.74 .74 0 0 1 1.1 .1 .74 .74 0 0 1-.3 1.1 .74 .74 0 0 1-1-.5v-.2h.2a.56 .56 0 0 0 .8 .6 .56 .56 0 0 0 .1-1 .52 .52 0 0 0-.6-.1 .52 .52 0 0 0-.3 .5h-.2z" fill-rule="evenodd"/>
<path d="M62.4 189.9a.74 .74 0 0 1 1.1 .1 .74 .74 0 0 1-.3 1.1 .74 .74 0 0 1-1-.5v-.1h.2a.56 .56 0 0 0 .8 .5 .56 .56 0 0 0 .1-.9l-.1-.1a.52 .52 0 0 0-.6 0 .52 .52 0 0 0-.2 .5h-.2z" fill-rule="evenodd"/>
<path d="M62.5 187.2h.2l.6 1.5h-.2l-.2-.4h-.6l-.2 .4h-.2l.2-.6h.8l-.3-.7-.3 .7h-.2z" fill-rule="evenodd"/>
<path d="M63.2 182.2h1.2v.1h-.5v1.4h-.2v-1.4h-.5z" fill-rule="evenodd"/>
<path d="M63.3 187.2h1.2v.2h-.5v1.3h-.2v-1.3h-.5z" fill-rule="evenodd"/>
<path d="M63.9 189.7h.5a.46 .46 0 0 1 .6 .5 .46 .46 0 0 1-.6 .4h-.3v.6h-.2v-.8h.5a.28 .28 0 0 0 .4-.2 .28 .28 0 0 0-.4-.3h-.3v.5h-.2z" fill-rule="evenodd"/>
<path d="M64.6 187.2h.2v1.5h-.2z" fill-rule="evenodd"/>
<path d="M65.2 191h.2v.2h-.2z" fill-rule="evenodd"/>
<path d="M65.1 182.2h.7a.42 .42 0 0 1 .5 .3 .42 .42 0 0 1-.4 .5l.5 .7h-.2l-.4-.6-.3-.1h-.2v.7h-.2v-.9h.6a.26 .26 0 0 0 .4-.2 .26 .26 0 0 0-.3-.3h-.5v.5h-.2z" fill-rule="evenodd"/>
<path d="M65.3 187.4a.74 .74 0 0 1 1.2 .1 .74 .74 0 0 1-.3 1.1 .74 .74 0 0 1-1.1-.5v-.1h.2a.56 .56 0 0 0 .8 .5 .56 .56 0 0 0 .1-.9l-.3-.2a.52 .52 0 0 0-.6 .6h-.2z" fill-rule="evenodd"/>
<path d="M66.6 182.2h1.1v.1h-.9v.5h.9v.2h-.9v.5h.9v.2h-1.1z" fill-rule="evenodd"/>
<path d="M66.8 187.2h.2l.8 1.2v-1.2h.2v1.5h-.2l-.8-1.2v1.2h-.2z" fill-rule="evenodd"/>
<path d="M68.1 182.4a.77 .77 0 0 1 1.1 0 .77 .77 0 0 1 0 1.1l.2 .2v.1l-.4-.2a.72 .72 0 0 1-1.1-.7h.3a.52 .52 0 0 0 .7 .6l-.2-.1v-.1a.28 .28 0 0 0 .4 0 .28 .28 0 0 0 .1-.4 .52 .52 0 0 0-.5-.6 .52 .52 0 0 0-.5 .6h-.3z" fill-rule="evenodd"/>
<path d="M69.3 187.2h.2l.6 1.5h-.2l-.2-.4h-.6l-.2 .4h-.2l.2-.6h.7l-.2-.7-.3 .7h-.2z" fill-rule="evenodd"/>
<path d="M70.2 187.2h.2l.8 1.2v-1.2h.2v1.5h-.2l-.8-1.2v1.2h-.2z" fill-rule="evenodd"/>
<path d="M69.7 182.2h.2v.8a.4 .4 0 0 0 .3 .5 .4 .4 0 0 0 .4-.5v-.8h.2v.8a.59 .59 0 0 1-.6 .7 .59 .59 0 0 1-.5-.7z" fill-rule="evenodd"/>
<path d="M71.2 182.2h.2v1.5h-.2z" fill-rule="evenodd"/>
<path d="M71.7 187.2h.5a.75 .75 0 0 1 .8 .8 .75 .75 0 0 1-.7 .7h-.6v-.2h.5a.58 .58 0 0 0 .6-.5 .58 .58 0 0 0-.6-.6h-.3v1.1h-.2z" fill-rule="evenodd"/>
<path d="M71.8 182.2h.6a.42 .42 0 0 1 .6 .3 .42 .42 0 0 1-.5 .5l.6 .7h-.3l-.4-.6-.2-.1h-.2v.7h-.2v-.9h.6a.26 .26 0 0 0 .3-.2 .26 .26 0 0 0-.3-.3h-.4v.5h-.2z" fill-rule="evenodd"/>
<path d="M73.3 182.2h1.1v.1h-.9v.5h.8v.2h-.8v.5h.9v.2h-1.1z" fill-rule="evenodd"/>
<path d="M73.8 187.2h.5a.75 .75 0 0 1 .8 .8 .75 .75 0 0 1-.7 .7h-.6v-.2h.5a.58 .58 0 0 0 .6-.5 .58 .58 0 0 0-.6-.6h-.3v1.1h-.2z" fill-rule="evenodd"/>
<path d="M75.3 187.2h1.1v.2h-.9v.5h.9v.1h-.9v.5h1v.2h-1.2z" fill-rule="evenodd"/>
<path d="M74.7 182.2h.5a.75 .75 0 0 1 .7 .7 .75 .75 0 0 1-.7 .8h-.5v-.2h.5a.58 .58 0 0 0 .5-.6 .58 .58 0 0 0-.5-.6h-.3v1.2h-.2z" fill-rule="evenodd"/>
<path d="M76.2 183.5h.2v.2h-.2z" fill-rule="evenodd"/>
<path d="M76.6 187.2h.2l.5 1.4 .4-1.4h.3l-.6 1.5h-.2z" fill-rule="evenodd"/>
<path d="M78.2 187.2h.2v1.5h-.2z" fill-rule="evenodd"/>
<path d="M78.9 187.4l.3-.2h.4l.3 .3 .1 .1-.2 .1a.53 .53 0 0 0-.8-.2 .53 .53 0 0 0-.1 .8l.4 .3 .3-.1 .2-.3h.2a.72 .72 0 0 1-1.1 .4 .72 .72 0 0 1-.2-1.1z" fill-rule="evenodd"/>
<path d="M80.2 187.2h1.1v.2h-.9v.5h.9v.1h-.9v.5h1v.2h-1.2z" fill-rule="evenodd"/>
<path d="M82.4 187.4a.74 .74 0 0 1 1.1 .1 .74 .74 0 0 1-.3 1.1 .74 .74 0 0 1-1-.5l-.1-.1h.3a.56 .56 0 0 0 .7 .5 .56 .56 0 0 0 .2-.9l-.3-.2a.52 .52 0 0 0-.6 .6h-.3z" fill-rule="evenodd"/>
<path d="M83.8 187.2h.7a.42 .42 0 0 1 .5 .4 .42 .42 0 0 1-.4 .4l.6 .7h-.3a.74 .74 0 0 0-.9-.6v.6h-.2v-.8h.7a.26 .26 0 0 0 .3-.2 .26 .26 0 0 0-.3-.3h-.5v.5h-.2z" fill-rule="evenodd"/>
<path d="M85.4 187.2h.2v1.5h-.2z" fill-rule="evenodd"/>
<path d="M85.9 187.2h1.1v.2h-.9v.5h.9v.1h-.9v.5h1v.2h-1.2z" fill-rule="evenodd"/>
<path d="M87.3 187.2h.2l.8 1.2v-1.2h.2v1.5h-.2l-.8-1.2v1.2h-.2z" fill-rule="evenodd"/>
<path d="M88.7 187.2h1.2v.2h-.5v1.3h-.2v-1.3h-.5z" fill-rule="evenodd"/>
<path d="M90.5 187.2h.2l.6 1.5h-.2l-.2-.4h-.6l-.2 .4h-.2l.2-.6h.7l-.2-.7-.3 .7h-.2z" fill-rule="evenodd"/>
<path d="M91.2 187.2h1.2v.2h-.5v1.3h-.2v-1.3h-.5z" fill-rule="evenodd"/>
<path d="M92.5 187.2h.2v1.5h-.2z" fill-rule="evenodd"/>
<path d="M93.2 187.4a.74 .74 0 0 1 1.2 .1 .74 .74 0 0 1-.3 1.1 .74 .74 0 0 1-1.1-.5v-.1h.2a.56 .56 0 0 0 .8 .5 .56 .56 0 0 0 .2-.9l-.4-.2a.52 .52 0 0 0-.6 .6h-.2z" fill-rule="evenodd"/>
<path d="M94.7 187.2h.2l.8 1.2v-1.2h.2v1.5h-.2l-.8-1.2v1.2h-.2z" fill-rule="evenodd"/>
<path d="M30.2 217.5a2.21 2.21 0 0 1 2.1-.2l.1-.2v1a.98 .98 0 0 0-1.2-.8 .98 .98 0 0 0-.7 1.2 1.01 1.01 0 0 0 .6 1.3 1.01 1.01 0 0 0 1.3-.5v.3a1.47 1.47 0 0 1-2.2 .1 1.47 1.47 0 0 1 0-2.2z" fill-rule="evenodd"/>
<path d="M33.2 218.1a.97 .97 0 0 1 1.4 .9 .97 .97 0 0 1-1.5 .8l-.3-.6h.6v.4a.26 .26 0 0 0 .2 .3 .26 .26 0 0 0 .3-.3v-1.3a.28 .28 0 0 0-.3-.2 .28 .28 0 0 0-.2 .4v.7h-.6v-.6z" fill-rule="evenodd"/>
<path d="M34.9 218h.8v.3a.59 .59 0 0 1 .5-.3 .59 .59 0 0 1 .6 .3 .61 .61 0 0 1 .7-.3 .61 .61 0 0 1 .4 .7v1l.2 .2h-1l.2-.2v-1.2a.27 .27 0 0 0-.3-.3 .27 .27 0 0 0-.2 .3v1.2l.2 .2h-1l.2-.2v-1.2a.23 .23 0 0 0-.2-.2 .23 .23 0 0 0-.2 .1l-.1 .1v1l.2 .4h-1l.2-.4v-1.3z" fill-rule="evenodd"/>
<path d="M38.3 218h.8v.3a.73 .73 0 0 1 .9-.2 .73 .73 0 0 1 .4 .9 .77 .77 0 0 1-.4 .9 .77 .77 0 0 1-.9-.1v.9l.3 .1h-1.1l.2-.2v-2.1h.6v1a.31 .31 0 0 0 .3 .3 .31 .31 0 0 0 .3-.2v-1.1a.31 .31 0 0 0-.3-.3 .31 .31 0 0 0-.3 .3h-.6v-.3z" fill-rule="evenodd"/>
<path d="M41.1 218.1a.97 .97 0 0 1 1.4 .9 .97 .97 0 0 1-1.4 .8l-.4-.6h.6v.4a.26 .26 0 0 0 .3 .3 .26 .26 0 0 0 .3-.3v-1.3a.28 .28 0 0 0-.4-.2 .28 .28 0 0 0-.2 .4v.7h-.6l.1-.6z" fill-rule="evenodd"/>
<path d="M42.8 218h.8v.3a.59 .59 0 0 1 .8-.3 .59 .59 0 0 1 .3 .8v.9l.2 .2h-1l.2-.2v-1.2a.21 .21 0 0 0-.2-.3 .21 .21 0 0 0-.2 .2l-.1 1.3 .2 .2h-1l.2-.4v-1.3z" fill-rule="evenodd"/>
<path d="M45.4 218.3a.77 .77 0 0 1 .9-.2 .77 .77 0 0 1 .5 .8h-1.1a.54 .54 0 0 0 .3 .7 .54 .54 0 0 0 .7-.2 .79 .79 0 0 1-1 .6 .79 .79 0 0 1-.5-1v-.3l1.1 .1-.2-.6a.37 .37 0 0 0-.4 .1 .37 .37 0 0 0 0 .4h-.5z" fill-rule="evenodd"/>
<path d="M47 218h.8v.3a.59 .59 0 0 1 .8-.3 .59 .59 0 0 1 .3 .8v.9l.2 .2h-1l.2-.2v-1.2a.21 .21 0 0 0-.2-.3 .21 .21 0 0 0-.2 .2l-.1 1.1 .2 .4h-1l.2-.4v-1.3z" fill-rule="evenodd"/>
<path d="M50 217.3l.1 .7h.4v.2h-.4v1.4l.2 .1 .2-.2a.51 .51 0 0 1-.7 .4 .51 .51 0 0 1-.3-.6v-1.1h-.2z" fill-rule="evenodd"/>
<path d="M50.9 218.2a.69 .69 0 0 1 .8-.1l.2-.1 .1 .6a.63 .63 0 0 0-.8-.4v.2a1.17 1.17 0 0 1 .8 1.1 .76 .76 0 0 1-1.1 .4l-.1 .1v-.7a.69 .69 0 0 0 .8 .5v-.3a1.08 1.08 0 0 1-.8-1.1z" fill-rule="evenodd"/>
<path d="M33.3 238.5l.3-.2a.75 .75 0 0 1 1.1 .6h-.3a.45 .45 0 0 0-.5-.4 .45 .45 0 0 0-.4 .5h.1a1.21 1.21 0 0 1 1.1 .7 .81 .81 0 0 1-.8 .7 .81 .81 0 0 1-.8-.7h.2a.56 .56 0 0 0 .6 .4 .56 .56 0 0 0 .5-.4l-.2-.2a1.04 1.04 0 0 1-1-.6z" fill-rule="evenodd"/>
<path d="M33 226.1h1.6v.3h-.6v1.7h-.4v-1.7h-.6z" fill-rule="evenodd"/>
<path d="M33 232.2h1.6v.2h-.6v1.8h-.3v-1.8h-.7z" fill-rule="evenodd"/>
<path d="M34.6 226.6h.4l.4 1.1 .3-1.1h.4l-.5 1.5a.65 .65 0 0 1-.9 .6v-.3h.3l.2-.3z" fill-rule="evenodd"/>
<path d="M34.9 232.2h.3v.8h1.1v-.8h.2v2h-.2v-.9h-1.1v.9h-.3z" fill-rule="evenodd"/>
<path d="M36.3 226.6h.3v.2a.64 .64 0 0 1 .9-.1 .64 .64 0 0 1 .2 .8 .59 .59 0 0 1-.4 .6 .59 .59 0 0 1-.6-.2v.8h-.4v-1.4h.4a.38 .38 0 0 0 .4 .5 .38 .38 0 0 0 .2-.6 .33 .33 0 0 0-.4-.3 .33 .33 0 0 0-.2 .4h-.4z" fill-rule="evenodd"/>
<path d="M36.8 232.2h1.7v.2h-.7v1.8h-.3v-1.8h-.7z" fill-rule="evenodd"/>
<path d="M37.5 238.3h.7a1.03 1.03 0 0 1 1 1 1.03 1.03 0 0 1-1 1.1h-.7v-.3h.7a.79 .79 0 0 0 .7-.8 .79 .79 0 0 0-.7-.8h-.5v1.6h-.2z" fill-rule="evenodd"/>
<path d="M38.1 226.8a.71 .71 0 0 1 .9-.1 .71 .71 0 0 1 .3 .8h-1a.3 .3 0 0 0 .2 .3 .3 .3 0 0 0 .4-.2l.4 .1a.72 .72 0 0 1-.9 .4 .72 .72 0 0 1-.5-.9h1a.3 .3 0 0 0-.3-.3 .3 .3 0 0 0-.3 .3h-.4z" fill-rule="evenodd"/>
<path d="M45.5 238.3h1v.3h-.8l-.1 .5a.68 .68 0 0 1 .9 .3 .68 .68 0 0 1-.4 1 .68 .68 0 0 1-.9-.6h.3a.46 .46 0 0 0 .6 .3 .46 .46 0 0 0 .2-.7 .46 .46 0 0 0-.6-.1l-.2 .1h-.2z" fill-rule="evenodd"/>
<path d="M45.3 226.1h1.4v.3h-1v.5h.9v.3h-.9v.9h-.4z" fill-rule="evenodd"/>
<path d="M45.5 232.3a.65 .65 0 0 1 .9 .1 .65 .65 0 0 1-.2 1l-.6 .6h1v.2h-1.4a2 2 0 0 1 1-1.2 .39 .39 0 0 0-.2-.6 .39 .39 0 0 0-.5 .4h-.2z" fill-rule="evenodd"/>
<path d="M47.1 226.6h.3v.2l.3-.2 .3 .1-.1 .3-.3-.1-.1 .2-.1 1h-.3z" fill-rule="evenodd"/>
<path d="M47.1 238.4a.55 .55 0 0 1 .8 0 .55 .55 0 0 1-.1 .8 .64 .64 0 0 1 0 1.2 .64 .64 0 0 1-1-.6h.3a.42 .42 0 0 0 .6 .3 .42 .42 0 0 0 .1-.7 .42 .42 0 0 0-.7 .2v.2h-.3l.1-.4 .3-.2-.2-.1-.1-.3h.3a.33 .33 0 0 0 .4 .3 .33 .33 0 0 0 .1-.5 .33 .33 0 0 0-.5 .1l-.3 .1z" fill-rule="evenodd"/>
<path d="M48.4 226.8a.78 .78 0 0 1 1.2 .2 .78 .78 0 0 1-.5 1.1 .78 .78 0 0 1-1-.7h.4a.41 .41 0 0 0 .5 .4 .41 .41 0 0 0 .2-.7 .36 .36 0 0 0-.5-.2 .36 .36 0 0 0-.2 .5h-.4z" fill-rule="evenodd"/>
<path d="M49.9 226.6h.4v.2a.53 .53 0 0 1 .6-.2 .53 .53 0 0 1 .4 .6v.9h-.4v-1a.28 .28 0 0 0-.3-.2 .28 .28 0 0 0-.3 .3v.9h-.4z" fill-rule="evenodd"/>
<path d="M51.7 226.3l.4-.2v.5h.3v.3h-.3v.9h.3l-.1 .3a.43 .43 0 0 1-.5 0 .43 .43 0 0 1-.1-.5v-.7h-.2z" fill-rule="evenodd"/>
<path d="M53.5 226.2a.84 .84 0 0 1 1.4 .4l-.4 .1a.33 .33 0 0 0-.3-.4 .33 .33 0 0 0-.4 .4h.1a1.07 1.07 0 0 1 1.1 .7 .83 .83 0 0 1-.8 .8 .83 .83 0 0 1-.9-.7l.4-.1a.38 .38 0 0 0 .4 .4 .38 .38 0 0 0 .4-.4 1.01 1.01 0 0 1-1.1-.8z" fill-rule="evenodd"/>
<path d="M55.3 226.1h.4v.3h-.4z" fill-rule="evenodd"/>
<path d="M55.3 226.6h.4v1.5h-.4z" fill-rule="evenodd"/>
<path d="M56.2 226.8a.58 .58 0 0 1 .9 0v-.7h.4v2h-.4v-.2a.62 .62 0 0 1-.8 .2 .62 .62 0 0 1-.3-.8h.4a.35 .35 0 0 0 .3 .5 .35 .35 0 0 0 .4-.4 .35 .35 0 0 0-.3-.5 .35 .35 0 0 0-.4 .4h-.4z" fill-rule="evenodd"/>
<path d="M57.9 226.8a.71 .71 0 0 1 .9-.1 .71 .71 0 0 1 .3 .8h-1a.3 .3 0 0 0 .3 .3 .3 .3 0 0 0 .3-.2l.4 .1a.72 .72 0 0 1-.9 .4 .72 .72 0 0 1-.4-.9h.9a.3 .3 0 0 0-.3-.3 .3 .3 0 0 0-.2 .3h-.4z" fill-rule="evenodd"/>
<path d="M65.4 238.4a.72 .72 0 0 1 .8 .1 .72 .72 0 0 1 .2 .8 .72 .72 0 0 1-.2 .9 .72 .72 0 0 1-.9 0l-.2-.9h.2a.57 .57 0 0 0 .5 .9 1.21 1.21 0 0 0 0-1.7 .44 .44 0 0 0-.5 .6v.2h-.2l.1-.5z" fill-rule="evenodd"/>
<path d="M65.4 232.3a.66 .66 0 0 1 .7 0 .66 .66 0 0 1 .3 .6 .9 .9 0 0 1-.8 1.4 .87 .87 0 0 1-.5-1.1h.2a.57 .57 0 0 0 .5 .8 1.21 1.21 0 0 0 0-1.6 .44 .44 0 0 0-.5 .6v.2h-.2l.1-.6z" fill-rule="evenodd"/>
<path d="M65.2 226.1h.8a.54 .54 0 0 1 .7 .2 .54 .54 0 0 1-.2 .7 .56 .56 0 0 1 .4 .7 .56 .56 0 0 1-.7 .4h-1v-.3h1a.27 .27 0 0 0 .3-.3 .27 .27 0 0 0-.3-.3h-.6v.6h-.4v-.9h1a.23 .23 0 0 0 .2-.3 .23 .23 0 0 0-.2-.2h-.6v.5h-.4z" fill-rule="evenodd"/>
<path d="M67.3 226.8l.4-.2a.54 .54 0 0 1 .7 .6l.1 .9h-.4v-.2a.52 .52 0 0 1-.6 .3 .52 .52 0 0 1-.4-.5h.4l.2 .2a.34 .34 0 0 0 .3-.5l-.5 .3h-.4a.62 .62 0 0 1 .8-.5l.1-.1a.26 .26 0 0 0-.2-.2 .26 .26 0 0 0-.3 .2l-.3-.1z" fill-rule="evenodd"/>
<path d="M68.9 226.8a.72 .72 0 0 1 1.2 .2l-.4 .1v-.1a.37 .37 0 0 0-.5 0 .37 .37 0 0 0-.1 .5 .3 .3 0 0 0 .3 .3 .3 .3 0 0 0 .3-.3l.4 .1a.76 .76 0 0 1-1.1 .4 .76 .76 0 0 1-.1-1.2z" fill-rule="evenodd"/>
<path d="M70.4 226.1h.4v1l.4-.5h.5l-.5 .6 .6 .9h-.5l-.3-.7-.2 .2v.5h-.4z" fill-rule="evenodd"/>
<path d="M72.9 226.2a.84 .84 0 0 1 1.4 .4l-.4 .1a.33 .33 0 0 0-.4-.4 .33 .33 0 0 0-.3 .4h.1a1.07 1.07 0 0 1 1 .7 .83 .83 0 0 1-.8 .8 .83 .83 0 0 1-.8-.7l.4-.1a.38 .38 0 0 0 .4 .4 .38 .38 0 0 0 .3-.4 1.01 1.01 0 0 1-1-.8z" fill-rule="evenodd"/>
<path d="M74.7 226.1h.4v.3h-.4z" fill-rule="evenodd"/>
<path d="M74.7 226.6h.4v1.5h-.4z" fill-rule="evenodd"/>
<path d="M75.6 226.8a.58 .58 0 0 1 .8 0v-.7h.4v2h-.3v-.2a.62 .62 0 0 1-.8 .2 .62 .62 0 0 1-.3-.8h.4a.35 .35 0 0 0 .3 .5 .35 .35 0 0 0 .3-.4 .35 .35 0 0 0-.3-.5 .35 .35 0 0 0-.3 .4h-.4z" fill-rule="evenodd"/>
<path d="M77.3 226.8a.71 .71 0 0 1 .9-.1 .71 .71 0 0 1 .3 .8h-1a.3 .3 0 0 0 .2 .3 .3 .3 0 0 0 .4-.2l.4 .1a.72 .72 0 0 1-.9 .4 .72 .72 0 0 1-.5-.9h1a.3 .3 0 0 0-.3-.3 .3 .3 0 0 0-.3 .3h-.4z" fill-rule="evenodd"/>
<path d="M84.7 238.3h1v.3h-.8l-.1 .5a.68 .68 0 0 1 .9 .3 .68 .68 0 0 1-.4 1 .68 .68 0 0 1-.9-.6h.3a.46 .46 0 0 0 .6 .3 .46 .46 0 0 0 .2-.7 .46 .46 0 0 0-.6-.1l-.2 .1h-.2z" fill-rule="evenodd"/>
<path d="M84.4 226.1h1.6v.3h-.6v1.7h-.4v-1.7h-.6z" fill-rule="evenodd"/>
<path d="M84.7 232.3a.65 .65 0 0 1 .9 .1 .65 .65 0 0 1-.2 1l-.6 .6h1v.2h-1.4a1.99 1.99 0 0 1 1-1.2 .39 .39 0 0 0-.2-.6 .39 .39 0 0 0-.5 .4h-.2z" fill-rule="evenodd"/>
<path d="M86.3 238.4a.55 .55 0 0 1 .8 0 .55 .55 0 0 1-.1 .8 .64 .64 0 0 1 0 1.2 .64 .64 0 0 1-1-.6h.3a.42 .42 0 0 0 .6 .3 .42 .42 0 0 0 .1-.7 .42 .42 0 0 0-.7 .2v.2h-.3l.1-.4 .3-.2-.2-.1-.1-.3h.3a.33 .33 0 0 0 .4 .3 .33 .33 0 0 0 .1-.5 .33 .33 0 0 0-.5 .1l-.3 .1z" fill-rule="evenodd"/>
<path d="M86.3 226.8a.78 .78 0 0 1 1.2 .2 .78 .78 0 0 1-.4 1.1 .78 .78 0 0 1-1-.7h.4a.41 .41 0 0 0 .5 .4 .41 .41 0 0 0 .1-.7 .36 .36 0 0 0-.4-.2 .36 .36 0 0 0-.2 .5h-.4z" fill-rule="evenodd"/>
<path d="M87.8 226.3l.4-.2v.5h.3v.3h-.3v.9h.3l-.1 .3a.43 .43 0 0 1-.5 0 .43 .43 0 0 1-.1-.5v-.7h-.2z" fill-rule="evenodd"/>
<path d="M88.8 226.8l.4-.2a.54 .54 0 0 1 .8 .6v.9h-.3l-.1-.2a.52 .52 0 0 1-.6 .3 .52 .52 0 0 1-.3-.5h.3l.2 .2a.34 .34 0 0 0 .4-.5l-.6 .3h-.3a.62 .62 0 0 1 .7-.5l.2-.1a.26 .26 0 0 0-.3-.2 .26 .26 0 0 0-.3 .2l-.3-.1z" fill-rule="evenodd"/>
<path d="M33 244.4h1.6v.3h-.6v1.8h-.3v-1.8h-.7z" fill-rule="evenodd"/>
<path d="M35.1 238.3h.4l.6 1.8 .6-1.8h.3v2.1h-.2v-1.8l-.6 1.8h-.3l-.6-1.8v1.8h-.2z" fill-rule="evenodd"/>
<path d="M34.9 245.1a.73 .73 0 0 1 1 .2 .73 .73 0 0 1-.2 1 .73 .73 0 0 1-1-.2l-.1-.4h.3a.47 .47 0 0 0 .5 .6 .47 .47 0 0 0 .4-.7 .44 .44 0 0 0-.6-.4 .44 .44 0 0 0-.3 .5h-.3z" fill-rule="evenodd"/>
<path d="M36.2 244.6l.3-.1v.5h.2v.2h-.2v.8v.2h.2v.3a.37 .37 0 0 1-.4-.1 .37 .37 0 0 1-.1-.4v-.8h-.2v-.2h.2z" fill-rule="evenodd"/>
<path d="M37.1 245.1a.67 .67 0 0 1 .8-.1 .67 .67 0 0 1 .3 .9v.6h-.2l-.1-.2a.58 .58 0 0 1-.6 .2 .58 .58 0 0 1-.4-.4h.2a.42 .42 0 0 0 .6 .2 .42 .42 0 0 0 .2-.6l-1 .4a.67 .67 0 0 1 .8-.5 .23 .23 0 0 0 .2-.3 .23 .23 0 0 0-.4-.1h-.2l-.1 .2h-.3z" fill-rule="evenodd"/>
<path d="M45.5 244.6a.6 .6 0 0 1 .6-.2 .6 .6 0 0 1 .4 .5h-.2a.42 .42 0 0 0-.5-.2 .42 .42 0 0 0-.3 .5v.2a.65 .65 0 0 1 .9 .1 .65 .65 0 0 1-.1 .9 .65 .65 0 0 1-.9-.2l-.1-.4h.2a.43 .43 0 0 0 .6 .4 .43 .43 0 0 0 .2-.7 .43 .43 0 0 0-.7 .1l-.1 .2h-.2a1.43 1.43 0 0 1 .2-1.2z" fill-rule="evenodd"/>
<path d="M47.1 244.5a.72 .72 0 0 1 .9 .1 .72 .72 0 0 1 .2 .9 .72 .72 0 0 1-.3 .8 .72 .72 0 0 1-.9 0l-.2-.8h.3a.57 .57 0 0 0 .5 .8 1.21 1.21 0 0 0 0-1.7 .44 .44 0 0 0-.5 .6v.3h-.3l.1-.6z" fill-rule="evenodd"/>
<path d="M65.4 244.5a.66 .66 0 0 1 .7 0 .66 .66 0 0 1 .3 .7 .9 .9 0 0 1-.8 1.3 .87 .87 0 0 1-.5-1h.2a.57 .57 0 0 0 .5 .8 1.2 1.2 0 0 0 0-1.7 .44 .44 0 0 0-.5 .6v.3h-.2l.1-.6z" fill-rule="evenodd"/>
<path d="M84.7 244.6a.6 .6 0 0 1 .6-.2 .6 .6 0 0 1 .4 .5h-.2a.42 .42 0 0 0-.6-.2 .42 .42 0 0 0-.2 .5v.2a.65 .65 0 0 1 .9 .1 .65 .65 0 0 1-.1 .9 .65 .65 0 0 1-.9-.2l-.2-.4h.3a.43 .43 0 0 0 .6 .4 .43 .43 0 0 0 .2-.7 .43 .43 0 0 0-.7 .1l-.1 .2h-.3a1.43 1.43 0 0 1 .3-1.2z" fill-rule="evenodd"/>
<path d="M86.3 244.5a.72 .72 0 0 1 .9 .1 .72 .72 0 0 1 .2 .9 .72 .72 0 0 1-.3 .8 .72 .72 0 0 1-.9 0l-.2-.8h.3a.57 .57 0 0 0 .5 .8 1.21 1.21 0 0 0 0-1.7 .44 .44 0 0 0-.5 .6v.3h-.3l.1-.6z" fill-rule="evenodd"/>
</g>
<path d="M38.7 244.4v2.1" fill="none" stroke="#000" stroke-width=".25"/>
<path d="M90.5 226.1v2" fill="none" stroke="#000" stroke-width=".39"/>
<path d="M30.1 230.3h63.7" fill="none" stroke="#000" stroke-width=".2"/>
<path d="M177.6 120.2l5.2 10.5M182.8 120.2l-5.2 10.5M193.5 124.5l2.1 1.4M195.6 124.5l-2.1 1.4M223.7 143.7l1 1.8M224.7 143.7l-1 1.8" fill="none" stroke="#d63034" stroke-width=".18"/>
<g fill="none" stroke="#000" stroke-width=".18">
<path d="M10 10h400v277h-400zM12 12h396v273h-396zM35.3 11.6h.8M35.3 10.7l.4-.4v1.3M60 10v2M85.3 10.4l.5-.1 .3 .4-.8 .9h.8M110 10v2M135.3 10.3h.8l-.4 .5 .3 .1v.6l-.2 .1-.5-.1M160 10v2M185.7 10.2l-.4 1h.9M186 10.7v.9M210 10v2"/>
<path d="M236 10.3h-.6l-.1 .6 .2-.1 .5 .1 .1 .1-.1 .5-.2 .1-.5-.1M260 10v2M286 10.3l-.4 .1a.87 .87 0 0 0 0 1.2l.4-.1 .1-.5-.3-.2-.3 .1-.2 .1M310 10v2M335.3 10.3h.9l-.6 1.3M360 10v2M385.6 10.9l-.3 .2 .1 .4 .2 .1 .4-.1 .1-.2-.1-.3-.2-.1M385.6 10.9l-.3-.3 .3-.3h.2l.3 .2-.3 .4M385.6 10.9h.2M10.6 35.6l.4-1.3 .4 1.3M10.7 35.2h.6M408.6 35.6l.4-1.3 .4 1.3"/>
<path d="M408.7 35.2h.6M10 60h2M408 60h2M10.7 84.3h.4l.2 .2-.2 .4 .2 .1 .1 .3-.2 .3h-.5zM10.7 84.9h.4M408.6 84.3h.5l.2 .2-.2 .4 .2 .1 .1 .3-.3 .3h-.5zM408.6 84.9h.5M10 110h2M408 110h2M11.4 134.4a.62 .62 0 0 0-.9 .5 .62 .62 0 0 0 .7 .7l.2-.1M409.4 134.4a.62 .62 0 0 0-.9 .5 .62 .62 0 0 0 .6 .7l.3-.1M10 160h2"/>
<path d="M408 160h2M10.7 184.3a.66 .66 0 0 1 .7 .6 .66 .66 0 0 1-.7 .7zM408.6 184.3a.66 .66 0 0 1 .8 .6 .66 .66 0 0 1-.8 .7zM10 210h2M408 210h2M10.7 234.9h.5M11.3 234.3h-.6v1.3h.6M408.7 234.9h.4M409.3 234.3h-.6v1.3h.6M10 260h2M408 260h2M10.8 284.9h.4"/>
<path d="M11.4 284.3h-.6v1.3M35.3 285.7l.4-.4v1.3M35.3 286.6h.8M60 285v2M85.3 285.4l.5-.1 .3 .4-.8 .9h.8M110 285v2M135.3 285.3h.8l-.4 .5 .3 .1v.6l-.2 .1-.5-.1M160 285v2M185.7 285.2l-.4 1h.9M186 285.7v.9M210 285v2M236 285.3h-.6l-.1 .6 .2-.1 .5 .1 .1 .1-.1 .5-.2 .1-.5-.1"/>
<path d="M260 285v2M286 285.3l-.4 .1a.87 .87 0 0 0 0 1.2l.4-.1 .1-.5-.3-.2-.3 .1-.2 .1M310 285v2M335.3 285.3h.9l-.6 1.3M360 285v2M385.6 285.9l-.3-.3 .3-.3h.2l.3 .2-.3 .4M385.6 285.9l-.3 .2v.2l.3 .3 .4-.1 .1-.2v-.2l-.3-.2M385.6 285.9h.2M408.7 284.9h.5M409.4 284.3h-.7v1.3"/>
</g>
<path d="M384.8 279.8a.67 .67 0 0 1 1 .1 .67 .67 0 0 1-.2 1l-.6 .7h.7l.3-.2-.2 .6h-1.3l.4-.5a.94 .94 0 0 0 .3-1.4h-.3l-.4 .2z" fill-rule="evenodd" fill="#00007f"/>
<g fill="#00f">
<path d="M384.3 275.7l.3-.1h.4l.2 .4-.1 .1a.32 .32 0 0 0-.4-.4 .32 .32 0 0 0-.3 .5h.1a.57 .57 0 0 1 .8 .6 .64 .64 0 0 1-.7 .3 .64 .64 0 0 1-.5-.5h.2a.39 .39 0 0 0 .4 .4 .39 .39 0 0 0 .4-.4l-.3-.1a.49 .49 0 0 1-.5-.2 .49 .49 0 0 1 0-.6z" fill-rule="evenodd"/>
<path d="M385.5 275.6h.2v.6l.3-.2 .4 .2v.9h-.2v-.7a.27 .27 0 0 0-.3-.2 .27 .27 0 0 0-.2 .3v.6h-.2z" fill-rule="evenodd"/>
<path d="M386.8 276.2a.51 .51 0 0 1 .6-.1 .51 .51 0 0 1 .2 .5h-.8l.3 .4 .5-.2a.52 .52 0 0 1-.6 .3 .52 .52 0 0 1-.3-.6h.8l-.2-.3a.31 .31 0 0 0-.5 .3h-.1z" fill-rule="evenodd"/>
<path d="M388 276.2a.51 .51 0 0 1 .6-.1 .51 .51 0 0 1 .2 .5h-.8l.2 .4 .6-.2a.52 .52 0 0 1-.6 .3 .52 .52 0 0 1-.4-.6h.8l-.2-.3a.31 .31 0 0 0-.4 .3h-.2z" fill-rule="evenodd"/>
<path d="M389.1 275.8l.2-.1v.3h.1v.2h-.1v.6l.2 .3a.27 .27 0 0 1-.3 0 .27 .27 0 0 1-.1-.3v-.6h-.2z" fill-rule="evenodd"/>
<path d="M389.7 276h.2v.2h-.2z" fill-rule="evenodd"/>
<path d="M389.7 276.9h.2v.2h-.2z" fill-rule="evenodd"/>
<path d="M392.7 281.1a.54 .54 0 0 1 .8 .1 .54 .54 0 0 1-.2 .8 .54 .54 0 0 1-.7-.3v-.1h.2a.36 .36 0 0 0 .4 .4 .36 .36 0 0 0 .2-.6l-.4-.2-.2 .4h-.2z" fill-rule="evenodd"/>
<path d="M393.9 280.7l.4-.1v.2a.19 .19 0 0 0-.2 0 .19 .19 0 0 0-.1 .2h.2v.2h-.2v.9h-.2v-.9h-.1v-.2h.1z" fill-rule="evenodd"/>
</g>
<path d="M396.3 279.9a.55 .55 0 0 1 .9-.2 .55 .55 0 0 1-.1 .9 .81 .81 0 0 1 .2 1.2 .81 .81 0 0 1-1.3 0l.3-.2a.54 .54 0 0 0 .8 .2 .71 .71 0 0 0-.6-1 .41 .41 0 0 0 .5-.3 .41 .41 0 0 0-.3-.5 .41 .41 0 0 0-.5 .3z" fill-rule="evenodd" fill="#00007f"/>
<g fill="#00f">
<path d="M368.3 275.7l.3-.1h.4l.2 .4-.1 .1a.32 .32 0 0 0-.4-.4 .32 .32 0 0 0-.3 .5h.1a.57 .57 0 0 1 .8 .6 .64 .64 0 0 1-.7 .3 .64 .64 0 0 1-.5-.5h.2a.39 .39 0 0 0 .4 .4 .39 .39 0 0 0 .4-.4l-.3-.1a.49 .49 0 0 1-.5-.2 .49 .49 0 0 1 0-.6z" fill-rule="evenodd"/>
<path d="M369.5 275.6h.2v.2h-.2z" fill-rule="evenodd"/>
<path d="M369.5 276h.2v1.1h-.2z" fill-rule="evenodd"/>
<path d="M369.9 276h.9l-.7 1h.8v.1h-1l.7-.9h-.7z" fill-rule="evenodd"/>
<path d="M371.1 276.2a.51 .51 0 0 1 .6-.1 .51 .51 0 0 1 .3 .5h-.8l.2 .4 .6-.2a.52 .52 0 0 1-.7 .3 .52 .52 0 0 1-.3-.6h.8l-.2-.3a.31 .31 0 0 0-.4 .3h-.2z" fill-rule="evenodd"/>
<path d="M372.3 276h.2v.2h-.2z" fill-rule="evenodd"/>
<path d="M372.3 276.9h.2v.2h-.2z" fill-rule="evenodd"/>
</g>
<g fill="#00007f">
<path d="M370.3 279.7l.9 2.1 .3 .2h-1.1l.2-.1-.1-.5h-.9l-.1 .5 .3 .1h-.8l.6-.8h.8l-.3-.7-.4 .7h-.1z" fill-rule="evenodd"/>
<path d="M371.9 279.9a.55 .55 0 0 1 .8-.2 .55 .55 0 0 1 0 .9 .81 .81 0 0 1 .1 1.2 .81 .81 0 0 1-1.2 0l.2-.2a.54 .54 0 0 0 .8 .2 .72 .72 0 0 0-.6-1 .41 .41 0 0 0 .5-.3 .41 .41 0 0 0-.3-.5 .41 .41 0 0 0-.5 .3z" fill-rule="evenodd"/>
</g>
<path d="M366.5 274.5h41.5M382.5 274.5v10.5M408 264h-41.5v21" fill="none" stroke="#000" stroke-width=".18"/>
<g fill="#00f">
<path d="M384.2 265.1h.6a.42 .42 0 0 1 .6 .4 .42 .42 0 0 1-.5 .4l.6 .7h-.3l-.4-.6h-.2h-.2v.6h-.2v-.8h.6a.26 .26 0 0 0 .4-.2 .26 .26 0 0 0-.4-.3h-.4v.5h-.2z" fill-rule="evenodd"/>
<path d="M385.7 265.7a.51 .51 0 0 1 .6-.1 .51 .51 0 0 1 .3 .5h-.8l.2 .4 .6-.2a.52 .52 0 0 1-.7 .3 .52 .52 0 0 1-.3-.6h.8l-.2-.3a.31 .31 0 0 0-.4 .3h-.2z" fill-rule="evenodd"/>
<path d="M386.7 265.5h.2l.3 .9 .3-.9h.2l-.4 1.1h-.2z" fill-rule="evenodd"/>
<path d="M387.9 265.1h.2v.2h-.2z" fill-rule="evenodd"/>
<path d="M387.9 265.5h.2v1.1h-.2z" fill-rule="evenodd"/>
<path d="M388.4 265.6l.2-.1a.39 .39 0 0 1 .5 .3h-.2a.21 .21 0 0 0-.2-.2 .21 .21 0 0 0-.1 .3 .43 .43 0 0 1 .4 .1 .43 .43 0 0 1 .1 .4l-.2 .2h-.4l-.2-.3h.1a.24 .24 0 0 0 .3 .3 .24 .24 0 0 0 .2-.4 .43 .43 0 0 1-.6-.5z" fill-rule="evenodd"/>
<path d="M389.4 265.1h.2v.2h-.2z" fill-rule="evenodd"/>
<path d="M389.4 265.5h.2v1.1h-.2z" fill-rule="evenodd"/>
<path d="M390 265.6a.54 .54 0 0 1 .8 .1 .54 .54 0 0 1-.3 .8 .54 .54 0 0 1-.7-.3v-.1h.2a.36 .36 0 0 0 .4 .4 .36 .36 0 0 0 .2-.6l-.4-.2-.2 .4h-.2z" fill-rule="evenodd"/>
<path d="M391 265.5h.2v.2l.2-.2a.37 .37 0 0 1 .4 .1 .37 .37 0 0 1 .1 .4v.6h-.2v-.6a.27 .27 0 0 0-.3-.3 .27 .27 0 0 0-.2 .3v.6h-.2z" fill-rule="evenodd"/>
<path d="M392.2 265.5h.2v.2h-.2z" fill-rule="evenodd"/>
<path d="M392.2 266.4h.2v.2h-.2z" fill-rule="evenodd"/>
</g>
<g fill="#00007f">
<path d="M384 270.4h.5l.1-.5v.5l.5 .1h-.5l-.1 .5v-.5z" fill-rule="evenodd"/>
<path d="M386.1 269.8l.3-.1a1.42 1.42 0 0 0 0 1.9l-.3-.2a1.12 1.12 0 0 1 0-1.6z" fill-rule="evenodd"/>
<path d="M386.4 269.7h.6l-.2 .2v.7a.41 .41 0 0 0 .4 .5 .41 .41 0 0 0 .4-.6v-.7l-.2-.1h.5l-.2 .2v.6a.55 .55 0 0 1-.6 .7 .55 .55 0 0 1-.5-.7v-.7z" fill-rule="evenodd"/>
<path d="M387.9 270.3l.4-.1v.2a.29 .29 0 0 1 .3-.2 .29 .29 0 0 1 .2 .3v.5l.2 .1h-.5l.2-.2-.1-.5-.1-.1-.2 .1v.6l.1 .1h-.4l.1-.1v-.6z" fill-rule="evenodd"/>
<path d="M389 270.3l.3-.1v.2l.2-.2h.2l-.4 .3v.5l.2 .1h-.5l.1-.1v-.6z" fill-rule="evenodd"/>
<path d="M389.9 270.3l.4-.1 .2 .2v.1h-.6l.2 .4 .3 .1 .1-.2a.41 .41 0 0 1-.6 .3 .41 .41 0 0 1-.1-.6h.5l-.2-.3-.3 .3z" fill-rule="evenodd"/>
<path d="M390.7 269.8l.3-.1v1.3l.1 .1h-.4l.1-.1v-.9v-.3z" fill-rule="evenodd"/>
<path d="M391.4 270.3l.4-.1 .2 .2 .1 .1h-.7l.2 .4 .3 .1 .1-.2a.41 .41 0 0 1-.5 .3 .41 .41 0 0 1-.2-.6h.5l-.2-.3-.3 .3z" fill-rule="evenodd"/>
<path d="M392.3 270.2l.5 .1 .1 .7 .1-.1-.1 .2h-.1l-.1-.1-.2 .1h-.2l-.1-.2 .3 .1 .2-.1v-.3l-.5 .3 .5-.4-.2-.3-.2 .3z" fill-rule="evenodd"/>
<path d="M393.2 270.2h.5v.3l-.2-.3a.15 .15 0 0 0-.2 .1 .15 .15 0 0 0 0 .2h.1a.34 .34 0 0 1 .4 .5 .34 .34 0 0 1-.6 .1v-.3l.2 .3 .2-.2-.4-.4z" fill-rule="evenodd"/>
<path d="M394.1 270.3l.4-.1 .2 .2v.1h-.6l.1 .4 .3 .1 .2-.2a.41 .41 0 0 1-.6 .3 .41 .41 0 0 1-.1-.6h.5l-.2-.3-.3 .3z" fill-rule="evenodd"/>
<path d="M395.4 269.8l.3-.1v1.3h.2l-.6 .2-.4-.2v-.4h.2l.1 .4 .3-.1-.1-.7-.3 .1v.3h-.2a.42 .42 0 0 1 .6-.4v-.4z" fill-rule="evenodd"/>
<path d="M395.9 269.7a1.08 1.08 0 0 1 0 1.9 1.42 1.42 0 0 0 0-1.9z" fill-rule="evenodd"/>
</g>
<path d="M382.5 264v10.5" fill="none" stroke="#000" stroke-width=".18"/>
<g fill="#00f">
<path d="M368.2 265.1h.5a.75 .75 0 0 1 .7 .8 .75 .75 0 0 1-.7 .7h-.5v-.2h.5a.58 .58 0 0 0 .5-.5 .58 .58 0 0 0-.5-.6h-.3v1.1h-.2z" fill-rule="evenodd"/>
<path d="M369.7 265.6l.2-.1a.47 .47 0 0 1 .5 .1 .47 .47 0 0 1 .1 .6l.1 .4h-.2v-.1l-.5 .1-.3-.1v-.2l.6 .2 .1-.4-.7 .2a.57 .57 0 0 1 .7-.4 .28 .28 0 0 0-.2-.2 .28 .28 0 0 0-.3 .2l-.2-.1z" fill-rule="evenodd"/>
<path d="M370.9 265.3l.1-.1v.3h.2v.2h-.2v.6l.2 .3a.27 .27 0 0 1-.3 0 .27 .27 0 0 1 0-.3v-.6h-.2z" fill-rule="evenodd"/>
<path d="M371.5 265.7a.51 .51 0 0 1 .6-.1 .51 .51 0 0 1 .2 .5h-.8l.3 .4 .5-.2a.52 .52 0 0 1-.6 .3 .52 .52 0 0 1-.4-.6h.9l-.2-.3a.31 .31 0 0 0-.5 .3h-.2z" fill-rule="evenodd"/>
<path d="M372.6 265.5h.2v.2h-.2z" fill-rule="evenodd"/>
<path d="M372.6 266.4h.2v.2h-.2z" fill-rule="evenodd"/>
</g>
<path d="M408 253.5h-41.5v10.5" fill="none" stroke="#000" stroke-width=".18"/>
<g fill="#00f">
<path d="M368.2 254.6h.5a.46 .46 0 0 1 .6 .5 .46 .46 0 0 1-.6 .4h-.3v.6h-.2v-.8h.5a.28 .28 0 0 0 .4-.2 .28 .28 0 0 0-.4-.3h-.3v.5h-.2z" fill-rule="evenodd"/>
<path d="M369.5 255h.2v.2l.2-.2h.2v.2a.24 .24 0 0 0-.3 .1 .24 .24 0 0 0-.1 .3v.5h-.2z" fill-rule="evenodd"/>
<path d="M370.3 255.1a.55 .55 0 0 1 .9 .1 .55 .55 0 0 1-.3 .8 .55 .55 0 0 1-.7-.4h.2a.36 .36 0 0 0 .4 .4 .36 .36 0 0 0 .2-.6l-.4-.2-.2 .4h-.2z" fill-rule="evenodd"/>
<path d="M371.4 254.6h.2v.2h-.2z" fill-rule="evenodd"/>
<path d="M371.4 255h.2v1.2a.3 .3 0 0 1-.1 .3 .3 .3 0 0 1-.3 0l.2-.2z" fill-rule="evenodd"/>
<path d="M371.9 255.2a.51 .51 0 0 1 .7-.1 .51 .51 0 0 1 .2 .5h-.8l.2 .4 .6-.2a.52 .52 0 0 1-.6 .3 .52 .52 0 0 1-.4-.6h.8l-.2-.3a.31 .31 0 0 0-.4 .3h-.2z" fill-rule="evenodd"/>
<path d="M373.1 255.1h.6l.2 .3h-.2a.34 .34 0 0 0-.5-.2 .34 .34 0 0 0 0 .6l.3 .2 .2-.3h.2a.53 .53 0 0 1-.8 .3 .53 .53 0 0 1 0-.8z" fill-rule="evenodd"/>
<path d="M374.1 254.8l.2-.1v.3h.2v.2h-.2v.6l.2 .3a.27 .27 0 0 1-.3 0 .27 .27 0 0 1-.1-.3v-.6h-.1z" fill-rule="evenodd"/>
<path d="M375.3 254.6h.2l.8 1.2v-1.2h.2v1.5h-.2l-.8-1.2v1.2h-.2z" fill-rule="evenodd"/>
<path d="M376.9 255.1l.1-.1a.47 .47 0 0 1 .6 .1 .47 .47 0 0 1 0 .6l.1 .4h-.2v-.1l-.5 .1-.3-.1v-.2l.4 .2h.2l.2-.4-.8 .2a.57 .57 0 0 1 .8-.4 .28 .28 0 0 0-.3-.2 .28 .28 0 0 0-.3 .2l-.2-.1z" fill-rule="evenodd"/>
<path d="M377.9 255h.2v.2l.3-.2 .3 .2 .3-.2 .3 .1 .1 .2v.8h-.2v-.7a.24 .24 0 0 0-.2-.2 .24 .24 0 0 0-.2 .3v.6h-.2v-.7a.25 .25 0 0 0-.3-.2 .25 .25 0 0 0-.2 .4v.5h-.2z" fill-rule="evenodd"/>
<path d="M379.8 255.2a.51 .51 0 0 1 .6-.1 .51 .51 0 0 1 .2 .5h-.8l.3 .4 .5-.2a.52 .52 0 0 1-.6 .3 .52 .52 0 0 1-.4-.6h.8l-.1-.3a.31 .31 0 0 0-.5 .3h-.2z" fill-rule="evenodd"/>
<path d="M380.9 255h.2v.2h-.2z" fill-rule="evenodd"/>
<path d="M380.9 255.9h.2v.2h-.2z" fill-rule="evenodd"/>
</g>
<g fill="#00007f">
<path d="M368.2 269.8a.42 .42 0 0 1 .6 .1 .42 .42 0 0 1-.1 .6l-.4 .5 .7-.1-.1 .2h-.9a1.05 1.05 0 0 0 .7-1.1l-.3-.1-.3 .2z" fill-rule="evenodd"/>
<path d="M369.3 269.8a.47 .47 0 0 1 .6 0 .47 .47 0 0 1 .1 .6 .48 .48 0 0 1-.1 .6 .48 .48 0 0 1-.6 0l-.2-.5h.2a.36 .36 0 0 0 0 .4 .36 .36 0 0 0 .4 .1l.1-.6-.1-.6a.24 .24 0 0 0-.3 0 .24 .24 0 0 0 0 .3l-.1 .4h-.2z" fill-rule="evenodd"/>
<path d="M370.3 269.8a.42 .42 0 0 1 .6 .1 .42 .42 0 0 1-.1 .6l-.4 .5 .7-.1-.1 .2h-.9a1.06 1.06 0 0 0 .7-1.1l-.3-.1-.3 .2z" fill-rule="evenodd"/>
<path d="M371.6 269.7h.5l-.1 .2h-.4l-.1 .2a.5 .5 0 0 1 .5 .6 .5 .5 0 0 1-.7 .3 .4 .4 0 0 0 .6-.2 .4 .4 0 0 0-.5-.5h-.1z" fill-rule="evenodd"/>
<path d="M372.3 270.6h.5v.1h-.5z" fill-rule="evenodd"/>
<path d="M373.2 269.8a.47 .47 0 0 1 .6 0 .47 .47 0 0 1 .1 .6 .48 .48 0 0 1-.2 .6 .48 .48 0 0 1-.6 0l-.1-.5h.2a.36 .36 0 0 0-.1 .4 .36 .36 0 0 0 .4 .1l.2-.6-.2-.6a.24 .24 0 0 0-.2 0 .24 .24 0 0 0-.1 .3v.4h-.2z" fill-rule="evenodd"/>
<path d="M374.2 269.7h.7l-.5 1.4h-.1l.4-1.2h-.5l-.1 .2z" fill-rule="evenodd"/>
<path d="M375.1 270.6h.5v.1h-.5z" fill-rule="evenodd"/>
<path d="M375.9 269.9l.4-.2v1.3l.2 .1h-.5l.1-.1v-1z" fill-rule="evenodd"/>
<path d="M377 269.8h.4a.31 .31 0 0 1 0 .5 .44 .44 0 0 1 .1 .7 .44 .44 0 0 1-.6 0 .34 .34 0 0 0 .5 0 .34 .34 0 0 0-.1-.5l-.2-.1a.28 .28 0 0 0 .3-.2 .28 .28 0 0 0-.2-.3 .28 .28 0 0 0-.3 .1z" fill-rule="evenodd"/>
</g>
<g fill="#00f">
<path d="M341.2 275.6h.6a.42 .42 0 0 1 .6 .4 .42 .42 0 0 1-.5 .4l.6 .7h-.3a.74 .74 0 0 0-.8-.6v.6h-.2v-.8h.6a.26 .26 0 0 0 .4-.2 .26 .26 0 0 0-.4-.3h-.4v.5h-.2z" fill-rule="evenodd"/>
<path d="M342.7 276.2a.51 .51 0 0 1 .6-.1 .51 .51 0 0 1 .3 .5h-.8l.2 .4 .6-.2a.52 .52 0 0 1-.7 .3 .52 .52 0 0 1-.3-.6h.8l-.2-.3a.31 .31 0 0 0-.4 .3h-.2z" fill-rule="evenodd"/>
<path d="M343.7 276h.2l.3 .9 .3-.9h.2l-.4 1.1h-.2z" fill-rule="evenodd"/>
<path d="M344.9 275.6h.2v.2h-.2z" fill-rule="evenodd"/>
<path d="M344.9 276h.2v1.1h-.2z" fill-rule="evenodd"/>
<path d="M345.4 276.2a.51 .51 0 0 1 .6-.1 .51 .51 0 0 1 .3 .5h-.8l.2 .4 .6-.2a.52 .52 0 0 1-.7 .3 .52 .52 0 0 1-.3-.6h.8l-.2-.3a.31 .31 0 0 0-.4 .3h-.2z" fill-rule="evenodd"/>
<path d="M346.4 276h.2l.2 .9 .2-.9h.2l.2 .9 .3-.9h.2l-.4 1.1h-.2l-.2-.8-.2 .8h-.2z" fill-rule="evenodd"/>
<path d="M348.1 276.2a.51 .51 0 0 1 .6-.1 .51 .51 0 0 1 .3 .5h-.9l.3 .4 .6-.2a.52 .52 0 0 1-.7 .3 .52 .52 0 0 1-.3-.6h.8l-.2-.3a.31 .31 0 0 0-.4 .3h-.2z" fill-rule="evenodd"/>
<path d="M349.2 276h.1v.2l.2-.2h.2v.2a.24 .24 0 0 0-.3 .1 .24 .24 0 0 0 0 .3v.5h-.2z" fill-rule="evenodd"/>
<path d="M349.9 276h.2v.2h-.2z" fill-rule="evenodd"/>
<path d="M349.9 276.9h.2v.2h-.2z" fill-rule="evenodd"/>
</g>
<path d="M332 274.5h34.5M339.5 274.5v10.5" fill="none" stroke="#000" stroke-width=".18"/>
<g fill="#00f">
<path d="M341.2 265.1h.5a.75 .75 0 0 1 .7 .8 .75 .75 0 0 1-.7 .7h-.5v-.2h.5a.58 .58 0 0 0 .5-.5 .58 .58 0 0 0-.5-.6h-.3v1.1h-.2z" fill-rule="evenodd"/>
<path d="M342.7 265.7a.51 .51 0 0 1 .6-.1 .51 .51 0 0 1 .3 .5h-.8l.2 .4 .6-.2a.52 .52 0 0 1-.7 .3 .52 .52 0 0 1-.3-.6h.8l-.2-.3a.31 .31 0 0 0-.4 .3h-.2z" fill-rule="evenodd"/>
<path d="M343.8 265.6l.3-.1a.39 .39 0 0 1 .5 .3h-.2a.21 .21 0 0 0-.2-.2 .21 .21 0 0 0-.2 .3 .43 .43 0 0 1 .5 .1 .43 .43 0 0 1 .1 .4l-.2 .2h-.4l-.3-.3h.2a.24 .24 0 0 0 .3 .3 .24 .24 0 0 0 .2-.4 .43 .43 0 0 1-.6-.5z" fill-rule="evenodd"/>
<path d="M344.9 265.1h.2v.2h-.2z" fill-rule="evenodd"/>
<path d="M344.9 265.5h.2v1.1h-.2z" fill-rule="evenodd"/>
<path d="M345.4 265.6a.43 .43 0 0 1 .7 .1v-.2h.1v1a.48 .48 0 0 1-.3 .5 .48 .48 0 0 1-.6-.3l.4 .2a.3 .3 0 0 0 .3-.4 .46 .46 0 0 1-.5 .1 .46 .46 0 0 1-.2-.5h.2a.34 .34 0 0 0 .4 .3 .34 .34 0 0 0 .1-.5 .3 .3 0 0 0-.3-.2 .3 .3 0 0 0-.2 .4h-.2z" fill-rule="evenodd"/>
<path d="M346.5 265.5h.2v.2l.1-.2a.37 .37 0 0 1 .5 .1 .37 .37 0 0 1 .1 .4v.6h-.2v-.6a.27 .27 0 0 0-.3-.3 .27 .27 0 0 0-.2 .3v.6h-.2z" fill-rule="evenodd"/>
<path d="M347.7 265.7a.51 .51 0 0 1 .7-.1 .51 .51 0 0 1 .2 .5h-.8l.2 .4 .6-.2a.52 .52 0 0 1-.6 .3 .52 .52 0 0 1-.4-.6h.8l-.2-.3a.31 .31 0 0 0-.4 .3h-.2z" fill-rule="evenodd"/>
<path d="M348.8 265.5h.2v.2l.2-.2h.2v.2a.24 .24 0 0 0-.3 .1 .24 .24 0 0 0-.1 .3v.5h-.2z" fill-rule="evenodd"/>
<path d="M349.6 265.5h.2v.2h-.2z" fill-rule="evenodd"/>
<path d="M349.6 266.4h.2v.2h-.2z" fill-rule="evenodd"/>
</g>
<path d="M332 264h34.5M339.5 264v10.5" fill="none" stroke="#000" stroke-width=".18"/>
<g fill="#00007f">
<path d="M341 269.7h.6a.7 .7 0 0 1 .8 .7 .7 .7 0 0 1-.7 .7h-.7l.2-.1v-1.2h.2v1.2a.65 .65 0 0 0 .8-.7 .65 .65 0 0 0-1-.5z" fill-rule="evenodd"/>
<path d="M342.7 270.2l.5 .1 .1 .7 .1-.1-.1 .2-.2-.1-.3 .1-.2-.1v-.1l.3 .1 .2-.1v-.3l-.5 .3 .5-.4-.2-.3-.3 .3z" fill-rule="evenodd"/>
<path d="M343.5 270.3l.3-.1v.2a.29 .29 0 0 1 .3-.2 .29 .29 0 0 1 .2 .3v.5l.2 .1h-.5l.2-.2v-.5l-.2-.1-.2 .1v.6l.1 .1h-.4l.1-.1v-.6z" fill-rule="evenodd"/>
<path d="M344.6 270.3l.3-.1v.8l.1 .1h-.4l.1-.1v-.5v-.2z" fill-rule="evenodd"/>
<path d="M345.3 270.3l.4-.1 .2 .2 .1 .1h-.7l.2 .4 .3 .1 .1-.2a.41 .41 0 0 1-.5 .3 .41 .41 0 0 1-.2-.6h.5l-.2-.3-.3 .3z" fill-rule="evenodd"/>
<path d="M346.1 269.8l.3-.1v1.3l.2 .1h-.5l.1-.1v-1.1z" fill-rule="evenodd"/>
<path d="M347.2 269.7h.5l-.1 .1-.1 .6 .6-.5-.1-.2h.5l-.8 .7 1 .7h-.7l.1-.1-.6-.6 .1 .6 .1 .1h-.5l.2-.2-.1-1z" fill-rule="evenodd"/>
<path d="M348.8 270.2l.6 .1v.7l.2-.1-.2 .2-.2-.1-.3 .1-.2-.1v-.1l.3 .1 .2-.1v-.3l-.5 .3 .5-.4-.1-.3-.3 .3z" fill-rule="evenodd"/>
<path d="M349.6 270.3l.3-.1v.2l.4-.2a.29 .29 0 0 0 .5 0l.2 .1 .1 .7 .1 .1h-.5l.2-.1v-.5a.2 .2 0 0 0-.2-.2 .2 .2 0 0 0-.2 .2v.5l.1 .1h-.4l.1-.1v-.5l-.1-.2-.3 .1v.6l.2 .1h-.5l.1-.1v-.5v-.2z" fill-rule="evenodd"/>
<path d="M351.2 270.3l.3-.1v.2a.39 .39 0 0 1 .6-.1 .39 .39 0 0 1 0 .5l-.2 .3h-.4v.4l.2 .1h-.5l.2-.2v-1h.1l.1 .6a.33 .33 0 0 0 .4-.3 .33 .33 0 0 0-.4-.3h-.2z" fill-rule="evenodd"/>
<path d="M352.4 270.3l.4-.1 .3 .2v.1h-.6l.1 .4 .3 .1 .2-.2a.41 .41 0 0 1-.6 .3 .41 .41 0 0 1-.1-.6h.5l-.2-.3-.3 .3z" fill-rule="evenodd"/>
<path d="M353.2 270.3l.3-.1v.2l.2-.2h.2l-.4 .3v.5l.2 .1h-.5l.1-.1 .1-.5-.1-.2z" fill-rule="evenodd"/>
<path d="M354.2 269.9v.3h.2h-.2v.7h.3l-.3 .2-.1-.1-.1-.8h-.1z" fill-rule="evenodd"/>
<circle cx="344.8" cy="269.8" r=".1"/>
</g>
<path d="M332 264h-34.5v10.5h34.5" fill="none" stroke="#000" stroke-width=".18"/>
<g fill="#00007f">
<path d="M299.2 269.7h1l-.9 1.3h.7l.2-.3v.4h-1.2l.9-1.3h-.6l-.2 .3z" fill-rule="evenodd"/>
<path d="M300.5 269.8l.7-.1v.5a.29 .29 0 0 0-.3-.4 .29 .29 0 0 0-.2 .4h.1a.51 .51 0 0 1 .4 .3 .51 .51 0 0 1 0 .5l-.8 .2 .1-.5a.33 .33 0 0 0 .3 .4 .33 .33 0 0 0 .3-.4l-.1-.1a.51 .51 0 0 1-.5-.2 .51 .51 0 0 1 0-.6z" fill-rule="evenodd"/>
<path d="M301.5 269.7h.5l-.1 .2 .3 .9 .2-.7-.3-.4h.6l-.2 .2 .3 .9 .3-.9-.1-.2h.4l-.2 .2-.4 1.3-.3-.9-.4 .9-.5-1.4z" fill-rule="evenodd"/>
<path d="M303.5 270.2l.5 .1v.7l.2-.1-.1 .2h-.2v-.1l-.3 .1-.2-.1-.1-.1 .4 .1 .2-.1v-.3l-.6 .3 .6-.4-.2-.3-.3 .3z" fill-rule="evenodd"/>
<path d="M304.5 269.9v.3h.3h-.3v.7h.3l-.3 .2-.1-.1v-.8h-.2z" fill-rule="evenodd"/>
<path d="M305 270.3l.4-.1 .2 .1-.1 .2a.28 .28 0 0 0-.4-.3 .28 .28 0 0 0-.1 .5 .3 .3 0 0 0 .3 .3 .3 .3 0 0 0 .3-.2 .43 .43 0 0 1-.6 .3 .43 .43 0 0 1-.1-.7z" fill-rule="evenodd"/>
<path d="M305.7 269.8l.3-.1v.7l.3-.2h.2l.1 .8 .1 .1h-.4l.1-.2v-.5l-.1-.1-.3 .1 .1 .6 .1 .1h-.5l.2-.1v-.9v-.3z" fill-rule="evenodd"/>
<path d="M306.8 270.6h.6v.1h-.6z" fill-rule="evenodd"/>
<path d="M307.5 269.7h.6a.7 .7 0 0 1 .8 .7 .7 .7 0 0 1-.8 .7h-.6l.2-.1v-1.2h.2v1.2a.65 .65 0 0 0 .7-.7 .65 .65 0 0 0-.9-.5z" fill-rule="evenodd"/>
<path d="M309.2 270.3a.46 .46 0 0 1 .7 .1 .46 .46 0 0 1-.3 .7 .46 .46 0 0 1-.6-.5h.2a.31 .31 0 0 0 .1 .4 .31 .31 0 0 0 .4-.1 .38 .38 0 0 0 0-.5 .38 .38 0 0 0-.4-.1l-.1 .3h-.2z" fill-rule="evenodd"/>
<path d="M310.2 270.3l.4-.1 .2 .1v.2a.28 .28 0 0 0-.4-.3 .28 .28 0 0 0-.1 .5 .3 .3 0 0 0 .2 .3 .3 .3 0 0 0 .4-.2 .43 .43 0 0 1-.7 .3 .43 .43 0 0 1 0-.7z" fill-rule="evenodd"/>
<path d="M311 269.8l.3-.1v.9l.3-.3v-.1h.4l-.5 .3 .5 .6h-.4v-.1l-.3-.4v.4l.1 .1h-.4l.1-.2v-1z" fill-rule="evenodd"/>
<path d="M312.5 269.8l.4-.1v.9l.3-.3-.1-.1h.4l-.5 .3 .6 .6h-.5l.1-.1-.3-.4v.4l.1 .1h-.5l.2-.2v-1z" fill-rule="evenodd"/>
<path d="M313.6 270.3l.4-.1v.8l.1 .1h-.4l.1-.1v-.5v-.2z" fill-rule="evenodd"/>
<path d="M314.4 270.3l.4-.1 .2 .1-.1 .2a.28 .28 0 0 0-.4-.3 .28 .28 0 0 0-.1 .5 .3 .3 0 0 0 .3 .3 .3 .3 0 0 0 .3-.2 .43 .43 0 0 1-.6 .3 .43 .43 0 0 1-.1-.7z" fill-rule="evenodd"/>
<path d="M315.3 270.2l.5 .1 .1 .7 .1-.1-.1 .2h-.1l-.1-.1-.3 .1-.2-.1v-.1l.3 .1 .2-.1v-.3l-.5 .3 .5-.4-.2-.3-.3 .3z" fill-rule="evenodd"/>
<path d="M316.6 269.8l.3-.1v1.3h.2l-.6 .2-.3-.2-.1-.4h.2l.2 .4 .3-.1-.2-.7-.2 .1-.1 .3h-.2a.42 .42 0 0 1 .7-.4l-.1-.4z" fill-rule="evenodd"/>
<path d="M317.1 271.5l1 .1z" fill-rule="evenodd"/>
<path d="M318.1 270.3l.3-.1v.2a.39 .39 0 0 1 .6-.1 .39 .39 0 0 1 .1 .5l-.3 .3h-.4l.1 .4 .1 .1h-.5l.2-.2v-1h.1l.1 .6a.33 .33 0 0 0 .4-.3 .33 .33 0 0 0-.4-.3h-.2z" fill-rule="evenodd"/>
<path d="M319.4 270.3l.4-.1 .2 .1-.1 .2a.28 .28 0 0 0-.4-.3 .28 .28 0 0 0-.1 .5 .3 .3 0 0 0 .3 .3 .3 .3 0 0 0 .3-.2 .43 .43 0 0 1-.6 .3 .43 .43 0 0 1-.1-.7z" fill-rule="evenodd"/>
<path d="M320.1 269.8l.3-.1v.6a.43 .43 0 0 1 .7 .1 .43 .43 0 0 1-.3 .7l-.2 .1-.3-.2v-.6h.1v.6a.32 .32 0 0 0 .5-.3 .32 .32 0 0 0-.5-.3h-.1v-.5z" fill-rule="evenodd"/>
<circle cx="312.3" cy="271" r=".11"/>
<circle cx="313.9" cy="269.8" r=".1"/>
</g>
<path d="M366.5 253.5h-69v10.5" fill="none" stroke="#000" stroke-width=".18"/>
<g fill="#00f">
<path d="M299.2 254.6l.8 .1 .2 .4a.25 .25 0 0 0-.1 .2 .25 .25 0 0 0 .2 .2 .45 .45 0 0 1-.1 .5 .45 .45 0 0 1-.5 .1h-.5v-.2h.7l.2-.1-.1-.3-.6-.1v.5h-.2v-.7h.5a.24 .24 0 0 0 .3-.1 .24 .24 0 0 0-.2-.3h-.4v.4h-.2z" fill-rule="evenodd"/>
<path d="M300.6 255.1a.55 .55 0 0 1 .9 .1 .55 .55 0 0 1-.3 .8 .55 .55 0 0 1-.7-.4h.2a.36 .36 0 0 0 .4 .4 .36 .36 0 0 0 .2-.6l-.4-.2-.2 .4h-.2z" fill-rule="evenodd"/>
<path d="M301.8 255.2l.1-.2a.47 .47 0 0 1 .6 .1 .47 .47 0 0 1 .1 .6v.4h-.1l-.1-.1-.5 .1-.2-.1-.1-.2 .4 .2h.2l.2-.4-.8 .2a.57 .57 0 0 1 .8-.4 .28 .28 0 0 0-.2-.2 .28 .28 0 0 0-.3 .2l-.2-.1z" fill-rule="evenodd"/>
<path d="M302.9 255h.1v.2l.2-.2h.2v.2a.25 .25 0 0 0-.3 .1 .25 .25 0 0 0 0 .3v.5h-.2z" fill-rule="evenodd"/>
<path d="M303.7 255.1l.3-.1 .3 .2v-.6h.1v1.5h-.1v-.1a.45 .45 0 0 1-.6 .1 .45 .45 0 0 1-.2-.5h.2a.34 .34 0 0 0 .4 .4 .34 .34 0 0 0 .2-.6l-.4-.2-.2 .4h-.2z" fill-rule="evenodd"/>
<path d="M305.3 254.6h.2l.8 1.2v-1.2h.2v1.5h-.2l-.8-1.2v1.2h-.2z" fill-rule="evenodd"/>
<path d="M306.9 255.2l.1-.2a.47 .47 0 0 1 .6 .1 .47 .47 0 0 1 .1 .6l.1 .4h-.2l-.1-.1-.4 .1-.3-.1v-.2l.3 .2h.3l.1-.4-.7 .2a.57 .57 0 0 1 .7-.4 .28 .28 0 0 0-.2-.2 .28 .28 0 0 0-.3 .2l-.2-.1z" fill-rule="evenodd"/>
<path d="M308 255h.2v.2l.2-.2 .4 .2 .3-.2 .2 .1 .2 .2v.8h-.2v-.7a.24 .24 0 0 0-.3-.2 .24 .24 0 0 0-.2 .3v.6h-.2v-.7a.25 .25 0 0 0-.3-.2 .25 .25 0 0 0-.1 .4v.5h-.2z" fill-rule="evenodd"/>
<path d="M309.8 255.2a.51 .51 0 0 1 .6-.1 .51 .51 0 0 1 .3 .5h-.8l.2 .4 .6-.2a.52 .52 0 0 1-.7 .3 .52 .52 0 0 1-.3-.6h.8l-.2-.3a.31 .31 0 0 0-.4 .3h-.2z" fill-rule="evenodd"/>
<path d="M311 255h.2v.2h-.2z" fill-rule="evenodd"/>
<path d="M311 255.9h.2v.2h-.2z" fill-rule="evenodd"/>
<path d="M368 244.1h.2l.5 1.4 .5-1.4h.2l-.6 1.5h-.2z" fill-rule="evenodd"/>
<path d="M369.6 244.6l.1-.1a.47 .47 0 0 1 .5 .1 .47 .47 0 0 1 .1 .6l.1 .4h-.2v-.1l-.5 .1-.3-.1v-.2l.6 .2 .2-.4-.8 .2a.57 .57 0 0 1 .8-.4 .28 .28 0 0 0-.3-.2 .28 .28 0 0 0-.3 .2l-.2-.1z" fill-rule="evenodd"/>
<path d="M370.5 244.5h.2v.2l.2-.2h.2v.2a.25 .25 0 0 0-.3 .1 .25 .25 0 0 0-.1 .3v.5h-.2z" fill-rule="evenodd"/>
<path d="M371.2 244.1h.2v.2h-.2z" fill-rule="evenodd"/>
<path d="M371.2 244.5h.2v1.1h-.2z" fill-rule="evenodd"/>
<path d="M371.8 244.6l.1-.1a.47 .47 0 0 1 .6 .1 .47 .47 0 0 1 .1 .6l.1 .4h-.2l-.1-.1-.5 .1-.2-.1v-.2l.3 .2h.3l.1-.4-.7 .2a.57 .57 0 0 1 .7-.4 .28 .28 0 0 0-.2-.2 .28 .28 0 0 0-.3 .2l-.2-.1z" fill-rule="evenodd"/>
<path d="M372.9 244.5h.1v.2l.2-.2a.37 .37 0 0 1 .4 .1 .37 .37 0 0 1 .2 .4v.6h-.2v-.6a.27 .27 0 0 0-.3-.3 .27 .27 0 0 0-.2 .3v.6h-.2z" fill-rule="evenodd"/>
<path d="M374.1 244.3l.2-.1v.3h.2v.2h-.2v.6l.2 .3a.27 .27 0 0 1-.3 0 .27 .27 0 0 1-.1-.3v-.6h-.2z" fill-rule="evenodd"/>
<path d="M374.7 244.5h.2v.2h-.2z" fill-rule="evenodd"/>
<path d="M374.7 245.4h.2v.2h-.2z" fill-rule="evenodd"/>
</g>
<path d="M408 243h-41.5v10.5" fill="none" stroke="#000" stroke-width=".18"/>
<g fill="#00007f">
<path d="M368.3 248.9l.4-.2 .4 .1 .2-.1v.5a.53 .53 0 0 0-.7-.4 .53 .53 0 0 0-.3 .8 .54 .54 0 0 0 .4 .5 .54 .54 0 0 0 .6-.3 .69 .69 0 0 1-1 .2 .69 .69 0 0 1 0-1.1z" fill-rule="evenodd"/>
<path d="M369.4 248.7h.6l-.2 .1v.6h.7v-.6l-.2-.1h.6l-.2 .3v1l.2 .1h-.6l.2-.1v-.5h-.7v.5l.2 .1h-.6l.2-.2v-1z" fill-rule="evenodd"/>
<path d="M371 248.7h1v.3l-.1-.2h-.5v.6l.4-.1 .1-.1v.4l-.1-.1-.4-.1v.6a.51 .51 0 0 0 .7-.2l-.1 .3h-1l.2-.2v-1z" fill-rule="evenodd"/>
<path d="M372.5 248.9l.4-.2 .4 .1 .2-.1v.5a.53 .53 0 0 0-.7-.4 .53 .53 0 0 0-.3 .8 .54 .54 0 0 0 .4 .5 .54 .54 0 0 0 .6-.3 .69 .69 0 0 1-1 .2 .69 .69 0 0 1 0-1.1z" fill-rule="evenodd"/>
<path d="M373.6 248.7h.6l-.2 .1v.6l.5-.5-.1-.2h.5l-.7 .7 .9 .7h-.6l.1-.1-.6-.6v.6l.2 .1h-.6l.2-.2v-1z" fill-rule="evenodd"/>
<path d="M375.2 248.7h1v.3l-.1-.2h-.6v.6l.5-.1 .1-.1v.4l-.1-.1-.5-.1 .1 .6a.51 .51 0 0 0 .7-.2l-.1 .3h-1l.2-.2-.1-1z" fill-rule="evenodd"/>
<path d="M376.4 248.7h.6a.7 .7 0 0 1 .8 .7 .7 .7 0 0 1-.7 .7h-.7l.2-.1v-1.2h.2v1.2a.65 .65 0 0 0 .8-.7 .65 .65 0 0 0-1-.5z" fill-rule="evenodd"/>
</g>
<path d="M366.5 243h-69v10.5" fill="none" stroke="#000" stroke-width=".18"/>
<g fill="#00f">
<path d="M299.3 244.3l.4-.2h.3l.4 .3v.1l-.2 .1a.53 .53 0 0 0-.8-.2 .53 .53 0 0 0 0 .8l.4 .3 .3-.1 .1-.3h.2a.72 .72 0 0 1-1 .4 .72 .72 0 0 1-.2-1.1z" fill-rule="evenodd"/>
<path d="M300.8 244.6a.54 .54 0 0 1 .8 .1 .54 .54 0 0 1-.3 .8 .54 .54 0 0 1-.7-.3v-.1h.2a.36 .36 0 0 0 .4 .4 .36 .36 0 0 0 .2-.6l-.4-.2-.2 .4h-.2z" fill-rule="evenodd"/>
<path d="M301.8 244.5h.2v.2l.4-.2 .2 .2 .3-.2 .3 .1 .1 .2v.8h-.2v-.7a.24 .24 0 0 0-.3-.2 .24 .24 0 0 0-.1 .3v.6h-.2v-.7a.25 .25 0 0 0-.4-.2 .25 .25 0 0 0-.1 .4v.5h-.2z" fill-rule="evenodd"/>
<path d="M303.6 244.5h.1v.2a.5 .5 0 0 1 .8 .4 .5 .5 0 0 1-.7 .4v.5h-.2v-.9h.1a.33 .33 0 0 0 .4 .4 .33 .33 0 0 0 .2-.5l-.1-.3h-.2l-.3 .4h-.1z" fill-rule="evenodd"/>
<path d="M304.8 244.6l.1-.1a.47 .47 0 0 1 .6 .1 .47 .47 0 0 1 .1 .6l.1 .4h-.2l-.1-.1-.4 .1-.3-.1v-.2l.3 .2h.3l.1-.4-.7 .2a.57 .57 0 0 1 .7-.4 .28 .28 0 0 0-.2-.2 .28 .28 0 0 0-.3 .2l-.2-.1z" fill-rule="evenodd"/>
<path d="M305.9 244.5h.2v.2l.1-.2a.37 .37 0 0 1 .5 .1 .37 .37 0 0 1 .1 .4v.6h-.2v-.6a.27 .27 0 0 0-.3-.3 .27 .27 0 0 0-.2 .3v.6h-.2z" fill-rule="evenodd"/>
<path d="M307 244.5h.2l.3 .9 .3-.9h.2l-.5 1.1a.38 .38 0 0 1-.4 .4l-.1-.1 .3-.1 .1-.2z" fill-rule="evenodd"/>
<path d="M308.2 244.5h.2v.2h-.2z" fill-rule="evenodd"/>
<path d="M308.2 245.4h.2v.2h-.2z" fill-rule="evenodd"/>
</g>
<g fill="#00007f">
<path d="M299.2 248.7h1.1l-.8 1.3a.68 .68 0 0 0 .9-.4l-.1 .5h-1.3l.9-1.3a.54 .54 0 0 0-.8 .3z" fill-rule="evenodd"/>
<path d="M300.6 248.8l.8-.1v.5l-.4-.4-.3 .2 .2 .2a.5 .5 0 0 1 .6 .3 .5 .5 0 0 1-.3 .6l-.7 .1v-.6a.35 .35 0 0 0 .3 .5 .35 .35 0 0 0 .4-.3l-.2-.2a.46 .46 0 0 1-.4-.3 .46 .46 0 0 1 0-.5z" fill-rule="evenodd"/>
<path d="M301.6 248.7h.6l-.1 .2 .3 .8 .2-.5-.3-.5h.7l-.2 .1 .3 .8 .3-.7-.1-.2 .3 .1-.6 1.4-.4-.9-.4 .9z" fill-rule="evenodd"/>
<path d="M303.7 249.3l.4-.2 .3 .1v.8h.2l-.1 .1h-.3l-.1-.1-.2 .1-.2-.1v-.1h.4v-.3l-.2 .3h-.2l.4-.4v-.2h-.2a.15 .15 0 0 1 0 .2 .15 .15 0 0 1-.2 0 .15 .15 0 0 1 0-.2z" fill-rule="evenodd"/>
<path d="M305 248.8v.4h.3l-.3 .1 .1 .7 .2-.1-.2 .2a.26 .26 0 0 1-.3-.3v-.5l-.2-.1z" fill-rule="evenodd"/>
<path d="M305.5 249.3l.2-.2a.23 .23 0 0 1 .4 .1 .23 .23 0 0 1-.1 .3l-.2-.3a.37 .37 0 0 0-.1 .5 .37 .37 0 0 0 .5 .2 .47 .47 0 0 1-.8 .1 .47 .47 0 0 1 .1-.7z" fill-rule="evenodd"/>
<path d="M306.3 248.7h.4v.6l.2-.2a.29 .29 0 0 1 .3 .4l.1 .6h-.4v-.2v-.6l-.2 .1 .1 .7h-.5l.1-.2z" fill-rule="evenodd"/>
<path d="M368.7 259h1.5l-1.1 1.7a.91 .91 0 0 0 1.2-.5l-.1 .6h-1.7l1.1-1.7a.73 .73 0 0 0-.9 .4z" fill-rule="evenodd"/>
<path d="M370.7 259.1l.4-.2 .4 .2 .2-.2-.1 .7a.43 .43 0 0 0-.3-.6 .43 .43 0 0 0-.5 .3l.2 .2a.95 .95 0 0 1 .8 .9 .88 .88 0 0 1-1.2 .4l-.1 .1 .1-.7a.48 .48 0 0 0 .3 .5 .48 .48 0 0 0 .6-.3l-.2-.2a.72 .72 0 0 1-.7-1z" fill-rule="evenodd"/>
<path d="M371.9 259h.8l-.1 .2 .4 1 .3-.7-.4-.5h.9l-.2 .1 .4 1.1 .4-1-.2-.2h.5l-.2 .1-.6 1.8-.5-1.2-.6 1.2z" fill-rule="evenodd"/>
<path d="M374.8 259.7l.1-.1a.5 .5 0 0 1 .6-.1 .5 .5 0 0 1 .2 .5l.1 .6h.1a.29 .29 0 0 1-.3 .3 .29 .29 0 0 1-.2-.3 .33 .33 0 0 1-.4 .3 .33 .33 0 0 1-.3-.4h.4l.1 .1 .2-.1v-.4l-.3 .4h-.4l.7-.5-.1-.3h-.3a.2 .2 0 0 1 .1 .3 .2 .2 0 0 1-.3 0 .2 .2 0 0 1 0-.3z" fill-rule="evenodd"/>
<path d="M376.5 259.1l.1 .5h.3v.1h-.3v.9h.2a.34 .34 0 0 1-.4 .2 .34 .34 0 0 1-.2-.4v-.7l-.2-.1z" fill-rule="evenodd"/>
<path d="M377.2 259.7a.4 .4 0 0 1 .5-.2 .4 .4 0 0 1 .2 .5h-.2l-.1-.4a.52 .52 0 0 0-.2 .7 .52 .52 0 0 0 .7 .2 .62 .62 0 0 1-1 .2 .62 .62 0 0 1 0-.9z" fill-rule="evenodd"/>
<path d="M378.2 259h.6v.7a.4 .4 0 0 1 .5-.2 .4 .4 0 0 1 .2 .6v.6l.1 .1h-.6l.1-.2v-.8l-.1-.1-.2 .2v.8l.1 .1h-.7l.2-.2v-1.5z" fill-rule="evenodd"/>
<path d="M380.4 259h.9a.93 .93 0 0 1 1 .9 .93 .93 0 0 1-1 .9h-.9l.3-.1v-.2h.4l.1 .2a.57 .57 0 0 0 .6-.8 .64 .64 0 0 0-.7-.8v1.4h-.4v-1.3z" fill-rule="evenodd"/>
<path d="M382.8 259.6a.63 .63 0 0 1 .8 .2 .63 .63 0 0 1-.1 .9 .63 .63 0 0 1-.9-.1l-.1-.3h.4v.3a.18 .18 0 0 0 .2 .2 .18 .18 0 0 0 .2-.2v-.8a.19 .19 0 0 0-.3-.2 .19 .19 0 0 0-.1 .3v.4h-.4z" fill-rule="evenodd"/>
<path d="M384.1 259.7a.4 .4 0 0 1 .5-.2 .4 .4 0 0 1 .3 .5h-.2l-.2-.4a.52 .52 0 0 0-.2 .7 .52 .52 0 0 0 .7 .2 .62 .62 0 0 1-.9 .2 .62 .62 0 0 1 0-.9z" fill-rule="evenodd"/>
<path d="M385.1 259h.6v1.2l.4-.5-.1-.1h.5l-.5 .4 .6 .8h-.6l.1-.1-.3-.5-.1 .5 .1 .1h-.7l.2-.2v-1.5z" fill-rule="evenodd"/>
<path d="M299.5 258.7h1.1a1.17 1.17 0 0 1 1.3 1.2 1.17 1.17 0 0 1-1.3 1.1h-1.1l.3-.1 .1-.2h.5v.1a.53 .53 0 0 0 .7 0 .53 .53 0 0 0 .1-.6 .93 .93 0 0 0-.8-1.4v1.9h-.5v-1.7z" fill-rule="evenodd"/>
<path d="M302.5 259.5a.79 .79 0 0 1 1.1 .8 .79 .79 0 0 1-1.3 .5l-.1-.4h.5v.3a.22 .22 0 0 0 .2 .3 .22 .22 0 0 0 .2-.2v-1.1a.23 .23 0 0 0-.3-.2 .23 .23 0 0 0-.1 .3v.6h-.5v-.5z" fill-rule="evenodd"/>
<path d="M304.2 259.6a.53 .53 0 0 1 .6-.2 .53 .53 0 0 1 .3 .6 .38 .38 0 0 1-.5-.5 .42 .42 0 0 0-.2 .7 .51 .51 0 0 0 .3 .6 .51 .51 0 0 0 .5-.1 .76 .76 0 0 1-1 .2 .76 .76 0 0 1-.2-1.1z" fill-rule="evenodd"/>
<path d="M305.4 258.7h.7v1.5l.5-.5-.1-.3h.7l-.7 .6 .8 1h-.8l.1-.1-.4-.6-.1 .6 .2 .1h-.9l.2-.3v-1.8z" fill-rule="evenodd"/>
<path d="M307.4 260.1h1v.3h-1z" fill-rule="evenodd"/>
<path d="M308.5 258.7h1.2l-.3 .2v.9h.8v-.9l-.3-.2h1.2l-.3 .1v.3v1.7l.3 .2h-1.2l.3-.1v-1h-.8v1l.3 .1h-1.2l.3-.1v-.3v-1.6z" fill-rule="evenodd"/>
<path d="M311.2 258.7h1l-.2 .3 .5 1.3 .4-.9-.2-.5-.3-.2h1.1l-.2 .2 .5 1.3 .4-1.2v-.1l-.2-.2 .6 .1-.2 .1-.8 2.2-.6-1.5-.7 1.5-.9-2.2z" fill-rule="evenodd"/>
</g>
<path d="M263 274.5h34.5M297.5 264h-34.5v21" fill="none" stroke="#000" stroke-width=".18"/>
<g fill="#00f">
<path d="M299.2 265.1h1v.2h-.8v.5h.7v.1h-.7v.7h-.2z" fill-rule="evenodd"/>
<path d="M300.4 265.1h.2v.2h-.2z" fill-rule="evenodd"/>
<path d="M300.4 265.5h.2v1.1h-.2z" fill-rule="evenodd"/>
<path d="M300.9 265.1h.2v1.5h-.2z" fill-rule="evenodd"/>
<path d="M301.4 265.7a.51 .51 0 0 1 .6-.1 .51 .51 0 0 1 .3 .5h-.8l.2 .4 .6-.2a.52 .52 0 0 1-.7 .3 .52 .52 0 0 1-.3-.6h.8l-.2-.3a.31 .31 0 0 0-.4 .3h-.2z" fill-rule="evenodd"/>
<path d="M303.1 265.1h.2l.8 1.2v-1.2h.2v1.5h-.2l-.8-1.2v1.2h-.2z" fill-rule="evenodd"/>
<path d="M304.7 265.6l.1-.1a.47 .47 0 0 1 .6 .1 .47 .47 0 0 1 .1 .6l.1 .4h-.2l-.1-.1-.5 .1-.2-.1v-.2l.6 .2 .1-.4-.7 .2a.57 .57 0 0 1 .7-.4 .28 .28 0 0 0-.2-.2 .28 .28 0 0 0-.3 .2l-.2-.1z" fill-rule="evenodd"/>
<path d="M305.8 265.5h.1v.2l.5-.2 .2 .2 .2-.2 .3 .1 .2 .2v.8h-.2v-.7a.24 .24 0 0 0-.3-.2 .24 .24 0 0 0-.2 .3v.6h-.2v-.7a.25 .25 0 0 0-.3-.2 .25 .25 0 0 0-.1 .4v.5h-.2z" fill-rule="evenodd"/>
<path d="M307.6 265.7a.51 .51 0 0 1 .6-.1 .51 .51 0 0 1 .3 .5h-.8l.2 .4 .6-.2a.52 .52 0 0 1-.7 .3 .52 .52 0 0 1-.3-.6h.8l-.2-.3a.31 .31 0 0 0-.4 .3h-.2z" fill-rule="evenodd"/>
<path d="M308.8 265.5h.2v.2h-.2z" fill-rule="evenodd"/>
<path d="M308.8 266.4h.2v.2h-.2z" fill-rule="evenodd"/>
<path d="M264.8 265.2l.3-.1h.4l.2 .4-.1 .1a.32 .32 0 0 0-.4-.4 .32 .32 0 0 0-.3 .5h.1a.57 .57 0 0 1 .8 .7 .64 .64 0 0 1-.7 .2 .64 .64 0 0 1-.5-.5h.2a.39 .39 0 0 0 .4 .4 .39 .39 0 0 0 .4-.4l-.3-.1a.49 .49 0 0 1-.5-.2 .49 .49 0 0 1 0-.6z" fill-rule="evenodd"/>
<path d="M266 265.1h.2v.6l.3-.2 .4 .2v.9h-.2v-.7a.27 .27 0 0 0-.3-.2 .27 .27 0 0 0-.2 .3v.6h-.2z" fill-rule="evenodd"/>
<path d="M267.3 265.7a.51 .51 0 0 1 .6-.1 .51 .51 0 0 1 .2 .5h-.8l.3 .4 .5-.2a.52 .52 0 0 1-.6 .3 .52 .52 0 0 1-.3-.6h.8l-.2-.3a.31 .31 0 0 0-.5 .3h-.1z" fill-rule="evenodd"/>
<path d="M268.5 265.7a.51 .51 0 0 1 .6-.1 .51 .51 0 0 1 .2 .5h-.8l.2 .4 .6-.2a.52 .52 0 0 1-.6 .3 .52 .52 0 0 1-.4-.6h.8l-.2-.3a.31 .31 0 0 0-.4 .3h-.2z" fill-rule="evenodd"/>
<path d="M269.6 265.3l.2-.1v.3h.1v.2h-.1v.6l.2 .3a.27 .27 0 0 1-.3 0 .27 .27 0 0 1-.1-.3v-.6h-.2z" fill-rule="evenodd"/>
<path d="M270.6 265.1h1.2v.2h-.5v1.3h-.2v-1.3h-.5z" fill-rule="evenodd"/>
<path d="M271.9 265.1h.2v.2h-.2z" fill-rule="evenodd"/>
<path d="M271.9 265.5h.2v1.1h-.2z" fill-rule="evenodd"/>
<path d="M272.4 265.3l.2-.1v.3h.1v.2h-.1v.6l.2 .3a.27 .27 0 0 1-.3 0 .27 .27 0 0 1-.1-.3v-.6h-.2z" fill-rule="evenodd"/>
<path d="M272.9 265.1h.2v1.5h-.2z" fill-rule="evenodd"/>
<path d="M273.5 265.7a.51 .51 0 0 1 .6-.1 .51 .51 0 0 1 .2 .5h-.8l.3 .4 .5-.2a.52 .52 0 0 1-.6 .3 .52 .52 0 0 1-.4-.6h.8l-.1-.3a.31 .31 0 0 0-.5 .3h-.2z" fill-rule="evenodd"/>
<path d="M274.6 265.5h.2v.2h-.2z" fill-rule="evenodd"/>
<path d="M274.6 266.4h.2v.2h-.2z" fill-rule="evenodd"/>
<path d="M264.8 275.7l.3-.1h.4l.2 .4-.1 .1a.32 .32 0 0 0-.4-.4 .32 .32 0 0 0-.3 .5h.1a.57 .57 0 0 1 .8 .6 .64 .64 0 0 1-.7 .3 .64 .64 0 0 1-.5-.5h.2a.39 .39 0 0 0 .4 .4 .39 .39 0 0 0 .4-.4l-.3-.1a.49 .49 0 0 1-.5-.2 .49 .49 0 0 1 0-.6z" fill-rule="evenodd"/>
<path d="M266 275.6h.2v.6l.3-.2 .4 .2v.9h-.2v-.7a.27 .27 0 0 0-.3-.2 .27 .27 0 0 0-.2 .3v.6h-.2z" fill-rule="evenodd"/>
<path d="M267.3 276.2a.51 .51 0 0 1 .6-.1 .51 .51 0 0 1 .2 .5h-.8l.3 .4 .5-.2a.52 .52 0 0 1-.6 .3 .52 .52 0 0 1-.3-.6h.8l-.2-.3a.31 .31 0 0 0-.5 .3h-.1z" fill-rule="evenodd"/>
<path d="M268.5 276.2a.51 .51 0 0 1 .6-.1 .51 .51 0 0 1 .2 .5h-.8l.2 .4 .6-.2a.52 .52 0 0 1-.6 .3 .52 .52 0 0 1-.4-.6h.8l-.2-.3a.31 .31 0 0 0-.4 .3h-.2z" fill-rule="evenodd"/>
<path d="M269.6 275.8l.2-.1v.3h.1v.2h-.1v.6l.2 .3a.27 .27 0 0 1-.3 0 .27 .27 0 0 1-.1-.3v-.6h-.2z" fill-rule="evenodd"/>
<path d="M270.7 275.6h.6a.46 .46 0 0 1 .6 .5 .46 .46 0 0 1-.6 .4h-.4v.6h-.2v-.8h.6a.28 .28 0 0 0 .4-.2 .28 .28 0 0 0-.4-.3h-.4v.5h-.2z" fill-rule="evenodd"/>
<path d="M272.2 276.2l.1-.2a.47 .47 0 0 1 .6 .1 .47 .47 0 0 1 .1 .6v.4h-.1l-.1-.1-.5 .1-.2-.1-.1-.2 .4 .2h.2l.2-.4-.8 .2a.57 .57 0 0 1 .8-.4 .28 .28 0 0 0-.2-.2 .28 .28 0 0 0-.3 .2l-.2-.1z" fill-rule="evenodd"/>
<path d="M273.3 275.8l.2-.1v.3h.2v.2h-.2v.6l.2 .3a.27 .27 0 0 1-.3 0 .27 .27 0 0 1-.1-.3v-.6h-.1z" fill-rule="evenodd"/>
<path d="M273.9 275.6h.1v.6l.4-.2 .3 .1v1h-.1v-.7a.27 .27 0 0 0-.4-.2 .27 .27 0 0 0-.2 .3v.6h-.1z" fill-rule="evenodd"/>
<path d="M275.1 276h.2v.2h-.2z" fill-rule="evenodd"/>
<path d="M275.1 276.9h.2v.2h-.2z" fill-rule="evenodd"/>
</g>
<g fill="#00007f">
<path d="M264.6 269.7h1.1v.4l-.1-.2-.4-.1v1.2l.2 .1h-.6l.2-.1v-1.2h-.3l-.1 .3z" fill-rule="evenodd"/>
<path d="M265.9 270.3a.46 .46 0 0 1 .7 .1 .46 .46 0 0 1-.3 .7 .46 .46 0 0 1-.6-.5h.2a.31 .31 0 0 0 .1 .4 .31 .31 0 0 0 .4-.1 .37 .37 0 0 0 0-.5 .37 .37 0 0 0-.4-.1l-.1 .3h-.2z" fill-rule="evenodd"/>
<path d="M266.7 270.3l.3-.1v.2a.39 .39 0 0 1 .6-.1 .39 .39 0 0 1 0 .5l-.2 .3h-.4v.4l.2 .1h-.5l.1-.2v-1h.2v.6a.33 .33 0 0 0 .5-.3 .33 .33 0 0 0-.4-.3h-.3z" fill-rule="evenodd"/>
<path d="M268.9 269.7l.6 1.3 .1 .1h-.5l.1-.1-.1-.3h-.5l-.2 .3 .2 .1h-.4l.3-.5h.6l-.3-.6-.3 .6z" fill-rule="evenodd"/>
<path d="M269.8 270.2h.5v.3l-.2-.3a.15 .15 0 0 0-.2 .1 .15 .15 0 0 0 .1 .2 .34 .34 0 0 1 .4 .5 .34 .34 0 0 1-.6 .1v-.3l.2 .3 .2-.2-.4-.4z" fill-rule="evenodd"/>
<path d="M270.7 270.2h.4v.3l-.2-.3a.14 .14 0 0 0-.2 .1 .14 .14 0 0 0 .1 .2h.1a.34 .34 0 0 1 .3 .5 .34 .34 0 0 1-.6 .1v-.3l.2 .3 .3-.2-.5-.4z" fill-rule="evenodd"/>
<path d="M271.5 270.3l.4-.1 .2 .2 .1 .1h-.7l.2 .4 .3 .1 .1-.2a.41 .41 0 0 1-.5 .3 .41 .41 0 0 1-.2-.6h.5l-.2-.3-.3 .3z" fill-rule="evenodd"/>
<path d="M272.2 270.3l.4-.1v.2l.3-.2a.3 .3 0 0 0 .6 0l.2 .1v.7l.1 .1h-.4l.1-.1v-.5a.2 .2 0 0 0-.1-.2 .2 .2 0 0 0-.3 .2v.5l.2 .1h-.5l.2-.1v-.5l-.2-.2-.2 .1v.6l.1 .1h-.4l.1-.1v-.6z" fill-rule="evenodd"/>
<path d="M273.9 269.8l.3-.1v.6a.43 .43 0 0 1 .7 .1 .43 .43 0 0 1-.3 .7l-.3 .1-.3-.2v-.6h.2v.6a.32 .32 0 0 0 .5-.3 .32 .32 0 0 0-.5-.3h-.2v-.5z" fill-rule="evenodd"/>
<path d="M275 269.8l.3-.1v1.3l.1 .1h-.4l.1-.1v-.9v-.3z" fill-rule="evenodd"/>
<path d="M275.5 270.2h.4l-.1 .1 .3 .6 .2-.6-.1-.1h.3l-.5 1.2-.3 .2-.1-.2h.3l.1-.3z" fill-rule="evenodd"/>
<path d="M277.5 269.8l.2-.1a1.42 1.42 0 0 0 0 1.9l-.2-.2a1.12 1.12 0 0 1 0-1.6z" fill-rule="evenodd"/>
<path d="M278 269.8l.7-.1v.5a.29 .29 0 0 0-.3-.4 .29 .29 0 0 0-.3 .4h.1a.51 .51 0 0 1 .5 .3 .51 .51 0 0 1 0 .5l-.8 .2v-.5a.33 .33 0 0 0 .3 .4 .33 .33 0 0 0 .4-.4l-.1-.1a.51 .51 0 0 1-.5-.2 .51 .51 0 0 1 0-.6z" fill-rule="evenodd"/>
<path d="M279.1 270.3l.4-.1 .3 .1-.1 .2a.28 .28 0 0 0-.4-.3 .28 .28 0 0 0-.1 .5 .3 .3 0 0 0 .2 .3 .3 .3 0 0 0 .4-.2 .43 .43 0 0 1-.7 .3 .43 .43 0 0 1 0-.7z" fill-rule="evenodd"/>
<path d="M280.1 270.2l.5 .1v.7l.2-.1-.1 .2h-.2v-.1l-.3 .1-.2-.1-.1-.1 .4 .1 .2-.1v-.3l-.6 .3 .6-.4-.2-.3-.3 .3z" fill-rule="evenodd"/>
<path d="M280.9 269.8l.3-.1v1.3l.1 .1h-.4l.1-.1v-.9v-.3z" fill-rule="evenodd"/>
<path d="M281.6 270.3l.4-.1 .2 .2v.1h-.6l.2 .4 .3 .1 .1-.2a.41 .41 0 0 1-.6 .3 .41 .41 0 0 1-.1-.6h.5l-.2-.3-.3 .3z" fill-rule="evenodd"/>
<path d="M283.1 269.9l.3-.2 .1 1.3 .1 .1h-.5l.2-.1v-.9v-.2z" fill-rule="evenodd"/>
<path d="M284.7 269.9l.4-.2v1.3l.2 .1h-.6l.2-.1v-.9v-.2z" fill-rule="evenodd"/>
<path d="M285.6 269.7a1.08 1.08 0 0 1 0 1.9 1.42 1.42 0 0 0 0-1.9z" fill-rule="evenodd"/>
<circle cx="284.2" cy="270.3" r=".11"/>
<circle cx="284.2" cy="271" r=".11"/>
</g>
<path d="M297.5 243h-34.5v21" fill="none" stroke="#000" stroke-width=".18"/>
<g fill="#00f">
<path d="M264.8 244.3l.4-.2h.3l.4 .3v.1l-.2 .1a.53 .53 0 0 0-.8-.2 .53 .53 0 0 0 0 .8l.4 .3 .3-.1 .1-.3h.2a.72 .72 0 0 1-1 .4 .72 .72 0 0 1-.2-1.1z" fill-rule="evenodd"/>
<path d="M266.3 244.6a.54 .54 0 0 1 .8 .1 .54 .54 0 0 1-.3 .8 .54 .54 0 0 1-.7-.3v-.1h.2a.36 .36 0 0 0 .4 .4 .36 .36 0 0 0 .2-.6l-.4-.2-.2 .4h-.2z" fill-rule="evenodd"/>
<path d="M267.3 244.5h.2v.2l.4-.2 .2 .2 .3-.2 .3 .1 .1 .2v.8h-.2v-.7a.24 .24 0 0 0-.3-.2 .24 .24 0 0 0-.1 .3v.6h-.2v-.7a.25 .25 0 0 0-.4-.2 .25 .25 0 0 0-.1 .4v.5h-.2z" fill-rule="evenodd"/>
<path d="M269.1 244.5h.1v.2l.4-.2 .3 .2 .2-.2 .3 .1 .1 .2v.8h-.1v-.7a.24 .24 0 0 0-.3-.2 .24 .24 0 0 0-.2 .3v.6h-.2v-.7a.25 .25 0 0 0-.3-.2 .25 .25 0 0 0-.1 .4v.5h-.2z" fill-rule="evenodd"/>
<path d="M270.9 244.7a.51 .51 0 0 1 .6-.1 .51 .51 0 0 1 .3 .5h-.9l.3 .4 .6-.2a.52 .52 0 0 1-.7 .3 .52 .52 0 0 1-.3-.6h.8l-.2-.3a.31 .31 0 0 0-.4 .3h-.2z" fill-rule="evenodd"/>
<path d="M272 244.5h.1v.2l.2-.2a.37 .37 0 0 1 .4 .1 .37 .37 0 0 1 .2 .4v.6h-.2v-.6a.27 .27 0 0 0-.3-.3 .27 .27 0 0 0-.2 .3v.6h-.2z" fill-rule="evenodd"/>
<path d="M273.2 244.3l.2-.1v.3h.2v.2h-.2v.6l.2 .3a.27 .27 0 0 1-.3 0 .27 .27 0 0 1-.1-.3v-.6h-.2z" fill-rule="evenodd"/>
<path d="M273.8 244.6l.2-.1a.39 .39 0 0 1 .5 .3h-.2a.21 .21 0 0 0-.2-.2 .21 .21 0 0 0-.1 .3 .43 .43 0 0 1 .4 .1 .43 .43 0 0 1 .1 .4l-.2 .2h-.4l-.2-.3h.1a.24 .24 0 0 0 .3 .3 .24 .24 0 0 0 .2-.4 .43 .43 0 0 1-.6-.5z" fill-rule="evenodd"/>
<path d="M274.8 244.5h.2v.2h-.2z" fill-rule="evenodd"/>
<path d="M274.8 245.4h.2v.2h-.2z" fill-rule="evenodd"/>
</g>
<g fill="#00007f">
<path d="M264.7 248.7h1l-.9 1.3h.7l.2-.3v.4h-1.2l.9-1.3h-.6l-.1 .3z" fill-rule="evenodd"/>
<path d="M266 248.8l.7-.1v.5a.29 .29 0 0 0-.3-.4 .29 .29 0 0 0-.2 .4h.1a.51 .51 0 0 1 .4 .3 .51 .51 0 0 1 0 .5l-.8 .2 .1-.5a.33 .33 0 0 0 .3 .4 .33 .33 0 0 0 .3-.4l-.1-.1a.51 .51 0 0 1-.5-.2 .51 .51 0 0 1 0-.6z" fill-rule="evenodd"/>
<path d="M267 248.7h.5l-.1 .1 .3 1 .2-.7-.3-.4h.6l-.2 .2 .3 .9 .3-.9-.1-.2h.4l-.2 .2-.4 1.3-.3-.9-.4 .9-.5-1.4z" fill-rule="evenodd"/>
<path d="M269 249.2h.3l.2 .1v.7h.2l-.2 .1-.1-.1a.29 .29 0 0 1-.5 0l-.1-.1 .4 .1 .2-.1v-.3l-.6 .3 .6-.4-.2-.3-.3 .3z" fill-rule="evenodd"/>
<path d="M270 248.9v.3h.3h-.3v.7h.3l-.3 .2-.1-.1v-.8h-.2z" fill-rule="evenodd"/>
<path d="M270.5 249.3l.4-.1 .2 .1-.1 .2a.28 .28 0 0 0-.4-.3 .28 .28 0 0 0-.1 .5 .3 .3 0 0 0 .3 .3 .3 .3 0 0 0 .3-.2 .43 .43 0 0 1-.6 .3 .43 .43 0 0 1-.1-.7z" fill-rule="evenodd"/>
<path d="M271.2 248.8l.3-.1v.7l.3-.2h.2l.1 .8 .1 .1h-.4l.1-.2v-.5l-.1-.1-.3 .1 .1 .6 .1 .1h-.5l.2-.1v-.9v-.3z" fill-rule="evenodd"/>
</g>
<path d="M263 243h-42v42M297.5 243h69" fill="none" stroke="#000" stroke-width=".18"/>
<g fill="#000">
<path d="M17.1 17.5a5.9 5.9 0 0 1 2.7 .1 1.87 1.87 0 0 1 .9 2.2 1.87 1.87 0 0 1-2 1.4h-1.6l.4-.2 .1-.4h.9v.2a.65 .65 0 0 0 .7 .2 .65 .65 0 0 0 .4-.6 2.21 2.21 0 0 0-.5-2.7h-.6v2.9h-.9v-2.8l-.2-.2z" fill-rule="evenodd"/>
<path d="M21.7 18.8a1.31 1.31 0 0 1 2 .9 1.31 1.31 0 0 1-1.5 1.5l-.6-.4-.3-.7h.7l.1 .6a.35 .35 0 0 0 .3 .3 .35 .35 0 0 0 .4-.3v-1.7a.37 .37 0 0 0-.5-.3 .37 .37 0 0 0-.2 .5l-.1 .9h-.7v-.7z" fill-rule="evenodd"/>
<path d="M26.5 17.5h1.1v2.4l.8-.9v-.2l-.3-.2h1.2l-1.1 .9 1.3 1.7h-1.3l.1-.3-.6-.9-.1 .1v.8l.2 .3h-1.3l.2-.2 .1-.4v-2.9z" fill-rule="evenodd"/>
<path d="M29.6 19.6h1.6v.6h-1.6z" fill-rule="evenodd"/>
<path d="M31.4 17.5h2l-.5 .2-.1 1.4h1.3v-1.4l-.5-.2h2l-.5 .2-.1 .4v2.7l.2 .2 .4 .2h-2l.5-.3v-1.5h-1.3l.1 1.5 .5 .3h-2l.5-.2v-.5v-2.7l-.1-.2z" fill-rule="evenodd"/>
<path d="M35.7 17.5h1.6l-.3 .2v.2l.8 2.1 .6-1.4a1.18 1.18 0 0 0-.7-1.1h1.8l-.4 .2 .8 2.2 .7-1.9v-.3l-.4-.2h1l-.3 .3-1.3 3.4h-.1l-1-2.3-1.1 2.3-1.4-3.4z" fill-rule="evenodd"/>
<path d="M46.7 18.8a1.08 1.08 0 0 1 1.2-.1l.2-.2v.9a.84 .84 0 0 0-1-.6v.3l.5 .4a.9 .9 0 0 1 .6 1.3 .9 .9 0 0 1-1.4 .3l-.2 .1-.1-.9a.91 .91 0 0 0 1.1 .7l.1-.4-.5-.3a.94 .94 0 0 1-.5-1.5z" fill-rule="evenodd"/>
<path d="M48.9 18.8a1.08 1.08 0 0 1 1.2-.1l.2-.2v.9a.84 .84 0 0 0-1-.6v.3l.5 .4a.9 .9 0 0 1 .6 1.3 .9 .9 0 0 1-1.4 .3l-.2 .1-.1-.9a.91 .91 0 0 0 1.1 .7v-.4l-.4-.3a.94 .94 0 0 1-.5-1.5z" fill-rule="evenodd"/>
<path d="M51.2 18.9a1.03 1.03 0 0 1 1.2-.3 1.03 1.03 0 0 1 .6 1.2h-1.4a.73 .73 0 0 0 .3 .8 .73 .73 0 0 0 .8 0l.2-.2 .1 .1a1.1 1.1 0 0 1-1.3 .7 1.1 1.1 0 0 1-.8-1.3v-.4l1.4 .1v-.6l-.3-.3-.4 .3v.5h-.7z" fill-rule="evenodd"/>
<path d="M53.3 18.6h1.1v.4a.79 .79 0 0 1 .7-.5 .79 .79 0 0 1 .7 .5 .82 .82 0 0 1 1.1-.4 .82 .82 0 0 1 .5 1v1.3l.2 .3h-1.3l.3-.3v-1.7a.31 .31 0 0 0-.3-.3 .31 .31 0 0 0-.3 .2l-.1 .1v1.7l.3 .3h-1.4l.3-.4v-1.6a.3 .3 0 0 0-.2-.3 .3 .3 0 0 0-.4 .2l-.1 .1v1.4v.4l.2 .2h-1.3l.3-.2v-.4v-1.7z" fill-rule="evenodd"/>
<path d="M57.9 17.5h1.1v1.4a1.04 1.04 0 0 1 1.3-.1 1.04 1.04 0 0 1 .3 1.3 1.17 1.17 0 0 1-.6 1 1.17 1.17 0 0 1-1.3-.1l-.5 .2v-2.1h.8v1.6a.4 .4 0 0 0 .4 .4 .4 .4 0 0 0 .4-.4v-1.3a.46 .46 0 0 0-.3-.5 .46 .46 0 0 0-.5 .2h-.8v-1.4z" fill-rule="evenodd"/>
<path d="M61 17.5h1.1v3.1v.4l.3 .2h-1.4l.3-.2v-.4v-2.9z" fill-rule="evenodd"/>
<path d="M66.7 17.5a5.9 5.9 0 0 1 2.7 .1 1.87 1.87 0 0 1 1 2.2 1.87 1.87 0 0 1-2 1.4h-1.7l.5-.2v-.4h.9v.2a.65 .65 0 0 0 .7 .2 .65 .65 0 0 0 .5-.6 2.21 2.21 0 0 0-.5-2.7h-.7v2.9h-.9v-2.8l-.1-.2z" fill-rule="evenodd"/>
<path d="M71.4 18.8a1.31 1.31 0 0 1 1.9 .9 1.31 1.31 0 0 1-1.5 1.5l-.6-.4-.3-.7h.8v.6a.35 .35 0 0 0 .3 .3 .35 .35 0 0 0 .4-.3v-1.7a.37 .37 0 0 0-.4-.3 .37 .37 0 0 0-.3 .5v.9h-.8l.1-.7z" fill-rule="evenodd"/>
<path d="M76.1 18.6h1.1v2a.27 .27 0 0 0 .2 .3 .27 .27 0 0 0 .3-.2l.2-.2v-1.3l-.1-.4-.2-.2h1v2.3l.3 .3h-1v-.4a.79 .79 0 0 1-1.1 .4 .79 .79 0 0 1-.4-1v-1.3z" fill-rule="evenodd"/>
<path d="M79.3 18.6h1v.4a.79 .79 0 0 1 .8-.5 .79 .79 0 0 1 .7 .5 .82 .82 0 0 1 1-.4 .82 .82 0 0 1 .5 1v1.3l.3 .3h-1.3l.2-.3v-1.7a.31 .31 0 0 0-.2-.3 .31 .31 0 0 0-.3 .2l-.2 .1v1.7l.3 .3h-1.3l.3-.4-.1-1.6a.3 .3 0 0 0-.2-.3 .3 .3 0 0 0-.3 .2l-.2 .1v1.4l.1 .4 .2 .2h-1.3l.2-.2 .1-.4-.1-1.7z" fill-rule="evenodd"/>
<path d="M84.3 18.9a1.03 1.03 0 0 1 1.3-.3 1.03 1.03 0 0 1 .5 1.2h-1.4a.73 .73 0 0 0 .3 .8 .73 .73 0 0 0 .8 0l.2-.2 .1 .1a1.1 1.1 0 0 1-1.3 .7 1.1 1.1 0 0 1-.8-1.3v-.4l1.4 .1v-.6l-.3-.3-.3 .3-.1 .5h-.7z" fill-rule="evenodd"/>
<path d="M86.4 18.6h1.1v.4a.79 .79 0 0 1 1-.4 .79 .79 0 0 1 .4 1v1.3l.3 .3h-1.3l.2-.3v-1.7a.28 .28 0 0 0-.2-.3 .28 .28 0 0 0-.3 .2l-.1 .2v1.3v.4l.2 .2h-1.3l.2-.2 .1-.4v-1.7z" fill-rule="evenodd"/>
<path d="M90.5 17.7v.9h.6v.3h-.6l.1 1.8 .1 .2 .4-.3a.68 .68 0 0 1-.9 .6 .68 .68 0 0 1-.4-.9v-1.4h-.4v-.1z" fill-rule="evenodd"/>
<path d="M24.5 18.8a.91 .91 0 0 1 .9-.3 .91 .91 0 0 1 .7 .8 .43 .43 0 0 1-.6 .1 .43 .43 0 0 1-.1-.5l-.3-.2a1.36 1.36 0 0 0 .5 2.1l.5-.3 .1 .1a1.15 1.15 0 0 1-1.5 .5 1.15 1.15 0 0 1-.6-1.4z" fill-rule="evenodd"/>
<path d="M44.3 17.4l1.5 3.4 .4 .4h-1.8l.5-.3-.3-.8h-1.3l-.3 .8 .5 .3h-1.2l.4-.5 .4-.8h1.4l-.6-1.3-.5 1.3h-.3z" fill-rule="evenodd"/>
<path d="M62.5 18.6h1.4l-.3 .3 .6 1.4 .4-1.4-.3-.3h.9l-.3 .3-.9 2.4a1.27 1.27 0 0 1-.7 1 .41 .41 0 0 1-.7-.2 .41 .41 0 0 1 .6-.4l.1 .3 .1 .1 .4-.8-1-2.3z" fill-rule="evenodd"/>
<path d="M74.1 18.8a.91 .91 0 0 1 1-.3 .91 .91 0 0 1 .6 .8 .43 .43 0 0 1-.5 .1 .43 .43 0 0 1-.2-.5l-.3-.2a1.35 1.35 0 0 0 .5 2.1l.6-.3v.1a1.16 1.16 0 0 1-1.5 .5 1.16 1.16 0 0 1-.6-1.4z" fill-rule="evenodd"/>
<path d="M185.5 64.7h2.7v.9a.82 .82 0 0 0-1-.7v2.5l.4 .3h-1.6l.4-.3v-2.5a.81 .81 0 0 0-.9 .7z" fill-rule="evenodd"/>
<path d="M188.5 65.8a1.04 1.04 0 0 1 1.5 .9 1.04 1.04 0 0 1-1.5 .9l-.4-.7h.6v.4a.28 .28 0 0 0 .3 .3 .28 .28 0 0 0 .3-.2v-1.4a.3 .3 0 0 0-.4-.2 .3 .3 0 0 0-.2 .4v.7h-.6v-.6z" fill-rule="evenodd"/>
<path d="M190.2 65.7h.9v.3a.79 .79 0 0 1 1-.3 .79 .79 0 0 1 .4 1 .82 .82 0 0 1-.4 .9 .82 .82 0 0 1-1-.1v1l.3 .2h-1.2l.3-.2v-2.3h.6v1.1a.33 .33 0 0 0 .3 .3 .33 .33 0 0 0 .4-.3v-1.1a.33 .33 0 0 0-.4-.3 .33 .33 0 0 0-.3 .3h-.6l-.1-.4z" fill-rule="evenodd"/>
<path d="M195.2 64.7l1.2 2.7 .4 .3h-1.5l.4-.2-.3-.6h-1l-.2 .6 .4 .2h-1l.3-.3 .4-.7h1l-.4-1-.5 1h-.1z" fill-rule="evenodd"/>
<path d="M197.1 65.8a.87 .87 0 0 1 1-.1l.2-.1v.7a.68 .68 0 0 0-.8-.5v.3a1.25 1.25 0 0 1 .9 1.2 .81 .81 0 0 1-1.2 .4l-.2 .1v-.8a.74 .74 0 0 0 .9 .6v-.3a1.59 1.59 0 0 1-.9-1.2z" fill-rule="evenodd"/>
<path d="M198.9 65.8a.88 .88 0 0 1 1-.1l.1-.1v.7a.68 .68 0 0 0-.7-.5l-.1 .3a1.25 1.25 0 0 1 .9 1.2 .81 .81 0 0 1-1.2 .4l-.1 .1v-.8a.74 .74 0 0 0 .8 .6l.1-.3a1.58 1.58 0 0 1-.9-1.2z" fill-rule="evenodd"/>
<path d="M200.8 65.9a.83 .83 0 0 1 1-.2 .83 .83 0 0 1 .4 .9h-1.1a.58 .58 0 0 0 .3 .8 .58 .58 0 0 0 .7-.3 .85 .85 0 0 1-1 .7 .85 .85 0 0 1-.6-1.1v-.3l1.2 .1-.2-.7a.39 .39 0 0 0-.4 .2 .39 .39 0 0 0 0 .4h-.6z" fill-rule="evenodd"/>
<path d="M202.5 65.7h.8v.3a.64 .64 0 0 1 .6-.4 .64 .64 0 0 1 .6 .4 .66 .66 0 0 1 .8-.4 .66 .66 0 0 1 .4 .8l.1 1.1 .2 .2h-1.1l.2-.2v-1.3a.29 .29 0 0 0-.3-.3 .29 .29 0 0 0-.3 .3v1.3l.3 .2h-1.1l.2-.2v-1.3a.24 .24 0 0 0-.2-.3 .24 .24 0 0 0-.3 .1l-.1 .2v1.1l.2 .4h-1l.2-.1v-.3v-1.4z" fill-rule="evenodd"/>
<path d="M206.2 64.7h.8v1.2a.84 .84 0 0 1 1.1-.1 .84 .84 0 0 1 .3 1 .95 .95 0 0 1-.6 .9 .95 .95 0 0 1-1-.1l-.4 .2v-1.7h.6a1.69 1.69 0 0 0 .1 1.5h.4a1.54 1.54 0 0 0 0-1.7l-.5 .2h-.6v-1.2z" fill-rule="evenodd"/>
<path d="M208.7 64.7h.8l.1 2.8 .2 .2h-1.1l.2-.1v-.3v-2.3z" fill-rule="evenodd"/>
<path d="M209.9 65.7h1.1l-.2 .2 .4 1.1 .4-1.1-.2-.2h.7l-.3 .2-.7 1.9a1.02 1.02 0 0 1-.6 .9 .33 .33 0 0 1-.5-.2 .33 .33 0 0 1 .4-.4l.2 .4 .3-.7z" fill-rule="evenodd"/>
<path d="M214 65.1l.7-.4a3.2 3.2 0 0 0-.2 3.7l.2 .2a2.2 2.2 0 0 1-.7-3.5z" fill-rule="evenodd"/>
<path d="M215.2 64.9a1.69 1.69 0 0 1 1.5 0l.2-.2v1a.88 .88 0 0 0-1.4-.6l.1 .4a2.28 2.28 0 0 1 1.5 1.4 1.2 1.2 0 0 1-1.9 .7l-.2 .2v-1.1a.98 .98 0 0 0 1.5 .7 .62 .62 0 0 0-.6-.8 1.01 1.01 0 0 1-.8-1.5z" fill-rule="evenodd"/>
<path d="M217.8 65.9a.68 .68 0 0 1 .8-.3 .68 .68 0 0 1 .4 .7 .41 .41 0 0 1-.5 0 .41 .41 0 0 1-.1-.5h-.1a1.04 1.04 0 0 0 .3 1.6l.5-.2a.89 .89 0 0 1-1.2 .5 .89 .89 0 0 1-.5-1.2z" fill-rule="evenodd"/>
<path d="M219.6 65.9a.85 .85 0 0 1 1-.3 .85 .85 0 0 1 .5 .8l.1 1h.2a.42 .42 0 0 1-.4 .4 .42 .42 0 0 1-.5-.4 .6 .6 0 0 1-.5 .4 .6 .6 0 0 1-.5-.3v-.3h.6l.2 .2 .2-.1v-.7l-.4 .6h-.6l.3-.4 .7-.4v-.4a.27 .27 0 0 0-.4-.2 .27 .27 0 0 0 0 .4 .32 .32 0 0 1-.5 .2 .32 .32 0 0 1 0-.5z" fill-rule="evenodd"/>
<path d="M221.6 64.7h.9v2.8l.2 .2h-1.1l.2-.1v-.3v-2.3z" fill-rule="evenodd"/>
<path d="M223.2 65.9a.83 .83 0 0 1 1-.2 .83 .83 0 0 1 .5 .9h-1.2a.58 .58 0 0 0 .3 .8 .58 .58 0 0 0 .8-.3 .85 .85 0 0 1-1 .7 .85 .85 0 0 1-.7-1.1l.1-.3 1.1 .1-.1-.7a.39 .39 0 0 0-.5 .2 .39 .39 0 0 0 0 .4h-.5z" fill-rule="evenodd"/>
<path d="M226.2 65.2l1.2-.5v2.4a.46 .46 0 0 0 .4 .6h-1.6l.5-.2v-1.9l-.1-.4z" fill-rule="evenodd"/>
<path d="M229.9 65.2l1.2-.5v2.7l.1 .2 .4 .1h-1.6l.4-.2 .1-1.9-.1-.4z" fill-rule="evenodd"/>
<path d="M232 64.7a2.18 2.18 0 0 1 1.2 2 2.18 2.18 0 0 1-1.2 1.9 3.2 3.2 0 0 0 .1-3.7z" fill-rule="evenodd"/>
<circle cx="228.9" cy="67.4" r=".36"/>
<circle cx="228.9" cy="66" r=".36"/>
</g>
<g fill="#00007f">
<path d="M392.6 248.8l.3-.1v1.3h.2l-.6 .2-.4-.2v-.4h.2l.1 .4 .3-.1-.1-.7-.2 .1-.1 .3h-.2a.42 .42 0 0 1 .6-.4v-.4z" fill-rule="evenodd"/>
<path d="M393.3 248.8a.42 .42 0 0 1 .6 .1 .42 .42 0 0 1-.2 .6l-.4 .5 .7-.1-.1 .2h-.8a1.06 1.06 0 0 0 .6-1.1l-.3-.1-.3 .2z" fill-rule="evenodd"/>
<path d="M394.3 249.2l.5 .1 .1 .7 .1-.1-.1 .2-.2-.1-.3 .1-.2-.1v-.1l.3 .1 .2-.1v-.3l-.5 .3 .5-.4-.2-.3-.2 .3z" fill-rule="evenodd"/>
<path d="M395.3 248.9l.3-.2 .1 1.3 .1 .1h-.5l.2-.1v-.9v-.2z" fill-rule="evenodd"/>
<path d="M396.5 248.9l.5-.2a.71 .71 0 0 0-.6 .6 .43 .43 0 0 1 .6 .3 .43 .43 0 0 1-.4 .6 .43 .43 0 0 1-.4-.6h.2a.31 .31 0 0 0 .1 .4 .31 .31 0 0 0 .4 0 .31 .31 0 0 0-.1-.5v-.1a.24 .24 0 0 0-.3 0 .24 .24 0 0 0-.1 .2h-.2v-.1z" fill-rule="evenodd"/>
<path d="M397.5 248.8l.3-.1 .2 .1v.1l-.3-.2-.1 .1v.4h.2h-.2v.8l.2 .1h-.6l.2-.1v-.8h-.2h.2z" fill-rule="evenodd"/>
<path d="M398.1 248.8a.57 .57 0 0 1 .7 .3 .57 .57 0 0 1-.2 .7l-.3 .3h-.4l.4-.2 .3-.4a.39 .39 0 0 1-.5 0 .39 .39 0 0 1-.2-.4h.2l.1 .3a.28 .28 0 0 0 .4 0 .28 .28 0 0 0 0-.4l-.2-.2a.24 .24 0 0 0-.2 0 .24 .24 0 0 0-.1 .3h-.2z" fill-rule="evenodd"/>
</g>
<path d="M390.5 243v10.5" fill="none" stroke="#000" stroke-width=".18"/>
<g fill="#00f">
<path d="M392.3 244.3l.3-.2h.5l.3 .3 .1 .1-.2 .1a.58 .58 0 0 0-.8-.2 .58 .58 0 0 0-.2 .8 .58 .58 0 0 0 .8 .2l.2-.1v-.3h-.4v-.1h.6v.5a.81 .81 0 0 1-1.2 .1 .81 .81 0 0 1 0-1.2z" fill-rule="evenodd"/>
<path d="M393.8 244.1h.2v.2h-.2z" fill-rule="evenodd"/>
<path d="M393.8 244.5h.2v1.1h-.2z" fill-rule="evenodd"/>
<path d="M394.3 244.3l.2-.1v.3h.1v.2h-.1v.6l.2 .3a.27 .27 0 0 1-.3 0 .27 .27 0 0 1-.1-.3v-.6h-.2z" fill-rule="evenodd"/>
<path d="M395.4 244.1h.2v.6h.8v-.6h.2v1.5h-.2v-.7h-.8v.7h-.2z" fill-rule="evenodd"/>
<path d="M397 244.6l.1-.1a.47 .47 0 0 1 .6 .1 .47 .47 0 0 1 .1 .6l.1 .4h-.2l-.1-.1-.5 .1-.2-.1v-.2l.3 .2h.3l.1-.4-.7 .2a.57 .57 0 0 1 .7-.4 .28 .28 0 0 0-.2-.2 .28 .28 0 0 0-.3 .2l-.2-.1z" fill-rule="evenodd"/>
<path d="M398.1 244.6l.3-.1a.39 .39 0 0 1 .5 .3h-.2a.21 .21 0 0 0-.3-.2 .21 .21 0 0 0-.1 .3 .43 .43 0 0 1 .5 .1 .43 .43 0 0 1 .1 .4l-.3 .2h-.3l-.3-.3h.2a.24 .24 0 0 0 .3 .3 .24 .24 0 0 0 .1-.4 .43 .43 0 0 1-.5-.5z" fill-rule="evenodd"/>
<path d="M399.1 244.1h.2v.6l.3-.2 .4 .1v1h-.2v-.7a.27 .27 0 0 0-.3-.2 .27 .27 0 0 0-.2 .3v.6h-.2z" fill-rule="evenodd"/>
<path d="M400.4 244.5h.2v.2h-.2z" fill-rule="evenodd"/>
<path d="M400.4 245.4h.2v.2h-.2z" fill-rule="evenodd"/>
</g>
<use href="#words"/>
</svg>
